VERSION 5.8 ;
BUSBITCHARS "[]" ;
DIVIDERCHAR "/" ;
UNITS
    DATABASE MICRONS 1000 ;
END UNITS

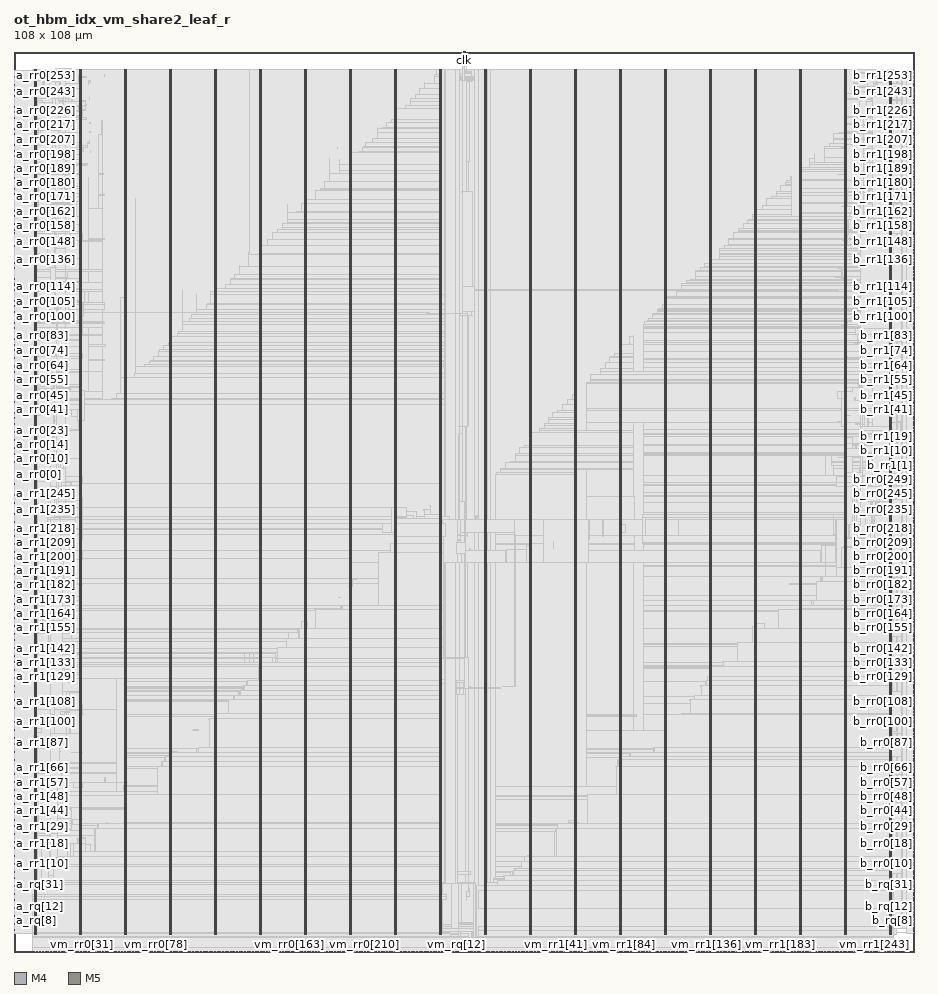
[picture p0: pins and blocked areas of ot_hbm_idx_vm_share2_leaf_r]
MACRO ot_hbm_idx_vm_share2_leaf_r
  FOREIGN ot_hbm_idx_vm_share2_leaf_r 0 0 ;
  CLASS BLOCK ;
  SIZE 108 BY 108 ;
  PIN a_rq[0]
    DIRECTION INPUT ;
    USE SIGNAL ;
    PORT
      LAYER M4 ;
        RECT  0 2.256 0.084 2.28 ;
    END
  END a_rq[0]
  PIN a_rq[10]
    DIRECTION INPUT ;
    USE SIGNAL ;
    PORT
      LAYER M4 ;
        RECT  0 4.128 0.084 4.152 ;
    END
  END a_rq[10]
  PIN a_rq[11]
    DIRECTION INPUT ;
    USE SIGNAL ;
    PORT
      LAYER M4 ;
        RECT  0 4.32 0.084 4.344 ;
    END
  END a_rq[11]
  PIN a_rq[12]
    DIRECTION INPUT ;
    USE SIGNAL ;
    PORT
      LAYER M4 ;
        RECT  0 4.512 0.084 4.536 ;
    END
  END a_rq[12]
  PIN a_rq[13]
    DIRECTION INPUT ;
    USE SIGNAL ;
    PORT
      LAYER M4 ;
        RECT  0 4.704 0.084 4.728 ;
    END
  END a_rq[13]
  PIN a_rq[14]
    DIRECTION INPUT ;
    USE SIGNAL ;
    PORT
      LAYER M4 ;
        RECT  0 4.896 0.084 4.92 ;
    END
  END a_rq[14]
  PIN a_rq[15]
    DIRECTION INPUT ;
    USE SIGNAL ;
    PORT
      LAYER M4 ;
        RECT  0 5.088 0.084 5.112 ;
    END
  END a_rq[15]
  PIN a_rq[16]
    DIRECTION INPUT ;
    USE SIGNAL ;
    PORT
      LAYER M4 ;
        RECT  0 5.28 0.084 5.304 ;
    END
  END a_rq[16]
  PIN a_rq[17]
    DIRECTION INPUT ;
    USE SIGNAL ;
    PORT
      LAYER M4 ;
        RECT  0 5.472 0.084 5.496 ;
    END
  END a_rq[17]
  PIN a_rq[18]
    DIRECTION INPUT ;
    USE SIGNAL ;
    PORT
      LAYER M4 ;
        RECT  0 5.664 0.084 5.688 ;
    END
  END a_rq[18]
  PIN a_rq[19]
    DIRECTION INPUT ;
    USE SIGNAL ;
    PORT
      LAYER M4 ;
        RECT  0 5.856 0.084 5.88 ;
    END
  END a_rq[19]
  PIN a_rq[1]
    DIRECTION INPUT ;
    USE SIGNAL ;
    PORT
      LAYER M4 ;
        RECT  0 2.448 0.084 2.472 ;
    END
  END a_rq[1]
  PIN a_rq[20]
    DIRECTION INPUT ;
    USE SIGNAL ;
    PORT
      LAYER M4 ;
        RECT  0 6.048 0.084 6.072 ;
    END
  END a_rq[20]
  PIN a_rq[21]
    DIRECTION INPUT ;
    USE SIGNAL ;
    PORT
      LAYER M4 ;
        RECT  0 6.24 0.084 6.264 ;
    END
  END a_rq[21]
  PIN a_rq[22]
    DIRECTION INPUT ;
    USE SIGNAL ;
    PORT
      LAYER M4 ;
        RECT  0 6.384 0.084 6.408 ;
    END
  END a_rq[22]
  PIN a_rq[23]
    DIRECTION INPUT ;
    USE SIGNAL ;
    PORT
      LAYER M4 ;
        RECT  0 6.576 0.084 6.6 ;
    END
  END a_rq[23]
  PIN a_rq[24]
    DIRECTION INPUT ;
    USE SIGNAL ;
    PORT
      LAYER M4 ;
        RECT  0 6.768 0.084 6.792 ;
    END
  END a_rq[24]
  PIN a_rq[25]
    DIRECTION INPUT ;
    USE SIGNAL ;
    PORT
      LAYER M4 ;
        RECT  0 6.96 0.084 6.984 ;
    END
  END a_rq[25]
  PIN a_rq[26]
    DIRECTION INPUT ;
    USE SIGNAL ;
    PORT
      LAYER M4 ;
        RECT  0 7.152 0.084 7.176 ;
    END
  END a_rq[26]
  PIN a_rq[27]
    DIRECTION INPUT ;
    USE SIGNAL ;
    PORT
      LAYER M4 ;
        RECT  0 7.344 0.084 7.368 ;
    END
  END a_rq[27]
  PIN a_rq[28]
    DIRECTION INPUT ;
    USE SIGNAL ;
    PORT
      LAYER M4 ;
        RECT  0 7.536 0.084 7.56 ;
    END
  END a_rq[28]
  PIN a_rq[29]
    DIRECTION INPUT ;
    USE SIGNAL ;
    PORT
      LAYER M4 ;
        RECT  0 7.728 0.084 7.752 ;
    END
  END a_rq[29]
  PIN a_rq[2]
    DIRECTION INPUT ;
    USE SIGNAL ;
    PORT
      LAYER M4 ;
        RECT  0 2.64 0.084 2.664 ;
    END
  END a_rq[2]
  PIN a_rq[30]
    DIRECTION INPUT ;
    USE SIGNAL ;
    PORT
      LAYER M4 ;
        RECT  0 7.92 0.084 7.944 ;
    END
  END a_rq[30]
  PIN a_rq[31]
    DIRECTION INPUT ;
    USE SIGNAL ;
    PORT
      LAYER M4 ;
        RECT  0 8.112 0.084 8.136 ;
    END
  END a_rq[31]
  PIN a_rq[32]
    DIRECTION INPUT ;
    USE SIGNAL ;
    PORT
      LAYER M4 ;
        RECT  0 8.304 0.084 8.328 ;
    END
  END a_rq[32]
  PIN a_rq[33]
    DIRECTION INPUT ;
    USE SIGNAL ;
    PORT
      LAYER M4 ;
        RECT  0 8.496 0.084 8.52 ;
    END
  END a_rq[33]
  PIN a_rq[3]
    DIRECTION INPUT ;
    USE SIGNAL ;
    PORT
      LAYER M4 ;
        RECT  0 2.832 0.084 2.856 ;
    END
  END a_rq[3]
  PIN a_rq[4]
    DIRECTION INPUT ;
    USE SIGNAL ;
    PORT
      LAYER M4 ;
        RECT  0 2.976 0.084 3 ;
    END
  END a_rq[4]
  PIN a_rq[5]
    DIRECTION INPUT ;
    USE SIGNAL ;
    PORT
      LAYER M4 ;
        RECT  0 3.168 0.084 3.192 ;
    END
  END a_rq[5]
  PIN a_rq[6]
    DIRECTION INPUT ;
    USE SIGNAL ;
    PORT
      LAYER M4 ;
        RECT  0 3.36 0.084 3.384 ;
    END
  END a_rq[6]
  PIN a_rq[7]
    DIRECTION INPUT ;
    USE SIGNAL ;
    PORT
      LAYER M4 ;
        RECT  0 3.552 0.084 3.576 ;
    END
  END a_rq[7]
  PIN a_rq[8]
    DIRECTION INPUT ;
    USE SIGNAL ;
    PORT
      LAYER M4 ;
        RECT  0 3.744 0.084 3.768 ;
    END
  END a_rq[8]
  PIN a_rq[9]
    DIRECTION INPUT ;
    USE SIGNAL ;
    PORT
      LAYER M4 ;
        RECT  0 3.936 0.084 3.96 ;
    END
  END a_rq[9]
  PIN a_rr0[0]
    DIRECTION OUTPUT ;
    USE SIGNAL ;
    PORT
      LAYER M4 ;
        RECT  0 57.264 0.084 57.288 ;
    END
  END a_rr0[0]
  PIN a_rr0[100]
    DIRECTION OUTPUT ;
    USE SIGNAL ;
    PORT
      LAYER M4 ;
        RECT  0 76.224 0.084 76.248 ;
    END
  END a_rr0[100]
  PIN a_rr0[101]
    DIRECTION OUTPUT ;
    USE SIGNAL ;
    PORT
      LAYER M4 ;
        RECT  0 76.416 0.084 76.44 ;
    END
  END a_rr0[101]
  PIN a_rr0[102]
    DIRECTION OUTPUT ;
    USE SIGNAL ;
    PORT
      LAYER M4 ;
        RECT  0 76.608 0.084 76.632 ;
    END
  END a_rr0[102]
  PIN a_rr0[103]
    DIRECTION OUTPUT ;
    USE SIGNAL ;
    PORT
      LAYER M4 ;
        RECT  0 76.8 0.084 76.824 ;
    END
  END a_rr0[103]
  PIN a_rr0[104]
    DIRECTION OUTPUT ;
    USE SIGNAL ;
    PORT
      LAYER M4 ;
        RECT  0 76.944 0.084 76.968 ;
    END
  END a_rr0[104]
  PIN a_rr0[105]
    DIRECTION OUTPUT ;
    USE SIGNAL ;
    PORT
      LAYER M4 ;
        RECT  0 77.136 0.084 77.16 ;
    END
  END a_rr0[105]
  PIN a_rr0[106]
    DIRECTION OUTPUT ;
    USE SIGNAL ;
    PORT
      LAYER M4 ;
        RECT  0 77.328 0.084 77.352 ;
    END
  END a_rr0[106]
  PIN a_rr0[107]
    DIRECTION OUTPUT ;
    USE SIGNAL ;
    PORT
      LAYER M4 ;
        RECT  0 77.52 0.084 77.544 ;
    END
  END a_rr0[107]
  PIN a_rr0[108]
    DIRECTION OUTPUT ;
    USE SIGNAL ;
    PORT
      LAYER M4 ;
        RECT  0 77.712 0.084 77.736 ;
    END
  END a_rr0[108]
  PIN a_rr0[109]
    DIRECTION OUTPUT ;
    USE SIGNAL ;
    PORT
      LAYER M4 ;
        RECT  0 77.904 0.084 77.928 ;
    END
  END a_rr0[109]
  PIN a_rr0[10]
    DIRECTION OUTPUT ;
    USE SIGNAL ;
    PORT
      LAYER M4 ;
        RECT  0 59.184 0.084 59.208 ;
    END
  END a_rr0[10]
  PIN a_rr0[110]
    DIRECTION OUTPUT ;
    USE SIGNAL ;
    PORT
      LAYER M4 ;
        RECT  0 78.096 0.084 78.12 ;
    END
  END a_rr0[110]
  PIN a_rr0[111]
    DIRECTION OUTPUT ;
    USE SIGNAL ;
    PORT
      LAYER M4 ;
        RECT  0 78.288 0.084 78.312 ;
    END
  END a_rr0[111]
  PIN a_rr0[112]
    DIRECTION OUTPUT ;
    USE SIGNAL ;
    PORT
      LAYER M4 ;
        RECT  0 78.48 0.084 78.504 ;
    END
  END a_rr0[112]
  PIN a_rr0[113]
    DIRECTION OUTPUT ;
    USE SIGNAL ;
    PORT
      LAYER M4 ;
        RECT  0 78.672 0.084 78.696 ;
    END
  END a_rr0[113]
  PIN a_rr0[114]
    DIRECTION OUTPUT ;
    USE SIGNAL ;
    PORT
      LAYER M4 ;
        RECT  0 78.864 0.084 78.888 ;
    END
  END a_rr0[114]
  PIN a_rr0[115]
    DIRECTION OUTPUT ;
    USE SIGNAL ;
    PORT
      LAYER M4 ;
        RECT  0 79.056 0.084 79.08 ;
    END
  END a_rr0[115]
  PIN a_rr0[116]
    DIRECTION OUTPUT ;
    USE SIGNAL ;
    PORT
      LAYER M4 ;
        RECT  0 79.248 0.084 79.272 ;
    END
  END a_rr0[116]
  PIN a_rr0[117]
    DIRECTION OUTPUT ;
    USE SIGNAL ;
    PORT
      LAYER M4 ;
        RECT  0 79.44 0.084 79.464 ;
    END
  END a_rr0[117]
  PIN a_rr0[118]
    DIRECTION OUTPUT ;
    USE SIGNAL ;
    PORT
      LAYER M4 ;
        RECT  0 79.632 0.084 79.656 ;
    END
  END a_rr0[118]
  PIN a_rr0[119]
    DIRECTION OUTPUT ;
    USE SIGNAL ;
    PORT
      LAYER M4 ;
        RECT  0 79.824 0.084 79.848 ;
    END
  END a_rr0[119]
  PIN a_rr0[11]
    DIRECTION OUTPUT ;
    USE SIGNAL ;
    PORT
      LAYER M4 ;
        RECT  0 59.376 0.084 59.4 ;
    END
  END a_rr0[11]
  PIN a_rr0[120]
    DIRECTION OUTPUT ;
    USE SIGNAL ;
    PORT
      LAYER M4 ;
        RECT  0 80.016 0.084 80.04 ;
    END
  END a_rr0[120]
  PIN a_rr0[121]
    DIRECTION OUTPUT ;
    USE SIGNAL ;
    PORT
      LAYER M4 ;
        RECT  0 80.16 0.084 80.184 ;
    END
  END a_rr0[121]
  PIN a_rr0[122]
    DIRECTION OUTPUT ;
    USE SIGNAL ;
    PORT
      LAYER M4 ;
        RECT  0 80.352 0.084 80.376 ;
    END
  END a_rr0[122]
  PIN a_rr0[123]
    DIRECTION OUTPUT ;
    USE SIGNAL ;
    PORT
      LAYER M4 ;
        RECT  0 80.544 0.084 80.568 ;
    END
  END a_rr0[123]
  PIN a_rr0[124]
    DIRECTION OUTPUT ;
    USE SIGNAL ;
    PORT
      LAYER M4 ;
        RECT  0 80.736 0.084 80.76 ;
    END
  END a_rr0[124]
  PIN a_rr0[125]
    DIRECTION OUTPUT ;
    USE SIGNAL ;
    PORT
      LAYER M4 ;
        RECT  0 80.928 0.084 80.952 ;
    END
  END a_rr0[125]
  PIN a_rr0[126]
    DIRECTION OUTPUT ;
    USE SIGNAL ;
    PORT
      LAYER M4 ;
        RECT  0 81.12 0.084 81.144 ;
    END
  END a_rr0[126]
  PIN a_rr0[127]
    DIRECTION OUTPUT ;
    USE SIGNAL ;
    PORT
      LAYER M4 ;
        RECT  0 81.312 0.084 81.336 ;
    END
  END a_rr0[127]
  PIN a_rr0[128]
    DIRECTION OUTPUT ;
    USE SIGNAL ;
    PORT
      LAYER M4 ;
        RECT  0 81.504 0.084 81.528 ;
    END
  END a_rr0[128]
  PIN a_rr0[129]
    DIRECTION OUTPUT ;
    USE SIGNAL ;
    PORT
      LAYER M4 ;
        RECT  0 81.696 0.084 81.72 ;
    END
  END a_rr0[129]
  PIN a_rr0[12]
    DIRECTION OUTPUT ;
    USE SIGNAL ;
    PORT
      LAYER M4 ;
        RECT  0 59.568 0.084 59.592 ;
    END
  END a_rr0[12]
  PIN a_rr0[130]
    DIRECTION OUTPUT ;
    USE SIGNAL ;
    PORT
      LAYER M4 ;
        RECT  0 81.888 0.084 81.912 ;
    END
  END a_rr0[130]
  PIN a_rr0[131]
    DIRECTION OUTPUT ;
    USE SIGNAL ;
    PORT
      LAYER M4 ;
        RECT  0 82.08 0.084 82.104 ;
    END
  END a_rr0[131]
  PIN a_rr0[132]
    DIRECTION OUTPUT ;
    USE SIGNAL ;
    PORT
      LAYER M4 ;
        RECT  0 82.272 0.084 82.296 ;
    END
  END a_rr0[132]
  PIN a_rr0[133]
    DIRECTION OUTPUT ;
    USE SIGNAL ;
    PORT
      LAYER M4 ;
        RECT  0 82.464 0.084 82.488 ;
    END
  END a_rr0[133]
  PIN a_rr0[134]
    DIRECTION OUTPUT ;
    USE SIGNAL ;
    PORT
      LAYER M4 ;
        RECT  0 82.656 0.084 82.68 ;
    END
  END a_rr0[134]
  PIN a_rr0[135]
    DIRECTION OUTPUT ;
    USE SIGNAL ;
    PORT
      LAYER M4 ;
        RECT  0 82.848 0.084 82.872 ;
    END
  END a_rr0[135]
  PIN a_rr0[136]
    DIRECTION OUTPUT ;
    USE SIGNAL ;
    PORT
      LAYER M4 ;
        RECT  0 83.04 0.084 83.064 ;
    END
  END a_rr0[136]
  PIN a_rr0[137]
    DIRECTION OUTPUT ;
    USE SIGNAL ;
    PORT
      LAYER M4 ;
        RECT  0 83.232 0.084 83.256 ;
    END
  END a_rr0[137]
  PIN a_rr0[138]
    DIRECTION OUTPUT ;
    USE SIGNAL ;
    PORT
      LAYER M4 ;
        RECT  0 83.424 0.084 83.448 ;
    END
  END a_rr0[138]
  PIN a_rr0[139]
    DIRECTION OUTPUT ;
    USE SIGNAL ;
    PORT
      LAYER M4 ;
        RECT  0 83.568 0.084 83.592 ;
    END
  END a_rr0[139]
  PIN a_rr0[13]
    DIRECTION OUTPUT ;
    USE SIGNAL ;
    PORT
      LAYER M4 ;
        RECT  0 59.76 0.084 59.784 ;
    END
  END a_rr0[13]
  PIN a_rr0[140]
    DIRECTION OUTPUT ;
    USE SIGNAL ;
    PORT
      LAYER M4 ;
        RECT  0 83.76 0.084 83.784 ;
    END
  END a_rr0[140]
  PIN a_rr0[141]
    DIRECTION OUTPUT ;
    USE SIGNAL ;
    PORT
      LAYER M4 ;
        RECT  0 83.952 0.084 83.976 ;
    END
  END a_rr0[141]
  PIN a_rr0[142]
    DIRECTION OUTPUT ;
    USE SIGNAL ;
    PORT
      LAYER M4 ;
        RECT  0 84.144 0.084 84.168 ;
    END
  END a_rr0[142]
  PIN a_rr0[143]
    DIRECTION OUTPUT ;
    USE SIGNAL ;
    PORT
      LAYER M4 ;
        RECT  0 84.336 0.084 84.36 ;
    END
  END a_rr0[143]
  PIN a_rr0[144]
    DIRECTION OUTPUT ;
    USE SIGNAL ;
    PORT
      LAYER M4 ;
        RECT  0 84.528 0.084 84.552 ;
    END
  END a_rr0[144]
  PIN a_rr0[145]
    DIRECTION OUTPUT ;
    USE SIGNAL ;
    PORT
      LAYER M4 ;
        RECT  0 84.72 0.084 84.744 ;
    END
  END a_rr0[145]
  PIN a_rr0[146]
    DIRECTION OUTPUT ;
    USE SIGNAL ;
    PORT
      LAYER M4 ;
        RECT  0 84.912 0.084 84.936 ;
    END
  END a_rr0[146]
  PIN a_rr0[147]
    DIRECTION OUTPUT ;
    USE SIGNAL ;
    PORT
      LAYER M4 ;
        RECT  0 85.104 0.084 85.128 ;
    END
  END a_rr0[147]
  PIN a_rr0[148]
    DIRECTION OUTPUT ;
    USE SIGNAL ;
    PORT
      LAYER M4 ;
        RECT  0 85.296 0.084 85.32 ;
    END
  END a_rr0[148]
  PIN a_rr0[149]
    DIRECTION OUTPUT ;
    USE SIGNAL ;
    PORT
      LAYER M4 ;
        RECT  0 85.488 0.084 85.512 ;
    END
  END a_rr0[149]
  PIN a_rr0[14]
    DIRECTION OUTPUT ;
    USE SIGNAL ;
    PORT
      LAYER M4 ;
        RECT  0 59.952 0.084 59.976 ;
    END
  END a_rr0[14]
  PIN a_rr0[150]
    DIRECTION OUTPUT ;
    USE SIGNAL ;
    PORT
      LAYER M4 ;
        RECT  0 85.68 0.084 85.704 ;
    END
  END a_rr0[150]
  PIN a_rr0[151]
    DIRECTION OUTPUT ;
    USE SIGNAL ;
    PORT
      LAYER M4 ;
        RECT  0 85.872 0.084 85.896 ;
    END
  END a_rr0[151]
  PIN a_rr0[152]
    DIRECTION OUTPUT ;
    USE SIGNAL ;
    PORT
      LAYER M4 ;
        RECT  0 86.064 0.084 86.088 ;
    END
  END a_rr0[152]
  PIN a_rr0[153]
    DIRECTION OUTPUT ;
    USE SIGNAL ;
    PORT
      LAYER M4 ;
        RECT  0 86.256 0.084 86.28 ;
    END
  END a_rr0[153]
  PIN a_rr0[154]
    DIRECTION OUTPUT ;
    USE SIGNAL ;
    PORT
      LAYER M4 ;
        RECT  0 86.448 0.084 86.472 ;
    END
  END a_rr0[154]
  PIN a_rr0[155]
    DIRECTION OUTPUT ;
    USE SIGNAL ;
    PORT
      LAYER M4 ;
        RECT  0 86.64 0.084 86.664 ;
    END
  END a_rr0[155]
  PIN a_rr0[156]
    DIRECTION OUTPUT ;
    USE SIGNAL ;
    PORT
      LAYER M4 ;
        RECT  0 86.784 0.084 86.808 ;
    END
  END a_rr0[156]
  PIN a_rr0[157]
    DIRECTION OUTPUT ;
    USE SIGNAL ;
    PORT
      LAYER M4 ;
        RECT  0 86.976 0.084 87 ;
    END
  END a_rr0[157]
  PIN a_rr0[158]
    DIRECTION OUTPUT ;
    USE SIGNAL ;
    PORT
      LAYER M4 ;
        RECT  0 87.168 0.084 87.192 ;
    END
  END a_rr0[158]
  PIN a_rr0[159]
    DIRECTION OUTPUT ;
    USE SIGNAL ;
    PORT
      LAYER M4 ;
        RECT  0 87.36 0.084 87.384 ;
    END
  END a_rr0[159]
  PIN a_rr0[15]
    DIRECTION OUTPUT ;
    USE SIGNAL ;
    PORT
      LAYER M4 ;
        RECT  0 60.144 0.084 60.168 ;
    END
  END a_rr0[15]
  PIN a_rr0[160]
    DIRECTION OUTPUT ;
    USE SIGNAL ;
    PORT
      LAYER M4 ;
        RECT  0 87.552 0.084 87.576 ;
    END
  END a_rr0[160]
  PIN a_rr0[161]
    DIRECTION OUTPUT ;
    USE SIGNAL ;
    PORT
      LAYER M4 ;
        RECT  0 87.744 0.084 87.768 ;
    END
  END a_rr0[161]
  PIN a_rr0[162]
    DIRECTION OUTPUT ;
    USE SIGNAL ;
    PORT
      LAYER M4 ;
        RECT  0 87.936 0.084 87.96 ;
    END
  END a_rr0[162]
  PIN a_rr0[163]
    DIRECTION OUTPUT ;
    USE SIGNAL ;
    PORT
      LAYER M4 ;
        RECT  0 88.128 0.084 88.152 ;
    END
  END a_rr0[163]
  PIN a_rr0[164]
    DIRECTION OUTPUT ;
    USE SIGNAL ;
    PORT
      LAYER M4 ;
        RECT  0 88.32 0.084 88.344 ;
    END
  END a_rr0[164]
  PIN a_rr0[165]
    DIRECTION OUTPUT ;
    USE SIGNAL ;
    PORT
      LAYER M4 ;
        RECT  0 88.512 0.084 88.536 ;
    END
  END a_rr0[165]
  PIN a_rr0[166]
    DIRECTION OUTPUT ;
    USE SIGNAL ;
    PORT
      LAYER M4 ;
        RECT  0 88.704 0.084 88.728 ;
    END
  END a_rr0[166]
  PIN a_rr0[167]
    DIRECTION OUTPUT ;
    USE SIGNAL ;
    PORT
      LAYER M4 ;
        RECT  0 88.896 0.084 88.92 ;
    END
  END a_rr0[167]
  PIN a_rr0[168]
    DIRECTION OUTPUT ;
    USE SIGNAL ;
    PORT
      LAYER M4 ;
        RECT  0 89.088 0.084 89.112 ;
    END
  END a_rr0[168]
  PIN a_rr0[169]
    DIRECTION OUTPUT ;
    USE SIGNAL ;
    PORT
      LAYER M4 ;
        RECT  0 89.28 0.084 89.304 ;
    END
  END a_rr0[169]
  PIN a_rr0[16]
    DIRECTION OUTPUT ;
    USE SIGNAL ;
    PORT
      LAYER M4 ;
        RECT  0 60.288 0.084 60.312 ;
    END
  END a_rr0[16]
  PIN a_rr0[170]
    DIRECTION OUTPUT ;
    USE SIGNAL ;
    PORT
      LAYER M4 ;
        RECT  0 89.472 0.084 89.496 ;
    END
  END a_rr0[170]
  PIN a_rr0[171]
    DIRECTION OUTPUT ;
    USE SIGNAL ;
    PORT
      LAYER M4 ;
        RECT  0 89.664 0.084 89.688 ;
    END
  END a_rr0[171]
  PIN a_rr0[172]
    DIRECTION OUTPUT ;
    USE SIGNAL ;
    PORT
      LAYER M4 ;
        RECT  0 89.856 0.084 89.88 ;
    END
  END a_rr0[172]
  PIN a_rr0[173]
    DIRECTION OUTPUT ;
    USE SIGNAL ;
    PORT
      LAYER M4 ;
        RECT  0 90.048 0.084 90.072 ;
    END
  END a_rr0[173]
  PIN a_rr0[174]
    DIRECTION OUTPUT ;
    USE SIGNAL ;
    PORT
      LAYER M4 ;
        RECT  0 90.192 0.084 90.216 ;
    END
  END a_rr0[174]
  PIN a_rr0[175]
    DIRECTION OUTPUT ;
    USE SIGNAL ;
    PORT
      LAYER M4 ;
        RECT  0 90.384 0.084 90.408 ;
    END
  END a_rr0[175]
  PIN a_rr0[176]
    DIRECTION OUTPUT ;
    USE SIGNAL ;
    PORT
      LAYER M4 ;
        RECT  0 90.576 0.084 90.6 ;
    END
  END a_rr0[176]
  PIN a_rr0[177]
    DIRECTION OUTPUT ;
    USE SIGNAL ;
    PORT
      LAYER M4 ;
        RECT  0 90.768 0.084 90.792 ;
    END
  END a_rr0[177]
  PIN a_rr0[178]
    DIRECTION OUTPUT ;
    USE SIGNAL ;
    PORT
      LAYER M4 ;
        RECT  0 90.96 0.084 90.984 ;
    END
  END a_rr0[178]
  PIN a_rr0[179]
    DIRECTION OUTPUT ;
    USE SIGNAL ;
    PORT
      LAYER M4 ;
        RECT  0 91.152 0.084 91.176 ;
    END
  END a_rr0[179]
  PIN a_rr0[17]
    DIRECTION OUTPUT ;
    USE SIGNAL ;
    PORT
      LAYER M4 ;
        RECT  0 60.48 0.084 60.504 ;
    END
  END a_rr0[17]
  PIN a_rr0[180]
    DIRECTION OUTPUT ;
    USE SIGNAL ;
    PORT
      LAYER M4 ;
        RECT  0 91.344 0.084 91.368 ;
    END
  END a_rr0[180]
  PIN a_rr0[181]
    DIRECTION OUTPUT ;
    USE SIGNAL ;
    PORT
      LAYER M4 ;
        RECT  0 91.536 0.084 91.56 ;
    END
  END a_rr0[181]
  PIN a_rr0[182]
    DIRECTION OUTPUT ;
    USE SIGNAL ;
    PORT
      LAYER M4 ;
        RECT  0 91.728 0.084 91.752 ;
    END
  END a_rr0[182]
  PIN a_rr0[183]
    DIRECTION OUTPUT ;
    USE SIGNAL ;
    PORT
      LAYER M4 ;
        RECT  0 91.92 0.084 91.944 ;
    END
  END a_rr0[183]
  PIN a_rr0[184]
    DIRECTION OUTPUT ;
    USE SIGNAL ;
    PORT
      LAYER M4 ;
        RECT  0 92.112 0.084 92.136 ;
    END
  END a_rr0[184]
  PIN a_rr0[185]
    DIRECTION OUTPUT ;
    USE SIGNAL ;
    PORT
      LAYER M4 ;
        RECT  0 92.304 0.084 92.328 ;
    END
  END a_rr0[185]
  PIN a_rr0[186]
    DIRECTION OUTPUT ;
    USE SIGNAL ;
    PORT
      LAYER M4 ;
        RECT  0 92.496 0.084 92.52 ;
    END
  END a_rr0[186]
  PIN a_rr0[187]
    DIRECTION OUTPUT ;
    USE SIGNAL ;
    PORT
      LAYER M4 ;
        RECT  0 92.688 0.084 92.712 ;
    END
  END a_rr0[187]
  PIN a_rr0[188]
    DIRECTION OUTPUT ;
    USE SIGNAL ;
    PORT
      LAYER M4 ;
        RECT  0 92.88 0.084 92.904 ;
    END
  END a_rr0[188]
  PIN a_rr0[189]
    DIRECTION OUTPUT ;
    USE SIGNAL ;
    PORT
      LAYER M4 ;
        RECT  0 93.072 0.084 93.096 ;
    END
  END a_rr0[189]
  PIN a_rr0[18]
    DIRECTION OUTPUT ;
    USE SIGNAL ;
    PORT
      LAYER M4 ;
        RECT  0 60.672 0.084 60.696 ;
    END
  END a_rr0[18]
  PIN a_rr0[190]
    DIRECTION OUTPUT ;
    USE SIGNAL ;
    PORT
      LAYER M4 ;
        RECT  0 93.264 0.084 93.288 ;
    END
  END a_rr0[190]
  PIN a_rr0[191]
    DIRECTION OUTPUT ;
    USE SIGNAL ;
    PORT
      LAYER M4 ;
        RECT  0 93.408 0.084 93.432 ;
    END
  END a_rr0[191]
  PIN a_rr0[192]
    DIRECTION OUTPUT ;
    USE SIGNAL ;
    PORT
      LAYER M4 ;
        RECT  0 93.6 0.084 93.624 ;
    END
  END a_rr0[192]
  PIN a_rr0[193]
    DIRECTION OUTPUT ;
    USE SIGNAL ;
    PORT
      LAYER M4 ;
        RECT  0 93.792 0.084 93.816 ;
    END
  END a_rr0[193]
  PIN a_rr0[194]
    DIRECTION OUTPUT ;
    USE SIGNAL ;
    PORT
      LAYER M4 ;
        RECT  0 93.984 0.084 94.008 ;
    END
  END a_rr0[194]
  PIN a_rr0[195]
    DIRECTION OUTPUT ;
    USE SIGNAL ;
    PORT
      LAYER M4 ;
        RECT  0 94.176 0.084 94.2 ;
    END
  END a_rr0[195]
  PIN a_rr0[196]
    DIRECTION OUTPUT ;
    USE SIGNAL ;
    PORT
      LAYER M4 ;
        RECT  0 94.368 0.084 94.392 ;
    END
  END a_rr0[196]
  PIN a_rr0[197]
    DIRECTION OUTPUT ;
    USE SIGNAL ;
    PORT
      LAYER M4 ;
        RECT  0 94.56 0.084 94.584 ;
    END
  END a_rr0[197]
  PIN a_rr0[198]
    DIRECTION OUTPUT ;
    USE SIGNAL ;
    PORT
      LAYER M4 ;
        RECT  0 94.752 0.084 94.776 ;
    END
  END a_rr0[198]
  PIN a_rr0[199]
    DIRECTION OUTPUT ;
    USE SIGNAL ;
    PORT
      LAYER M4 ;
        RECT  0 94.944 0.084 94.968 ;
    END
  END a_rr0[199]
  PIN a_rr0[19]
    DIRECTION OUTPUT ;
    USE SIGNAL ;
    PORT
      LAYER M4 ;
        RECT  0 60.864 0.084 60.888 ;
    END
  END a_rr0[19]
  PIN a_rr0[1]
    DIRECTION OUTPUT ;
    USE SIGNAL ;
    PORT
      LAYER M4 ;
        RECT  0 57.456 0.084 57.48 ;
    END
  END a_rr0[1]
  PIN a_rr0[200]
    DIRECTION OUTPUT ;
    USE SIGNAL ;
    PORT
      LAYER M4 ;
        RECT  0 95.136 0.084 95.16 ;
    END
  END a_rr0[200]
  PIN a_rr0[201]
    DIRECTION OUTPUT ;
    USE SIGNAL ;
    PORT
      LAYER M4 ;
        RECT  0 95.328 0.084 95.352 ;
    END
  END a_rr0[201]
  PIN a_rr0[202]
    DIRECTION OUTPUT ;
    USE SIGNAL ;
    PORT
      LAYER M4 ;
        RECT  0 95.52 0.084 95.544 ;
    END
  END a_rr0[202]
  PIN a_rr0[203]
    DIRECTION OUTPUT ;
    USE SIGNAL ;
    PORT
      LAYER M4 ;
        RECT  0 95.712 0.084 95.736 ;
    END
  END a_rr0[203]
  PIN a_rr0[204]
    DIRECTION OUTPUT ;
    USE SIGNAL ;
    PORT
      LAYER M4 ;
        RECT  0 95.904 0.084 95.928 ;
    END
  END a_rr0[204]
  PIN a_rr0[205]
    DIRECTION OUTPUT ;
    USE SIGNAL ;
    PORT
      LAYER M4 ;
        RECT  0 96.096 0.084 96.12 ;
    END
  END a_rr0[205]
  PIN a_rr0[206]
    DIRECTION OUTPUT ;
    USE SIGNAL ;
    PORT
      LAYER M4 ;
        RECT  0 96.288 0.084 96.312 ;
    END
  END a_rr0[206]
  PIN a_rr0[207]
    DIRECTION OUTPUT ;
    USE SIGNAL ;
    PORT
      LAYER M4 ;
        RECT  0 96.48 0.084 96.504 ;
    END
  END a_rr0[207]
  PIN a_rr0[208]
    DIRECTION OUTPUT ;
    USE SIGNAL ;
    PORT
      LAYER M4 ;
        RECT  0 96.672 0.084 96.696 ;
    END
  END a_rr0[208]
  PIN a_rr0[209]
    DIRECTION OUTPUT ;
    USE SIGNAL ;
    PORT
      LAYER M4 ;
        RECT  0 96.816 0.084 96.84 ;
    END
  END a_rr0[209]
  PIN a_rr0[20]
    DIRECTION OUTPUT ;
    USE SIGNAL ;
    PORT
      LAYER M4 ;
        RECT  0 61.056 0.084 61.08 ;
    END
  END a_rr0[20]
  PIN a_rr0[210]
    DIRECTION OUTPUT ;
    USE SIGNAL ;
    PORT
      LAYER M4 ;
        RECT  0 97.008 0.084 97.032 ;
    END
  END a_rr0[210]
  PIN a_rr0[211]
    DIRECTION OUTPUT ;
    USE SIGNAL ;
    PORT
      LAYER M4 ;
        RECT  0 97.2 0.084 97.224 ;
    END
  END a_rr0[211]
  PIN a_rr0[212]
    DIRECTION OUTPUT ;
    USE SIGNAL ;
    PORT
      LAYER M4 ;
        RECT  0 97.392 0.084 97.416 ;
    END
  END a_rr0[212]
  PIN a_rr0[213]
    DIRECTION OUTPUT ;
    USE SIGNAL ;
    PORT
      LAYER M4 ;
        RECT  0 97.584 0.084 97.608 ;
    END
  END a_rr0[213]
  PIN a_rr0[214]
    DIRECTION OUTPUT ;
    USE SIGNAL ;
    PORT
      LAYER M4 ;
        RECT  0 97.776 0.084 97.8 ;
    END
  END a_rr0[214]
  PIN a_rr0[215]
    DIRECTION OUTPUT ;
    USE SIGNAL ;
    PORT
      LAYER M4 ;
        RECT  0 97.968 0.084 97.992 ;
    END
  END a_rr0[215]
  PIN a_rr0[216]
    DIRECTION OUTPUT ;
    USE SIGNAL ;
    PORT
      LAYER M4 ;
        RECT  0 98.16 0.084 98.184 ;
    END
  END a_rr0[216]
  PIN a_rr0[217]
    DIRECTION OUTPUT ;
    USE SIGNAL ;
    PORT
      LAYER M4 ;
        RECT  0 98.352 0.084 98.376 ;
    END
  END a_rr0[217]
  PIN a_rr0[218]
    DIRECTION OUTPUT ;
    USE SIGNAL ;
    PORT
      LAYER M4 ;
        RECT  0 98.544 0.084 98.568 ;
    END
  END a_rr0[218]
  PIN a_rr0[219]
    DIRECTION OUTPUT ;
    USE SIGNAL ;
    PORT
      LAYER M4 ;
        RECT  0 98.736 0.084 98.76 ;
    END
  END a_rr0[219]
  PIN a_rr0[21]
    DIRECTION OUTPUT ;
    USE SIGNAL ;
    PORT
      LAYER M4 ;
        RECT  0 61.248 0.084 61.272 ;
    END
  END a_rr0[21]
  PIN a_rr0[220]
    DIRECTION OUTPUT ;
    USE SIGNAL ;
    PORT
      LAYER M4 ;
        RECT  0 98.928 0.084 98.952 ;
    END
  END a_rr0[220]
  PIN a_rr0[221]
    DIRECTION OUTPUT ;
    USE SIGNAL ;
    PORT
      LAYER M4 ;
        RECT  0 99.12 0.084 99.144 ;
    END
  END a_rr0[221]
  PIN a_rr0[222]
    DIRECTION OUTPUT ;
    USE SIGNAL ;
    PORT
      LAYER M4 ;
        RECT  0 99.312 0.084 99.336 ;
    END
  END a_rr0[222]
  PIN a_rr0[223]
    DIRECTION OUTPUT ;
    USE SIGNAL ;
    PORT
      LAYER M4 ;
        RECT  0 99.504 0.084 99.528 ;
    END
  END a_rr0[223]
  PIN a_rr0[224]
    DIRECTION OUTPUT ;
    USE SIGNAL ;
    PORT
      LAYER M4 ;
        RECT  0 99.696 0.084 99.72 ;
    END
  END a_rr0[224]
  PIN a_rr0[225]
    DIRECTION OUTPUT ;
    USE SIGNAL ;
    PORT
      LAYER M4 ;
        RECT  0 99.888 0.084 99.912 ;
    END
  END a_rr0[225]
  PIN a_rr0[226]
    DIRECTION OUTPUT ;
    USE SIGNAL ;
    PORT
      LAYER M4 ;
        RECT  0 100.08 0.084 100.104 ;
    END
  END a_rr0[226]
  PIN a_rr0[227]
    DIRECTION OUTPUT ;
    USE SIGNAL ;
    PORT
      LAYER M4 ;
        RECT  0 100.224 0.084 100.248 ;
    END
  END a_rr0[227]
  PIN a_rr0[228]
    DIRECTION OUTPUT ;
    USE SIGNAL ;
    PORT
      LAYER M4 ;
        RECT  0 100.416 0.084 100.44 ;
    END
  END a_rr0[228]
  PIN a_rr0[229]
    DIRECTION OUTPUT ;
    USE SIGNAL ;
    PORT
      LAYER M4 ;
        RECT  0 100.608 0.084 100.632 ;
    END
  END a_rr0[229]
  PIN a_rr0[22]
    DIRECTION OUTPUT ;
    USE SIGNAL ;
    PORT
      LAYER M4 ;
        RECT  0 61.44 0.084 61.464 ;
    END
  END a_rr0[22]
  PIN a_rr0[230]
    DIRECTION OUTPUT ;
    USE SIGNAL ;
    PORT
      LAYER M4 ;
        RECT  0 100.8 0.084 100.824 ;
    END
  END a_rr0[230]
  PIN a_rr0[231]
    DIRECTION OUTPUT ;
    USE SIGNAL ;
    PORT
      LAYER M4 ;
        RECT  0 100.992 0.084 101.016 ;
    END
  END a_rr0[231]
  PIN a_rr0[232]
    DIRECTION OUTPUT ;
    USE SIGNAL ;
    PORT
      LAYER M4 ;
        RECT  0 101.184 0.084 101.208 ;
    END
  END a_rr0[232]
  PIN a_rr0[233]
    DIRECTION OUTPUT ;
    USE SIGNAL ;
    PORT
      LAYER M4 ;
        RECT  0 101.376 0.084 101.4 ;
    END
  END a_rr0[233]
  PIN a_rr0[234]
    DIRECTION OUTPUT ;
    USE SIGNAL ;
    PORT
      LAYER M4 ;
        RECT  0 101.568 0.084 101.592 ;
    END
  END a_rr0[234]
  PIN a_rr0[235]
    DIRECTION OUTPUT ;
    USE SIGNAL ;
    PORT
      LAYER M4 ;
        RECT  0 101.76 0.084 101.784 ;
    END
  END a_rr0[235]
  PIN a_rr0[236]
    DIRECTION OUTPUT ;
    USE SIGNAL ;
    PORT
      LAYER M4 ;
        RECT  0 101.952 0.084 101.976 ;
    END
  END a_rr0[236]
  PIN a_rr0[237]
    DIRECTION OUTPUT ;
    USE SIGNAL ;
    PORT
      LAYER M4 ;
        RECT  0 102.144 0.084 102.168 ;
    END
  END a_rr0[237]
  PIN a_rr0[238]
    DIRECTION OUTPUT ;
    USE SIGNAL ;
    PORT
      LAYER M4 ;
        RECT  0 102.336 0.084 102.36 ;
    END
  END a_rr0[238]
  PIN a_rr0[239]
    DIRECTION OUTPUT ;
    USE SIGNAL ;
    PORT
      LAYER M4 ;
        RECT  0 102.528 0.084 102.552 ;
    END
  END a_rr0[239]
  PIN a_rr0[23]
    DIRECTION OUTPUT ;
    USE SIGNAL ;
    PORT
      LAYER M4 ;
        RECT  0 61.632 0.084 61.656 ;
    END
  END a_rr0[23]
  PIN a_rr0[240]
    DIRECTION OUTPUT ;
    USE SIGNAL ;
    PORT
      LAYER M4 ;
        RECT  0 102.72 0.084 102.744 ;
    END
  END a_rr0[240]
  PIN a_rr0[241]
    DIRECTION OUTPUT ;
    USE SIGNAL ;
    PORT
      LAYER M4 ;
        RECT  0 102.912 0.084 102.936 ;
    END
  END a_rr0[241]
  PIN a_rr0[242]
    DIRECTION OUTPUT ;
    USE SIGNAL ;
    PORT
      LAYER M4 ;
        RECT  0 103.104 0.084 103.128 ;
    END
  END a_rr0[242]
  PIN a_rr0[243]
    DIRECTION OUTPUT ;
    USE SIGNAL ;
    PORT
      LAYER M4 ;
        RECT  0 103.296 0.084 103.32 ;
    END
  END a_rr0[243]
  PIN a_rr0[244]
    DIRECTION OUTPUT ;
    USE SIGNAL ;
    PORT
      LAYER M4 ;
        RECT  0 103.44 0.084 103.464 ;
    END
  END a_rr0[244]
  PIN a_rr0[245]
    DIRECTION OUTPUT ;
    USE SIGNAL ;
    PORT
      LAYER M4 ;
        RECT  0 103.632 0.084 103.656 ;
    END
  END a_rr0[245]
  PIN a_rr0[246]
    DIRECTION OUTPUT ;
    USE SIGNAL ;
    PORT
      LAYER M4 ;
        RECT  0 103.824 0.084 103.848 ;
    END
  END a_rr0[246]
  PIN a_rr0[247]
    DIRECTION OUTPUT ;
    USE SIGNAL ;
    PORT
      LAYER M4 ;
        RECT  0 104.016 0.084 104.04 ;
    END
  END a_rr0[247]
  PIN a_rr0[248]
    DIRECTION OUTPUT ;
    USE SIGNAL ;
    PORT
      LAYER M4 ;
        RECT  0 104.208 0.084 104.232 ;
    END
  END a_rr0[248]
  PIN a_rr0[249]
    DIRECTION OUTPUT ;
    USE SIGNAL ;
    PORT
      LAYER M4 ;
        RECT  0 104.4 0.084 104.424 ;
    END
  END a_rr0[249]
  PIN a_rr0[24]
    DIRECTION OUTPUT ;
    USE SIGNAL ;
    PORT
      LAYER M4 ;
        RECT  0 61.824 0.084 61.848 ;
    END
  END a_rr0[24]
  PIN a_rr0[250]
    DIRECTION OUTPUT ;
    USE SIGNAL ;
    PORT
      LAYER M4 ;
        RECT  0 104.592 0.084 104.616 ;
    END
  END a_rr0[250]
  PIN a_rr0[251]
    DIRECTION OUTPUT ;
    USE SIGNAL ;
    PORT
      LAYER M4 ;
        RECT  0 104.784 0.084 104.808 ;
    END
  END a_rr0[251]
  PIN a_rr0[252]
    DIRECTION OUTPUT ;
    USE SIGNAL ;
    PORT
      LAYER M4 ;
        RECT  0 104.976 0.084 105 ;
    END
  END a_rr0[252]
  PIN a_rr0[253]
    DIRECTION OUTPUT ;
    USE SIGNAL ;
    PORT
      LAYER M4 ;
        RECT  0 105.168 0.084 105.192 ;
    END
  END a_rr0[253]
  PIN a_rr0[254]
    DIRECTION OUTPUT ;
    USE SIGNAL ;
    PORT
      LAYER M4 ;
        RECT  0 105.36 0.084 105.384 ;
    END
  END a_rr0[254]
  PIN a_rr0[255]
    DIRECTION OUTPUT ;
    USE SIGNAL ;
    PORT
      LAYER M4 ;
        RECT  0 105.552 0.084 105.576 ;
    END
  END a_rr0[255]
  PIN a_rr0[256]
    DIRECTION OUTPUT ;
    USE SIGNAL ;
    PORT
      LAYER M4 ;
        RECT  0 105.744 0.084 105.768 ;
    END
  END a_rr0[256]
  PIN a_rr0[25]
    DIRECTION OUTPUT ;
    USE SIGNAL ;
    PORT
      LAYER M4 ;
        RECT  0 62.016 0.084 62.04 ;
    END
  END a_rr0[25]
  PIN a_rr0[26]
    DIRECTION OUTPUT ;
    USE SIGNAL ;
    PORT
      LAYER M4 ;
        RECT  0 62.208 0.084 62.232 ;
    END
  END a_rr0[26]
  PIN a_rr0[27]
    DIRECTION OUTPUT ;
    USE SIGNAL ;
    PORT
      LAYER M4 ;
        RECT  0 62.4 0.084 62.424 ;
    END
  END a_rr0[27]
  PIN a_rr0[28]
    DIRECTION OUTPUT ;
    USE SIGNAL ;
    PORT
      LAYER M4 ;
        RECT  0 62.592 0.084 62.616 ;
    END
  END a_rr0[28]
  PIN a_rr0[29]
    DIRECTION OUTPUT ;
    USE SIGNAL ;
    PORT
      LAYER M4 ;
        RECT  0 62.784 0.084 62.808 ;
    END
  END a_rr0[29]
  PIN a_rr0[2]
    DIRECTION OUTPUT ;
    USE SIGNAL ;
    PORT
      LAYER M4 ;
        RECT  0 57.648 0.084 57.672 ;
    END
  END a_rr0[2]
  PIN a_rr0[30]
    DIRECTION OUTPUT ;
    USE SIGNAL ;
    PORT
      LAYER M4 ;
        RECT  0 62.976 0.084 63 ;
    END
  END a_rr0[30]
  PIN a_rr0[31]
    DIRECTION OUTPUT ;
    USE SIGNAL ;
    PORT
      LAYER M4 ;
        RECT  0 63.168 0.084 63.192 ;
    END
  END a_rr0[31]
  PIN a_rr0[32]
    DIRECTION OUTPUT ;
    USE SIGNAL ;
    PORT
      LAYER M4 ;
        RECT  0 63.36 0.084 63.384 ;
    END
  END a_rr0[32]
  PIN a_rr0[33]
    DIRECTION OUTPUT ;
    USE SIGNAL ;
    PORT
      LAYER M4 ;
        RECT  0 63.552 0.084 63.576 ;
    END
  END a_rr0[33]
  PIN a_rr0[34]
    DIRECTION OUTPUT ;
    USE SIGNAL ;
    PORT
      LAYER M4 ;
        RECT  0 63.696 0.084 63.72 ;
    END
  END a_rr0[34]
  PIN a_rr0[35]
    DIRECTION OUTPUT ;
    USE SIGNAL ;
    PORT
      LAYER M4 ;
        RECT  0 63.888 0.084 63.912 ;
    END
  END a_rr0[35]
  PIN a_rr0[36]
    DIRECTION OUTPUT ;
    USE SIGNAL ;
    PORT
      LAYER M4 ;
        RECT  0 64.08 0.084 64.104 ;
    END
  END a_rr0[36]
  PIN a_rr0[37]
    DIRECTION OUTPUT ;
    USE SIGNAL ;
    PORT
      LAYER M4 ;
        RECT  0 64.272 0.084 64.296 ;
    END
  END a_rr0[37]
  PIN a_rr0[38]
    DIRECTION OUTPUT ;
    USE SIGNAL ;
    PORT
      LAYER M4 ;
        RECT  0 64.464 0.084 64.488 ;
    END
  END a_rr0[38]
  PIN a_rr0[39]
    DIRECTION OUTPUT ;
    USE SIGNAL ;
    PORT
      LAYER M4 ;
        RECT  0 64.656 0.084 64.68 ;
    END
  END a_rr0[39]
  PIN a_rr0[3]
    DIRECTION OUTPUT ;
    USE SIGNAL ;
    PORT
      LAYER M4 ;
        RECT  0 57.84 0.084 57.864 ;
    END
  END a_rr0[3]
  PIN a_rr0[40]
    DIRECTION OUTPUT ;
    USE SIGNAL ;
    PORT
      LAYER M4 ;
        RECT  0 64.848 0.084 64.872 ;
    END
  END a_rr0[40]
  PIN a_rr0[41]
    DIRECTION OUTPUT ;
    USE SIGNAL ;
    PORT
      LAYER M4 ;
        RECT  0 65.04 0.084 65.064 ;
    END
  END a_rr0[41]
  PIN a_rr0[42]
    DIRECTION OUTPUT ;
    USE SIGNAL ;
    PORT
      LAYER M4 ;
        RECT  0 65.232 0.084 65.256 ;
    END
  END a_rr0[42]
  PIN a_rr0[43]
    DIRECTION OUTPUT ;
    USE SIGNAL ;
    PORT
      LAYER M4 ;
        RECT  0 65.424 0.084 65.448 ;
    END
  END a_rr0[43]
  PIN a_rr0[44]
    DIRECTION OUTPUT ;
    USE SIGNAL ;
    PORT
      LAYER M4 ;
        RECT  0 65.616 0.084 65.64 ;
    END
  END a_rr0[44]
  PIN a_rr0[45]
    DIRECTION OUTPUT ;
    USE SIGNAL ;
    PORT
      LAYER M4 ;
        RECT  0 65.808 0.084 65.832 ;
    END
  END a_rr0[45]
  PIN a_rr0[46]
    DIRECTION OUTPUT ;
    USE SIGNAL ;
    PORT
      LAYER M4 ;
        RECT  0 66 0.084 66.024 ;
    END
  END a_rr0[46]
  PIN a_rr0[47]
    DIRECTION OUTPUT ;
    USE SIGNAL ;
    PORT
      LAYER M4 ;
        RECT  0 66.192 0.084 66.216 ;
    END
  END a_rr0[47]
  PIN a_rr0[48]
    DIRECTION OUTPUT ;
    USE SIGNAL ;
    PORT
      LAYER M4 ;
        RECT  0 66.384 0.084 66.408 ;
    END
  END a_rr0[48]
  PIN a_rr0[49]
    DIRECTION OUTPUT ;
    USE SIGNAL ;
    PORT
      LAYER M4 ;
        RECT  0 66.576 0.084 66.6 ;
    END
  END a_rr0[49]
  PIN a_rr0[4]
    DIRECTION OUTPUT ;
    USE SIGNAL ;
    PORT
      LAYER M4 ;
        RECT  0 58.032 0.084 58.056 ;
    END
  END a_rr0[4]
  PIN a_rr0[50]
    DIRECTION OUTPUT ;
    USE SIGNAL ;
    PORT
      LAYER M4 ;
        RECT  0 66.768 0.084 66.792 ;
    END
  END a_rr0[50]
  PIN a_rr0[51]
    DIRECTION OUTPUT ;
    USE SIGNAL ;
    PORT
      LAYER M4 ;
        RECT  0 66.912 0.084 66.936 ;
    END
  END a_rr0[51]
  PIN a_rr0[52]
    DIRECTION OUTPUT ;
    USE SIGNAL ;
    PORT
      LAYER M4 ;
        RECT  0 67.104 0.084 67.128 ;
    END
  END a_rr0[52]
  PIN a_rr0[53]
    DIRECTION OUTPUT ;
    USE SIGNAL ;
    PORT
      LAYER M4 ;
        RECT  0 67.296 0.084 67.32 ;
    END
  END a_rr0[53]
  PIN a_rr0[54]
    DIRECTION OUTPUT ;
    USE SIGNAL ;
    PORT
      LAYER M4 ;
        RECT  0 67.488 0.084 67.512 ;
    END
  END a_rr0[54]
  PIN a_rr0[55]
    DIRECTION OUTPUT ;
    USE SIGNAL ;
    PORT
      LAYER M4 ;
        RECT  0 67.68 0.084 67.704 ;
    END
  END a_rr0[55]
  PIN a_rr0[56]
    DIRECTION OUTPUT ;
    USE SIGNAL ;
    PORT
      LAYER M4 ;
        RECT  0 67.872 0.084 67.896 ;
    END
  END a_rr0[56]
  PIN a_rr0[57]
    DIRECTION OUTPUT ;
    USE SIGNAL ;
    PORT
      LAYER M4 ;
        RECT  0 68.064 0.084 68.088 ;
    END
  END a_rr0[57]
  PIN a_rr0[58]
    DIRECTION OUTPUT ;
    USE SIGNAL ;
    PORT
      LAYER M4 ;
        RECT  0 68.256 0.084 68.28 ;
    END
  END a_rr0[58]
  PIN a_rr0[59]
    DIRECTION OUTPUT ;
    USE SIGNAL ;
    PORT
      LAYER M4 ;
        RECT  0 68.448 0.084 68.472 ;
    END
  END a_rr0[59]
  PIN a_rr0[5]
    DIRECTION OUTPUT ;
    USE SIGNAL ;
    PORT
      LAYER M4 ;
        RECT  0 58.224 0.084 58.248 ;
    END
  END a_rr0[5]
  PIN a_rr0[60]
    DIRECTION OUTPUT ;
    USE SIGNAL ;
    PORT
      LAYER M4 ;
        RECT  0 68.64 0.084 68.664 ;
    END
  END a_rr0[60]
  PIN a_rr0[61]
    DIRECTION OUTPUT ;
    USE SIGNAL ;
    PORT
      LAYER M4 ;
        RECT  0 68.832 0.084 68.856 ;
    END
  END a_rr0[61]
  PIN a_rr0[62]
    DIRECTION OUTPUT ;
    USE SIGNAL ;
    PORT
      LAYER M4 ;
        RECT  0 69.024 0.084 69.048 ;
    END
  END a_rr0[62]
  PIN a_rr0[63]
    DIRECTION OUTPUT ;
    USE SIGNAL ;
    PORT
      LAYER M4 ;
        RECT  0 69.216 0.084 69.24 ;
    END
  END a_rr0[63]
  PIN a_rr0[64]
    DIRECTION OUTPUT ;
    USE SIGNAL ;
    PORT
      LAYER M4 ;
        RECT  0 69.408 0.084 69.432 ;
    END
  END a_rr0[64]
  PIN a_rr0[65]
    DIRECTION OUTPUT ;
    USE SIGNAL ;
    PORT
      LAYER M4 ;
        RECT  0 69.6 0.084 69.624 ;
    END
  END a_rr0[65]
  PIN a_rr0[66]
    DIRECTION OUTPUT ;
    USE SIGNAL ;
    PORT
      LAYER M4 ;
        RECT  0 69.792 0.084 69.816 ;
    END
  END a_rr0[66]
  PIN a_rr0[67]
    DIRECTION OUTPUT ;
    USE SIGNAL ;
    PORT
      LAYER M4 ;
        RECT  0 69.984 0.084 70.008 ;
    END
  END a_rr0[67]
  PIN a_rr0[68]
    DIRECTION OUTPUT ;
    USE SIGNAL ;
    PORT
      LAYER M4 ;
        RECT  0 70.176 0.084 70.2 ;
    END
  END a_rr0[68]
  PIN a_rr0[69]
    DIRECTION OUTPUT ;
    USE SIGNAL ;
    PORT
      LAYER M4 ;
        RECT  0 70.32 0.084 70.344 ;
    END
  END a_rr0[69]
  PIN a_rr0[6]
    DIRECTION OUTPUT ;
    USE SIGNAL ;
    PORT
      LAYER M4 ;
        RECT  0 58.416 0.084 58.44 ;
    END
  END a_rr0[6]
  PIN a_rr0[70]
    DIRECTION OUTPUT ;
    USE SIGNAL ;
    PORT
      LAYER M4 ;
        RECT  0 70.512 0.084 70.536 ;
    END
  END a_rr0[70]
  PIN a_rr0[71]
    DIRECTION OUTPUT ;
    USE SIGNAL ;
    PORT
      LAYER M4 ;
        RECT  0 70.704 0.084 70.728 ;
    END
  END a_rr0[71]
  PIN a_rr0[72]
    DIRECTION OUTPUT ;
    USE SIGNAL ;
    PORT
      LAYER M4 ;
        RECT  0 70.896 0.084 70.92 ;
    END
  END a_rr0[72]
  PIN a_rr0[73]
    DIRECTION OUTPUT ;
    USE SIGNAL ;
    PORT
      LAYER M4 ;
        RECT  0 71.088 0.084 71.112 ;
    END
  END a_rr0[73]
  PIN a_rr0[74]
    DIRECTION OUTPUT ;
    USE SIGNAL ;
    PORT
      LAYER M4 ;
        RECT  0 71.28 0.084 71.304 ;
    END
  END a_rr0[74]
  PIN a_rr0[75]
    DIRECTION OUTPUT ;
    USE SIGNAL ;
    PORT
      LAYER M4 ;
        RECT  0 71.472 0.084 71.496 ;
    END
  END a_rr0[75]
  PIN a_rr0[76]
    DIRECTION OUTPUT ;
    USE SIGNAL ;
    PORT
      LAYER M4 ;
        RECT  0 71.664 0.084 71.688 ;
    END
  END a_rr0[76]
  PIN a_rr0[77]
    DIRECTION OUTPUT ;
    USE SIGNAL ;
    PORT
      LAYER M4 ;
        RECT  0 71.856 0.084 71.88 ;
    END
  END a_rr0[77]
  PIN a_rr0[78]
    DIRECTION OUTPUT ;
    USE SIGNAL ;
    PORT
      LAYER M4 ;
        RECT  0 72.048 0.084 72.072 ;
    END
  END a_rr0[78]
  PIN a_rr0[79]
    DIRECTION OUTPUT ;
    USE SIGNAL ;
    PORT
      LAYER M4 ;
        RECT  0 72.24 0.084 72.264 ;
    END
  END a_rr0[79]
  PIN a_rr0[7]
    DIRECTION OUTPUT ;
    USE SIGNAL ;
    PORT
      LAYER M4 ;
        RECT  0 58.608 0.084 58.632 ;
    END
  END a_rr0[7]
  PIN a_rr0[80]
    DIRECTION OUTPUT ;
    USE SIGNAL ;
    PORT
      LAYER M4 ;
        RECT  0 72.432 0.084 72.456 ;
    END
  END a_rr0[80]
  PIN a_rr0[81]
    DIRECTION OUTPUT ;
    USE SIGNAL ;
    PORT
      LAYER M4 ;
        RECT  0 72.624 0.084 72.648 ;
    END
  END a_rr0[81]
  PIN a_rr0[82]
    DIRECTION OUTPUT ;
    USE SIGNAL ;
    PORT
      LAYER M4 ;
        RECT  0 72.816 0.084 72.84 ;
    END
  END a_rr0[82]
  PIN a_rr0[83]
    DIRECTION OUTPUT ;
    USE SIGNAL ;
    PORT
      LAYER M4 ;
        RECT  0 73.008 0.084 73.032 ;
    END
  END a_rr0[83]
  PIN a_rr0[84]
    DIRECTION OUTPUT ;
    USE SIGNAL ;
    PORT
      LAYER M4 ;
        RECT  0 73.2 0.084 73.224 ;
    END
  END a_rr0[84]
  PIN a_rr0[85]
    DIRECTION OUTPUT ;
    USE SIGNAL ;
    PORT
      LAYER M4 ;
        RECT  0 73.392 0.084 73.416 ;
    END
  END a_rr0[85]
  PIN a_rr0[86]
    DIRECTION OUTPUT ;
    USE SIGNAL ;
    PORT
      LAYER M4 ;
        RECT  0 73.536 0.084 73.56 ;
    END
  END a_rr0[86]
  PIN a_rr0[87]
    DIRECTION OUTPUT ;
    USE SIGNAL ;
    PORT
      LAYER M4 ;
        RECT  0 73.728 0.084 73.752 ;
    END
  END a_rr0[87]
  PIN a_rr0[88]
    DIRECTION OUTPUT ;
    USE SIGNAL ;
    PORT
      LAYER M4 ;
        RECT  0 73.92 0.084 73.944 ;
    END
  END a_rr0[88]
  PIN a_rr0[89]
    DIRECTION OUTPUT ;
    USE SIGNAL ;
    PORT
      LAYER M4 ;
        RECT  0 74.112 0.084 74.136 ;
    END
  END a_rr0[89]
  PIN a_rr0[8]
    DIRECTION OUTPUT ;
    USE SIGNAL ;
    PORT
      LAYER M4 ;
        RECT  0 58.8 0.084 58.824 ;
    END
  END a_rr0[8]
  PIN a_rr0[90]
    DIRECTION OUTPUT ;
    USE SIGNAL ;
    PORT
      LAYER M4 ;
        RECT  0 74.304 0.084 74.328 ;
    END
  END a_rr0[90]
  PIN a_rr0[91]
    DIRECTION OUTPUT ;
    USE SIGNAL ;
    PORT
      LAYER M4 ;
        RECT  0 74.496 0.084 74.52 ;
    END
  END a_rr0[91]
  PIN a_rr0[92]
    DIRECTION OUTPUT ;
    USE SIGNAL ;
    PORT
      LAYER M4 ;
        RECT  0 74.688 0.084 74.712 ;
    END
  END a_rr0[92]
  PIN a_rr0[93]
    DIRECTION OUTPUT ;
    USE SIGNAL ;
    PORT
      LAYER M4 ;
        RECT  0 74.88 0.084 74.904 ;
    END
  END a_rr0[93]
  PIN a_rr0[94]
    DIRECTION OUTPUT ;
    USE SIGNAL ;
    PORT
      LAYER M4 ;
        RECT  0 75.072 0.084 75.096 ;
    END
  END a_rr0[94]
  PIN a_rr0[95]
    DIRECTION OUTPUT ;
    USE SIGNAL ;
    PORT
      LAYER M4 ;
        RECT  0 75.264 0.084 75.288 ;
    END
  END a_rr0[95]
  PIN a_rr0[96]
    DIRECTION OUTPUT ;
    USE SIGNAL ;
    PORT
      LAYER M4 ;
        RECT  0 75.456 0.084 75.48 ;
    END
  END a_rr0[96]
  PIN a_rr0[97]
    DIRECTION OUTPUT ;
    USE SIGNAL ;
    PORT
      LAYER M4 ;
        RECT  0 75.648 0.084 75.672 ;
    END
  END a_rr0[97]
  PIN a_rr0[98]
    DIRECTION OUTPUT ;
    USE SIGNAL ;
    PORT
      LAYER M4 ;
        RECT  0 75.84 0.084 75.864 ;
    END
  END a_rr0[98]
  PIN a_rr0[99]
    DIRECTION OUTPUT ;
    USE SIGNAL ;
    PORT
      LAYER M4 ;
        RECT  0 76.032 0.084 76.056 ;
    END
  END a_rr0[99]
  PIN a_rr0[9]
    DIRECTION OUTPUT ;
    USE SIGNAL ;
    PORT
      LAYER M4 ;
        RECT  0 58.992 0.084 59.016 ;
    END
  END a_rr0[9]
  PIN a_rr1[0]
    DIRECTION OUTPUT ;
    USE SIGNAL ;
    PORT
      LAYER M4 ;
        RECT  0 8.688 0.084 8.712 ;
    END
  END a_rr1[0]
  PIN a_rr1[100]
    DIRECTION OUTPUT ;
    USE SIGNAL ;
    PORT
      LAYER M4 ;
        RECT  0 27.6 0.084 27.624 ;
    END
  END a_rr1[100]
  PIN a_rr1[101]
    DIRECTION OUTPUT ;
    USE SIGNAL ;
    PORT
      LAYER M4 ;
        RECT  0 27.792 0.084 27.816 ;
    END
  END a_rr1[101]
  PIN a_rr1[102]
    DIRECTION OUTPUT ;
    USE SIGNAL ;
    PORT
      LAYER M4 ;
        RECT  0 27.984 0.084 28.008 ;
    END
  END a_rr1[102]
  PIN a_rr1[103]
    DIRECTION OUTPUT ;
    USE SIGNAL ;
    PORT
      LAYER M4 ;
        RECT  0 28.176 0.084 28.2 ;
    END
  END a_rr1[103]
  PIN a_rr1[104]
    DIRECTION OUTPUT ;
    USE SIGNAL ;
    PORT
      LAYER M4 ;
        RECT  0 28.368 0.084 28.392 ;
    END
  END a_rr1[104]
  PIN a_rr1[105]
    DIRECTION OUTPUT ;
    USE SIGNAL ;
    PORT
      LAYER M4 ;
        RECT  0 28.512 0.084 28.536 ;
    END
  END a_rr1[105]
  PIN a_rr1[106]
    DIRECTION OUTPUT ;
    USE SIGNAL ;
    PORT
      LAYER M4 ;
        RECT  0 28.704 0.084 28.728 ;
    END
  END a_rr1[106]
  PIN a_rr1[107]
    DIRECTION OUTPUT ;
    USE SIGNAL ;
    PORT
      LAYER M4 ;
        RECT  0 28.896 0.084 28.92 ;
    END
  END a_rr1[107]
  PIN a_rr1[108]
    DIRECTION OUTPUT ;
    USE SIGNAL ;
    PORT
      LAYER M4 ;
        RECT  0 29.088 0.084 29.112 ;
    END
  END a_rr1[108]
  PIN a_rr1[109]
    DIRECTION OUTPUT ;
    USE SIGNAL ;
    PORT
      LAYER M4 ;
        RECT  0 29.28 0.084 29.304 ;
    END
  END a_rr1[109]
  PIN a_rr1[10]
    DIRECTION OUTPUT ;
    USE SIGNAL ;
    PORT
      LAYER M4 ;
        RECT  0 10.56 0.084 10.584 ;
    END
  END a_rr1[10]
  PIN a_rr1[110]
    DIRECTION OUTPUT ;
    USE SIGNAL ;
    PORT
      LAYER M4 ;
        RECT  0 29.472 0.084 29.496 ;
    END
  END a_rr1[110]
  PIN a_rr1[111]
    DIRECTION OUTPUT ;
    USE SIGNAL ;
    PORT
      LAYER M4 ;
        RECT  0 29.664 0.084 29.688 ;
    END
  END a_rr1[111]
  PIN a_rr1[112]
    DIRECTION OUTPUT ;
    USE SIGNAL ;
    PORT
      LAYER M4 ;
        RECT  0 29.856 0.084 29.88 ;
    END
  END a_rr1[112]
  PIN a_rr1[113]
    DIRECTION OUTPUT ;
    USE SIGNAL ;
    PORT
      LAYER M4 ;
        RECT  0 30.048 0.084 30.072 ;
    END
  END a_rr1[113]
  PIN a_rr1[114]
    DIRECTION OUTPUT ;
    USE SIGNAL ;
    PORT
      LAYER M4 ;
        RECT  0 30.24 0.084 30.264 ;
    END
  END a_rr1[114]
  PIN a_rr1[115]
    DIRECTION OUTPUT ;
    USE SIGNAL ;
    PORT
      LAYER M4 ;
        RECT  0 30.432 0.084 30.456 ;
    END
  END a_rr1[115]
  PIN a_rr1[116]
    DIRECTION OUTPUT ;
    USE SIGNAL ;
    PORT
      LAYER M4 ;
        RECT  0 30.624 0.084 30.648 ;
    END
  END a_rr1[116]
  PIN a_rr1[117]
    DIRECTION OUTPUT ;
    USE SIGNAL ;
    PORT
      LAYER M4 ;
        RECT  0 30.816 0.084 30.84 ;
    END
  END a_rr1[117]
  PIN a_rr1[118]
    DIRECTION OUTPUT ;
    USE SIGNAL ;
    PORT
      LAYER M4 ;
        RECT  0 31.008 0.084 31.032 ;
    END
  END a_rr1[118]
  PIN a_rr1[119]
    DIRECTION OUTPUT ;
    USE SIGNAL ;
    PORT
      LAYER M4 ;
        RECT  0 31.2 0.084 31.224 ;
    END
  END a_rr1[119]
  PIN a_rr1[11]
    DIRECTION OUTPUT ;
    USE SIGNAL ;
    PORT
      LAYER M4 ;
        RECT  0 10.752 0.084 10.776 ;
    END
  END a_rr1[11]
  PIN a_rr1[120]
    DIRECTION OUTPUT ;
    USE SIGNAL ;
    PORT
      LAYER M4 ;
        RECT  0 31.392 0.084 31.416 ;
    END
  END a_rr1[120]
  PIN a_rr1[121]
    DIRECTION OUTPUT ;
    USE SIGNAL ;
    PORT
      LAYER M4 ;
        RECT  0 31.584 0.084 31.608 ;
    END
  END a_rr1[121]
  PIN a_rr1[122]
    DIRECTION OUTPUT ;
    USE SIGNAL ;
    PORT
      LAYER M4 ;
        RECT  0 31.728 0.084 31.752 ;
    END
  END a_rr1[122]
  PIN a_rr1[123]
    DIRECTION OUTPUT ;
    USE SIGNAL ;
    PORT
      LAYER M4 ;
        RECT  0 31.92 0.084 31.944 ;
    END
  END a_rr1[123]
  PIN a_rr1[124]
    DIRECTION OUTPUT ;
    USE SIGNAL ;
    PORT
      LAYER M4 ;
        RECT  0 32.112 0.084 32.136 ;
    END
  END a_rr1[124]
  PIN a_rr1[125]
    DIRECTION OUTPUT ;
    USE SIGNAL ;
    PORT
      LAYER M4 ;
        RECT  0 32.304 0.084 32.328 ;
    END
  END a_rr1[125]
  PIN a_rr1[126]
    DIRECTION OUTPUT ;
    USE SIGNAL ;
    PORT
      LAYER M4 ;
        RECT  0 32.496 0.084 32.52 ;
    END
  END a_rr1[126]
  PIN a_rr1[127]
    DIRECTION OUTPUT ;
    USE SIGNAL ;
    PORT
      LAYER M4 ;
        RECT  0 32.688 0.084 32.712 ;
    END
  END a_rr1[127]
  PIN a_rr1[128]
    DIRECTION OUTPUT ;
    USE SIGNAL ;
    PORT
      LAYER M4 ;
        RECT  0 32.88 0.084 32.904 ;
    END
  END a_rr1[128]
  PIN a_rr1[129]
    DIRECTION OUTPUT ;
    USE SIGNAL ;
    PORT
      LAYER M4 ;
        RECT  0 33.072 0.084 33.096 ;
    END
  END a_rr1[129]
  PIN a_rr1[12]
    DIRECTION OUTPUT ;
    USE SIGNAL ;
    PORT
      LAYER M4 ;
        RECT  0 10.944 0.084 10.968 ;
    END
  END a_rr1[12]
  PIN a_rr1[130]
    DIRECTION OUTPUT ;
    USE SIGNAL ;
    PORT
      LAYER M4 ;
        RECT  0 33.264 0.084 33.288 ;
    END
  END a_rr1[130]
  PIN a_rr1[131]
    DIRECTION OUTPUT ;
    USE SIGNAL ;
    PORT
      LAYER M4 ;
        RECT  0 33.456 0.084 33.48 ;
    END
  END a_rr1[131]
  PIN a_rr1[132]
    DIRECTION OUTPUT ;
    USE SIGNAL ;
    PORT
      LAYER M4 ;
        RECT  0 33.648 0.084 33.672 ;
    END
  END a_rr1[132]
  PIN a_rr1[133]
    DIRECTION OUTPUT ;
    USE SIGNAL ;
    PORT
      LAYER M4 ;
        RECT  0 33.84 0.084 33.864 ;
    END
  END a_rr1[133]
  PIN a_rr1[134]
    DIRECTION OUTPUT ;
    USE SIGNAL ;
    PORT
      LAYER M4 ;
        RECT  0 34.032 0.084 34.056 ;
    END
  END a_rr1[134]
  PIN a_rr1[135]
    DIRECTION OUTPUT ;
    USE SIGNAL ;
    PORT
      LAYER M4 ;
        RECT  0 34.224 0.084 34.248 ;
    END
  END a_rr1[135]
  PIN a_rr1[136]
    DIRECTION OUTPUT ;
    USE SIGNAL ;
    PORT
      LAYER M4 ;
        RECT  0 34.416 0.084 34.44 ;
    END
  END a_rr1[136]
  PIN a_rr1[137]
    DIRECTION OUTPUT ;
    USE SIGNAL ;
    PORT
      LAYER M4 ;
        RECT  0 34.608 0.084 34.632 ;
    END
  END a_rr1[137]
  PIN a_rr1[138]
    DIRECTION OUTPUT ;
    USE SIGNAL ;
    PORT
      LAYER M4 ;
        RECT  0 34.8 0.084 34.824 ;
    END
  END a_rr1[138]
  PIN a_rr1[139]
    DIRECTION OUTPUT ;
    USE SIGNAL ;
    PORT
      LAYER M4 ;
        RECT  0 34.944 0.084 34.968 ;
    END
  END a_rr1[139]
  PIN a_rr1[13]
    DIRECTION OUTPUT ;
    USE SIGNAL ;
    PORT
      LAYER M4 ;
        RECT  0 11.136 0.084 11.16 ;
    END
  END a_rr1[13]
  PIN a_rr1[140]
    DIRECTION OUTPUT ;
    USE SIGNAL ;
    PORT
      LAYER M4 ;
        RECT  0 35.136 0.084 35.16 ;
    END
  END a_rr1[140]
  PIN a_rr1[141]
    DIRECTION OUTPUT ;
    USE SIGNAL ;
    PORT
      LAYER M4 ;
        RECT  0 35.328 0.084 35.352 ;
    END
  END a_rr1[141]
  PIN a_rr1[142]
    DIRECTION OUTPUT ;
    USE SIGNAL ;
    PORT
      LAYER M4 ;
        RECT  0 35.52 0.084 35.544 ;
    END
  END a_rr1[142]
  PIN a_rr1[143]
    DIRECTION OUTPUT ;
    USE SIGNAL ;
    PORT
      LAYER M4 ;
        RECT  0 35.712 0.084 35.736 ;
    END
  END a_rr1[143]
  PIN a_rr1[144]
    DIRECTION OUTPUT ;
    USE SIGNAL ;
    PORT
      LAYER M4 ;
        RECT  0 35.904 0.084 35.928 ;
    END
  END a_rr1[144]
  PIN a_rr1[145]
    DIRECTION OUTPUT ;
    USE SIGNAL ;
    PORT
      LAYER M4 ;
        RECT  0 36.096 0.084 36.12 ;
    END
  END a_rr1[145]
  PIN a_rr1[146]
    DIRECTION OUTPUT ;
    USE SIGNAL ;
    PORT
      LAYER M4 ;
        RECT  0 36.288 0.084 36.312 ;
    END
  END a_rr1[146]
  PIN a_rr1[147]
    DIRECTION OUTPUT ;
    USE SIGNAL ;
    PORT
      LAYER M4 ;
        RECT  0 36.48 0.084 36.504 ;
    END
  END a_rr1[147]
  PIN a_rr1[148]
    DIRECTION OUTPUT ;
    USE SIGNAL ;
    PORT
      LAYER M4 ;
        RECT  0 36.672 0.084 36.696 ;
    END
  END a_rr1[148]
  PIN a_rr1[149]
    DIRECTION OUTPUT ;
    USE SIGNAL ;
    PORT
      LAYER M4 ;
        RECT  0 36.864 0.084 36.888 ;
    END
  END a_rr1[149]
  PIN a_rr1[14]
    DIRECTION OUTPUT ;
    USE SIGNAL ;
    PORT
      LAYER M4 ;
        RECT  0 11.328 0.084 11.352 ;
    END
  END a_rr1[14]
  PIN a_rr1[150]
    DIRECTION OUTPUT ;
    USE SIGNAL ;
    PORT
      LAYER M4 ;
        RECT  0 37.056 0.084 37.08 ;
    END
  END a_rr1[150]
  PIN a_rr1[151]
    DIRECTION OUTPUT ;
    USE SIGNAL ;
    PORT
      LAYER M4 ;
        RECT  0 37.248 0.084 37.272 ;
    END
  END a_rr1[151]
  PIN a_rr1[152]
    DIRECTION OUTPUT ;
    USE SIGNAL ;
    PORT
      LAYER M4 ;
        RECT  0 37.44 0.084 37.464 ;
    END
  END a_rr1[152]
  PIN a_rr1[153]
    DIRECTION OUTPUT ;
    USE SIGNAL ;
    PORT
      LAYER M4 ;
        RECT  0 37.632 0.084 37.656 ;
    END
  END a_rr1[153]
  PIN a_rr1[154]
    DIRECTION OUTPUT ;
    USE SIGNAL ;
    PORT
      LAYER M4 ;
        RECT  0 37.824 0.084 37.848 ;
    END
  END a_rr1[154]
  PIN a_rr1[155]
    DIRECTION OUTPUT ;
    USE SIGNAL ;
    PORT
      LAYER M4 ;
        RECT  0 37.968 0.084 37.992 ;
    END
  END a_rr1[155]
  PIN a_rr1[156]
    DIRECTION OUTPUT ;
    USE SIGNAL ;
    PORT
      LAYER M4 ;
        RECT  0 38.16 0.084 38.184 ;
    END
  END a_rr1[156]
  PIN a_rr1[157]
    DIRECTION OUTPUT ;
    USE SIGNAL ;
    PORT
      LAYER M4 ;
        RECT  0 38.352 0.084 38.376 ;
    END
  END a_rr1[157]
  PIN a_rr1[158]
    DIRECTION OUTPUT ;
    USE SIGNAL ;
    PORT
      LAYER M4 ;
        RECT  0 38.544 0.084 38.568 ;
    END
  END a_rr1[158]
  PIN a_rr1[159]
    DIRECTION OUTPUT ;
    USE SIGNAL ;
    PORT
      LAYER M4 ;
        RECT  0 38.736 0.084 38.76 ;
    END
  END a_rr1[159]
  PIN a_rr1[15]
    DIRECTION OUTPUT ;
    USE SIGNAL ;
    PORT
      LAYER M4 ;
        RECT  0 11.52 0.084 11.544 ;
    END
  END a_rr1[15]
  PIN a_rr1[160]
    DIRECTION OUTPUT ;
    USE SIGNAL ;
    PORT
      LAYER M4 ;
        RECT  0 38.928 0.084 38.952 ;
    END
  END a_rr1[160]
  PIN a_rr1[161]
    DIRECTION OUTPUT ;
    USE SIGNAL ;
    PORT
      LAYER M4 ;
        RECT  0 39.12 0.084 39.144 ;
    END
  END a_rr1[161]
  PIN a_rr1[162]
    DIRECTION OUTPUT ;
    USE SIGNAL ;
    PORT
      LAYER M4 ;
        RECT  0 39.312 0.084 39.336 ;
    END
  END a_rr1[162]
  PIN a_rr1[163]
    DIRECTION OUTPUT ;
    USE SIGNAL ;
    PORT
      LAYER M4 ;
        RECT  0 39.504 0.084 39.528 ;
    END
  END a_rr1[163]
  PIN a_rr1[164]
    DIRECTION OUTPUT ;
    USE SIGNAL ;
    PORT
      LAYER M4 ;
        RECT  0 39.696 0.084 39.72 ;
    END
  END a_rr1[164]
  PIN a_rr1[165]
    DIRECTION OUTPUT ;
    USE SIGNAL ;
    PORT
      LAYER M4 ;
        RECT  0 39.888 0.084 39.912 ;
    END
  END a_rr1[165]
  PIN a_rr1[166]
    DIRECTION OUTPUT ;
    USE SIGNAL ;
    PORT
      LAYER M4 ;
        RECT  0 40.08 0.084 40.104 ;
    END
  END a_rr1[166]
  PIN a_rr1[167]
    DIRECTION OUTPUT ;
    USE SIGNAL ;
    PORT
      LAYER M4 ;
        RECT  0 40.272 0.084 40.296 ;
    END
  END a_rr1[167]
  PIN a_rr1[168]
    DIRECTION OUTPUT ;
    USE SIGNAL ;
    PORT
      LAYER M4 ;
        RECT  0 40.464 0.084 40.488 ;
    END
  END a_rr1[168]
  PIN a_rr1[169]
    DIRECTION OUTPUT ;
    USE SIGNAL ;
    PORT
      LAYER M4 ;
        RECT  0 40.656 0.084 40.68 ;
    END
  END a_rr1[169]
  PIN a_rr1[16]
    DIRECTION OUTPUT ;
    USE SIGNAL ;
    PORT
      LAYER M4 ;
        RECT  0 11.712 0.084 11.736 ;
    END
  END a_rr1[16]
  PIN a_rr1[170]
    DIRECTION OUTPUT ;
    USE SIGNAL ;
    PORT
      LAYER M4 ;
        RECT  0 40.848 0.084 40.872 ;
    END
  END a_rr1[170]
  PIN a_rr1[171]
    DIRECTION OUTPUT ;
    USE SIGNAL ;
    PORT
      LAYER M4 ;
        RECT  0 41.04 0.084 41.064 ;
    END
  END a_rr1[171]
  PIN a_rr1[172]
    DIRECTION OUTPUT ;
    USE SIGNAL ;
    PORT
      LAYER M4 ;
        RECT  0 41.184 0.084 41.208 ;
    END
  END a_rr1[172]
  PIN a_rr1[173]
    DIRECTION OUTPUT ;
    USE SIGNAL ;
    PORT
      LAYER M4 ;
        RECT  0 41.376 0.084 41.4 ;
    END
  END a_rr1[173]
  PIN a_rr1[174]
    DIRECTION OUTPUT ;
    USE SIGNAL ;
    PORT
      LAYER M4 ;
        RECT  0 41.568 0.084 41.592 ;
    END
  END a_rr1[174]
  PIN a_rr1[175]
    DIRECTION OUTPUT ;
    USE SIGNAL ;
    PORT
      LAYER M4 ;
        RECT  0 41.76 0.084 41.784 ;
    END
  END a_rr1[175]
  PIN a_rr1[176]
    DIRECTION OUTPUT ;
    USE SIGNAL ;
    PORT
      LAYER M4 ;
        RECT  0 41.952 0.084 41.976 ;
    END
  END a_rr1[176]
  PIN a_rr1[177]
    DIRECTION OUTPUT ;
    USE SIGNAL ;
    PORT
      LAYER M4 ;
        RECT  0 42.144 0.084 42.168 ;
    END
  END a_rr1[177]
  PIN a_rr1[178]
    DIRECTION OUTPUT ;
    USE SIGNAL ;
    PORT
      LAYER M4 ;
        RECT  0 42.336 0.084 42.36 ;
    END
  END a_rr1[178]
  PIN a_rr1[179]
    DIRECTION OUTPUT ;
    USE SIGNAL ;
    PORT
      LAYER M4 ;
        RECT  0 42.528 0.084 42.552 ;
    END
  END a_rr1[179]
  PIN a_rr1[17]
    DIRECTION OUTPUT ;
    USE SIGNAL ;
    PORT
      LAYER M4 ;
        RECT  0 11.904 0.084 11.928 ;
    END
  END a_rr1[17]
  PIN a_rr1[180]
    DIRECTION OUTPUT ;
    USE SIGNAL ;
    PORT
      LAYER M4 ;
        RECT  0 42.72 0.084 42.744 ;
    END
  END a_rr1[180]
  PIN a_rr1[181]
    DIRECTION OUTPUT ;
    USE SIGNAL ;
    PORT
      LAYER M4 ;
        RECT  0 42.912 0.084 42.936 ;
    END
  END a_rr1[181]
  PIN a_rr1[182]
    DIRECTION OUTPUT ;
    USE SIGNAL ;
    PORT
      LAYER M4 ;
        RECT  0 43.104 0.084 43.128 ;
    END
  END a_rr1[182]
  PIN a_rr1[183]
    DIRECTION OUTPUT ;
    USE SIGNAL ;
    PORT
      LAYER M4 ;
        RECT  0 43.296 0.084 43.32 ;
    END
  END a_rr1[183]
  PIN a_rr1[184]
    DIRECTION OUTPUT ;
    USE SIGNAL ;
    PORT
      LAYER M4 ;
        RECT  0 43.488 0.084 43.512 ;
    END
  END a_rr1[184]
  PIN a_rr1[185]
    DIRECTION OUTPUT ;
    USE SIGNAL ;
    PORT
      LAYER M4 ;
        RECT  0 43.68 0.084 43.704 ;
    END
  END a_rr1[185]
  PIN a_rr1[186]
    DIRECTION OUTPUT ;
    USE SIGNAL ;
    PORT
      LAYER M4 ;
        RECT  0 43.872 0.084 43.896 ;
    END
  END a_rr1[186]
  PIN a_rr1[187]
    DIRECTION OUTPUT ;
    USE SIGNAL ;
    PORT
      LAYER M4 ;
        RECT  0 44.064 0.084 44.088 ;
    END
  END a_rr1[187]
  PIN a_rr1[188]
    DIRECTION OUTPUT ;
    USE SIGNAL ;
    PORT
      LAYER M4 ;
        RECT  0 44.256 0.084 44.28 ;
    END
  END a_rr1[188]
  PIN a_rr1[189]
    DIRECTION OUTPUT ;
    USE SIGNAL ;
    PORT
      LAYER M4 ;
        RECT  0 44.4 0.084 44.424 ;
    END
  END a_rr1[189]
  PIN a_rr1[18]
    DIRECTION OUTPUT ;
    USE SIGNAL ;
    PORT
      LAYER M4 ;
        RECT  0 12.096 0.084 12.12 ;
    END
  END a_rr1[18]
  PIN a_rr1[190]
    DIRECTION OUTPUT ;
    USE SIGNAL ;
    PORT
      LAYER M4 ;
        RECT  0 44.592 0.084 44.616 ;
    END
  END a_rr1[190]
  PIN a_rr1[191]
    DIRECTION OUTPUT ;
    USE SIGNAL ;
    PORT
      LAYER M4 ;
        RECT  0 44.784 0.084 44.808 ;
    END
  END a_rr1[191]
  PIN a_rr1[192]
    DIRECTION OUTPUT ;
    USE SIGNAL ;
    PORT
      LAYER M4 ;
        RECT  0 44.976 0.084 45 ;
    END
  END a_rr1[192]
  PIN a_rr1[193]
    DIRECTION OUTPUT ;
    USE SIGNAL ;
    PORT
      LAYER M4 ;
        RECT  0 45.168 0.084 45.192 ;
    END
  END a_rr1[193]
  PIN a_rr1[194]
    DIRECTION OUTPUT ;
    USE SIGNAL ;
    PORT
      LAYER M4 ;
        RECT  0 45.36 0.084 45.384 ;
    END
  END a_rr1[194]
  PIN a_rr1[195]
    DIRECTION OUTPUT ;
    USE SIGNAL ;
    PORT
      LAYER M4 ;
        RECT  0 45.552 0.084 45.576 ;
    END
  END a_rr1[195]
  PIN a_rr1[196]
    DIRECTION OUTPUT ;
    USE SIGNAL ;
    PORT
      LAYER M4 ;
        RECT  0 45.744 0.084 45.768 ;
    END
  END a_rr1[196]
  PIN a_rr1[197]
    DIRECTION OUTPUT ;
    USE SIGNAL ;
    PORT
      LAYER M4 ;
        RECT  0 45.936 0.084 45.96 ;
    END
  END a_rr1[197]
  PIN a_rr1[198]
    DIRECTION OUTPUT ;
    USE SIGNAL ;
    PORT
      LAYER M4 ;
        RECT  0 46.128 0.084 46.152 ;
    END
  END a_rr1[198]
  PIN a_rr1[199]
    DIRECTION OUTPUT ;
    USE SIGNAL ;
    PORT
      LAYER M4 ;
        RECT  0 46.32 0.084 46.344 ;
    END
  END a_rr1[199]
  PIN a_rr1[19]
    DIRECTION OUTPUT ;
    USE SIGNAL ;
    PORT
      LAYER M4 ;
        RECT  0 12.288 0.084 12.312 ;
    END
  END a_rr1[19]
  PIN a_rr1[1]
    DIRECTION OUTPUT ;
    USE SIGNAL ;
    PORT
      LAYER M4 ;
        RECT  0 8.88 0.084 8.904 ;
    END
  END a_rr1[1]
  PIN a_rr1[200]
    DIRECTION OUTPUT ;
    USE SIGNAL ;
    PORT
      LAYER M4 ;
        RECT  0 46.512 0.084 46.536 ;
    END
  END a_rr1[200]
  PIN a_rr1[201]
    DIRECTION OUTPUT ;
    USE SIGNAL ;
    PORT
      LAYER M4 ;
        RECT  0 46.704 0.084 46.728 ;
    END
  END a_rr1[201]
  PIN a_rr1[202]
    DIRECTION OUTPUT ;
    USE SIGNAL ;
    PORT
      LAYER M4 ;
        RECT  0 46.896 0.084 46.92 ;
    END
  END a_rr1[202]
  PIN a_rr1[203]
    DIRECTION OUTPUT ;
    USE SIGNAL ;
    PORT
      LAYER M4 ;
        RECT  0 47.088 0.084 47.112 ;
    END
  END a_rr1[203]
  PIN a_rr1[204]
    DIRECTION OUTPUT ;
    USE SIGNAL ;
    PORT
      LAYER M4 ;
        RECT  0 47.28 0.084 47.304 ;
    END
  END a_rr1[204]
  PIN a_rr1[205]
    DIRECTION OUTPUT ;
    USE SIGNAL ;
    PORT
      LAYER M4 ;
        RECT  0 47.472 0.084 47.496 ;
    END
  END a_rr1[205]
  PIN a_rr1[206]
    DIRECTION OUTPUT ;
    USE SIGNAL ;
    PORT
      LAYER M4 ;
        RECT  0 47.616 0.084 47.64 ;
    END
  END a_rr1[206]
  PIN a_rr1[207]
    DIRECTION OUTPUT ;
    USE SIGNAL ;
    PORT
      LAYER M4 ;
        RECT  0 47.808 0.084 47.832 ;
    END
  END a_rr1[207]
  PIN a_rr1[208]
    DIRECTION OUTPUT ;
    USE SIGNAL ;
    PORT
      LAYER M4 ;
        RECT  0 48 0.084 48.024 ;
    END
  END a_rr1[208]
  PIN a_rr1[209]
    DIRECTION OUTPUT ;
    USE SIGNAL ;
    PORT
      LAYER M4 ;
        RECT  0 48.192 0.084 48.216 ;
    END
  END a_rr1[209]
  PIN a_rr1[20]
    DIRECTION OUTPUT ;
    USE SIGNAL ;
    PORT
      LAYER M4 ;
        RECT  0 12.48 0.084 12.504 ;
    END
  END a_rr1[20]
  PIN a_rr1[210]
    DIRECTION OUTPUT ;
    USE SIGNAL ;
    PORT
      LAYER M4 ;
        RECT  0 48.384 0.084 48.408 ;
    END
  END a_rr1[210]
  PIN a_rr1[211]
    DIRECTION OUTPUT ;
    USE SIGNAL ;
    PORT
      LAYER M4 ;
        RECT  0 48.576 0.084 48.6 ;
    END
  END a_rr1[211]
  PIN a_rr1[212]
    DIRECTION OUTPUT ;
    USE SIGNAL ;
    PORT
      LAYER M4 ;
        RECT  0 48.768 0.084 48.792 ;
    END
  END a_rr1[212]
  PIN a_rr1[213]
    DIRECTION OUTPUT ;
    USE SIGNAL ;
    PORT
      LAYER M4 ;
        RECT  0 48.96 0.084 48.984 ;
    END
  END a_rr1[213]
  PIN a_rr1[214]
    DIRECTION OUTPUT ;
    USE SIGNAL ;
    PORT
      LAYER M4 ;
        RECT  0 49.152 0.084 49.176 ;
    END
  END a_rr1[214]
  PIN a_rr1[215]
    DIRECTION OUTPUT ;
    USE SIGNAL ;
    PORT
      LAYER M4 ;
        RECT  0 49.344 0.084 49.368 ;
    END
  END a_rr1[215]
  PIN a_rr1[216]
    DIRECTION OUTPUT ;
    USE SIGNAL ;
    PORT
      LAYER M4 ;
        RECT  0 49.536 0.084 49.56 ;
    END
  END a_rr1[216]
  PIN a_rr1[217]
    DIRECTION OUTPUT ;
    USE SIGNAL ;
    PORT
      LAYER M4 ;
        RECT  0 49.728 0.084 49.752 ;
    END
  END a_rr1[217]
  PIN a_rr1[218]
    DIRECTION OUTPUT ;
    USE SIGNAL ;
    PORT
      LAYER M4 ;
        RECT  0 49.92 0.084 49.944 ;
    END
  END a_rr1[218]
  PIN a_rr1[219]
    DIRECTION OUTPUT ;
    USE SIGNAL ;
    PORT
      LAYER M4 ;
        RECT  0 50.112 0.084 50.136 ;
    END
  END a_rr1[219]
  PIN a_rr1[21]
    DIRECTION OUTPUT ;
    USE SIGNAL ;
    PORT
      LAYER M4 ;
        RECT  0 12.624 0.084 12.648 ;
    END
  END a_rr1[21]
  PIN a_rr1[220]
    DIRECTION OUTPUT ;
    USE SIGNAL ;
    PORT
      LAYER M4 ;
        RECT  0 50.304 0.084 50.328 ;
    END
  END a_rr1[220]
  PIN a_rr1[221]
    DIRECTION OUTPUT ;
    USE SIGNAL ;
    PORT
      LAYER M4 ;
        RECT  0 50.496 0.084 50.52 ;
    END
  END a_rr1[221]
  PIN a_rr1[222]
    DIRECTION OUTPUT ;
    USE SIGNAL ;
    PORT
      LAYER M4 ;
        RECT  0 50.64 0.084 50.664 ;
    END
  END a_rr1[222]
  PIN a_rr1[223]
    DIRECTION OUTPUT ;
    USE SIGNAL ;
    PORT
      LAYER M4 ;
        RECT  0 50.832 0.084 50.856 ;
    END
  END a_rr1[223]
  PIN a_rr1[224]
    DIRECTION OUTPUT ;
    USE SIGNAL ;
    PORT
      LAYER M4 ;
        RECT  0 51.024 0.084 51.048 ;
    END
  END a_rr1[224]
  PIN a_rr1[225]
    DIRECTION OUTPUT ;
    USE SIGNAL ;
    PORT
      LAYER M4 ;
        RECT  0 51.216 0.084 51.24 ;
    END
  END a_rr1[225]
  PIN a_rr1[226]
    DIRECTION OUTPUT ;
    USE SIGNAL ;
    PORT
      LAYER M4 ;
        RECT  0 51.408 0.084 51.432 ;
    END
  END a_rr1[226]
  PIN a_rr1[227]
    DIRECTION OUTPUT ;
    USE SIGNAL ;
    PORT
      LAYER M4 ;
        RECT  0 51.6 0.084 51.624 ;
    END
  END a_rr1[227]
  PIN a_rr1[228]
    DIRECTION OUTPUT ;
    USE SIGNAL ;
    PORT
      LAYER M4 ;
        RECT  0 51.792 0.084 51.816 ;
    END
  END a_rr1[228]
  PIN a_rr1[229]
    DIRECTION OUTPUT ;
    USE SIGNAL ;
    PORT
      LAYER M4 ;
        RECT  0 51.984 0.084 52.008 ;
    END
  END a_rr1[229]
  PIN a_rr1[22]
    DIRECTION OUTPUT ;
    USE SIGNAL ;
    PORT
      LAYER M4 ;
        RECT  0 12.816 0.084 12.84 ;
    END
  END a_rr1[22]
  PIN a_rr1[230]
    DIRECTION OUTPUT ;
    USE SIGNAL ;
    PORT
      LAYER M4 ;
        RECT  0 52.176 0.084 52.2 ;
    END
  END a_rr1[230]
  PIN a_rr1[231]
    DIRECTION OUTPUT ;
    USE SIGNAL ;
    PORT
      LAYER M4 ;
        RECT  0 52.368 0.084 52.392 ;
    END
  END a_rr1[231]
  PIN a_rr1[232]
    DIRECTION OUTPUT ;
    USE SIGNAL ;
    PORT
      LAYER M4 ;
        RECT  0 52.56 0.084 52.584 ;
    END
  END a_rr1[232]
  PIN a_rr1[233]
    DIRECTION OUTPUT ;
    USE SIGNAL ;
    PORT
      LAYER M4 ;
        RECT  0 52.752 0.084 52.776 ;
    END
  END a_rr1[233]
  PIN a_rr1[234]
    DIRECTION OUTPUT ;
    USE SIGNAL ;
    PORT
      LAYER M4 ;
        RECT  0 52.944 0.084 52.968 ;
    END
  END a_rr1[234]
  PIN a_rr1[235]
    DIRECTION OUTPUT ;
    USE SIGNAL ;
    PORT
      LAYER M4 ;
        RECT  0 53.136 0.084 53.16 ;
    END
  END a_rr1[235]
  PIN a_rr1[236]
    DIRECTION OUTPUT ;
    USE SIGNAL ;
    PORT
      LAYER M4 ;
        RECT  0 53.328 0.084 53.352 ;
    END
  END a_rr1[236]
  PIN a_rr1[237]
    DIRECTION OUTPUT ;
    USE SIGNAL ;
    PORT
      LAYER M4 ;
        RECT  0 53.52 0.084 53.544 ;
    END
  END a_rr1[237]
  PIN a_rr1[238]
    DIRECTION OUTPUT ;
    USE SIGNAL ;
    PORT
      LAYER M4 ;
        RECT  0 53.712 0.084 53.736 ;
    END
  END a_rr1[238]
  PIN a_rr1[239]
    DIRECTION OUTPUT ;
    USE SIGNAL ;
    PORT
      LAYER M4 ;
        RECT  0 53.856 0.084 53.88 ;
    END
  END a_rr1[239]
  PIN a_rr1[23]
    DIRECTION OUTPUT ;
    USE SIGNAL ;
    PORT
      LAYER M4 ;
        RECT  0 13.008 0.084 13.032 ;
    END
  END a_rr1[23]
  PIN a_rr1[240]
    DIRECTION OUTPUT ;
    USE SIGNAL ;
    PORT
      LAYER M4 ;
        RECT  0 54.048 0.084 54.072 ;
    END
  END a_rr1[240]
  PIN a_rr1[241]
    DIRECTION OUTPUT ;
    USE SIGNAL ;
    PORT
      LAYER M4 ;
        RECT  0 54.24 0.084 54.264 ;
    END
  END a_rr1[241]
  PIN a_rr1[242]
    DIRECTION OUTPUT ;
    USE SIGNAL ;
    PORT
      LAYER M4 ;
        RECT  0 54.432 0.084 54.456 ;
    END
  END a_rr1[242]
  PIN a_rr1[243]
    DIRECTION OUTPUT ;
    USE SIGNAL ;
    PORT
      LAYER M4 ;
        RECT  0 54.624 0.084 54.648 ;
    END
  END a_rr1[243]
  PIN a_rr1[244]
    DIRECTION OUTPUT ;
    USE SIGNAL ;
    PORT
      LAYER M4 ;
        RECT  0 54.816 0.084 54.84 ;
    END
  END a_rr1[244]
  PIN a_rr1[245]
    DIRECTION OUTPUT ;
    USE SIGNAL ;
    PORT
      LAYER M4 ;
        RECT  0 55.008 0.084 55.032 ;
    END
  END a_rr1[245]
  PIN a_rr1[246]
    DIRECTION OUTPUT ;
    USE SIGNAL ;
    PORT
      LAYER M4 ;
        RECT  0 55.2 0.084 55.224 ;
    END
  END a_rr1[246]
  PIN a_rr1[247]
    DIRECTION OUTPUT ;
    USE SIGNAL ;
    PORT
      LAYER M4 ;
        RECT  0 55.392 0.084 55.416 ;
    END
  END a_rr1[247]
  PIN a_rr1[248]
    DIRECTION OUTPUT ;
    USE SIGNAL ;
    PORT
      LAYER M4 ;
        RECT  0 55.584 0.084 55.608 ;
    END
  END a_rr1[248]
  PIN a_rr1[249]
    DIRECTION OUTPUT ;
    USE SIGNAL ;
    PORT
      LAYER M4 ;
        RECT  0 55.776 0.084 55.8 ;
    END
  END a_rr1[249]
  PIN a_rr1[24]
    DIRECTION OUTPUT ;
    USE SIGNAL ;
    PORT
      LAYER M4 ;
        RECT  0 13.2 0.084 13.224 ;
    END
  END a_rr1[24]
  PIN a_rr1[250]
    DIRECTION OUTPUT ;
    USE SIGNAL ;
    PORT
      LAYER M4 ;
        RECT  0 55.968 0.084 55.992 ;
    END
  END a_rr1[250]
  PIN a_rr1[251]
    DIRECTION OUTPUT ;
    USE SIGNAL ;
    PORT
      LAYER M4 ;
        RECT  0 56.16 0.084 56.184 ;
    END
  END a_rr1[251]
  PIN a_rr1[252]
    DIRECTION OUTPUT ;
    USE SIGNAL ;
    PORT
      LAYER M4 ;
        RECT  0 56.352 0.084 56.376 ;
    END
  END a_rr1[252]
  PIN a_rr1[253]
    DIRECTION OUTPUT ;
    USE SIGNAL ;
    PORT
      LAYER M4 ;
        RECT  0 56.544 0.084 56.568 ;
    END
  END a_rr1[253]
  PIN a_rr1[254]
    DIRECTION OUTPUT ;
    USE SIGNAL ;
    PORT
      LAYER M4 ;
        RECT  0 56.736 0.084 56.76 ;
    END
  END a_rr1[254]
  PIN a_rr1[255]
    DIRECTION OUTPUT ;
    USE SIGNAL ;
    PORT
      LAYER M4 ;
        RECT  0 56.928 0.084 56.952 ;
    END
  END a_rr1[255]
  PIN a_rr1[256]
    DIRECTION OUTPUT ;
    USE SIGNAL ;
    PORT
      LAYER M4 ;
        RECT  0 57.072 0.084 57.096 ;
    END
  END a_rr1[256]
  PIN a_rr1[25]
    DIRECTION OUTPUT ;
    USE SIGNAL ;
    PORT
      LAYER M4 ;
        RECT  0 13.392 0.084 13.416 ;
    END
  END a_rr1[25]
  PIN a_rr1[26]
    DIRECTION OUTPUT ;
    USE SIGNAL ;
    PORT
      LAYER M4 ;
        RECT  0 13.584 0.084 13.608 ;
    END
  END a_rr1[26]
  PIN a_rr1[27]
    DIRECTION OUTPUT ;
    USE SIGNAL ;
    PORT
      LAYER M4 ;
        RECT  0 13.776 0.084 13.8 ;
    END
  END a_rr1[27]
  PIN a_rr1[28]
    DIRECTION OUTPUT ;
    USE SIGNAL ;
    PORT
      LAYER M4 ;
        RECT  0 13.968 0.084 13.992 ;
    END
  END a_rr1[28]
  PIN a_rr1[29]
    DIRECTION OUTPUT ;
    USE SIGNAL ;
    PORT
      LAYER M4 ;
        RECT  0 14.16 0.084 14.184 ;
    END
  END a_rr1[29]
  PIN a_rr1[2]
    DIRECTION OUTPUT ;
    USE SIGNAL ;
    PORT
      LAYER M4 ;
        RECT  0 9.072 0.084 9.096 ;
    END
  END a_rr1[2]
  PIN a_rr1[30]
    DIRECTION OUTPUT ;
    USE SIGNAL ;
    PORT
      LAYER M4 ;
        RECT  0 14.352 0.084 14.376 ;
    END
  END a_rr1[30]
  PIN a_rr1[31]
    DIRECTION OUTPUT ;
    USE SIGNAL ;
    PORT
      LAYER M4 ;
        RECT  0 14.544 0.084 14.568 ;
    END
  END a_rr1[31]
  PIN a_rr1[32]
    DIRECTION OUTPUT ;
    USE SIGNAL ;
    PORT
      LAYER M4 ;
        RECT  0 14.736 0.084 14.76 ;
    END
  END a_rr1[32]
  PIN a_rr1[33]
    DIRECTION OUTPUT ;
    USE SIGNAL ;
    PORT
      LAYER M4 ;
        RECT  0 14.928 0.084 14.952 ;
    END
  END a_rr1[33]
  PIN a_rr1[34]
    DIRECTION OUTPUT ;
    USE SIGNAL ;
    PORT
      LAYER M4 ;
        RECT  0 15.12 0.084 15.144 ;
    END
  END a_rr1[34]
  PIN a_rr1[35]
    DIRECTION OUTPUT ;
    USE SIGNAL ;
    PORT
      LAYER M4 ;
        RECT  0 15.312 0.084 15.336 ;
    END
  END a_rr1[35]
  PIN a_rr1[36]
    DIRECTION OUTPUT ;
    USE SIGNAL ;
    PORT
      LAYER M4 ;
        RECT  0 15.504 0.084 15.528 ;
    END
  END a_rr1[36]
  PIN a_rr1[37]
    DIRECTION OUTPUT ;
    USE SIGNAL ;
    PORT
      LAYER M4 ;
        RECT  0 15.696 0.084 15.72 ;
    END
  END a_rr1[37]
  PIN a_rr1[38]
    DIRECTION OUTPUT ;
    USE SIGNAL ;
    PORT
      LAYER M4 ;
        RECT  0 15.84 0.084 15.864 ;
    END
  END a_rr1[38]
  PIN a_rr1[39]
    DIRECTION OUTPUT ;
    USE SIGNAL ;
    PORT
      LAYER M4 ;
        RECT  0 16.032 0.084 16.056 ;
    END
  END a_rr1[39]
  PIN a_rr1[3]
    DIRECTION OUTPUT ;
    USE SIGNAL ;
    PORT
      LAYER M4 ;
        RECT  0 9.264 0.084 9.288 ;
    END
  END a_rr1[3]
  PIN a_rr1[40]
    DIRECTION OUTPUT ;
    USE SIGNAL ;
    PORT
      LAYER M4 ;
        RECT  0 16.224 0.084 16.248 ;
    END
  END a_rr1[40]
  PIN a_rr1[41]
    DIRECTION OUTPUT ;
    USE SIGNAL ;
    PORT
      LAYER M4 ;
        RECT  0 16.416 0.084 16.44 ;
    END
  END a_rr1[41]
  PIN a_rr1[42]
    DIRECTION OUTPUT ;
    USE SIGNAL ;
    PORT
      LAYER M4 ;
        RECT  0 16.608 0.084 16.632 ;
    END
  END a_rr1[42]
  PIN a_rr1[43]
    DIRECTION OUTPUT ;
    USE SIGNAL ;
    PORT
      LAYER M4 ;
        RECT  0 16.8 0.084 16.824 ;
    END
  END a_rr1[43]
  PIN a_rr1[44]
    DIRECTION OUTPUT ;
    USE SIGNAL ;
    PORT
      LAYER M4 ;
        RECT  0 16.992 0.084 17.016 ;
    END
  END a_rr1[44]
  PIN a_rr1[45]
    DIRECTION OUTPUT ;
    USE SIGNAL ;
    PORT
      LAYER M4 ;
        RECT  0 17.184 0.084 17.208 ;
    END
  END a_rr1[45]
  PIN a_rr1[46]
    DIRECTION OUTPUT ;
    USE SIGNAL ;
    PORT
      LAYER M4 ;
        RECT  0 17.376 0.084 17.4 ;
    END
  END a_rr1[46]
  PIN a_rr1[47]
    DIRECTION OUTPUT ;
    USE SIGNAL ;
    PORT
      LAYER M4 ;
        RECT  0 17.568 0.084 17.592 ;
    END
  END a_rr1[47]
  PIN a_rr1[48]
    DIRECTION OUTPUT ;
    USE SIGNAL ;
    PORT
      LAYER M4 ;
        RECT  0 17.76 0.084 17.784 ;
    END
  END a_rr1[48]
  PIN a_rr1[49]
    DIRECTION OUTPUT ;
    USE SIGNAL ;
    PORT
      LAYER M4 ;
        RECT  0 17.952 0.084 17.976 ;
    END
  END a_rr1[49]
  PIN a_rr1[4]
    DIRECTION OUTPUT ;
    USE SIGNAL ;
    PORT
      LAYER M4 ;
        RECT  0 9.456 0.084 9.48 ;
    END
  END a_rr1[4]
  PIN a_rr1[50]
    DIRECTION OUTPUT ;
    USE SIGNAL ;
    PORT
      LAYER M4 ;
        RECT  0 18.144 0.084 18.168 ;
    END
  END a_rr1[50]
  PIN a_rr1[51]
    DIRECTION OUTPUT ;
    USE SIGNAL ;
    PORT
      LAYER M4 ;
        RECT  0 18.336 0.084 18.36 ;
    END
  END a_rr1[51]
  PIN a_rr1[52]
    DIRECTION OUTPUT ;
    USE SIGNAL ;
    PORT
      LAYER M4 ;
        RECT  0 18.528 0.084 18.552 ;
    END
  END a_rr1[52]
  PIN a_rr1[53]
    DIRECTION OUTPUT ;
    USE SIGNAL ;
    PORT
      LAYER M4 ;
        RECT  0 18.72 0.084 18.744 ;
    END
  END a_rr1[53]
  PIN a_rr1[54]
    DIRECTION OUTPUT ;
    USE SIGNAL ;
    PORT
      LAYER M4 ;
        RECT  0 18.912 0.084 18.936 ;
    END
  END a_rr1[54]
  PIN a_rr1[55]
    DIRECTION OUTPUT ;
    USE SIGNAL ;
    PORT
      LAYER M4 ;
        RECT  0 19.056 0.084 19.08 ;
    END
  END a_rr1[55]
  PIN a_rr1[56]
    DIRECTION OUTPUT ;
    USE SIGNAL ;
    PORT
      LAYER M4 ;
        RECT  0 19.248 0.084 19.272 ;
    END
  END a_rr1[56]
  PIN a_rr1[57]
    DIRECTION OUTPUT ;
    USE SIGNAL ;
    PORT
      LAYER M4 ;
        RECT  0 19.44 0.084 19.464 ;
    END
  END a_rr1[57]
  PIN a_rr1[58]
    DIRECTION OUTPUT ;
    USE SIGNAL ;
    PORT
      LAYER M4 ;
        RECT  0 19.632 0.084 19.656 ;
    END
  END a_rr1[58]
  PIN a_rr1[59]
    DIRECTION OUTPUT ;
    USE SIGNAL ;
    PORT
      LAYER M4 ;
        RECT  0 19.824 0.084 19.848 ;
    END
  END a_rr1[59]
  PIN a_rr1[5]
    DIRECTION OUTPUT ;
    USE SIGNAL ;
    PORT
      LAYER M4 ;
        RECT  0 9.6 0.084 9.624 ;
    END
  END a_rr1[5]
  PIN a_rr1[60]
    DIRECTION OUTPUT ;
    USE SIGNAL ;
    PORT
      LAYER M4 ;
        RECT  0 20.016 0.084 20.04 ;
    END
  END a_rr1[60]
  PIN a_rr1[61]
    DIRECTION OUTPUT ;
    USE SIGNAL ;
    PORT
      LAYER M4 ;
        RECT  0 20.208 0.084 20.232 ;
    END
  END a_rr1[61]
  PIN a_rr1[62]
    DIRECTION OUTPUT ;
    USE SIGNAL ;
    PORT
      LAYER M4 ;
        RECT  0 20.4 0.084 20.424 ;
    END
  END a_rr1[62]
  PIN a_rr1[63]
    DIRECTION OUTPUT ;
    USE SIGNAL ;
    PORT
      LAYER M4 ;
        RECT  0 20.592 0.084 20.616 ;
    END
  END a_rr1[63]
  PIN a_rr1[64]
    DIRECTION OUTPUT ;
    USE SIGNAL ;
    PORT
      LAYER M4 ;
        RECT  0 20.784 0.084 20.808 ;
    END
  END a_rr1[64]
  PIN a_rr1[65]
    DIRECTION OUTPUT ;
    USE SIGNAL ;
    PORT
      LAYER M4 ;
        RECT  0 20.976 0.084 21 ;
    END
  END a_rr1[65]
  PIN a_rr1[66]
    DIRECTION OUTPUT ;
    USE SIGNAL ;
    PORT
      LAYER M4 ;
        RECT  0 21.168 0.084 21.192 ;
    END
  END a_rr1[66]
  PIN a_rr1[67]
    DIRECTION OUTPUT ;
    USE SIGNAL ;
    PORT
      LAYER M4 ;
        RECT  0 21.36 0.084 21.384 ;
    END
  END a_rr1[67]
  PIN a_rr1[68]
    DIRECTION OUTPUT ;
    USE SIGNAL ;
    PORT
      LAYER M4 ;
        RECT  0 21.552 0.084 21.576 ;
    END
  END a_rr1[68]
  PIN a_rr1[69]
    DIRECTION OUTPUT ;
    USE SIGNAL ;
    PORT
      LAYER M4 ;
        RECT  0 21.744 0.084 21.768 ;
    END
  END a_rr1[69]
  PIN a_rr1[6]
    DIRECTION OUTPUT ;
    USE SIGNAL ;
    PORT
      LAYER M4 ;
        RECT  0 9.792 0.084 9.816 ;
    END
  END a_rr1[6]
  PIN a_rr1[70]
    DIRECTION OUTPUT ;
    USE SIGNAL ;
    PORT
      LAYER M4 ;
        RECT  0 21.936 0.084 21.96 ;
    END
  END a_rr1[70]
  PIN a_rr1[71]
    DIRECTION OUTPUT ;
    USE SIGNAL ;
    PORT
      LAYER M4 ;
        RECT  0 22.128 0.084 22.152 ;
    END
  END a_rr1[71]
  PIN a_rr1[72]
    DIRECTION OUTPUT ;
    USE SIGNAL ;
    PORT
      LAYER M4 ;
        RECT  0 22.272 0.084 22.296 ;
    END
  END a_rr1[72]
  PIN a_rr1[73]
    DIRECTION OUTPUT ;
    USE SIGNAL ;
    PORT
      LAYER M4 ;
        RECT  0 22.464 0.084 22.488 ;
    END
  END a_rr1[73]
  PIN a_rr1[74]
    DIRECTION OUTPUT ;
    USE SIGNAL ;
    PORT
      LAYER M4 ;
        RECT  0 22.656 0.084 22.68 ;
    END
  END a_rr1[74]
  PIN a_rr1[75]
    DIRECTION OUTPUT ;
    USE SIGNAL ;
    PORT
      LAYER M4 ;
        RECT  0 22.848 0.084 22.872 ;
    END
  END a_rr1[75]
  PIN a_rr1[76]
    DIRECTION OUTPUT ;
    USE SIGNAL ;
    PORT
      LAYER M4 ;
        RECT  0 23.04 0.084 23.064 ;
    END
  END a_rr1[76]
  PIN a_rr1[77]
    DIRECTION OUTPUT ;
    USE SIGNAL ;
    PORT
      LAYER M4 ;
        RECT  0 23.232 0.084 23.256 ;
    END
  END a_rr1[77]
  PIN a_rr1[78]
    DIRECTION OUTPUT ;
    USE SIGNAL ;
    PORT
      LAYER M4 ;
        RECT  0 23.424 0.084 23.448 ;
    END
  END a_rr1[78]
  PIN a_rr1[79]
    DIRECTION OUTPUT ;
    USE SIGNAL ;
    PORT
      LAYER M4 ;
        RECT  0 23.616 0.084 23.64 ;
    END
  END a_rr1[79]
  PIN a_rr1[7]
    DIRECTION OUTPUT ;
    USE SIGNAL ;
    PORT
      LAYER M4 ;
        RECT  0 9.984 0.084 10.008 ;
    END
  END a_rr1[7]
  PIN a_rr1[80]
    DIRECTION OUTPUT ;
    USE SIGNAL ;
    PORT
      LAYER M4 ;
        RECT  0 23.808 0.084 23.832 ;
    END
  END a_rr1[80]
  PIN a_rr1[81]
    DIRECTION OUTPUT ;
    USE SIGNAL ;
    PORT
      LAYER M4 ;
        RECT  0 24 0.084 24.024 ;
    END
  END a_rr1[81]
  PIN a_rr1[82]
    DIRECTION OUTPUT ;
    USE SIGNAL ;
    PORT
      LAYER M4 ;
        RECT  0 24.192 0.084 24.216 ;
    END
  END a_rr1[82]
  PIN a_rr1[83]
    DIRECTION OUTPUT ;
    USE SIGNAL ;
    PORT
      LAYER M4 ;
        RECT  0 24.384 0.084 24.408 ;
    END
  END a_rr1[83]
  PIN a_rr1[84]
    DIRECTION OUTPUT ;
    USE SIGNAL ;
    PORT
      LAYER M4 ;
        RECT  0 24.576 0.084 24.6 ;
    END
  END a_rr1[84]
  PIN a_rr1[85]
    DIRECTION OUTPUT ;
    USE SIGNAL ;
    PORT
      LAYER M4 ;
        RECT  0 24.768 0.084 24.792 ;
    END
  END a_rr1[85]
  PIN a_rr1[86]
    DIRECTION OUTPUT ;
    USE SIGNAL ;
    PORT
      LAYER M4 ;
        RECT  0 24.96 0.084 24.984 ;
    END
  END a_rr1[86]
  PIN a_rr1[87]
    DIRECTION OUTPUT ;
    USE SIGNAL ;
    PORT
      LAYER M4 ;
        RECT  0 25.152 0.084 25.176 ;
    END
  END a_rr1[87]
  PIN a_rr1[88]
    DIRECTION OUTPUT ;
    USE SIGNAL ;
    PORT
      LAYER M4 ;
        RECT  0 25.296 0.084 25.32 ;
    END
  END a_rr1[88]
  PIN a_rr1[89]
    DIRECTION OUTPUT ;
    USE SIGNAL ;
    PORT
      LAYER M4 ;
        RECT  0 25.488 0.084 25.512 ;
    END
  END a_rr1[89]
  PIN a_rr1[8]
    DIRECTION OUTPUT ;
    USE SIGNAL ;
    PORT
      LAYER M4 ;
        RECT  0 10.176 0.084 10.2 ;
    END
  END a_rr1[8]
  PIN a_rr1[90]
    DIRECTION OUTPUT ;
    USE SIGNAL ;
    PORT
      LAYER M4 ;
        RECT  0 25.68 0.084 25.704 ;
    END
  END a_rr1[90]
  PIN a_rr1[91]
    DIRECTION OUTPUT ;
    USE SIGNAL ;
    PORT
      LAYER M4 ;
        RECT  0 25.872 0.084 25.896 ;
    END
  END a_rr1[91]
  PIN a_rr1[92]
    DIRECTION OUTPUT ;
    USE SIGNAL ;
    PORT
      LAYER M4 ;
        RECT  0 26.064 0.084 26.088 ;
    END
  END a_rr1[92]
  PIN a_rr1[93]
    DIRECTION OUTPUT ;
    USE SIGNAL ;
    PORT
      LAYER M4 ;
        RECT  0 26.256 0.084 26.28 ;
    END
  END a_rr1[93]
  PIN a_rr1[94]
    DIRECTION OUTPUT ;
    USE SIGNAL ;
    PORT
      LAYER M4 ;
        RECT  0 26.448 0.084 26.472 ;
    END
  END a_rr1[94]
  PIN a_rr1[95]
    DIRECTION OUTPUT ;
    USE SIGNAL ;
    PORT
      LAYER M4 ;
        RECT  0 26.64 0.084 26.664 ;
    END
  END a_rr1[95]
  PIN a_rr1[96]
    DIRECTION OUTPUT ;
    USE SIGNAL ;
    PORT
      LAYER M4 ;
        RECT  0 26.832 0.084 26.856 ;
    END
  END a_rr1[96]
  PIN a_rr1[97]
    DIRECTION OUTPUT ;
    USE SIGNAL ;
    PORT
      LAYER M4 ;
        RECT  0 27.024 0.084 27.048 ;
    END
  END a_rr1[97]
  PIN a_rr1[98]
    DIRECTION OUTPUT ;
    USE SIGNAL ;
    PORT
      LAYER M4 ;
        RECT  0 27.216 0.084 27.24 ;
    END
  END a_rr1[98]
  PIN a_rr1[99]
    DIRECTION OUTPUT ;
    USE SIGNAL ;
    PORT
      LAYER M4 ;
        RECT  0 27.408 0.084 27.432 ;
    END
  END a_rr1[99]
  PIN a_rr1[9]
    DIRECTION OUTPUT ;
    USE SIGNAL ;
    PORT
      LAYER M4 ;
        RECT  0 10.368 0.084 10.392 ;
    END
  END a_rr1[9]
  PIN b_rq[0]
    DIRECTION INPUT ;
    USE SIGNAL ;
    PORT
      LAYER M4 ;
        RECT  107.916 2.256 108 2.28 ;
    END
  END b_rq[0]
  PIN b_rq[10]
    DIRECTION INPUT ;
    USE SIGNAL ;
    PORT
      LAYER M4 ;
        RECT  107.916 4.128 108 4.152 ;
    END
  END b_rq[10]
  PIN b_rq[11]
    DIRECTION INPUT ;
    USE SIGNAL ;
    PORT
      LAYER M4 ;
        RECT  107.916 4.32 108 4.344 ;
    END
  END b_rq[11]
  PIN b_rq[12]
    DIRECTION INPUT ;
    USE SIGNAL ;
    PORT
      LAYER M4 ;
        RECT  107.916 4.512 108 4.536 ;
    END
  END b_rq[12]
  PIN b_rq[13]
    DIRECTION INPUT ;
    USE SIGNAL ;
    PORT
      LAYER M4 ;
        RECT  107.916 4.704 108 4.728 ;
    END
  END b_rq[13]
  PIN b_rq[14]
    DIRECTION INPUT ;
    USE SIGNAL ;
    PORT
      LAYER M4 ;
        RECT  107.916 4.896 108 4.92 ;
    END
  END b_rq[14]
  PIN b_rq[15]
    DIRECTION INPUT ;
    USE SIGNAL ;
    PORT
      LAYER M4 ;
        RECT  107.916 5.088 108 5.112 ;
    END
  END b_rq[15]
  PIN b_rq[16]
    DIRECTION INPUT ;
    USE SIGNAL ;
    PORT
      LAYER M4 ;
        RECT  107.916 5.28 108 5.304 ;
    END
  END b_rq[16]
  PIN b_rq[17]
    DIRECTION INPUT ;
    USE SIGNAL ;
    PORT
      LAYER M4 ;
        RECT  107.916 5.472 108 5.496 ;
    END
  END b_rq[17]
  PIN b_rq[18]
    DIRECTION INPUT ;
    USE SIGNAL ;
    PORT
      LAYER M4 ;
        RECT  107.916 5.664 108 5.688 ;
    END
  END b_rq[18]
  PIN b_rq[19]
    DIRECTION INPUT ;
    USE SIGNAL ;
    PORT
      LAYER M4 ;
        RECT  107.916 5.856 108 5.88 ;
    END
  END b_rq[19]
  PIN b_rq[1]
    DIRECTION INPUT ;
    USE SIGNAL ;
    PORT
      LAYER M4 ;
        RECT  107.916 2.448 108 2.472 ;
    END
  END b_rq[1]
  PIN b_rq[20]
    DIRECTION INPUT ;
    USE SIGNAL ;
    PORT
      LAYER M4 ;
        RECT  107.916 6.048 108 6.072 ;
    END
  END b_rq[20]
  PIN b_rq[21]
    DIRECTION INPUT ;
    USE SIGNAL ;
    PORT
      LAYER M4 ;
        RECT  107.916 6.24 108 6.264 ;
    END
  END b_rq[21]
  PIN b_rq[22]
    DIRECTION INPUT ;
    USE SIGNAL ;
    PORT
      LAYER M4 ;
        RECT  107.916 6.384 108 6.408 ;
    END
  END b_rq[22]
  PIN b_rq[23]
    DIRECTION INPUT ;
    USE SIGNAL ;
    PORT
      LAYER M4 ;
        RECT  107.916 6.576 108 6.6 ;
    END
  END b_rq[23]
  PIN b_rq[24]
    DIRECTION INPUT ;
    USE SIGNAL ;
    PORT
      LAYER M4 ;
        RECT  107.916 6.768 108 6.792 ;
    END
  END b_rq[24]
  PIN b_rq[25]
    DIRECTION INPUT ;
    USE SIGNAL ;
    PORT
      LAYER M4 ;
        RECT  107.916 6.96 108 6.984 ;
    END
  END b_rq[25]
  PIN b_rq[26]
    DIRECTION INPUT ;
    USE SIGNAL ;
    PORT
      LAYER M4 ;
        RECT  107.916 7.152 108 7.176 ;
    END
  END b_rq[26]
  PIN b_rq[27]
    DIRECTION INPUT ;
    USE SIGNAL ;
    PORT
      LAYER M4 ;
        RECT  107.916 7.344 108 7.368 ;
    END
  END b_rq[27]
  PIN b_rq[28]
    DIRECTION INPUT ;
    USE SIGNAL ;
    PORT
      LAYER M4 ;
        RECT  107.916 7.536 108 7.56 ;
    END
  END b_rq[28]
  PIN b_rq[29]
    DIRECTION INPUT ;
    USE SIGNAL ;
    PORT
      LAYER M4 ;
        RECT  107.916 7.728 108 7.752 ;
    END
  END b_rq[29]
  PIN b_rq[2]
    DIRECTION INPUT ;
    USE SIGNAL ;
    PORT
      LAYER M4 ;
        RECT  107.916 2.64 108 2.664 ;
    END
  END b_rq[2]
  PIN b_rq[30]
    DIRECTION INPUT ;
    USE SIGNAL ;
    PORT
      LAYER M4 ;
        RECT  107.916 7.92 108 7.944 ;
    END
  END b_rq[30]
  PIN b_rq[31]
    DIRECTION INPUT ;
    USE SIGNAL ;
    PORT
      LAYER M4 ;
        RECT  107.916 8.112 108 8.136 ;
    END
  END b_rq[31]
  PIN b_rq[32]
    DIRECTION INPUT ;
    USE SIGNAL ;
    PORT
      LAYER M4 ;
        RECT  107.916 8.304 108 8.328 ;
    END
  END b_rq[32]
  PIN b_rq[33]
    DIRECTION INPUT ;
    USE SIGNAL ;
    PORT
      LAYER M4 ;
        RECT  107.916 8.496 108 8.52 ;
    END
  END b_rq[33]
  PIN b_rq[3]
    DIRECTION INPUT ;
    USE SIGNAL ;
    PORT
      LAYER M4 ;
        RECT  107.916 2.832 108 2.856 ;
    END
  END b_rq[3]
  PIN b_rq[4]
    DIRECTION INPUT ;
    USE SIGNAL ;
    PORT
      LAYER M4 ;
        RECT  107.916 2.976 108 3 ;
    END
  END b_rq[4]
  PIN b_rq[5]
    DIRECTION INPUT ;
    USE SIGNAL ;
    PORT
      LAYER M4 ;
        RECT  107.916 3.168 108 3.192 ;
    END
  END b_rq[5]
  PIN b_rq[6]
    DIRECTION INPUT ;
    USE SIGNAL ;
    PORT
      LAYER M4 ;
        RECT  107.916 3.36 108 3.384 ;
    END
  END b_rq[6]
  PIN b_rq[7]
    DIRECTION INPUT ;
    USE SIGNAL ;
    PORT
      LAYER M4 ;
        RECT  107.916 3.552 108 3.576 ;
    END
  END b_rq[7]
  PIN b_rq[8]
    DIRECTION INPUT ;
    USE SIGNAL ;
    PORT
      LAYER M4 ;
        RECT  107.916 3.744 108 3.768 ;
    END
  END b_rq[8]
  PIN b_rq[9]
    DIRECTION INPUT ;
    USE SIGNAL ;
    PORT
      LAYER M4 ;
        RECT  107.916 3.936 108 3.96 ;
    END
  END b_rq[9]
  PIN b_rr0[0]
    DIRECTION OUTPUT ;
    USE SIGNAL ;
    PORT
      LAYER M4 ;
        RECT  107.916 8.688 108 8.712 ;
    END
  END b_rr0[0]
  PIN b_rr0[100]
    DIRECTION OUTPUT ;
    USE SIGNAL ;
    PORT
      LAYER M4 ;
        RECT  107.916 27.6 108 27.624 ;
    END
  END b_rr0[100]
  PIN b_rr0[101]
    DIRECTION OUTPUT ;
    USE SIGNAL ;
    PORT
      LAYER M4 ;
        RECT  107.916 27.792 108 27.816 ;
    END
  END b_rr0[101]
  PIN b_rr0[102]
    DIRECTION OUTPUT ;
    USE SIGNAL ;
    PORT
      LAYER M4 ;
        RECT  107.916 27.984 108 28.008 ;
    END
  END b_rr0[102]
  PIN b_rr0[103]
    DIRECTION OUTPUT ;
    USE SIGNAL ;
    PORT
      LAYER M4 ;
        RECT  107.916 28.176 108 28.2 ;
    END
  END b_rr0[103]
  PIN b_rr0[104]
    DIRECTION OUTPUT ;
    USE SIGNAL ;
    PORT
      LAYER M4 ;
        RECT  107.916 28.368 108 28.392 ;
    END
  END b_rr0[104]
  PIN b_rr0[105]
    DIRECTION OUTPUT ;
    USE SIGNAL ;
    PORT
      LAYER M4 ;
        RECT  107.916 28.512 108 28.536 ;
    END
  END b_rr0[105]
  PIN b_rr0[106]
    DIRECTION OUTPUT ;
    USE SIGNAL ;
    PORT
      LAYER M4 ;
        RECT  107.916 28.704 108 28.728 ;
    END
  END b_rr0[106]
  PIN b_rr0[107]
    DIRECTION OUTPUT ;
    USE SIGNAL ;
    PORT
      LAYER M4 ;
        RECT  107.916 28.896 108 28.92 ;
    END
  END b_rr0[107]
  PIN b_rr0[108]
    DIRECTION OUTPUT ;
    USE SIGNAL ;
    PORT
      LAYER M4 ;
        RECT  107.916 29.088 108 29.112 ;
    END
  END b_rr0[108]
  PIN b_rr0[109]
    DIRECTION OUTPUT ;
    USE SIGNAL ;
    PORT
      LAYER M4 ;
        RECT  107.916 29.28 108 29.304 ;
    END
  END b_rr0[109]
  PIN b_rr0[10]
    DIRECTION OUTPUT ;
    USE SIGNAL ;
    PORT
      LAYER M4 ;
        RECT  107.916 10.56 108 10.584 ;
    END
  END b_rr0[10]
  PIN b_rr0[110]
    DIRECTION OUTPUT ;
    USE SIGNAL ;
    PORT
      LAYER M4 ;
        RECT  107.916 29.472 108 29.496 ;
    END
  END b_rr0[110]
  PIN b_rr0[111]
    DIRECTION OUTPUT ;
    USE SIGNAL ;
    PORT
      LAYER M4 ;
        RECT  107.916 29.664 108 29.688 ;
    END
  END b_rr0[111]
  PIN b_rr0[112]
    DIRECTION OUTPUT ;
    USE SIGNAL ;
    PORT
      LAYER M4 ;
        RECT  107.916 29.856 108 29.88 ;
    END
  END b_rr0[112]
  PIN b_rr0[113]
    DIRECTION OUTPUT ;
    USE SIGNAL ;
    PORT
      LAYER M4 ;
        RECT  107.916 30.048 108 30.072 ;
    END
  END b_rr0[113]
  PIN b_rr0[114]
    DIRECTION OUTPUT ;
    USE SIGNAL ;
    PORT
      LAYER M4 ;
        RECT  107.916 30.24 108 30.264 ;
    END
  END b_rr0[114]
  PIN b_rr0[115]
    DIRECTION OUTPUT ;
    USE SIGNAL ;
    PORT
      LAYER M4 ;
        RECT  107.916 30.432 108 30.456 ;
    END
  END b_rr0[115]
  PIN b_rr0[116]
    DIRECTION OUTPUT ;
    USE SIGNAL ;
    PORT
      LAYER M4 ;
        RECT  107.916 30.624 108 30.648 ;
    END
  END b_rr0[116]
  PIN b_rr0[117]
    DIRECTION OUTPUT ;
    USE SIGNAL ;
    PORT
      LAYER M4 ;
        RECT  107.916 30.816 108 30.84 ;
    END
  END b_rr0[117]
  PIN b_rr0[118]
    DIRECTION OUTPUT ;
    USE SIGNAL ;
    PORT
      LAYER M4 ;
        RECT  107.916 31.008 108 31.032 ;
    END
  END b_rr0[118]
  PIN b_rr0[119]
    DIRECTION OUTPUT ;
    USE SIGNAL ;
    PORT
      LAYER M4 ;
        RECT  107.916 31.2 108 31.224 ;
    END
  END b_rr0[119]
  PIN b_rr0[11]
    DIRECTION OUTPUT ;
    USE SIGNAL ;
    PORT
      LAYER M4 ;
        RECT  107.916 10.752 108 10.776 ;
    END
  END b_rr0[11]
  PIN b_rr0[120]
    DIRECTION OUTPUT ;
    USE SIGNAL ;
    PORT
      LAYER M4 ;
        RECT  107.916 31.392 108 31.416 ;
    END
  END b_rr0[120]
  PIN b_rr0[121]
    DIRECTION OUTPUT ;
    USE SIGNAL ;
    PORT
      LAYER M4 ;
        RECT  107.916 31.584 108 31.608 ;
    END
  END b_rr0[121]
  PIN b_rr0[122]
    DIRECTION OUTPUT ;
    USE SIGNAL ;
    PORT
      LAYER M4 ;
        RECT  107.916 31.728 108 31.752 ;
    END
  END b_rr0[122]
  PIN b_rr0[123]
    DIRECTION OUTPUT ;
    USE SIGNAL ;
    PORT
      LAYER M4 ;
        RECT  107.916 31.92 108 31.944 ;
    END
  END b_rr0[123]
  PIN b_rr0[124]
    DIRECTION OUTPUT ;
    USE SIGNAL ;
    PORT
      LAYER M4 ;
        RECT  107.916 32.112 108 32.136 ;
    END
  END b_rr0[124]
  PIN b_rr0[125]
    DIRECTION OUTPUT ;
    USE SIGNAL ;
    PORT
      LAYER M4 ;
        RECT  107.916 32.304 108 32.328 ;
    END
  END b_rr0[125]
  PIN b_rr0[126]
    DIRECTION OUTPUT ;
    USE SIGNAL ;
    PORT
      LAYER M4 ;
        RECT  107.916 32.496 108 32.52 ;
    END
  END b_rr0[126]
  PIN b_rr0[127]
    DIRECTION OUTPUT ;
    USE SIGNAL ;
    PORT
      LAYER M4 ;
        RECT  107.916 32.688 108 32.712 ;
    END
  END b_rr0[127]
  PIN b_rr0[128]
    DIRECTION OUTPUT ;
    USE SIGNAL ;
    PORT
      LAYER M4 ;
        RECT  107.916 32.88 108 32.904 ;
    END
  END b_rr0[128]
  PIN b_rr0[129]
    DIRECTION OUTPUT ;
    USE SIGNAL ;
    PORT
      LAYER M4 ;
        RECT  107.916 33.072 108 33.096 ;
    END
  END b_rr0[129]
  PIN b_rr0[12]
    DIRECTION OUTPUT ;
    USE SIGNAL ;
    PORT
      LAYER M4 ;
        RECT  107.916 10.944 108 10.968 ;
    END
  END b_rr0[12]
  PIN b_rr0[130]
    DIRECTION OUTPUT ;
    USE SIGNAL ;
    PORT
      LAYER M4 ;
        RECT  107.916 33.264 108 33.288 ;
    END
  END b_rr0[130]
  PIN b_rr0[131]
    DIRECTION OUTPUT ;
    USE SIGNAL ;
    PORT
      LAYER M4 ;
        RECT  107.916 33.456 108 33.48 ;
    END
  END b_rr0[131]
  PIN b_rr0[132]
    DIRECTION OUTPUT ;
    USE SIGNAL ;
    PORT
      LAYER M4 ;
        RECT  107.916 33.648 108 33.672 ;
    END
  END b_rr0[132]
  PIN b_rr0[133]
    DIRECTION OUTPUT ;
    USE SIGNAL ;
    PORT
      LAYER M4 ;
        RECT  107.916 33.84 108 33.864 ;
    END
  END b_rr0[133]
  PIN b_rr0[134]
    DIRECTION OUTPUT ;
    USE SIGNAL ;
    PORT
      LAYER M4 ;
        RECT  107.916 34.032 108 34.056 ;
    END
  END b_rr0[134]
  PIN b_rr0[135]
    DIRECTION OUTPUT ;
    USE SIGNAL ;
    PORT
      LAYER M4 ;
        RECT  107.916 34.224 108 34.248 ;
    END
  END b_rr0[135]
  PIN b_rr0[136]
    DIRECTION OUTPUT ;
    USE SIGNAL ;
    PORT
      LAYER M4 ;
        RECT  107.916 34.416 108 34.44 ;
    END
  END b_rr0[136]
  PIN b_rr0[137]
    DIRECTION OUTPUT ;
    USE SIGNAL ;
    PORT
      LAYER M4 ;
        RECT  107.916 34.608 108 34.632 ;
    END
  END b_rr0[137]
  PIN b_rr0[138]
    DIRECTION OUTPUT ;
    USE SIGNAL ;
    PORT
      LAYER M4 ;
        RECT  107.916 34.8 108 34.824 ;
    END
  END b_rr0[138]
  PIN b_rr0[139]
    DIRECTION OUTPUT ;
    USE SIGNAL ;
    PORT
      LAYER M4 ;
        RECT  107.916 34.944 108 34.968 ;
    END
  END b_rr0[139]
  PIN b_rr0[13]
    DIRECTION OUTPUT ;
    USE SIGNAL ;
    PORT
      LAYER M4 ;
        RECT  107.916 11.136 108 11.16 ;
    END
  END b_rr0[13]
  PIN b_rr0[140]
    DIRECTION OUTPUT ;
    USE SIGNAL ;
    PORT
      LAYER M4 ;
        RECT  107.916 35.136 108 35.16 ;
    END
  END b_rr0[140]
  PIN b_rr0[141]
    DIRECTION OUTPUT ;
    USE SIGNAL ;
    PORT
      LAYER M4 ;
        RECT  107.916 35.328 108 35.352 ;
    END
  END b_rr0[141]
  PIN b_rr0[142]
    DIRECTION OUTPUT ;
    USE SIGNAL ;
    PORT
      LAYER M4 ;
        RECT  107.916 35.52 108 35.544 ;
    END
  END b_rr0[142]
  PIN b_rr0[143]
    DIRECTION OUTPUT ;
    USE SIGNAL ;
    PORT
      LAYER M4 ;
        RECT  107.916 35.712 108 35.736 ;
    END
  END b_rr0[143]
  PIN b_rr0[144]
    DIRECTION OUTPUT ;
    USE SIGNAL ;
    PORT
      LAYER M4 ;
        RECT  107.916 35.904 108 35.928 ;
    END
  END b_rr0[144]
  PIN b_rr0[145]
    DIRECTION OUTPUT ;
    USE SIGNAL ;
    PORT
      LAYER M4 ;
        RECT  107.916 36.096 108 36.12 ;
    END
  END b_rr0[145]
  PIN b_rr0[146]
    DIRECTION OUTPUT ;
    USE SIGNAL ;
    PORT
      LAYER M4 ;
        RECT  107.916 36.288 108 36.312 ;
    END
  END b_rr0[146]
  PIN b_rr0[147]
    DIRECTION OUTPUT ;
    USE SIGNAL ;
    PORT
      LAYER M4 ;
        RECT  107.916 36.48 108 36.504 ;
    END
  END b_rr0[147]
  PIN b_rr0[148]
    DIRECTION OUTPUT ;
    USE SIGNAL ;
    PORT
      LAYER M4 ;
        RECT  107.916 36.672 108 36.696 ;
    END
  END b_rr0[148]
  PIN b_rr0[149]
    DIRECTION OUTPUT ;
    USE SIGNAL ;
    PORT
      LAYER M4 ;
        RECT  107.916 36.864 108 36.888 ;
    END
  END b_rr0[149]
  PIN b_rr0[14]
    DIRECTION OUTPUT ;
    USE SIGNAL ;
    PORT
      LAYER M4 ;
        RECT  107.916 11.328 108 11.352 ;
    END
  END b_rr0[14]
  PIN b_rr0[150]
    DIRECTION OUTPUT ;
    USE SIGNAL ;
    PORT
      LAYER M4 ;
        RECT  107.916 37.056 108 37.08 ;
    END
  END b_rr0[150]
  PIN b_rr0[151]
    DIRECTION OUTPUT ;
    USE SIGNAL ;
    PORT
      LAYER M4 ;
        RECT  107.916 37.248 108 37.272 ;
    END
  END b_rr0[151]
  PIN b_rr0[152]
    DIRECTION OUTPUT ;
    USE SIGNAL ;
    PORT
      LAYER M4 ;
        RECT  107.916 37.44 108 37.464 ;
    END
  END b_rr0[152]
  PIN b_rr0[153]
    DIRECTION OUTPUT ;
    USE SIGNAL ;
    PORT
      LAYER M4 ;
        RECT  107.916 37.632 108 37.656 ;
    END
  END b_rr0[153]
  PIN b_rr0[154]
    DIRECTION OUTPUT ;
    USE SIGNAL ;
    PORT
      LAYER M4 ;
        RECT  107.916 37.824 108 37.848 ;
    END
  END b_rr0[154]
  PIN b_rr0[155]
    DIRECTION OUTPUT ;
    USE SIGNAL ;
    PORT
      LAYER M4 ;
        RECT  107.916 37.968 108 37.992 ;
    END
  END b_rr0[155]
  PIN b_rr0[156]
    DIRECTION OUTPUT ;
    USE SIGNAL ;
    PORT
      LAYER M4 ;
        RECT  107.916 38.16 108 38.184 ;
    END
  END b_rr0[156]
  PIN b_rr0[157]
    DIRECTION OUTPUT ;
    USE SIGNAL ;
    PORT
      LAYER M4 ;
        RECT  107.916 38.352 108 38.376 ;
    END
  END b_rr0[157]
  PIN b_rr0[158]
    DIRECTION OUTPUT ;
    USE SIGNAL ;
    PORT
      LAYER M4 ;
        RECT  107.916 38.544 108 38.568 ;
    END
  END b_rr0[158]
  PIN b_rr0[159]
    DIRECTION OUTPUT ;
    USE SIGNAL ;
    PORT
      LAYER M4 ;
        RECT  107.916 38.736 108 38.76 ;
    END
  END b_rr0[159]
  PIN b_rr0[15]
    DIRECTION OUTPUT ;
    USE SIGNAL ;
    PORT
      LAYER M4 ;
        RECT  107.916 11.52 108 11.544 ;
    END
  END b_rr0[15]
  PIN b_rr0[160]
    DIRECTION OUTPUT ;
    USE SIGNAL ;
    PORT
      LAYER M4 ;
        RECT  107.916 38.928 108 38.952 ;
    END
  END b_rr0[160]
  PIN b_rr0[161]
    DIRECTION OUTPUT ;
    USE SIGNAL ;
    PORT
      LAYER M4 ;
        RECT  107.916 39.12 108 39.144 ;
    END
  END b_rr0[161]
  PIN b_rr0[162]
    DIRECTION OUTPUT ;
    USE SIGNAL ;
    PORT
      LAYER M4 ;
        RECT  107.916 39.312 108 39.336 ;
    END
  END b_rr0[162]
  PIN b_rr0[163]
    DIRECTION OUTPUT ;
    USE SIGNAL ;
    PORT
      LAYER M4 ;
        RECT  107.916 39.504 108 39.528 ;
    END
  END b_rr0[163]
  PIN b_rr0[164]
    DIRECTION OUTPUT ;
    USE SIGNAL ;
    PORT
      LAYER M4 ;
        RECT  107.916 39.696 108 39.72 ;
    END
  END b_rr0[164]
  PIN b_rr0[165]
    DIRECTION OUTPUT ;
    USE SIGNAL ;
    PORT
      LAYER M4 ;
        RECT  107.916 39.888 108 39.912 ;
    END
  END b_rr0[165]
  PIN b_rr0[166]
    DIRECTION OUTPUT ;
    USE SIGNAL ;
    PORT
      LAYER M4 ;
        RECT  107.916 40.08 108 40.104 ;
    END
  END b_rr0[166]
  PIN b_rr0[167]
    DIRECTION OUTPUT ;
    USE SIGNAL ;
    PORT
      LAYER M4 ;
        RECT  107.916 40.272 108 40.296 ;
    END
  END b_rr0[167]
  PIN b_rr0[168]
    DIRECTION OUTPUT ;
    USE SIGNAL ;
    PORT
      LAYER M4 ;
        RECT  107.916 40.464 108 40.488 ;
    END
  END b_rr0[168]
  PIN b_rr0[169]
    DIRECTION OUTPUT ;
    USE SIGNAL ;
    PORT
      LAYER M4 ;
        RECT  107.916 40.656 108 40.68 ;
    END
  END b_rr0[169]
  PIN b_rr0[16]
    DIRECTION OUTPUT ;
    USE SIGNAL ;
    PORT
      LAYER M4 ;
        RECT  107.916 11.712 108 11.736 ;
    END
  END b_rr0[16]
  PIN b_rr0[170]
    DIRECTION OUTPUT ;
    USE SIGNAL ;
    PORT
      LAYER M4 ;
        RECT  107.916 40.848 108 40.872 ;
    END
  END b_rr0[170]
  PIN b_rr0[171]
    DIRECTION OUTPUT ;
    USE SIGNAL ;
    PORT
      LAYER M4 ;
        RECT  107.916 41.04 108 41.064 ;
    END
  END b_rr0[171]
  PIN b_rr0[172]
    DIRECTION OUTPUT ;
    USE SIGNAL ;
    PORT
      LAYER M4 ;
        RECT  107.916 41.184 108 41.208 ;
    END
  END b_rr0[172]
  PIN b_rr0[173]
    DIRECTION OUTPUT ;
    USE SIGNAL ;
    PORT
      LAYER M4 ;
        RECT  107.916 41.376 108 41.4 ;
    END
  END b_rr0[173]
  PIN b_rr0[174]
    DIRECTION OUTPUT ;
    USE SIGNAL ;
    PORT
      LAYER M4 ;
        RECT  107.916 41.568 108 41.592 ;
    END
  END b_rr0[174]
  PIN b_rr0[175]
    DIRECTION OUTPUT ;
    USE SIGNAL ;
    PORT
      LAYER M4 ;
        RECT  107.916 41.76 108 41.784 ;
    END
  END b_rr0[175]
  PIN b_rr0[176]
    DIRECTION OUTPUT ;
    USE SIGNAL ;
    PORT
      LAYER M4 ;
        RECT  107.916 41.952 108 41.976 ;
    END
  END b_rr0[176]
  PIN b_rr0[177]
    DIRECTION OUTPUT ;
    USE SIGNAL ;
    PORT
      LAYER M4 ;
        RECT  107.916 42.144 108 42.168 ;
    END
  END b_rr0[177]
  PIN b_rr0[178]
    DIRECTION OUTPUT ;
    USE SIGNAL ;
    PORT
      LAYER M4 ;
        RECT  107.916 42.336 108 42.36 ;
    END
  END b_rr0[178]
  PIN b_rr0[179]
    DIRECTION OUTPUT ;
    USE SIGNAL ;
    PORT
      LAYER M4 ;
        RECT  107.916 42.528 108 42.552 ;
    END
  END b_rr0[179]
  PIN b_rr0[17]
    DIRECTION OUTPUT ;
    USE SIGNAL ;
    PORT
      LAYER M4 ;
        RECT  107.916 11.904 108 11.928 ;
    END
  END b_rr0[17]
  PIN b_rr0[180]
    DIRECTION OUTPUT ;
    USE SIGNAL ;
    PORT
      LAYER M4 ;
        RECT  107.916 42.72 108 42.744 ;
    END
  END b_rr0[180]
  PIN b_rr0[181]
    DIRECTION OUTPUT ;
    USE SIGNAL ;
    PORT
      LAYER M4 ;
        RECT  107.916 42.912 108 42.936 ;
    END
  END b_rr0[181]
  PIN b_rr0[182]
    DIRECTION OUTPUT ;
    USE SIGNAL ;
    PORT
      LAYER M4 ;
        RECT  107.916 43.104 108 43.128 ;
    END
  END b_rr0[182]
  PIN b_rr0[183]
    DIRECTION OUTPUT ;
    USE SIGNAL ;
    PORT
      LAYER M4 ;
        RECT  107.916 43.296 108 43.32 ;
    END
  END b_rr0[183]
  PIN b_rr0[184]
    DIRECTION OUTPUT ;
    USE SIGNAL ;
    PORT
      LAYER M4 ;
        RECT  107.916 43.488 108 43.512 ;
    END
  END b_rr0[184]
  PIN b_rr0[185]
    DIRECTION OUTPUT ;
    USE SIGNAL ;
    PORT
      LAYER M4 ;
        RECT  107.916 43.68 108 43.704 ;
    END
  END b_rr0[185]
  PIN b_rr0[186]
    DIRECTION OUTPUT ;
    USE SIGNAL ;
    PORT
      LAYER M4 ;
        RECT  107.916 43.872 108 43.896 ;
    END
  END b_rr0[186]
  PIN b_rr0[187]
    DIRECTION OUTPUT ;
    USE SIGNAL ;
    PORT
      LAYER M4 ;
        RECT  107.916 44.064 108 44.088 ;
    END
  END b_rr0[187]
  PIN b_rr0[188]
    DIRECTION OUTPUT ;
    USE SIGNAL ;
    PORT
      LAYER M4 ;
        RECT  107.916 44.256 108 44.28 ;
    END
  END b_rr0[188]
  PIN b_rr0[189]
    DIRECTION OUTPUT ;
    USE SIGNAL ;
    PORT
      LAYER M4 ;
        RECT  107.916 44.4 108 44.424 ;
    END
  END b_rr0[189]
  PIN b_rr0[18]
    DIRECTION OUTPUT ;
    USE SIGNAL ;
    PORT
      LAYER M4 ;
        RECT  107.916 12.096 108 12.12 ;
    END
  END b_rr0[18]
  PIN b_rr0[190]
    DIRECTION OUTPUT ;
    USE SIGNAL ;
    PORT
      LAYER M4 ;
        RECT  107.916 44.592 108 44.616 ;
    END
  END b_rr0[190]
  PIN b_rr0[191]
    DIRECTION OUTPUT ;
    USE SIGNAL ;
    PORT
      LAYER M4 ;
        RECT  107.916 44.784 108 44.808 ;
    END
  END b_rr0[191]
  PIN b_rr0[192]
    DIRECTION OUTPUT ;
    USE SIGNAL ;
    PORT
      LAYER M4 ;
        RECT  107.916 44.976 108 45 ;
    END
  END b_rr0[192]
  PIN b_rr0[193]
    DIRECTION OUTPUT ;
    USE SIGNAL ;
    PORT
      LAYER M4 ;
        RECT  107.916 45.168 108 45.192 ;
    END
  END b_rr0[193]
  PIN b_rr0[194]
    DIRECTION OUTPUT ;
    USE SIGNAL ;
    PORT
      LAYER M4 ;
        RECT  107.916 45.36 108 45.384 ;
    END
  END b_rr0[194]
  PIN b_rr0[195]
    DIRECTION OUTPUT ;
    USE SIGNAL ;
    PORT
      LAYER M4 ;
        RECT  107.916 45.552 108 45.576 ;
    END
  END b_rr0[195]
  PIN b_rr0[196]
    DIRECTION OUTPUT ;
    USE SIGNAL ;
    PORT
      LAYER M4 ;
        RECT  107.916 45.744 108 45.768 ;
    END
  END b_rr0[196]
  PIN b_rr0[197]
    DIRECTION OUTPUT ;
    USE SIGNAL ;
    PORT
      LAYER M4 ;
        RECT  107.916 45.936 108 45.96 ;
    END
  END b_rr0[197]
  PIN b_rr0[198]
    DIRECTION OUTPUT ;
    USE SIGNAL ;
    PORT
      LAYER M4 ;
        RECT  107.916 46.128 108 46.152 ;
    END
  END b_rr0[198]
  PIN b_rr0[199]
    DIRECTION OUTPUT ;
    USE SIGNAL ;
    PORT
      LAYER M4 ;
        RECT  107.916 46.32 108 46.344 ;
    END
  END b_rr0[199]
  PIN b_rr0[19]
    DIRECTION OUTPUT ;
    USE SIGNAL ;
    PORT
      LAYER M4 ;
        RECT  107.916 12.288 108 12.312 ;
    END
  END b_rr0[19]
  PIN b_rr0[1]
    DIRECTION OUTPUT ;
    USE SIGNAL ;
    PORT
      LAYER M4 ;
        RECT  107.916 8.88 108 8.904 ;
    END
  END b_rr0[1]
  PIN b_rr0[200]
    DIRECTION OUTPUT ;
    USE SIGNAL ;
    PORT
      LAYER M4 ;
        RECT  107.916 46.512 108 46.536 ;
    END
  END b_rr0[200]
  PIN b_rr0[201]
    DIRECTION OUTPUT ;
    USE SIGNAL ;
    PORT
      LAYER M4 ;
        RECT  107.916 46.704 108 46.728 ;
    END
  END b_rr0[201]
  PIN b_rr0[202]
    DIRECTION OUTPUT ;
    USE SIGNAL ;
    PORT
      LAYER M4 ;
        RECT  107.916 46.896 108 46.92 ;
    END
  END b_rr0[202]
  PIN b_rr0[203]
    DIRECTION OUTPUT ;
    USE SIGNAL ;
    PORT
      LAYER M4 ;
        RECT  107.916 47.088 108 47.112 ;
    END
  END b_rr0[203]
  PIN b_rr0[204]
    DIRECTION OUTPUT ;
    USE SIGNAL ;
    PORT
      LAYER M4 ;
        RECT  107.916 47.28 108 47.304 ;
    END
  END b_rr0[204]
  PIN b_rr0[205]
    DIRECTION OUTPUT ;
    USE SIGNAL ;
    PORT
      LAYER M4 ;
        RECT  107.916 47.472 108 47.496 ;
    END
  END b_rr0[205]
  PIN b_rr0[206]
    DIRECTION OUTPUT ;
    USE SIGNAL ;
    PORT
      LAYER M4 ;
        RECT  107.916 47.616 108 47.64 ;
    END
  END b_rr0[206]
  PIN b_rr0[207]
    DIRECTION OUTPUT ;
    USE SIGNAL ;
    PORT
      LAYER M4 ;
        RECT  107.916 47.808 108 47.832 ;
    END
  END b_rr0[207]
  PIN b_rr0[208]
    DIRECTION OUTPUT ;
    USE SIGNAL ;
    PORT
      LAYER M4 ;
        RECT  107.916 48 108 48.024 ;
    END
  END b_rr0[208]
  PIN b_rr0[209]
    DIRECTION OUTPUT ;
    USE SIGNAL ;
    PORT
      LAYER M4 ;
        RECT  107.916 48.192 108 48.216 ;
    END
  END b_rr0[209]
  PIN b_rr0[20]
    DIRECTION OUTPUT ;
    USE SIGNAL ;
    PORT
      LAYER M4 ;
        RECT  107.916 12.48 108 12.504 ;
    END
  END b_rr0[20]
  PIN b_rr0[210]
    DIRECTION OUTPUT ;
    USE SIGNAL ;
    PORT
      LAYER M4 ;
        RECT  107.916 48.384 108 48.408 ;
    END
  END b_rr0[210]
  PIN b_rr0[211]
    DIRECTION OUTPUT ;
    USE SIGNAL ;
    PORT
      LAYER M4 ;
        RECT  107.916 48.576 108 48.6 ;
    END
  END b_rr0[211]
  PIN b_rr0[212]
    DIRECTION OUTPUT ;
    USE SIGNAL ;
    PORT
      LAYER M4 ;
        RECT  107.916 48.768 108 48.792 ;
    END
  END b_rr0[212]
  PIN b_rr0[213]
    DIRECTION OUTPUT ;
    USE SIGNAL ;
    PORT
      LAYER M4 ;
        RECT  107.916 48.96 108 48.984 ;
    END
  END b_rr0[213]
  PIN b_rr0[214]
    DIRECTION OUTPUT ;
    USE SIGNAL ;
    PORT
      LAYER M4 ;
        RECT  107.916 49.152 108 49.176 ;
    END
  END b_rr0[214]
  PIN b_rr0[215]
    DIRECTION OUTPUT ;
    USE SIGNAL ;
    PORT
      LAYER M4 ;
        RECT  107.916 49.344 108 49.368 ;
    END
  END b_rr0[215]
  PIN b_rr0[216]
    DIRECTION OUTPUT ;
    USE SIGNAL ;
    PORT
      LAYER M4 ;
        RECT  107.916 49.536 108 49.56 ;
    END
  END b_rr0[216]
  PIN b_rr0[217]
    DIRECTION OUTPUT ;
    USE SIGNAL ;
    PORT
      LAYER M4 ;
        RECT  107.916 49.728 108 49.752 ;
    END
  END b_rr0[217]
  PIN b_rr0[218]
    DIRECTION OUTPUT ;
    USE SIGNAL ;
    PORT
      LAYER M4 ;
        RECT  107.916 49.92 108 49.944 ;
    END
  END b_rr0[218]
  PIN b_rr0[219]
    DIRECTION OUTPUT ;
    USE SIGNAL ;
    PORT
      LAYER M4 ;
        RECT  107.916 50.112 108 50.136 ;
    END
  END b_rr0[219]
  PIN b_rr0[21]
    DIRECTION OUTPUT ;
    USE SIGNAL ;
    PORT
      LAYER M4 ;
        RECT  107.916 12.624 108 12.648 ;
    END
  END b_rr0[21]
  PIN b_rr0[220]
    DIRECTION OUTPUT ;
    USE SIGNAL ;
    PORT
      LAYER M4 ;
        RECT  107.916 50.304 108 50.328 ;
    END
  END b_rr0[220]
  PIN b_rr0[221]
    DIRECTION OUTPUT ;
    USE SIGNAL ;
    PORT
      LAYER M4 ;
        RECT  107.916 50.496 108 50.52 ;
    END
  END b_rr0[221]
  PIN b_rr0[222]
    DIRECTION OUTPUT ;
    USE SIGNAL ;
    PORT
      LAYER M4 ;
        RECT  107.916 50.64 108 50.664 ;
    END
  END b_rr0[222]
  PIN b_rr0[223]
    DIRECTION OUTPUT ;
    USE SIGNAL ;
    PORT
      LAYER M4 ;
        RECT  107.916 50.832 108 50.856 ;
    END
  END b_rr0[223]
  PIN b_rr0[224]
    DIRECTION OUTPUT ;
    USE SIGNAL ;
    PORT
      LAYER M4 ;
        RECT  107.916 51.024 108 51.048 ;
    END
  END b_rr0[224]
  PIN b_rr0[225]
    DIRECTION OUTPUT ;
    USE SIGNAL ;
    PORT
      LAYER M4 ;
        RECT  107.916 51.216 108 51.24 ;
    END
  END b_rr0[225]
  PIN b_rr0[226]
    DIRECTION OUTPUT ;
    USE SIGNAL ;
    PORT
      LAYER M4 ;
        RECT  107.916 51.408 108 51.432 ;
    END
  END b_rr0[226]
  PIN b_rr0[227]
    DIRECTION OUTPUT ;
    USE SIGNAL ;
    PORT
      LAYER M4 ;
        RECT  107.916 51.6 108 51.624 ;
    END
  END b_rr0[227]
  PIN b_rr0[228]
    DIRECTION OUTPUT ;
    USE SIGNAL ;
    PORT
      LAYER M4 ;
        RECT  107.916 51.792 108 51.816 ;
    END
  END b_rr0[228]
  PIN b_rr0[229]
    DIRECTION OUTPUT ;
    USE SIGNAL ;
    PORT
      LAYER M4 ;
        RECT  107.916 51.984 108 52.008 ;
    END
  END b_rr0[229]
  PIN b_rr0[22]
    DIRECTION OUTPUT ;
    USE SIGNAL ;
    PORT
      LAYER M4 ;
        RECT  107.916 12.816 108 12.84 ;
    END
  END b_rr0[22]
  PIN b_rr0[230]
    DIRECTION OUTPUT ;
    USE SIGNAL ;
    PORT
      LAYER M4 ;
        RECT  107.916 52.176 108 52.2 ;
    END
  END b_rr0[230]
  PIN b_rr0[231]
    DIRECTION OUTPUT ;
    USE SIGNAL ;
    PORT
      LAYER M4 ;
        RECT  107.916 52.368 108 52.392 ;
    END
  END b_rr0[231]
  PIN b_rr0[232]
    DIRECTION OUTPUT ;
    USE SIGNAL ;
    PORT
      LAYER M4 ;
        RECT  107.916 52.56 108 52.584 ;
    END
  END b_rr0[232]
  PIN b_rr0[233]
    DIRECTION OUTPUT ;
    USE SIGNAL ;
    PORT
      LAYER M4 ;
        RECT  107.916 52.752 108 52.776 ;
    END
  END b_rr0[233]
  PIN b_rr0[234]
    DIRECTION OUTPUT ;
    USE SIGNAL ;
    PORT
      LAYER M4 ;
        RECT  107.916 52.944 108 52.968 ;
    END
  END b_rr0[234]
  PIN b_rr0[235]
    DIRECTION OUTPUT ;
    USE SIGNAL ;
    PORT
      LAYER M4 ;
        RECT  107.916 53.136 108 53.16 ;
    END
  END b_rr0[235]
  PIN b_rr0[236]
    DIRECTION OUTPUT ;
    USE SIGNAL ;
    PORT
      LAYER M4 ;
        RECT  107.916 53.328 108 53.352 ;
    END
  END b_rr0[236]
  PIN b_rr0[237]
    DIRECTION OUTPUT ;
    USE SIGNAL ;
    PORT
      LAYER M4 ;
        RECT  107.916 53.52 108 53.544 ;
    END
  END b_rr0[237]
  PIN b_rr0[238]
    DIRECTION OUTPUT ;
    USE SIGNAL ;
    PORT
      LAYER M4 ;
        RECT  107.916 53.712 108 53.736 ;
    END
  END b_rr0[238]
  PIN b_rr0[239]
    DIRECTION OUTPUT ;
    USE SIGNAL ;
    PORT
      LAYER M4 ;
        RECT  107.916 53.856 108 53.88 ;
    END
  END b_rr0[239]
  PIN b_rr0[23]
    DIRECTION OUTPUT ;
    USE SIGNAL ;
    PORT
      LAYER M4 ;
        RECT  107.916 13.008 108 13.032 ;
    END
  END b_rr0[23]
  PIN b_rr0[240]
    DIRECTION OUTPUT ;
    USE SIGNAL ;
    PORT
      LAYER M4 ;
        RECT  107.916 54.048 108 54.072 ;
    END
  END b_rr0[240]
  PIN b_rr0[241]
    DIRECTION OUTPUT ;
    USE SIGNAL ;
    PORT
      LAYER M4 ;
        RECT  107.916 54.24 108 54.264 ;
    END
  END b_rr0[241]
  PIN b_rr0[242]
    DIRECTION OUTPUT ;
    USE SIGNAL ;
    PORT
      LAYER M4 ;
        RECT  107.916 54.432 108 54.456 ;
    END
  END b_rr0[242]
  PIN b_rr0[243]
    DIRECTION OUTPUT ;
    USE SIGNAL ;
    PORT
      LAYER M4 ;
        RECT  107.916 54.624 108 54.648 ;
    END
  END b_rr0[243]
  PIN b_rr0[244]
    DIRECTION OUTPUT ;
    USE SIGNAL ;
    PORT
      LAYER M4 ;
        RECT  107.916 54.816 108 54.84 ;
    END
  END b_rr0[244]
  PIN b_rr0[245]
    DIRECTION OUTPUT ;
    USE SIGNAL ;
    PORT
      LAYER M4 ;
        RECT  107.916 55.008 108 55.032 ;
    END
  END b_rr0[245]
  PIN b_rr0[246]
    DIRECTION OUTPUT ;
    USE SIGNAL ;
    PORT
      LAYER M4 ;
        RECT  107.916 55.2 108 55.224 ;
    END
  END b_rr0[246]
  PIN b_rr0[247]
    DIRECTION OUTPUT ;
    USE SIGNAL ;
    PORT
      LAYER M4 ;
        RECT  107.916 55.392 108 55.416 ;
    END
  END b_rr0[247]
  PIN b_rr0[248]
    DIRECTION OUTPUT ;
    USE SIGNAL ;
    PORT
      LAYER M4 ;
        RECT  107.916 55.584 108 55.608 ;
    END
  END b_rr0[248]
  PIN b_rr0[249]
    DIRECTION OUTPUT ;
    USE SIGNAL ;
    PORT
      LAYER M4 ;
        RECT  107.916 55.776 108 55.8 ;
    END
  END b_rr0[249]
  PIN b_rr0[24]
    DIRECTION OUTPUT ;
    USE SIGNAL ;
    PORT
      LAYER M4 ;
        RECT  107.916 13.2 108 13.224 ;
    END
  END b_rr0[24]
  PIN b_rr0[250]
    DIRECTION OUTPUT ;
    USE SIGNAL ;
    PORT
      LAYER M4 ;
        RECT  107.916 55.968 108 55.992 ;
    END
  END b_rr0[250]
  PIN b_rr0[251]
    DIRECTION OUTPUT ;
    USE SIGNAL ;
    PORT
      LAYER M4 ;
        RECT  107.916 56.16 108 56.184 ;
    END
  END b_rr0[251]
  PIN b_rr0[252]
    DIRECTION OUTPUT ;
    USE SIGNAL ;
    PORT
      LAYER M4 ;
        RECT  107.916 56.352 108 56.376 ;
    END
  END b_rr0[252]
  PIN b_rr0[253]
    DIRECTION OUTPUT ;
    USE SIGNAL ;
    PORT
      LAYER M4 ;
        RECT  107.916 56.544 108 56.568 ;
    END
  END b_rr0[253]
  PIN b_rr0[254]
    DIRECTION OUTPUT ;
    USE SIGNAL ;
    PORT
      LAYER M4 ;
        RECT  107.916 56.736 108 56.76 ;
    END
  END b_rr0[254]
  PIN b_rr0[255]
    DIRECTION OUTPUT ;
    USE SIGNAL ;
    PORT
      LAYER M4 ;
        RECT  107.916 56.928 108 56.952 ;
    END
  END b_rr0[255]
  PIN b_rr0[256]
    DIRECTION OUTPUT ;
    USE SIGNAL ;
    PORT
      LAYER M4 ;
        RECT  107.916 57.072 108 57.096 ;
    END
  END b_rr0[256]
  PIN b_rr0[25]
    DIRECTION OUTPUT ;
    USE SIGNAL ;
    PORT
      LAYER M4 ;
        RECT  107.916 13.392 108 13.416 ;
    END
  END b_rr0[25]
  PIN b_rr0[26]
    DIRECTION OUTPUT ;
    USE SIGNAL ;
    PORT
      LAYER M4 ;
        RECT  107.916 13.584 108 13.608 ;
    END
  END b_rr0[26]
  PIN b_rr0[27]
    DIRECTION OUTPUT ;
    USE SIGNAL ;
    PORT
      LAYER M4 ;
        RECT  107.916 13.776 108 13.8 ;
    END
  END b_rr0[27]
  PIN b_rr0[28]
    DIRECTION OUTPUT ;
    USE SIGNAL ;
    PORT
      LAYER M4 ;
        RECT  107.916 13.968 108 13.992 ;
    END
  END b_rr0[28]
  PIN b_rr0[29]
    DIRECTION OUTPUT ;
    USE SIGNAL ;
    PORT
      LAYER M4 ;
        RECT  107.916 14.16 108 14.184 ;
    END
  END b_rr0[29]
  PIN b_rr0[2]
    DIRECTION OUTPUT ;
    USE SIGNAL ;
    PORT
      LAYER M4 ;
        RECT  107.916 9.072 108 9.096 ;
    END
  END b_rr0[2]
  PIN b_rr0[30]
    DIRECTION OUTPUT ;
    USE SIGNAL ;
    PORT
      LAYER M4 ;
        RECT  107.916 14.352 108 14.376 ;
    END
  END b_rr0[30]
  PIN b_rr0[31]
    DIRECTION OUTPUT ;
    USE SIGNAL ;
    PORT
      LAYER M4 ;
        RECT  107.916 14.544 108 14.568 ;
    END
  END b_rr0[31]
  PIN b_rr0[32]
    DIRECTION OUTPUT ;
    USE SIGNAL ;
    PORT
      LAYER M4 ;
        RECT  107.916 14.736 108 14.76 ;
    END
  END b_rr0[32]
  PIN b_rr0[33]
    DIRECTION OUTPUT ;
    USE SIGNAL ;
    PORT
      LAYER M4 ;
        RECT  107.916 14.928 108 14.952 ;
    END
  END b_rr0[33]
  PIN b_rr0[34]
    DIRECTION OUTPUT ;
    USE SIGNAL ;
    PORT
      LAYER M4 ;
        RECT  107.916 15.12 108 15.144 ;
    END
  END b_rr0[34]
  PIN b_rr0[35]
    DIRECTION OUTPUT ;
    USE SIGNAL ;
    PORT
      LAYER M4 ;
        RECT  107.916 15.312 108 15.336 ;
    END
  END b_rr0[35]
  PIN b_rr0[36]
    DIRECTION OUTPUT ;
    USE SIGNAL ;
    PORT
      LAYER M4 ;
        RECT  107.916 15.504 108 15.528 ;
    END
  END b_rr0[36]
  PIN b_rr0[37]
    DIRECTION OUTPUT ;
    USE SIGNAL ;
    PORT
      LAYER M4 ;
        RECT  107.916 15.696 108 15.72 ;
    END
  END b_rr0[37]
  PIN b_rr0[38]
    DIRECTION OUTPUT ;
    USE SIGNAL ;
    PORT
      LAYER M4 ;
        RECT  107.916 15.84 108 15.864 ;
    END
  END b_rr0[38]
  PIN b_rr0[39]
    DIRECTION OUTPUT ;
    USE SIGNAL ;
    PORT
      LAYER M4 ;
        RECT  107.916 16.032 108 16.056 ;
    END
  END b_rr0[39]
  PIN b_rr0[3]
    DIRECTION OUTPUT ;
    USE SIGNAL ;
    PORT
      LAYER M4 ;
        RECT  107.916 9.264 108 9.288 ;
    END
  END b_rr0[3]
  PIN b_rr0[40]
    DIRECTION OUTPUT ;
    USE SIGNAL ;
    PORT
      LAYER M4 ;
        RECT  107.916 16.224 108 16.248 ;
    END
  END b_rr0[40]
  PIN b_rr0[41]
    DIRECTION OUTPUT ;
    USE SIGNAL ;
    PORT
      LAYER M4 ;
        RECT  107.916 16.416 108 16.44 ;
    END
  END b_rr0[41]
  PIN b_rr0[42]
    DIRECTION OUTPUT ;
    USE SIGNAL ;
    PORT
      LAYER M4 ;
        RECT  107.916 16.608 108 16.632 ;
    END
  END b_rr0[42]
  PIN b_rr0[43]
    DIRECTION OUTPUT ;
    USE SIGNAL ;
    PORT
      LAYER M4 ;
        RECT  107.916 16.8 108 16.824 ;
    END
  END b_rr0[43]
  PIN b_rr0[44]
    DIRECTION OUTPUT ;
    USE SIGNAL ;
    PORT
      LAYER M4 ;
        RECT  107.916 16.992 108 17.016 ;
    END
  END b_rr0[44]
  PIN b_rr0[45]
    DIRECTION OUTPUT ;
    USE SIGNAL ;
    PORT
      LAYER M4 ;
        RECT  107.916 17.184 108 17.208 ;
    END
  END b_rr0[45]
  PIN b_rr0[46]
    DIRECTION OUTPUT ;
    USE SIGNAL ;
    PORT
      LAYER M4 ;
        RECT  107.916 17.376 108 17.4 ;
    END
  END b_rr0[46]
  PIN b_rr0[47]
    DIRECTION OUTPUT ;
    USE SIGNAL ;
    PORT
      LAYER M4 ;
        RECT  107.916 17.568 108 17.592 ;
    END
  END b_rr0[47]
  PIN b_rr0[48]
    DIRECTION OUTPUT ;
    USE SIGNAL ;
    PORT
      LAYER M4 ;
        RECT  107.916 17.76 108 17.784 ;
    END
  END b_rr0[48]
  PIN b_rr0[49]
    DIRECTION OUTPUT ;
    USE SIGNAL ;
    PORT
      LAYER M4 ;
        RECT  107.916 17.952 108 17.976 ;
    END
  END b_rr0[49]
  PIN b_rr0[4]
    DIRECTION OUTPUT ;
    USE SIGNAL ;
    PORT
      LAYER M4 ;
        RECT  107.916 9.456 108 9.48 ;
    END
  END b_rr0[4]
  PIN b_rr0[50]
    DIRECTION OUTPUT ;
    USE SIGNAL ;
    PORT
      LAYER M4 ;
        RECT  107.916 18.144 108 18.168 ;
    END
  END b_rr0[50]
  PIN b_rr0[51]
    DIRECTION OUTPUT ;
    USE SIGNAL ;
    PORT
      LAYER M4 ;
        RECT  107.916 18.336 108 18.36 ;
    END
  END b_rr0[51]
  PIN b_rr0[52]
    DIRECTION OUTPUT ;
    USE SIGNAL ;
    PORT
      LAYER M4 ;
        RECT  107.916 18.528 108 18.552 ;
    END
  END b_rr0[52]
  PIN b_rr0[53]
    DIRECTION OUTPUT ;
    USE SIGNAL ;
    PORT
      LAYER M4 ;
        RECT  107.916 18.72 108 18.744 ;
    END
  END b_rr0[53]
  PIN b_rr0[54]
    DIRECTION OUTPUT ;
    USE SIGNAL ;
    PORT
      LAYER M4 ;
        RECT  107.916 18.912 108 18.936 ;
    END
  END b_rr0[54]
  PIN b_rr0[55]
    DIRECTION OUTPUT ;
    USE SIGNAL ;
    PORT
      LAYER M4 ;
        RECT  107.916 19.056 108 19.08 ;
    END
  END b_rr0[55]
  PIN b_rr0[56]
    DIRECTION OUTPUT ;
    USE SIGNAL ;
    PORT
      LAYER M4 ;
        RECT  107.916 19.248 108 19.272 ;
    END
  END b_rr0[56]
  PIN b_rr0[57]
    DIRECTION OUTPUT ;
    USE SIGNAL ;
    PORT
      LAYER M4 ;
        RECT  107.916 19.44 108 19.464 ;
    END
  END b_rr0[57]
  PIN b_rr0[58]
    DIRECTION OUTPUT ;
    USE SIGNAL ;
    PORT
      LAYER M4 ;
        RECT  107.916 19.632 108 19.656 ;
    END
  END b_rr0[58]
  PIN b_rr0[59]
    DIRECTION OUTPUT ;
    USE SIGNAL ;
    PORT
      LAYER M4 ;
        RECT  107.916 19.824 108 19.848 ;
    END
  END b_rr0[59]
  PIN b_rr0[5]
    DIRECTION OUTPUT ;
    USE SIGNAL ;
    PORT
      LAYER M4 ;
        RECT  107.916 9.6 108 9.624 ;
    END
  END b_rr0[5]
  PIN b_rr0[60]
    DIRECTION OUTPUT ;
    USE SIGNAL ;
    PORT
      LAYER M4 ;
        RECT  107.916 20.016 108 20.04 ;
    END
  END b_rr0[60]
  PIN b_rr0[61]
    DIRECTION OUTPUT ;
    USE SIGNAL ;
    PORT
      LAYER M4 ;
        RECT  107.916 20.208 108 20.232 ;
    END
  END b_rr0[61]
  PIN b_rr0[62]
    DIRECTION OUTPUT ;
    USE SIGNAL ;
    PORT
      LAYER M4 ;
        RECT  107.916 20.4 108 20.424 ;
    END
  END b_rr0[62]
  PIN b_rr0[63]
    DIRECTION OUTPUT ;
    USE SIGNAL ;
    PORT
      LAYER M4 ;
        RECT  107.916 20.592 108 20.616 ;
    END
  END b_rr0[63]
  PIN b_rr0[64]
    DIRECTION OUTPUT ;
    USE SIGNAL ;
    PORT
      LAYER M4 ;
        RECT  107.916 20.784 108 20.808 ;
    END
  END b_rr0[64]
  PIN b_rr0[65]
    DIRECTION OUTPUT ;
    USE SIGNAL ;
    PORT
      LAYER M4 ;
        RECT  107.916 20.976 108 21 ;
    END
  END b_rr0[65]
  PIN b_rr0[66]
    DIRECTION OUTPUT ;
    USE SIGNAL ;
    PORT
      LAYER M4 ;
        RECT  107.916 21.168 108 21.192 ;
    END
  END b_rr0[66]
  PIN b_rr0[67]
    DIRECTION OUTPUT ;
    USE SIGNAL ;
    PORT
      LAYER M4 ;
        RECT  107.916 21.36 108 21.384 ;
    END
  END b_rr0[67]
  PIN b_rr0[68]
    DIRECTION OUTPUT ;
    USE SIGNAL ;
    PORT
      LAYER M4 ;
        RECT  107.916 21.552 108 21.576 ;
    END
  END b_rr0[68]
  PIN b_rr0[69]
    DIRECTION OUTPUT ;
    USE SIGNAL ;
    PORT
      LAYER M4 ;
        RECT  107.916 21.744 108 21.768 ;
    END
  END b_rr0[69]
  PIN b_rr0[6]
    DIRECTION OUTPUT ;
    USE SIGNAL ;
    PORT
      LAYER M4 ;
        RECT  107.916 9.792 108 9.816 ;
    END
  END b_rr0[6]
  PIN b_rr0[70]
    DIRECTION OUTPUT ;
    USE SIGNAL ;
    PORT
      LAYER M4 ;
        RECT  107.916 21.936 108 21.96 ;
    END
  END b_rr0[70]
  PIN b_rr0[71]
    DIRECTION OUTPUT ;
    USE SIGNAL ;
    PORT
      LAYER M4 ;
        RECT  107.916 22.128 108 22.152 ;
    END
  END b_rr0[71]
  PIN b_rr0[72]
    DIRECTION OUTPUT ;
    USE SIGNAL ;
    PORT
      LAYER M4 ;
        RECT  107.916 22.272 108 22.296 ;
    END
  END b_rr0[72]
  PIN b_rr0[73]
    DIRECTION OUTPUT ;
    USE SIGNAL ;
    PORT
      LAYER M4 ;
        RECT  107.916 22.464 108 22.488 ;
    END
  END b_rr0[73]
  PIN b_rr0[74]
    DIRECTION OUTPUT ;
    USE SIGNAL ;
    PORT
      LAYER M4 ;
        RECT  107.916 22.656 108 22.68 ;
    END
  END b_rr0[74]
  PIN b_rr0[75]
    DIRECTION OUTPUT ;
    USE SIGNAL ;
    PORT
      LAYER M4 ;
        RECT  107.916 22.848 108 22.872 ;
    END
  END b_rr0[75]
  PIN b_rr0[76]
    DIRECTION OUTPUT ;
    USE SIGNAL ;
    PORT
      LAYER M4 ;
        RECT  107.916 23.04 108 23.064 ;
    END
  END b_rr0[76]
  PIN b_rr0[77]
    DIRECTION OUTPUT ;
    USE SIGNAL ;
    PORT
      LAYER M4 ;
        RECT  107.916 23.232 108 23.256 ;
    END
  END b_rr0[77]
  PIN b_rr0[78]
    DIRECTION OUTPUT ;
    USE SIGNAL ;
    PORT
      LAYER M4 ;
        RECT  107.916 23.424 108 23.448 ;
    END
  END b_rr0[78]
  PIN b_rr0[79]
    DIRECTION OUTPUT ;
    USE SIGNAL ;
    PORT
      LAYER M4 ;
        RECT  107.916 23.616 108 23.64 ;
    END
  END b_rr0[79]
  PIN b_rr0[7]
    DIRECTION OUTPUT ;
    USE SIGNAL ;
    PORT
      LAYER M4 ;
        RECT  107.916 9.984 108 10.008 ;
    END
  END b_rr0[7]
  PIN b_rr0[80]
    DIRECTION OUTPUT ;
    USE SIGNAL ;
    PORT
      LAYER M4 ;
        RECT  107.916 23.808 108 23.832 ;
    END
  END b_rr0[80]
  PIN b_rr0[81]
    DIRECTION OUTPUT ;
    USE SIGNAL ;
    PORT
      LAYER M4 ;
        RECT  107.916 24 108 24.024 ;
    END
  END b_rr0[81]
  PIN b_rr0[82]
    DIRECTION OUTPUT ;
    USE SIGNAL ;
    PORT
      LAYER M4 ;
        RECT  107.916 24.192 108 24.216 ;
    END
  END b_rr0[82]
  PIN b_rr0[83]
    DIRECTION OUTPUT ;
    USE SIGNAL ;
    PORT
      LAYER M4 ;
        RECT  107.916 24.384 108 24.408 ;
    END
  END b_rr0[83]
  PIN b_rr0[84]
    DIRECTION OUTPUT ;
    USE SIGNAL ;
    PORT
      LAYER M4 ;
        RECT  107.916 24.576 108 24.6 ;
    END
  END b_rr0[84]
  PIN b_rr0[85]
    DIRECTION OUTPUT ;
    USE SIGNAL ;
    PORT
      LAYER M4 ;
        RECT  107.916 24.768 108 24.792 ;
    END
  END b_rr0[85]
  PIN b_rr0[86]
    DIRECTION OUTPUT ;
    USE SIGNAL ;
    PORT
      LAYER M4 ;
        RECT  107.916 24.96 108 24.984 ;
    END
  END b_rr0[86]
  PIN b_rr0[87]
    DIRECTION OUTPUT ;
    USE SIGNAL ;
    PORT
      LAYER M4 ;
        RECT  107.916 25.152 108 25.176 ;
    END
  END b_rr0[87]
  PIN b_rr0[88]
    DIRECTION OUTPUT ;
    USE SIGNAL ;
    PORT
      LAYER M4 ;
        RECT  107.916 25.296 108 25.32 ;
    END
  END b_rr0[88]
  PIN b_rr0[89]
    DIRECTION OUTPUT ;
    USE SIGNAL ;
    PORT
      LAYER M4 ;
        RECT  107.916 25.488 108 25.512 ;
    END
  END b_rr0[89]
  PIN b_rr0[8]
    DIRECTION OUTPUT ;
    USE SIGNAL ;
    PORT
      LAYER M4 ;
        RECT  107.916 10.176 108 10.2 ;
    END
  END b_rr0[8]
  PIN b_rr0[90]
    DIRECTION OUTPUT ;
    USE SIGNAL ;
    PORT
      LAYER M4 ;
        RECT  107.916 25.68 108 25.704 ;
    END
  END b_rr0[90]
  PIN b_rr0[91]
    DIRECTION OUTPUT ;
    USE SIGNAL ;
    PORT
      LAYER M4 ;
        RECT  107.916 25.872 108 25.896 ;
    END
  END b_rr0[91]
  PIN b_rr0[92]
    DIRECTION OUTPUT ;
    USE SIGNAL ;
    PORT
      LAYER M4 ;
        RECT  107.916 26.064 108 26.088 ;
    END
  END b_rr0[92]
  PIN b_rr0[93]
    DIRECTION OUTPUT ;
    USE SIGNAL ;
    PORT
      LAYER M4 ;
        RECT  107.916 26.256 108 26.28 ;
    END
  END b_rr0[93]
  PIN b_rr0[94]
    DIRECTION OUTPUT ;
    USE SIGNAL ;
    PORT
      LAYER M4 ;
        RECT  107.916 26.448 108 26.472 ;
    END
  END b_rr0[94]
  PIN b_rr0[95]
    DIRECTION OUTPUT ;
    USE SIGNAL ;
    PORT
      LAYER M4 ;
        RECT  107.916 26.64 108 26.664 ;
    END
  END b_rr0[95]
  PIN b_rr0[96]
    DIRECTION OUTPUT ;
    USE SIGNAL ;
    PORT
      LAYER M4 ;
        RECT  107.916 26.832 108 26.856 ;
    END
  END b_rr0[96]
  PIN b_rr0[97]
    DIRECTION OUTPUT ;
    USE SIGNAL ;
    PORT
      LAYER M4 ;
        RECT  107.916 27.024 108 27.048 ;
    END
  END b_rr0[97]
  PIN b_rr0[98]
    DIRECTION OUTPUT ;
    USE SIGNAL ;
    PORT
      LAYER M4 ;
        RECT  107.916 27.216 108 27.24 ;
    END
  END b_rr0[98]
  PIN b_rr0[99]
    DIRECTION OUTPUT ;
    USE SIGNAL ;
    PORT
      LAYER M4 ;
        RECT  107.916 27.408 108 27.432 ;
    END
  END b_rr0[99]
  PIN b_rr0[9]
    DIRECTION OUTPUT ;
    USE SIGNAL ;
    PORT
      LAYER M4 ;
        RECT  107.916 10.368 108 10.392 ;
    END
  END b_rr0[9]
  PIN b_rr1[0]
    DIRECTION OUTPUT ;
    USE SIGNAL ;
    PORT
      LAYER M4 ;
        RECT  107.916 57.264 108 57.288 ;
    END
  END b_rr1[0]
  PIN b_rr1[100]
    DIRECTION OUTPUT ;
    USE SIGNAL ;
    PORT
      LAYER M4 ;
        RECT  107.916 76.224 108 76.248 ;
    END
  END b_rr1[100]
  PIN b_rr1[101]
    DIRECTION OUTPUT ;
    USE SIGNAL ;
    PORT
      LAYER M4 ;
        RECT  107.916 76.416 108 76.44 ;
    END
  END b_rr1[101]
  PIN b_rr1[102]
    DIRECTION OUTPUT ;
    USE SIGNAL ;
    PORT
      LAYER M4 ;
        RECT  107.916 76.608 108 76.632 ;
    END
  END b_rr1[102]
  PIN b_rr1[103]
    DIRECTION OUTPUT ;
    USE SIGNAL ;
    PORT
      LAYER M4 ;
        RECT  107.916 76.8 108 76.824 ;
    END
  END b_rr1[103]
  PIN b_rr1[104]
    DIRECTION OUTPUT ;
    USE SIGNAL ;
    PORT
      LAYER M4 ;
        RECT  107.916 76.944 108 76.968 ;
    END
  END b_rr1[104]
  PIN b_rr1[105]
    DIRECTION OUTPUT ;
    USE SIGNAL ;
    PORT
      LAYER M4 ;
        RECT  107.916 77.136 108 77.16 ;
    END
  END b_rr1[105]
  PIN b_rr1[106]
    DIRECTION OUTPUT ;
    USE SIGNAL ;
    PORT
      LAYER M4 ;
        RECT  107.916 77.328 108 77.352 ;
    END
  END b_rr1[106]
  PIN b_rr1[107]
    DIRECTION OUTPUT ;
    USE SIGNAL ;
    PORT
      LAYER M4 ;
        RECT  107.916 77.52 108 77.544 ;
    END
  END b_rr1[107]
  PIN b_rr1[108]
    DIRECTION OUTPUT ;
    USE SIGNAL ;
    PORT
      LAYER M4 ;
        RECT  107.916 77.712 108 77.736 ;
    END
  END b_rr1[108]
  PIN b_rr1[109]
    DIRECTION OUTPUT ;
    USE SIGNAL ;
    PORT
      LAYER M4 ;
        RECT  107.916 77.904 108 77.928 ;
    END
  END b_rr1[109]
  PIN b_rr1[10]
    DIRECTION OUTPUT ;
    USE SIGNAL ;
    PORT
      LAYER M4 ;
        RECT  107.916 59.184 108 59.208 ;
    END
  END b_rr1[10]
  PIN b_rr1[110]
    DIRECTION OUTPUT ;
    USE SIGNAL ;
    PORT
      LAYER M4 ;
        RECT  107.916 78.096 108 78.12 ;
    END
  END b_rr1[110]
  PIN b_rr1[111]
    DIRECTION OUTPUT ;
    USE SIGNAL ;
    PORT
      LAYER M4 ;
        RECT  107.916 78.288 108 78.312 ;
    END
  END b_rr1[111]
  PIN b_rr1[112]
    DIRECTION OUTPUT ;
    USE SIGNAL ;
    PORT
      LAYER M4 ;
        RECT  107.916 78.48 108 78.504 ;
    END
  END b_rr1[112]
  PIN b_rr1[113]
    DIRECTION OUTPUT ;
    USE SIGNAL ;
    PORT
      LAYER M4 ;
        RECT  107.916 78.672 108 78.696 ;
    END
  END b_rr1[113]
  PIN b_rr1[114]
    DIRECTION OUTPUT ;
    USE SIGNAL ;
    PORT
      LAYER M4 ;
        RECT  107.916 78.864 108 78.888 ;
    END
  END b_rr1[114]
  PIN b_rr1[115]
    DIRECTION OUTPUT ;
    USE SIGNAL ;
    PORT
      LAYER M4 ;
        RECT  107.916 79.056 108 79.08 ;
    END
  END b_rr1[115]
  PIN b_rr1[116]
    DIRECTION OUTPUT ;
    USE SIGNAL ;
    PORT
      LAYER M4 ;
        RECT  107.916 79.248 108 79.272 ;
    END
  END b_rr1[116]
  PIN b_rr1[117]
    DIRECTION OUTPUT ;
    USE SIGNAL ;
    PORT
      LAYER M4 ;
        RECT  107.916 79.44 108 79.464 ;
    END
  END b_rr1[117]
  PIN b_rr1[118]
    DIRECTION OUTPUT ;
    USE SIGNAL ;
    PORT
      LAYER M4 ;
        RECT  107.916 79.632 108 79.656 ;
    END
  END b_rr1[118]
  PIN b_rr1[119]
    DIRECTION OUTPUT ;
    USE SIGNAL ;
    PORT
      LAYER M4 ;
        RECT  107.916 79.824 108 79.848 ;
    END
  END b_rr1[119]
  PIN b_rr1[11]
    DIRECTION OUTPUT ;
    USE SIGNAL ;
    PORT
      LAYER M4 ;
        RECT  107.916 59.376 108 59.4 ;
    END
  END b_rr1[11]
  PIN b_rr1[120]
    DIRECTION OUTPUT ;
    USE SIGNAL ;
    PORT
      LAYER M4 ;
        RECT  107.916 80.016 108 80.04 ;
    END
  END b_rr1[120]
  PIN b_rr1[121]
    DIRECTION OUTPUT ;
    USE SIGNAL ;
    PORT
      LAYER M4 ;
        RECT  107.916 80.16 108 80.184 ;
    END
  END b_rr1[121]
  PIN b_rr1[122]
    DIRECTION OUTPUT ;
    USE SIGNAL ;
    PORT
      LAYER M4 ;
        RECT  107.916 80.352 108 80.376 ;
    END
  END b_rr1[122]
  PIN b_rr1[123]
    DIRECTION OUTPUT ;
    USE SIGNAL ;
    PORT
      LAYER M4 ;
        RECT  107.916 80.544 108 80.568 ;
    END
  END b_rr1[123]
  PIN b_rr1[124]
    DIRECTION OUTPUT ;
    USE SIGNAL ;
    PORT
      LAYER M4 ;
        RECT  107.916 80.736 108 80.76 ;
    END
  END b_rr1[124]
  PIN b_rr1[125]
    DIRECTION OUTPUT ;
    USE SIGNAL ;
    PORT
      LAYER M4 ;
        RECT  107.916 80.928 108 80.952 ;
    END
  END b_rr1[125]
  PIN b_rr1[126]
    DIRECTION OUTPUT ;
    USE SIGNAL ;
    PORT
      LAYER M4 ;
        RECT  107.916 81.12 108 81.144 ;
    END
  END b_rr1[126]
  PIN b_rr1[127]
    DIRECTION OUTPUT ;
    USE SIGNAL ;
    PORT
      LAYER M4 ;
        RECT  107.916 81.312 108 81.336 ;
    END
  END b_rr1[127]
  PIN b_rr1[128]
    DIRECTION OUTPUT ;
    USE SIGNAL ;
    PORT
      LAYER M4 ;
        RECT  107.916 81.504 108 81.528 ;
    END
  END b_rr1[128]
  PIN b_rr1[129]
    DIRECTION OUTPUT ;
    USE SIGNAL ;
    PORT
      LAYER M4 ;
        RECT  107.916 81.696 108 81.72 ;
    END
  END b_rr1[129]
  PIN b_rr1[12]
    DIRECTION OUTPUT ;
    USE SIGNAL ;
    PORT
      LAYER M4 ;
        RECT  107.916 59.568 108 59.592 ;
    END
  END b_rr1[12]
  PIN b_rr1[130]
    DIRECTION OUTPUT ;
    USE SIGNAL ;
    PORT
      LAYER M4 ;
        RECT  107.916 81.888 108 81.912 ;
    END
  END b_rr1[130]
  PIN b_rr1[131]
    DIRECTION OUTPUT ;
    USE SIGNAL ;
    PORT
      LAYER M4 ;
        RECT  107.916 82.08 108 82.104 ;
    END
  END b_rr1[131]
  PIN b_rr1[132]
    DIRECTION OUTPUT ;
    USE SIGNAL ;
    PORT
      LAYER M4 ;
        RECT  107.916 82.272 108 82.296 ;
    END
  END b_rr1[132]
  PIN b_rr1[133]
    DIRECTION OUTPUT ;
    USE SIGNAL ;
    PORT
      LAYER M4 ;
        RECT  107.916 82.464 108 82.488 ;
    END
  END b_rr1[133]
  PIN b_rr1[134]
    DIRECTION OUTPUT ;
    USE SIGNAL ;
    PORT
      LAYER M4 ;
        RECT  107.916 82.656 108 82.68 ;
    END
  END b_rr1[134]
  PIN b_rr1[135]
    DIRECTION OUTPUT ;
    USE SIGNAL ;
    PORT
      LAYER M4 ;
        RECT  107.916 82.848 108 82.872 ;
    END
  END b_rr1[135]
  PIN b_rr1[136]
    DIRECTION OUTPUT ;
    USE SIGNAL ;
    PORT
      LAYER M4 ;
        RECT  107.916 83.04 108 83.064 ;
    END
  END b_rr1[136]
  PIN b_rr1[137]
    DIRECTION OUTPUT ;
    USE SIGNAL ;
    PORT
      LAYER M4 ;
        RECT  107.916 83.232 108 83.256 ;
    END
  END b_rr1[137]
  PIN b_rr1[138]
    DIRECTION OUTPUT ;
    USE SIGNAL ;
    PORT
      LAYER M4 ;
        RECT  107.916 83.424 108 83.448 ;
    END
  END b_rr1[138]
  PIN b_rr1[139]
    DIRECTION OUTPUT ;
    USE SIGNAL ;
    PORT
      LAYER M4 ;
        RECT  107.916 83.568 108 83.592 ;
    END
  END b_rr1[139]
  PIN b_rr1[13]
    DIRECTION OUTPUT ;
    USE SIGNAL ;
    PORT
      LAYER M4 ;
        RECT  107.916 59.76 108 59.784 ;
    END
  END b_rr1[13]
  PIN b_rr1[140]
    DIRECTION OUTPUT ;
    USE SIGNAL ;
    PORT
      LAYER M4 ;
        RECT  107.916 83.76 108 83.784 ;
    END
  END b_rr1[140]
  PIN b_rr1[141]
    DIRECTION OUTPUT ;
    USE SIGNAL ;
    PORT
      LAYER M4 ;
        RECT  107.916 83.952 108 83.976 ;
    END
  END b_rr1[141]
  PIN b_rr1[142]
    DIRECTION OUTPUT ;
    USE SIGNAL ;
    PORT
      LAYER M4 ;
        RECT  107.916 84.144 108 84.168 ;
    END
  END b_rr1[142]
  PIN b_rr1[143]
    DIRECTION OUTPUT ;
    USE SIGNAL ;
    PORT
      LAYER M4 ;
        RECT  107.916 84.336 108 84.36 ;
    END
  END b_rr1[143]
  PIN b_rr1[144]
    DIRECTION OUTPUT ;
    USE SIGNAL ;
    PORT
      LAYER M4 ;
        RECT  107.916 84.528 108 84.552 ;
    END
  END b_rr1[144]
  PIN b_rr1[145]
    DIRECTION OUTPUT ;
    USE SIGNAL ;
    PORT
      LAYER M4 ;
        RECT  107.916 84.72 108 84.744 ;
    END
  END b_rr1[145]
  PIN b_rr1[146]
    DIRECTION OUTPUT ;
    USE SIGNAL ;
    PORT
      LAYER M4 ;
        RECT  107.916 84.912 108 84.936 ;
    END
  END b_rr1[146]
  PIN b_rr1[147]
    DIRECTION OUTPUT ;
    USE SIGNAL ;
    PORT
      LAYER M4 ;
        RECT  107.916 85.104 108 85.128 ;
    END
  END b_rr1[147]
  PIN b_rr1[148]
    DIRECTION OUTPUT ;
    USE SIGNAL ;
    PORT
      LAYER M4 ;
        RECT  107.916 85.296 108 85.32 ;
    END
  END b_rr1[148]
  PIN b_rr1[149]
    DIRECTION OUTPUT ;
    USE SIGNAL ;
    PORT
      LAYER M4 ;
        RECT  107.916 85.488 108 85.512 ;
    END
  END b_rr1[149]
  PIN b_rr1[14]
    DIRECTION OUTPUT ;
    USE SIGNAL ;
    PORT
      LAYER M4 ;
        RECT  107.916 59.952 108 59.976 ;
    END
  END b_rr1[14]
  PIN b_rr1[150]
    DIRECTION OUTPUT ;
    USE SIGNAL ;
    PORT
      LAYER M4 ;
        RECT  107.916 85.68 108 85.704 ;
    END
  END b_rr1[150]
  PIN b_rr1[151]
    DIRECTION OUTPUT ;
    USE SIGNAL ;
    PORT
      LAYER M4 ;
        RECT  107.916 85.872 108 85.896 ;
    END
  END b_rr1[151]
  PIN b_rr1[152]
    DIRECTION OUTPUT ;
    USE SIGNAL ;
    PORT
      LAYER M4 ;
        RECT  107.916 86.064 108 86.088 ;
    END
  END b_rr1[152]
  PIN b_rr1[153]
    DIRECTION OUTPUT ;
    USE SIGNAL ;
    PORT
      LAYER M4 ;
        RECT  107.916 86.256 108 86.28 ;
    END
  END b_rr1[153]
  PIN b_rr1[154]
    DIRECTION OUTPUT ;
    USE SIGNAL ;
    PORT
      LAYER M4 ;
        RECT  107.916 86.448 108 86.472 ;
    END
  END b_rr1[154]
  PIN b_rr1[155]
    DIRECTION OUTPUT ;
    USE SIGNAL ;
    PORT
      LAYER M4 ;
        RECT  107.916 86.64 108 86.664 ;
    END
  END b_rr1[155]
  PIN b_rr1[156]
    DIRECTION OUTPUT ;
    USE SIGNAL ;
    PORT
      LAYER M4 ;
        RECT  107.916 86.784 108 86.808 ;
    END
  END b_rr1[156]
  PIN b_rr1[157]
    DIRECTION OUTPUT ;
    USE SIGNAL ;
    PORT
      LAYER M4 ;
        RECT  107.916 86.976 108 87 ;
    END
  END b_rr1[157]
  PIN b_rr1[158]
    DIRECTION OUTPUT ;
    USE SIGNAL ;
    PORT
      LAYER M4 ;
        RECT  107.916 87.168 108 87.192 ;
    END
  END b_rr1[158]
  PIN b_rr1[159]
    DIRECTION OUTPUT ;
    USE SIGNAL ;
    PORT
      LAYER M4 ;
        RECT  107.916 87.36 108 87.384 ;
    END
  END b_rr1[159]
  PIN b_rr1[15]
    DIRECTION OUTPUT ;
    USE SIGNAL ;
    PORT
      LAYER M4 ;
        RECT  107.916 60.144 108 60.168 ;
    END
  END b_rr1[15]
  PIN b_rr1[160]
    DIRECTION OUTPUT ;
    USE SIGNAL ;
    PORT
      LAYER M4 ;
        RECT  107.916 87.552 108 87.576 ;
    END
  END b_rr1[160]
  PIN b_rr1[161]
    DIRECTION OUTPUT ;
    USE SIGNAL ;
    PORT
      LAYER M4 ;
        RECT  107.916 87.744 108 87.768 ;
    END
  END b_rr1[161]
  PIN b_rr1[162]
    DIRECTION OUTPUT ;
    USE SIGNAL ;
    PORT
      LAYER M4 ;
        RECT  107.916 87.936 108 87.96 ;
    END
  END b_rr1[162]
  PIN b_rr1[163]
    DIRECTION OUTPUT ;
    USE SIGNAL ;
    PORT
      LAYER M4 ;
        RECT  107.916 88.128 108 88.152 ;
    END
  END b_rr1[163]
  PIN b_rr1[164]
    DIRECTION OUTPUT ;
    USE SIGNAL ;
    PORT
      LAYER M4 ;
        RECT  107.916 88.32 108 88.344 ;
    END
  END b_rr1[164]
  PIN b_rr1[165]
    DIRECTION OUTPUT ;
    USE SIGNAL ;
    PORT
      LAYER M4 ;
        RECT  107.916 88.512 108 88.536 ;
    END
  END b_rr1[165]
  PIN b_rr1[166]
    DIRECTION OUTPUT ;
    USE SIGNAL ;
    PORT
      LAYER M4 ;
        RECT  107.916 88.704 108 88.728 ;
    END
  END b_rr1[166]
  PIN b_rr1[167]
    DIRECTION OUTPUT ;
    USE SIGNAL ;
    PORT
      LAYER M4 ;
        RECT  107.916 88.896 108 88.92 ;
    END
  END b_rr1[167]
  PIN b_rr1[168]
    DIRECTION OUTPUT ;
    USE SIGNAL ;
    PORT
      LAYER M4 ;
        RECT  107.916 89.088 108 89.112 ;
    END
  END b_rr1[168]
  PIN b_rr1[169]
    DIRECTION OUTPUT ;
    USE SIGNAL ;
    PORT
      LAYER M4 ;
        RECT  107.916 89.28 108 89.304 ;
    END
  END b_rr1[169]
  PIN b_rr1[16]
    DIRECTION OUTPUT ;
    USE SIGNAL ;
    PORT
      LAYER M4 ;
        RECT  107.916 60.288 108 60.312 ;
    END
  END b_rr1[16]
  PIN b_rr1[170]
    DIRECTION OUTPUT ;
    USE SIGNAL ;
    PORT
      LAYER M4 ;
        RECT  107.916 89.472 108 89.496 ;
    END
  END b_rr1[170]
  PIN b_rr1[171]
    DIRECTION OUTPUT ;
    USE SIGNAL ;
    PORT
      LAYER M4 ;
        RECT  107.916 89.664 108 89.688 ;
    END
  END b_rr1[171]
  PIN b_rr1[172]
    DIRECTION OUTPUT ;
    USE SIGNAL ;
    PORT
      LAYER M4 ;
        RECT  107.916 89.856 108 89.88 ;
    END
  END b_rr1[172]
  PIN b_rr1[173]
    DIRECTION OUTPUT ;
    USE SIGNAL ;
    PORT
      LAYER M4 ;
        RECT  107.916 90.048 108 90.072 ;
    END
  END b_rr1[173]
  PIN b_rr1[174]
    DIRECTION OUTPUT ;
    USE SIGNAL ;
    PORT
      LAYER M4 ;
        RECT  107.916 90.192 108 90.216 ;
    END
  END b_rr1[174]
  PIN b_rr1[175]
    DIRECTION OUTPUT ;
    USE SIGNAL ;
    PORT
      LAYER M4 ;
        RECT  107.916 90.384 108 90.408 ;
    END
  END b_rr1[175]
  PIN b_rr1[176]
    DIRECTION OUTPUT ;
    USE SIGNAL ;
    PORT
      LAYER M4 ;
        RECT  107.916 90.576 108 90.6 ;
    END
  END b_rr1[176]
  PIN b_rr1[177]
    DIRECTION OUTPUT ;
    USE SIGNAL ;
    PORT
      LAYER M4 ;
        RECT  107.916 90.768 108 90.792 ;
    END
  END b_rr1[177]
  PIN b_rr1[178]
    DIRECTION OUTPUT ;
    USE SIGNAL ;
    PORT
      LAYER M4 ;
        RECT  107.916 90.96 108 90.984 ;
    END
  END b_rr1[178]
  PIN b_rr1[179]
    DIRECTION OUTPUT ;
    USE SIGNAL ;
    PORT
      LAYER M4 ;
        RECT  107.916 91.152 108 91.176 ;
    END
  END b_rr1[179]
  PIN b_rr1[17]
    DIRECTION OUTPUT ;
    USE SIGNAL ;
    PORT
      LAYER M4 ;
        RECT  107.916 60.48 108 60.504 ;
    END
  END b_rr1[17]
  PIN b_rr1[180]
    DIRECTION OUTPUT ;
    USE SIGNAL ;
    PORT
      LAYER M4 ;
        RECT  107.916 91.344 108 91.368 ;
    END
  END b_rr1[180]
  PIN b_rr1[181]
    DIRECTION OUTPUT ;
    USE SIGNAL ;
    PORT
      LAYER M4 ;
        RECT  107.916 91.536 108 91.56 ;
    END
  END b_rr1[181]
  PIN b_rr1[182]
    DIRECTION OUTPUT ;
    USE SIGNAL ;
    PORT
      LAYER M4 ;
        RECT  107.916 91.728 108 91.752 ;
    END
  END b_rr1[182]
  PIN b_rr1[183]
    DIRECTION OUTPUT ;
    USE SIGNAL ;
    PORT
      LAYER M4 ;
        RECT  107.916 91.92 108 91.944 ;
    END
  END b_rr1[183]
  PIN b_rr1[184]
    DIRECTION OUTPUT ;
    USE SIGNAL ;
    PORT
      LAYER M4 ;
        RECT  107.916 92.112 108 92.136 ;
    END
  END b_rr1[184]
  PIN b_rr1[185]
    DIRECTION OUTPUT ;
    USE SIGNAL ;
    PORT
      LAYER M4 ;
        RECT  107.916 92.304 108 92.328 ;
    END
  END b_rr1[185]
  PIN b_rr1[186]
    DIRECTION OUTPUT ;
    USE SIGNAL ;
    PORT
      LAYER M4 ;
        RECT  107.916 92.496 108 92.52 ;
    END
  END b_rr1[186]
  PIN b_rr1[187]
    DIRECTION OUTPUT ;
    USE SIGNAL ;
    PORT
      LAYER M4 ;
        RECT  107.916 92.688 108 92.712 ;
    END
  END b_rr1[187]
  PIN b_rr1[188]
    DIRECTION OUTPUT ;
    USE SIGNAL ;
    PORT
      LAYER M4 ;
        RECT  107.916 92.88 108 92.904 ;
    END
  END b_rr1[188]
  PIN b_rr1[189]
    DIRECTION OUTPUT ;
    USE SIGNAL ;
    PORT
      LAYER M4 ;
        RECT  107.916 93.072 108 93.096 ;
    END
  END b_rr1[189]
  PIN b_rr1[18]
    DIRECTION OUTPUT ;
    USE SIGNAL ;
    PORT
      LAYER M4 ;
        RECT  107.916 60.672 108 60.696 ;
    END
  END b_rr1[18]
  PIN b_rr1[190]
    DIRECTION OUTPUT ;
    USE SIGNAL ;
    PORT
      LAYER M4 ;
        RECT  107.916 93.264 108 93.288 ;
    END
  END b_rr1[190]
  PIN b_rr1[191]
    DIRECTION OUTPUT ;
    USE SIGNAL ;
    PORT
      LAYER M4 ;
        RECT  107.916 93.408 108 93.432 ;
    END
  END b_rr1[191]
  PIN b_rr1[192]
    DIRECTION OUTPUT ;
    USE SIGNAL ;
    PORT
      LAYER M4 ;
        RECT  107.916 93.6 108 93.624 ;
    END
  END b_rr1[192]
  PIN b_rr1[193]
    DIRECTION OUTPUT ;
    USE SIGNAL ;
    PORT
      LAYER M4 ;
        RECT  107.916 93.792 108 93.816 ;
    END
  END b_rr1[193]
  PIN b_rr1[194]
    DIRECTION OUTPUT ;
    USE SIGNAL ;
    PORT
      LAYER M4 ;
        RECT  107.916 93.984 108 94.008 ;
    END
  END b_rr1[194]
  PIN b_rr1[195]
    DIRECTION OUTPUT ;
    USE SIGNAL ;
    PORT
      LAYER M4 ;
        RECT  107.916 94.176 108 94.2 ;
    END
  END b_rr1[195]
  PIN b_rr1[196]
    DIRECTION OUTPUT ;
    USE SIGNAL ;
    PORT
      LAYER M4 ;
        RECT  107.916 94.368 108 94.392 ;
    END
  END b_rr1[196]
  PIN b_rr1[197]
    DIRECTION OUTPUT ;
    USE SIGNAL ;
    PORT
      LAYER M4 ;
        RECT  107.916 94.56 108 94.584 ;
    END
  END b_rr1[197]
  PIN b_rr1[198]
    DIRECTION OUTPUT ;
    USE SIGNAL ;
    PORT
      LAYER M4 ;
        RECT  107.916 94.752 108 94.776 ;
    END
  END b_rr1[198]
  PIN b_rr1[199]
    DIRECTION OUTPUT ;
    USE SIGNAL ;
    PORT
      LAYER M4 ;
        RECT  107.916 94.944 108 94.968 ;
    END
  END b_rr1[199]
  PIN b_rr1[19]
    DIRECTION OUTPUT ;
    USE SIGNAL ;
    PORT
      LAYER M4 ;
        RECT  107.916 60.864 108 60.888 ;
    END
  END b_rr1[19]
  PIN b_rr1[1]
    DIRECTION OUTPUT ;
    USE SIGNAL ;
    PORT
      LAYER M4 ;
        RECT  107.916 57.456 108 57.48 ;
    END
  END b_rr1[1]
  PIN b_rr1[200]
    DIRECTION OUTPUT ;
    USE SIGNAL ;
    PORT
      LAYER M4 ;
        RECT  107.916 95.136 108 95.16 ;
    END
  END b_rr1[200]
  PIN b_rr1[201]
    DIRECTION OUTPUT ;
    USE SIGNAL ;
    PORT
      LAYER M4 ;
        RECT  107.916 95.328 108 95.352 ;
    END
  END b_rr1[201]
  PIN b_rr1[202]
    DIRECTION OUTPUT ;
    USE SIGNAL ;
    PORT
      LAYER M4 ;
        RECT  107.916 95.52 108 95.544 ;
    END
  END b_rr1[202]
  PIN b_rr1[203]
    DIRECTION OUTPUT ;
    USE SIGNAL ;
    PORT
      LAYER M4 ;
        RECT  107.916 95.712 108 95.736 ;
    END
  END b_rr1[203]
  PIN b_rr1[204]
    DIRECTION OUTPUT ;
    USE SIGNAL ;
    PORT
      LAYER M4 ;
        RECT  107.916 95.904 108 95.928 ;
    END
  END b_rr1[204]
  PIN b_rr1[205]
    DIRECTION OUTPUT ;
    USE SIGNAL ;
    PORT
      LAYER M4 ;
        RECT  107.916 96.096 108 96.12 ;
    END
  END b_rr1[205]
  PIN b_rr1[206]
    DIRECTION OUTPUT ;
    USE SIGNAL ;
    PORT
      LAYER M4 ;
        RECT  107.916 96.288 108 96.312 ;
    END
  END b_rr1[206]
  PIN b_rr1[207]
    DIRECTION OUTPUT ;
    USE SIGNAL ;
    PORT
      LAYER M4 ;
        RECT  107.916 96.48 108 96.504 ;
    END
  END b_rr1[207]
  PIN b_rr1[208]
    DIRECTION OUTPUT ;
    USE SIGNAL ;
    PORT
      LAYER M4 ;
        RECT  107.916 96.672 108 96.696 ;
    END
  END b_rr1[208]
  PIN b_rr1[209]
    DIRECTION OUTPUT ;
    USE SIGNAL ;
    PORT
      LAYER M4 ;
        RECT  107.916 96.816 108 96.84 ;
    END
  END b_rr1[209]
  PIN b_rr1[20]
    DIRECTION OUTPUT ;
    USE SIGNAL ;
    PORT
      LAYER M4 ;
        RECT  107.916 61.056 108 61.08 ;
    END
  END b_rr1[20]
  PIN b_rr1[210]
    DIRECTION OUTPUT ;
    USE SIGNAL ;
    PORT
      LAYER M4 ;
        RECT  107.916 97.008 108 97.032 ;
    END
  END b_rr1[210]
  PIN b_rr1[211]
    DIRECTION OUTPUT ;
    USE SIGNAL ;
    PORT
      LAYER M4 ;
        RECT  107.916 97.2 108 97.224 ;
    END
  END b_rr1[211]
  PIN b_rr1[212]
    DIRECTION OUTPUT ;
    USE SIGNAL ;
    PORT
      LAYER M4 ;
        RECT  107.916 97.392 108 97.416 ;
    END
  END b_rr1[212]
  PIN b_rr1[213]
    DIRECTION OUTPUT ;
    USE SIGNAL ;
    PORT
      LAYER M4 ;
        RECT  107.916 97.584 108 97.608 ;
    END
  END b_rr1[213]
  PIN b_rr1[214]
    DIRECTION OUTPUT ;
    USE SIGNAL ;
    PORT
      LAYER M4 ;
        RECT  107.916 97.776 108 97.8 ;
    END
  END b_rr1[214]
  PIN b_rr1[215]
    DIRECTION OUTPUT ;
    USE SIGNAL ;
    PORT
      LAYER M4 ;
        RECT  107.916 97.968 108 97.992 ;
    END
  END b_rr1[215]
  PIN b_rr1[216]
    DIRECTION OUTPUT ;
    USE SIGNAL ;
    PORT
      LAYER M4 ;
        RECT  107.916 98.16 108 98.184 ;
    END
  END b_rr1[216]
  PIN b_rr1[217]
    DIRECTION OUTPUT ;
    USE SIGNAL ;
    PORT
      LAYER M4 ;
        RECT  107.916 98.352 108 98.376 ;
    END
  END b_rr1[217]
  PIN b_rr1[218]
    DIRECTION OUTPUT ;
    USE SIGNAL ;
    PORT
      LAYER M4 ;
        RECT  107.916 98.544 108 98.568 ;
    END
  END b_rr1[218]
  PIN b_rr1[219]
    DIRECTION OUTPUT ;
    USE SIGNAL ;
    PORT
      LAYER M4 ;
        RECT  107.916 98.736 108 98.76 ;
    END
  END b_rr1[219]
  PIN b_rr1[21]
    DIRECTION OUTPUT ;
    USE SIGNAL ;
    PORT
      LAYER M4 ;
        RECT  107.916 61.248 108 61.272 ;
    END
  END b_rr1[21]
  PIN b_rr1[220]
    DIRECTION OUTPUT ;
    USE SIGNAL ;
    PORT
      LAYER M4 ;
        RECT  107.916 98.928 108 98.952 ;
    END
  END b_rr1[220]
  PIN b_rr1[221]
    DIRECTION OUTPUT ;
    USE SIGNAL ;
    PORT
      LAYER M4 ;
        RECT  107.916 99.12 108 99.144 ;
    END
  END b_rr1[221]
  PIN b_rr1[222]
    DIRECTION OUTPUT ;
    USE SIGNAL ;
    PORT
      LAYER M4 ;
        RECT  107.916 99.312 108 99.336 ;
    END
  END b_rr1[222]
  PIN b_rr1[223]
    DIRECTION OUTPUT ;
    USE SIGNAL ;
    PORT
      LAYER M4 ;
        RECT  107.916 99.504 108 99.528 ;
    END
  END b_rr1[223]
  PIN b_rr1[224]
    DIRECTION OUTPUT ;
    USE SIGNAL ;
    PORT
      LAYER M4 ;
        RECT  107.916 99.696 108 99.72 ;
    END
  END b_rr1[224]
  PIN b_rr1[225]
    DIRECTION OUTPUT ;
    USE SIGNAL ;
    PORT
      LAYER M4 ;
        RECT  107.916 99.888 108 99.912 ;
    END
  END b_rr1[225]
  PIN b_rr1[226]
    DIRECTION OUTPUT ;
    USE SIGNAL ;
    PORT
      LAYER M4 ;
        RECT  107.916 100.08 108 100.104 ;
    END
  END b_rr1[226]
  PIN b_rr1[227]
    DIRECTION OUTPUT ;
    USE SIGNAL ;
    PORT
      LAYER M4 ;
        RECT  107.916 100.224 108 100.248 ;
    END
  END b_rr1[227]
  PIN b_rr1[228]
    DIRECTION OUTPUT ;
    USE SIGNAL ;
    PORT
      LAYER M4 ;
        RECT  107.916 100.416 108 100.44 ;
    END
  END b_rr1[228]
  PIN b_rr1[229]
    DIRECTION OUTPUT ;
    USE SIGNAL ;
    PORT
      LAYER M4 ;
        RECT  107.916 100.608 108 100.632 ;
    END
  END b_rr1[229]
  PIN b_rr1[22]
    DIRECTION OUTPUT ;
    USE SIGNAL ;
    PORT
      LAYER M4 ;
        RECT  107.916 61.44 108 61.464 ;
    END
  END b_rr1[22]
  PIN b_rr1[230]
    DIRECTION OUTPUT ;
    USE SIGNAL ;
    PORT
      LAYER M4 ;
        RECT  107.916 100.8 108 100.824 ;
    END
  END b_rr1[230]
  PIN b_rr1[231]
    DIRECTION OUTPUT ;
    USE SIGNAL ;
    PORT
      LAYER M4 ;
        RECT  107.916 100.992 108 101.016 ;
    END
  END b_rr1[231]
  PIN b_rr1[232]
    DIRECTION OUTPUT ;
    USE SIGNAL ;
    PORT
      LAYER M4 ;
        RECT  107.916 101.184 108 101.208 ;
    END
  END b_rr1[232]
  PIN b_rr1[233]
    DIRECTION OUTPUT ;
    USE SIGNAL ;
    PORT
      LAYER M4 ;
        RECT  107.916 101.376 108 101.4 ;
    END
  END b_rr1[233]
  PIN b_rr1[234]
    DIRECTION OUTPUT ;
    USE SIGNAL ;
    PORT
      LAYER M4 ;
        RECT  107.916 101.568 108 101.592 ;
    END
  END b_rr1[234]
  PIN b_rr1[235]
    DIRECTION OUTPUT ;
    USE SIGNAL ;
    PORT
      LAYER M4 ;
        RECT  107.916 101.76 108 101.784 ;
    END
  END b_rr1[235]
  PIN b_rr1[236]
    DIRECTION OUTPUT ;
    USE SIGNAL ;
    PORT
      LAYER M4 ;
        RECT  107.916 101.952 108 101.976 ;
    END
  END b_rr1[236]
  PIN b_rr1[237]
    DIRECTION OUTPUT ;
    USE SIGNAL ;
    PORT
      LAYER M4 ;
        RECT  107.916 102.144 108 102.168 ;
    END
  END b_rr1[237]
  PIN b_rr1[238]
    DIRECTION OUTPUT ;
    USE SIGNAL ;
    PORT
      LAYER M4 ;
        RECT  107.916 102.336 108 102.36 ;
    END
  END b_rr1[238]
  PIN b_rr1[239]
    DIRECTION OUTPUT ;
    USE SIGNAL ;
    PORT
      LAYER M4 ;
        RECT  107.916 102.528 108 102.552 ;
    END
  END b_rr1[239]
  PIN b_rr1[23]
    DIRECTION OUTPUT ;
    USE SIGNAL ;
    PORT
      LAYER M4 ;
        RECT  107.916 61.632 108 61.656 ;
    END
  END b_rr1[23]
  PIN b_rr1[240]
    DIRECTION OUTPUT ;
    USE SIGNAL ;
    PORT
      LAYER M4 ;
        RECT  107.916 102.72 108 102.744 ;
    END
  END b_rr1[240]
  PIN b_rr1[241]
    DIRECTION OUTPUT ;
    USE SIGNAL ;
    PORT
      LAYER M4 ;
        RECT  107.916 102.912 108 102.936 ;
    END
  END b_rr1[241]
  PIN b_rr1[242]
    DIRECTION OUTPUT ;
    USE SIGNAL ;
    PORT
      LAYER M4 ;
        RECT  107.916 103.104 108 103.128 ;
    END
  END b_rr1[242]
  PIN b_rr1[243]
    DIRECTION OUTPUT ;
    USE SIGNAL ;
    PORT
      LAYER M4 ;
        RECT  107.916 103.296 108 103.32 ;
    END
  END b_rr1[243]
  PIN b_rr1[244]
    DIRECTION OUTPUT ;
    USE SIGNAL ;
    PORT
      LAYER M4 ;
        RECT  107.916 103.44 108 103.464 ;
    END
  END b_rr1[244]
  PIN b_rr1[245]
    DIRECTION OUTPUT ;
    USE SIGNAL ;
    PORT
      LAYER M4 ;
        RECT  107.916 103.632 108 103.656 ;
    END
  END b_rr1[245]
  PIN b_rr1[246]
    DIRECTION OUTPUT ;
    USE SIGNAL ;
    PORT
      LAYER M4 ;
        RECT  107.916 103.824 108 103.848 ;
    END
  END b_rr1[246]
  PIN b_rr1[247]
    DIRECTION OUTPUT ;
    USE SIGNAL ;
    PORT
      LAYER M4 ;
        RECT  107.916 104.016 108 104.04 ;
    END
  END b_rr1[247]
  PIN b_rr1[248]
    DIRECTION OUTPUT ;
    USE SIGNAL ;
    PORT
      LAYER M4 ;
        RECT  107.916 104.208 108 104.232 ;
    END
  END b_rr1[248]
  PIN b_rr1[249]
    DIRECTION OUTPUT ;
    USE SIGNAL ;
    PORT
      LAYER M4 ;
        RECT  107.916 104.4 108 104.424 ;
    END
  END b_rr1[249]
  PIN b_rr1[24]
    DIRECTION OUTPUT ;
    USE SIGNAL ;
    PORT
      LAYER M4 ;
        RECT  107.916 61.824 108 61.848 ;
    END
  END b_rr1[24]
  PIN b_rr1[250]
    DIRECTION OUTPUT ;
    USE SIGNAL ;
    PORT
      LAYER M4 ;
        RECT  107.916 104.592 108 104.616 ;
    END
  END b_rr1[250]
  PIN b_rr1[251]
    DIRECTION OUTPUT ;
    USE SIGNAL ;
    PORT
      LAYER M4 ;
        RECT  107.916 104.784 108 104.808 ;
    END
  END b_rr1[251]
  PIN b_rr1[252]
    DIRECTION OUTPUT ;
    USE SIGNAL ;
    PORT
      LAYER M4 ;
        RECT  107.916 104.976 108 105 ;
    END
  END b_rr1[252]
  PIN b_rr1[253]
    DIRECTION OUTPUT ;
    USE SIGNAL ;
    PORT
      LAYER M4 ;
        RECT  107.916 105.168 108 105.192 ;
    END
  END b_rr1[253]
  PIN b_rr1[254]
    DIRECTION OUTPUT ;
    USE SIGNAL ;
    PORT
      LAYER M4 ;
        RECT  107.916 105.36 108 105.384 ;
    END
  END b_rr1[254]
  PIN b_rr1[255]
    DIRECTION OUTPUT ;
    USE SIGNAL ;
    PORT
      LAYER M4 ;
        RECT  107.916 105.552 108 105.576 ;
    END
  END b_rr1[255]
  PIN b_rr1[256]
    DIRECTION OUTPUT ;
    USE SIGNAL ;
    PORT
      LAYER M4 ;
        RECT  107.916 105.744 108 105.768 ;
    END
  END b_rr1[256]
  PIN b_rr1[25]
    DIRECTION OUTPUT ;
    USE SIGNAL ;
    PORT
      LAYER M4 ;
        RECT  107.916 62.016 108 62.04 ;
    END
  END b_rr1[25]
  PIN b_rr1[26]
    DIRECTION OUTPUT ;
    USE SIGNAL ;
    PORT
      LAYER M4 ;
        RECT  107.916 62.208 108 62.232 ;
    END
  END b_rr1[26]
  PIN b_rr1[27]
    DIRECTION OUTPUT ;
    USE SIGNAL ;
    PORT
      LAYER M4 ;
        RECT  107.916 62.4 108 62.424 ;
    END
  END b_rr1[27]
  PIN b_rr1[28]
    DIRECTION OUTPUT ;
    USE SIGNAL ;
    PORT
      LAYER M4 ;
        RECT  107.916 62.592 108 62.616 ;
    END
  END b_rr1[28]
  PIN b_rr1[29]
    DIRECTION OUTPUT ;
    USE SIGNAL ;
    PORT
      LAYER M4 ;
        RECT  107.916 62.784 108 62.808 ;
    END
  END b_rr1[29]
  PIN b_rr1[2]
    DIRECTION OUTPUT ;
    USE SIGNAL ;
    PORT
      LAYER M4 ;
        RECT  107.916 57.648 108 57.672 ;
    END
  END b_rr1[2]
  PIN b_rr1[30]
    DIRECTION OUTPUT ;
    USE SIGNAL ;
    PORT
      LAYER M4 ;
        RECT  107.916 62.976 108 63 ;
    END
  END b_rr1[30]
  PIN b_rr1[31]
    DIRECTION OUTPUT ;
    USE SIGNAL ;
    PORT
      LAYER M4 ;
        RECT  107.916 63.168 108 63.192 ;
    END
  END b_rr1[31]
  PIN b_rr1[32]
    DIRECTION OUTPUT ;
    USE SIGNAL ;
    PORT
      LAYER M4 ;
        RECT  107.916 63.36 108 63.384 ;
    END
  END b_rr1[32]
  PIN b_rr1[33]
    DIRECTION OUTPUT ;
    USE SIGNAL ;
    PORT
      LAYER M4 ;
        RECT  107.916 63.552 108 63.576 ;
    END
  END b_rr1[33]
  PIN b_rr1[34]
    DIRECTION OUTPUT ;
    USE SIGNAL ;
    PORT
      LAYER M4 ;
        RECT  107.916 63.696 108 63.72 ;
    END
  END b_rr1[34]
  PIN b_rr1[35]
    DIRECTION OUTPUT ;
    USE SIGNAL ;
    PORT
      LAYER M4 ;
        RECT  107.916 63.888 108 63.912 ;
    END
  END b_rr1[35]
  PIN b_rr1[36]
    DIRECTION OUTPUT ;
    USE SIGNAL ;
    PORT
      LAYER M4 ;
        RECT  107.916 64.08 108 64.104 ;
    END
  END b_rr1[36]
  PIN b_rr1[37]
    DIRECTION OUTPUT ;
    USE SIGNAL ;
    PORT
      LAYER M4 ;
        RECT  107.916 64.272 108 64.296 ;
    END
  END b_rr1[37]
  PIN b_rr1[38]
    DIRECTION OUTPUT ;
    USE SIGNAL ;
    PORT
      LAYER M4 ;
        RECT  107.916 64.464 108 64.488 ;
    END
  END b_rr1[38]
  PIN b_rr1[39]
    DIRECTION OUTPUT ;
    USE SIGNAL ;
    PORT
      LAYER M4 ;
        RECT  107.916 64.656 108 64.68 ;
    END
  END b_rr1[39]
  PIN b_rr1[3]
    DIRECTION OUTPUT ;
    USE SIGNAL ;
    PORT
      LAYER M4 ;
        RECT  107.916 57.84 108 57.864 ;
    END
  END b_rr1[3]
  PIN b_rr1[40]
    DIRECTION OUTPUT ;
    USE SIGNAL ;
    PORT
      LAYER M4 ;
        RECT  107.916 64.848 108 64.872 ;
    END
  END b_rr1[40]
  PIN b_rr1[41]
    DIRECTION OUTPUT ;
    USE SIGNAL ;
    PORT
      LAYER M4 ;
        RECT  107.916 65.04 108 65.064 ;
    END
  END b_rr1[41]
  PIN b_rr1[42]
    DIRECTION OUTPUT ;
    USE SIGNAL ;
    PORT
      LAYER M4 ;
        RECT  107.916 65.232 108 65.256 ;
    END
  END b_rr1[42]
  PIN b_rr1[43]
    DIRECTION OUTPUT ;
    USE SIGNAL ;
    PORT
      LAYER M4 ;
        RECT  107.916 65.424 108 65.448 ;
    END
  END b_rr1[43]
  PIN b_rr1[44]
    DIRECTION OUTPUT ;
    USE SIGNAL ;
    PORT
      LAYER M4 ;
        RECT  107.916 65.616 108 65.64 ;
    END
  END b_rr1[44]
  PIN b_rr1[45]
    DIRECTION OUTPUT ;
    USE SIGNAL ;
    PORT
      LAYER M4 ;
        RECT  107.916 65.808 108 65.832 ;
    END
  END b_rr1[45]
  PIN b_rr1[46]
    DIRECTION OUTPUT ;
    USE SIGNAL ;
    PORT
      LAYER M4 ;
        RECT  107.916 66 108 66.024 ;
    END
  END b_rr1[46]
  PIN b_rr1[47]
    DIRECTION OUTPUT ;
    USE SIGNAL ;
    PORT
      LAYER M4 ;
        RECT  107.916 66.192 108 66.216 ;
    END
  END b_rr1[47]
  PIN b_rr1[48]
    DIRECTION OUTPUT ;
    USE SIGNAL ;
    PORT
      LAYER M4 ;
        RECT  107.916 66.384 108 66.408 ;
    END
  END b_rr1[48]
  PIN b_rr1[49]
    DIRECTION OUTPUT ;
    USE SIGNAL ;
    PORT
      LAYER M4 ;
        RECT  107.916 66.576 108 66.6 ;
    END
  END b_rr1[49]
  PIN b_rr1[4]
    DIRECTION OUTPUT ;
    USE SIGNAL ;
    PORT
      LAYER M4 ;
        RECT  107.916 58.032 108 58.056 ;
    END
  END b_rr1[4]
  PIN b_rr1[50]
    DIRECTION OUTPUT ;
    USE SIGNAL ;
    PORT
      LAYER M4 ;
        RECT  107.916 66.768 108 66.792 ;
    END
  END b_rr1[50]
  PIN b_rr1[51]
    DIRECTION OUTPUT ;
    USE SIGNAL ;
    PORT
      LAYER M4 ;
        RECT  107.916 66.912 108 66.936 ;
    END
  END b_rr1[51]
  PIN b_rr1[52]
    DIRECTION OUTPUT ;
    USE SIGNAL ;
    PORT
      LAYER M4 ;
        RECT  107.916 67.104 108 67.128 ;
    END
  END b_rr1[52]
  PIN b_rr1[53]
    DIRECTION OUTPUT ;
    USE SIGNAL ;
    PORT
      LAYER M4 ;
        RECT  107.916 67.296 108 67.32 ;
    END
  END b_rr1[53]
  PIN b_rr1[54]
    DIRECTION OUTPUT ;
    USE SIGNAL ;
    PORT
      LAYER M4 ;
        RECT  107.916 67.488 108 67.512 ;
    END
  END b_rr1[54]
  PIN b_rr1[55]
    DIRECTION OUTPUT ;
    USE SIGNAL ;
    PORT
      LAYER M4 ;
        RECT  107.916 67.68 108 67.704 ;
    END
  END b_rr1[55]
  PIN b_rr1[56]
    DIRECTION OUTPUT ;
    USE SIGNAL ;
    PORT
      LAYER M4 ;
        RECT  107.916 67.872 108 67.896 ;
    END
  END b_rr1[56]
  PIN b_rr1[57]
    DIRECTION OUTPUT ;
    USE SIGNAL ;
    PORT
      LAYER M4 ;
        RECT  107.916 68.064 108 68.088 ;
    END
  END b_rr1[57]
  PIN b_rr1[58]
    DIRECTION OUTPUT ;
    USE SIGNAL ;
    PORT
      LAYER M4 ;
        RECT  107.916 68.256 108 68.28 ;
    END
  END b_rr1[58]
  PIN b_rr1[59]
    DIRECTION OUTPUT ;
    USE SIGNAL ;
    PORT
      LAYER M4 ;
        RECT  107.916 68.448 108 68.472 ;
    END
  END b_rr1[59]
  PIN b_rr1[5]
    DIRECTION OUTPUT ;
    USE SIGNAL ;
    PORT
      LAYER M4 ;
        RECT  107.916 58.224 108 58.248 ;
    END
  END b_rr1[5]
  PIN b_rr1[60]
    DIRECTION OUTPUT ;
    USE SIGNAL ;
    PORT
      LAYER M4 ;
        RECT  107.916 68.64 108 68.664 ;
    END
  END b_rr1[60]
  PIN b_rr1[61]
    DIRECTION OUTPUT ;
    USE SIGNAL ;
    PORT
      LAYER M4 ;
        RECT  107.916 68.832 108 68.856 ;
    END
  END b_rr1[61]
  PIN b_rr1[62]
    DIRECTION OUTPUT ;
    USE SIGNAL ;
    PORT
      LAYER M4 ;
        RECT  107.916 69.024 108 69.048 ;
    END
  END b_rr1[62]
  PIN b_rr1[63]
    DIRECTION OUTPUT ;
    USE SIGNAL ;
    PORT
      LAYER M4 ;
        RECT  107.916 69.216 108 69.24 ;
    END
  END b_rr1[63]
  PIN b_rr1[64]
    DIRECTION OUTPUT ;
    USE SIGNAL ;
    PORT
      LAYER M4 ;
        RECT  107.916 69.408 108 69.432 ;
    END
  END b_rr1[64]
  PIN b_rr1[65]
    DIRECTION OUTPUT ;
    USE SIGNAL ;
    PORT
      LAYER M4 ;
        RECT  107.916 69.6 108 69.624 ;
    END
  END b_rr1[65]
  PIN b_rr1[66]
    DIRECTION OUTPUT ;
    USE SIGNAL ;
    PORT
      LAYER M4 ;
        RECT  107.916 69.792 108 69.816 ;
    END
  END b_rr1[66]
  PIN b_rr1[67]
    DIRECTION OUTPUT ;
    USE SIGNAL ;
    PORT
      LAYER M4 ;
        RECT  107.916 69.984 108 70.008 ;
    END
  END b_rr1[67]
  PIN b_rr1[68]
    DIRECTION OUTPUT ;
    USE SIGNAL ;
    PORT
      LAYER M4 ;
        RECT  107.916 70.176 108 70.2 ;
    END
  END b_rr1[68]
  PIN b_rr1[69]
    DIRECTION OUTPUT ;
    USE SIGNAL ;
    PORT
      LAYER M4 ;
        RECT  107.916 70.32 108 70.344 ;
    END
  END b_rr1[69]
  PIN b_rr1[6]
    DIRECTION OUTPUT ;
    USE SIGNAL ;
    PORT
      LAYER M4 ;
        RECT  107.916 58.416 108 58.44 ;
    END
  END b_rr1[6]
  PIN b_rr1[70]
    DIRECTION OUTPUT ;
    USE SIGNAL ;
    PORT
      LAYER M4 ;
        RECT  107.916 70.512 108 70.536 ;
    END
  END b_rr1[70]
  PIN b_rr1[71]
    DIRECTION OUTPUT ;
    USE SIGNAL ;
    PORT
      LAYER M4 ;
        RECT  107.916 70.704 108 70.728 ;
    END
  END b_rr1[71]
  PIN b_rr1[72]
    DIRECTION OUTPUT ;
    USE SIGNAL ;
    PORT
      LAYER M4 ;
        RECT  107.916 70.896 108 70.92 ;
    END
  END b_rr1[72]
  PIN b_rr1[73]
    DIRECTION OUTPUT ;
    USE SIGNAL ;
    PORT
      LAYER M4 ;
        RECT  107.916 71.088 108 71.112 ;
    END
  END b_rr1[73]
  PIN b_rr1[74]
    DIRECTION OUTPUT ;
    USE SIGNAL ;
    PORT
      LAYER M4 ;
        RECT  107.916 71.28 108 71.304 ;
    END
  END b_rr1[74]
  PIN b_rr1[75]
    DIRECTION OUTPUT ;
    USE SIGNAL ;
    PORT
      LAYER M4 ;
        RECT  107.916 71.472 108 71.496 ;
    END
  END b_rr1[75]
  PIN b_rr1[76]
    DIRECTION OUTPUT ;
    USE SIGNAL ;
    PORT
      LAYER M4 ;
        RECT  107.916 71.664 108 71.688 ;
    END
  END b_rr1[76]
  PIN b_rr1[77]
    DIRECTION OUTPUT ;
    USE SIGNAL ;
    PORT
      LAYER M4 ;
        RECT  107.916 71.856 108 71.88 ;
    END
  END b_rr1[77]
  PIN b_rr1[78]
    DIRECTION OUTPUT ;
    USE SIGNAL ;
    PORT
      LAYER M4 ;
        RECT  107.916 72.048 108 72.072 ;
    END
  END b_rr1[78]
  PIN b_rr1[79]
    DIRECTION OUTPUT ;
    USE SIGNAL ;
    PORT
      LAYER M4 ;
        RECT  107.916 72.24 108 72.264 ;
    END
  END b_rr1[79]
  PIN b_rr1[7]
    DIRECTION OUTPUT ;
    USE SIGNAL ;
    PORT
      LAYER M4 ;
        RECT  107.916 58.608 108 58.632 ;
    END
  END b_rr1[7]
  PIN b_rr1[80]
    DIRECTION OUTPUT ;
    USE SIGNAL ;
    PORT
      LAYER M4 ;
        RECT  107.916 72.432 108 72.456 ;
    END
  END b_rr1[80]
  PIN b_rr1[81]
    DIRECTION OUTPUT ;
    USE SIGNAL ;
    PORT
      LAYER M4 ;
        RECT  107.916 72.624 108 72.648 ;
    END
  END b_rr1[81]
  PIN b_rr1[82]
    DIRECTION OUTPUT ;
    USE SIGNAL ;
    PORT
      LAYER M4 ;
        RECT  107.916 72.816 108 72.84 ;
    END
  END b_rr1[82]
  PIN b_rr1[83]
    DIRECTION OUTPUT ;
    USE SIGNAL ;
    PORT
      LAYER M4 ;
        RECT  107.916 73.008 108 73.032 ;
    END
  END b_rr1[83]
  PIN b_rr1[84]
    DIRECTION OUTPUT ;
    USE SIGNAL ;
    PORT
      LAYER M4 ;
        RECT  107.916 73.2 108 73.224 ;
    END
  END b_rr1[84]
  PIN b_rr1[85]
    DIRECTION OUTPUT ;
    USE SIGNAL ;
    PORT
      LAYER M4 ;
        RECT  107.916 73.392 108 73.416 ;
    END
  END b_rr1[85]
  PIN b_rr1[86]
    DIRECTION OUTPUT ;
    USE SIGNAL ;
    PORT
      LAYER M4 ;
        RECT  107.916 73.536 108 73.56 ;
    END
  END b_rr1[86]
  PIN b_rr1[87]
    DIRECTION OUTPUT ;
    USE SIGNAL ;
    PORT
      LAYER M4 ;
        RECT  107.916 73.728 108 73.752 ;
    END
  END b_rr1[87]
  PIN b_rr1[88]
    DIRECTION OUTPUT ;
    USE SIGNAL ;
    PORT
      LAYER M4 ;
        RECT  107.916 73.92 108 73.944 ;
    END
  END b_rr1[88]
  PIN b_rr1[89]
    DIRECTION OUTPUT ;
    USE SIGNAL ;
    PORT
      LAYER M4 ;
        RECT  107.916 74.112 108 74.136 ;
    END
  END b_rr1[89]
  PIN b_rr1[8]
    DIRECTION OUTPUT ;
    USE SIGNAL ;
    PORT
      LAYER M4 ;
        RECT  107.916 58.8 108 58.824 ;
    END
  END b_rr1[8]
  PIN b_rr1[90]
    DIRECTION OUTPUT ;
    USE SIGNAL ;
    PORT
      LAYER M4 ;
        RECT  107.916 74.304 108 74.328 ;
    END
  END b_rr1[90]
  PIN b_rr1[91]
    DIRECTION OUTPUT ;
    USE SIGNAL ;
    PORT
      LAYER M4 ;
        RECT  107.916 74.496 108 74.52 ;
    END
  END b_rr1[91]
  PIN b_rr1[92]
    DIRECTION OUTPUT ;
    USE SIGNAL ;
    PORT
      LAYER M4 ;
        RECT  107.916 74.688 108 74.712 ;
    END
  END b_rr1[92]
  PIN b_rr1[93]
    DIRECTION OUTPUT ;
    USE SIGNAL ;
    PORT
      LAYER M4 ;
        RECT  107.916 74.88 108 74.904 ;
    END
  END b_rr1[93]
  PIN b_rr1[94]
    DIRECTION OUTPUT ;
    USE SIGNAL ;
    PORT
      LAYER M4 ;
        RECT  107.916 75.072 108 75.096 ;
    END
  END b_rr1[94]
  PIN b_rr1[95]
    DIRECTION OUTPUT ;
    USE SIGNAL ;
    PORT
      LAYER M4 ;
        RECT  107.916 75.264 108 75.288 ;
    END
  END b_rr1[95]
  PIN b_rr1[96]
    DIRECTION OUTPUT ;
    USE SIGNAL ;
    PORT
      LAYER M4 ;
        RECT  107.916 75.456 108 75.48 ;
    END
  END b_rr1[96]
  PIN b_rr1[97]
    DIRECTION OUTPUT ;
    USE SIGNAL ;
    PORT
      LAYER M4 ;
        RECT  107.916 75.648 108 75.672 ;
    END
  END b_rr1[97]
  PIN b_rr1[98]
    DIRECTION OUTPUT ;
    USE SIGNAL ;
    PORT
      LAYER M4 ;
        RECT  107.916 75.84 108 75.864 ;
    END
  END b_rr1[98]
  PIN b_rr1[99]
    DIRECTION OUTPUT ;
    USE SIGNAL ;
    PORT
      LAYER M4 ;
        RECT  107.916 76.032 108 76.056 ;
    END
  END b_rr1[99]
  PIN b_rr1[9]
    DIRECTION OUTPUT ;
    USE SIGNAL ;
    PORT
      LAYER M4 ;
        RECT  107.916 58.992 108 59.016 ;
    END
  END b_rr1[9]
  PIN clk
    DIRECTION INPUT ;
    USE SIGNAL ;
    PORT
      LAYER M5 ;
        RECT  53.952 107.916 53.976 108 ;
    END
  END clk
  PIN fault
    DIRECTION OUTPUT ;
    USE SIGNAL ;
    PORT
      LAYER M5 ;
        RECT  54.144 107.916 54.168 108 ;
    END
  END fault
  PIN rst_n
    DIRECTION INPUT ;
    USE SIGNAL ;
    PORT
      LAYER M5 ;
        RECT  54.048 107.916 54.072 108 ;
    END
  END rst_n
  PIN vm_rq[0]
    DIRECTION OUTPUT ;
    USE SIGNAL ;
    PORT
      LAYER M5 ;
        RECT  50.88 0 50.904 0.084 ;
    END
  END vm_rq[0]
  PIN vm_rq[10]
    DIRECTION OUTPUT ;
    USE SIGNAL ;
    PORT
      LAYER M5 ;
        RECT  52.752 0 52.776 0.084 ;
    END
  END vm_rq[10]
  PIN vm_rq[11]
    DIRECTION OUTPUT ;
    USE SIGNAL ;
    PORT
      LAYER M5 ;
        RECT  52.944 0 52.968 0.084 ;
    END
  END vm_rq[11]
  PIN vm_rq[12]
    DIRECTION OUTPUT ;
    USE SIGNAL ;
    PORT
      LAYER M5 ;
        RECT  53.136 0 53.16 0.084 ;
    END
  END vm_rq[12]
  PIN vm_rq[13]
    DIRECTION OUTPUT ;
    USE SIGNAL ;
    PORT
      LAYER M5 ;
        RECT  53.328 0 53.352 0.084 ;
    END
  END vm_rq[13]
  PIN vm_rq[14]
    DIRECTION OUTPUT ;
    USE SIGNAL ;
    PORT
      LAYER M5 ;
        RECT  53.52 0 53.544 0.084 ;
    END
  END vm_rq[14]
  PIN vm_rq[15]
    DIRECTION OUTPUT ;
    USE SIGNAL ;
    PORT
      LAYER M5 ;
        RECT  53.712 0 53.736 0.084 ;
    END
  END vm_rq[15]
  PIN vm_rq[16]
    DIRECTION OUTPUT ;
    USE SIGNAL ;
    PORT
      LAYER M5 ;
        RECT  53.904 0 53.928 0.084 ;
    END
  END vm_rq[16]
  PIN vm_rq[17]
    DIRECTION OUTPUT ;
    USE SIGNAL ;
    PORT
      LAYER M5 ;
        RECT  54.096 0 54.12 0.084 ;
    END
  END vm_rq[17]
  PIN vm_rq[18]
    DIRECTION OUTPUT ;
    USE SIGNAL ;
    PORT
      LAYER M5 ;
        RECT  54.288 0 54.312 0.084 ;
    END
  END vm_rq[18]
  PIN vm_rq[19]
    DIRECTION OUTPUT ;
    USE SIGNAL ;
    PORT
      LAYER M5 ;
        RECT  54.48 0 54.504 0.084 ;
    END
  END vm_rq[19]
  PIN vm_rq[1]
    DIRECTION OUTPUT ;
    USE SIGNAL ;
    PORT
      LAYER M5 ;
        RECT  51.072 0 51.096 0.084 ;
    END
  END vm_rq[1]
  PIN vm_rq[20]
    DIRECTION OUTPUT ;
    USE SIGNAL ;
    PORT
      LAYER M5 ;
        RECT  54.624 0 54.648 0.084 ;
    END
  END vm_rq[20]
  PIN vm_rq[21]
    DIRECTION OUTPUT ;
    USE SIGNAL ;
    PORT
      LAYER M5 ;
        RECT  54.816 0 54.84 0.084 ;
    END
  END vm_rq[21]
  PIN vm_rq[22]
    DIRECTION OUTPUT ;
    USE SIGNAL ;
    PORT
      LAYER M5 ;
        RECT  55.008 0 55.032 0.084 ;
    END
  END vm_rq[22]
  PIN vm_rq[23]
    DIRECTION OUTPUT ;
    USE SIGNAL ;
    PORT
      LAYER M5 ;
        RECT  55.2 0 55.224 0.084 ;
    END
  END vm_rq[23]
  PIN vm_rq[24]
    DIRECTION OUTPUT ;
    USE SIGNAL ;
    PORT
      LAYER M5 ;
        RECT  55.392 0 55.416 0.084 ;
    END
  END vm_rq[24]
  PIN vm_rq[25]
    DIRECTION OUTPUT ;
    USE SIGNAL ;
    PORT
      LAYER M5 ;
        RECT  55.584 0 55.608 0.084 ;
    END
  END vm_rq[25]
  PIN vm_rq[26]
    DIRECTION OUTPUT ;
    USE SIGNAL ;
    PORT
      LAYER M5 ;
        RECT  55.776 0 55.8 0.084 ;
    END
  END vm_rq[26]
  PIN vm_rq[27]
    DIRECTION OUTPUT ;
    USE SIGNAL ;
    PORT
      LAYER M5 ;
        RECT  55.968 0 55.992 0.084 ;
    END
  END vm_rq[27]
  PIN vm_rq[28]
    DIRECTION OUTPUT ;
    USE SIGNAL ;
    PORT
      LAYER M5 ;
        RECT  56.16 0 56.184 0.084 ;
    END
  END vm_rq[28]
  PIN vm_rq[29]
    DIRECTION OUTPUT ;
    USE SIGNAL ;
    PORT
      LAYER M5 ;
        RECT  56.352 0 56.376 0.084 ;
    END
  END vm_rq[29]
  PIN vm_rq[2]
    DIRECTION OUTPUT ;
    USE SIGNAL ;
    PORT
      LAYER M5 ;
        RECT  51.264 0 51.288 0.084 ;
    END
  END vm_rq[2]
  PIN vm_rq[30]
    DIRECTION OUTPUT ;
    USE SIGNAL ;
    PORT
      LAYER M5 ;
        RECT  56.544 0 56.568 0.084 ;
    END
  END vm_rq[30]
  PIN vm_rq[31]
    DIRECTION OUTPUT ;
    USE SIGNAL ;
    PORT
      LAYER M5 ;
        RECT  56.736 0 56.76 0.084 ;
    END
  END vm_rq[31]
  PIN vm_rq[32]
    DIRECTION OUTPUT ;
    USE SIGNAL ;
    PORT
      LAYER M5 ;
        RECT  56.928 0 56.952 0.084 ;
    END
  END vm_rq[32]
  PIN vm_rq[33]
    DIRECTION OUTPUT ;
    USE SIGNAL ;
    PORT
      LAYER M5 ;
        RECT  57.072 0 57.096 0.084 ;
    END
  END vm_rq[33]
  PIN vm_rq[3]
    DIRECTION OUTPUT ;
    USE SIGNAL ;
    PORT
      LAYER M5 ;
        RECT  51.456 0 51.48 0.084 ;
    END
  END vm_rq[3]
  PIN vm_rq[4]
    DIRECTION OUTPUT ;
    USE SIGNAL ;
    PORT
      LAYER M5 ;
        RECT  51.648 0 51.672 0.084 ;
    END
  END vm_rq[4]
  PIN vm_rq[5]
    DIRECTION OUTPUT ;
    USE SIGNAL ;
    PORT
      LAYER M5 ;
        RECT  51.84 0 51.864 0.084 ;
    END
  END vm_rq[5]
  PIN vm_rq[6]
    DIRECTION OUTPUT ;
    USE SIGNAL ;
    PORT
      LAYER M5 ;
        RECT  52.032 0 52.056 0.084 ;
    END
  END vm_rq[6]
  PIN vm_rq[7]
    DIRECTION OUTPUT ;
    USE SIGNAL ;
    PORT
      LAYER M5 ;
        RECT  52.224 0 52.248 0.084 ;
    END
  END vm_rq[7]
  PIN vm_rq[8]
    DIRECTION OUTPUT ;
    USE SIGNAL ;
    PORT
      LAYER M5 ;
        RECT  52.368 0 52.392 0.084 ;
    END
  END vm_rq[8]
  PIN vm_rq[9]
    DIRECTION OUTPUT ;
    USE SIGNAL ;
    PORT
      LAYER M5 ;
        RECT  52.56 0 52.584 0.084 ;
    END
  END vm_rq[9]
  PIN vm_rr0[0]
    DIRECTION INPUT ;
    USE SIGNAL ;
    PORT
      LAYER M5 ;
        RECT  2.256 0 2.28 0.084 ;
    END
  END vm_rr0[0]
  PIN vm_rr0[100]
    DIRECTION INPUT ;
    USE SIGNAL ;
    PORT
      LAYER M5 ;
        RECT  21.168 0 21.192 0.084 ;
    END
  END vm_rr0[100]
  PIN vm_rr0[101]
    DIRECTION INPUT ;
    USE SIGNAL ;
    PORT
      LAYER M5 ;
        RECT  21.36 0 21.384 0.084 ;
    END
  END vm_rr0[101]
  PIN vm_rr0[102]
    DIRECTION INPUT ;
    USE SIGNAL ;
    PORT
      LAYER M5 ;
        RECT  21.552 0 21.576 0.084 ;
    END
  END vm_rr0[102]
  PIN vm_rr0[103]
    DIRECTION INPUT ;
    USE SIGNAL ;
    PORT
      LAYER M5 ;
        RECT  21.744 0 21.768 0.084 ;
    END
  END vm_rr0[103]
  PIN vm_rr0[104]
    DIRECTION INPUT ;
    USE SIGNAL ;
    PORT
      LAYER M5 ;
        RECT  21.936 0 21.96 0.084 ;
    END
  END vm_rr0[104]
  PIN vm_rr0[105]
    DIRECTION INPUT ;
    USE SIGNAL ;
    PORT
      LAYER M5 ;
        RECT  22.128 0 22.152 0.084 ;
    END
  END vm_rr0[105]
  PIN vm_rr0[106]
    DIRECTION INPUT ;
    USE SIGNAL ;
    PORT
      LAYER M5 ;
        RECT  22.32 0 22.344 0.084 ;
    END
  END vm_rr0[106]
  PIN vm_rr0[107]
    DIRECTION INPUT ;
    USE SIGNAL ;
    PORT
      LAYER M5 ;
        RECT  22.512 0 22.536 0.084 ;
    END
  END vm_rr0[107]
  PIN vm_rr0[108]
    DIRECTION INPUT ;
    USE SIGNAL ;
    PORT
      LAYER M5 ;
        RECT  22.704 0 22.728 0.084 ;
    END
  END vm_rr0[108]
  PIN vm_rr0[109]
    DIRECTION INPUT ;
    USE SIGNAL ;
    PORT
      LAYER M5 ;
        RECT  22.896 0 22.92 0.084 ;
    END
  END vm_rr0[109]
  PIN vm_rr0[10]
    DIRECTION INPUT ;
    USE SIGNAL ;
    PORT
      LAYER M5 ;
        RECT  4.128 0 4.152 0.084 ;
    END
  END vm_rr0[10]
  PIN vm_rr0[110]
    DIRECTION INPUT ;
    USE SIGNAL ;
    PORT
      LAYER M5 ;
        RECT  23.04 0 23.064 0.084 ;
    END
  END vm_rr0[110]
  PIN vm_rr0[111]
    DIRECTION INPUT ;
    USE SIGNAL ;
    PORT
      LAYER M5 ;
        RECT  23.232 0 23.256 0.084 ;
    END
  END vm_rr0[111]
  PIN vm_rr0[112]
    DIRECTION INPUT ;
    USE SIGNAL ;
    PORT
      LAYER M5 ;
        RECT  23.424 0 23.448 0.084 ;
    END
  END vm_rr0[112]
  PIN vm_rr0[113]
    DIRECTION INPUT ;
    USE SIGNAL ;
    PORT
      LAYER M5 ;
        RECT  23.616 0 23.64 0.084 ;
    END
  END vm_rr0[113]
  PIN vm_rr0[114]
    DIRECTION INPUT ;
    USE SIGNAL ;
    PORT
      LAYER M5 ;
        RECT  23.808 0 23.832 0.084 ;
    END
  END vm_rr0[114]
  PIN vm_rr0[115]
    DIRECTION INPUT ;
    USE SIGNAL ;
    PORT
      LAYER M5 ;
        RECT  24 0 24.024 0.084 ;
    END
  END vm_rr0[115]
  PIN vm_rr0[116]
    DIRECTION INPUT ;
    USE SIGNAL ;
    PORT
      LAYER M5 ;
        RECT  24.192 0 24.216 0.084 ;
    END
  END vm_rr0[116]
  PIN vm_rr0[117]
    DIRECTION INPUT ;
    USE SIGNAL ;
    PORT
      LAYER M5 ;
        RECT  24.384 0 24.408 0.084 ;
    END
  END vm_rr0[117]
  PIN vm_rr0[118]
    DIRECTION INPUT ;
    USE SIGNAL ;
    PORT
      LAYER M5 ;
        RECT  24.576 0 24.6 0.084 ;
    END
  END vm_rr0[118]
  PIN vm_rr0[119]
    DIRECTION INPUT ;
    USE SIGNAL ;
    PORT
      LAYER M5 ;
        RECT  24.768 0 24.792 0.084 ;
    END
  END vm_rr0[119]
  PIN vm_rr0[11]
    DIRECTION INPUT ;
    USE SIGNAL ;
    PORT
      LAYER M5 ;
        RECT  4.32 0 4.344 0.084 ;
    END
  END vm_rr0[11]
  PIN vm_rr0[120]
    DIRECTION INPUT ;
    USE SIGNAL ;
    PORT
      LAYER M5 ;
        RECT  24.96 0 24.984 0.084 ;
    END
  END vm_rr0[120]
  PIN vm_rr0[121]
    DIRECTION INPUT ;
    USE SIGNAL ;
    PORT
      LAYER M5 ;
        RECT  25.152 0 25.176 0.084 ;
    END
  END vm_rr0[121]
  PIN vm_rr0[122]
    DIRECTION INPUT ;
    USE SIGNAL ;
    PORT
      LAYER M5 ;
        RECT  25.344 0 25.368 0.084 ;
    END
  END vm_rr0[122]
  PIN vm_rr0[123]
    DIRECTION INPUT ;
    USE SIGNAL ;
    PORT
      LAYER M5 ;
        RECT  25.536 0 25.56 0.084 ;
    END
  END vm_rr0[123]
  PIN vm_rr0[124]
    DIRECTION INPUT ;
    USE SIGNAL ;
    PORT
      LAYER M5 ;
        RECT  25.728 0 25.752 0.084 ;
    END
  END vm_rr0[124]
  PIN vm_rr0[125]
    DIRECTION INPUT ;
    USE SIGNAL ;
    PORT
      LAYER M5 ;
        RECT  25.92 0 25.944 0.084 ;
    END
  END vm_rr0[125]
  PIN vm_rr0[126]
    DIRECTION INPUT ;
    USE SIGNAL ;
    PORT
      LAYER M5 ;
        RECT  26.112 0 26.136 0.084 ;
    END
  END vm_rr0[126]
  PIN vm_rr0[127]
    DIRECTION INPUT ;
    USE SIGNAL ;
    PORT
      LAYER M5 ;
        RECT  26.256 0 26.28 0.084 ;
    END
  END vm_rr0[127]
  PIN vm_rr0[128]
    DIRECTION INPUT ;
    USE SIGNAL ;
    PORT
      LAYER M5 ;
        RECT  26.448 0 26.472 0.084 ;
    END
  END vm_rr0[128]
  PIN vm_rr0[129]
    DIRECTION INPUT ;
    USE SIGNAL ;
    PORT
      LAYER M5 ;
        RECT  26.64 0 26.664 0.084 ;
    END
  END vm_rr0[129]
  PIN vm_rr0[12]
    DIRECTION INPUT ;
    USE SIGNAL ;
    PORT
      LAYER M5 ;
        RECT  4.512 0 4.536 0.084 ;
    END
  END vm_rr0[12]
  PIN vm_rr0[130]
    DIRECTION INPUT ;
    USE SIGNAL ;
    PORT
      LAYER M5 ;
        RECT  26.832 0 26.856 0.084 ;
    END
  END vm_rr0[130]
  PIN vm_rr0[131]
    DIRECTION INPUT ;
    USE SIGNAL ;
    PORT
      LAYER M5 ;
        RECT  27.024 0 27.048 0.084 ;
    END
  END vm_rr0[131]
  PIN vm_rr0[132]
    DIRECTION INPUT ;
    USE SIGNAL ;
    PORT
      LAYER M5 ;
        RECT  27.216 0 27.24 0.084 ;
    END
  END vm_rr0[132]
  PIN vm_rr0[133]
    DIRECTION INPUT ;
    USE SIGNAL ;
    PORT
      LAYER M5 ;
        RECT  27.408 0 27.432 0.084 ;
    END
  END vm_rr0[133]
  PIN vm_rr0[134]
    DIRECTION INPUT ;
    USE SIGNAL ;
    PORT
      LAYER M5 ;
        RECT  27.6 0 27.624 0.084 ;
    END
  END vm_rr0[134]
  PIN vm_rr0[135]
    DIRECTION INPUT ;
    USE SIGNAL ;
    PORT
      LAYER M5 ;
        RECT  27.792 0 27.816 0.084 ;
    END
  END vm_rr0[135]
  PIN vm_rr0[136]
    DIRECTION INPUT ;
    USE SIGNAL ;
    PORT
      LAYER M5 ;
        RECT  27.984 0 28.008 0.084 ;
    END
  END vm_rr0[136]
  PIN vm_rr0[137]
    DIRECTION INPUT ;
    USE SIGNAL ;
    PORT
      LAYER M5 ;
        RECT  28.176 0 28.2 0.084 ;
    END
  END vm_rr0[137]
  PIN vm_rr0[138]
    DIRECTION INPUT ;
    USE SIGNAL ;
    PORT
      LAYER M5 ;
        RECT  28.368 0 28.392 0.084 ;
    END
  END vm_rr0[138]
  PIN vm_rr0[139]
    DIRECTION INPUT ;
    USE SIGNAL ;
    PORT
      LAYER M5 ;
        RECT  28.56 0 28.584 0.084 ;
    END
  END vm_rr0[139]
  PIN vm_rr0[13]
    DIRECTION INPUT ;
    USE SIGNAL ;
    PORT
      LAYER M5 ;
        RECT  4.704 0 4.728 0.084 ;
    END
  END vm_rr0[13]
  PIN vm_rr0[140]
    DIRECTION INPUT ;
    USE SIGNAL ;
    PORT
      LAYER M5 ;
        RECT  28.752 0 28.776 0.084 ;
    END
  END vm_rr0[140]
  PIN vm_rr0[141]
    DIRECTION INPUT ;
    USE SIGNAL ;
    PORT
      LAYER M5 ;
        RECT  28.944 0 28.968 0.084 ;
    END
  END vm_rr0[141]
  PIN vm_rr0[142]
    DIRECTION INPUT ;
    USE SIGNAL ;
    PORT
      LAYER M5 ;
        RECT  29.136 0 29.16 0.084 ;
    END
  END vm_rr0[142]
  PIN vm_rr0[143]
    DIRECTION INPUT ;
    USE SIGNAL ;
    PORT
      LAYER M5 ;
        RECT  29.328 0 29.352 0.084 ;
    END
  END vm_rr0[143]
  PIN vm_rr0[144]
    DIRECTION INPUT ;
    USE SIGNAL ;
    PORT
      LAYER M5 ;
        RECT  29.52 0 29.544 0.084 ;
    END
  END vm_rr0[144]
  PIN vm_rr0[145]
    DIRECTION INPUT ;
    USE SIGNAL ;
    PORT
      LAYER M5 ;
        RECT  29.664 0 29.688 0.084 ;
    END
  END vm_rr0[145]
  PIN vm_rr0[146]
    DIRECTION INPUT ;
    USE SIGNAL ;
    PORT
      LAYER M5 ;
        RECT  29.856 0 29.88 0.084 ;
    END
  END vm_rr0[146]
  PIN vm_rr0[147]
    DIRECTION INPUT ;
    USE SIGNAL ;
    PORT
      LAYER M5 ;
        RECT  30.048 0 30.072 0.084 ;
    END
  END vm_rr0[147]
  PIN vm_rr0[148]
    DIRECTION INPUT ;
    USE SIGNAL ;
    PORT
      LAYER M5 ;
        RECT  30.24 0 30.264 0.084 ;
    END
  END vm_rr0[148]
  PIN vm_rr0[149]
    DIRECTION INPUT ;
    USE SIGNAL ;
    PORT
      LAYER M5 ;
        RECT  30.432 0 30.456 0.084 ;
    END
  END vm_rr0[149]
  PIN vm_rr0[14]
    DIRECTION INPUT ;
    USE SIGNAL ;
    PORT
      LAYER M5 ;
        RECT  4.896 0 4.92 0.084 ;
    END
  END vm_rr0[14]
  PIN vm_rr0[150]
    DIRECTION INPUT ;
    USE SIGNAL ;
    PORT
      LAYER M5 ;
        RECT  30.624 0 30.648 0.084 ;
    END
  END vm_rr0[150]
  PIN vm_rr0[151]
    DIRECTION INPUT ;
    USE SIGNAL ;
    PORT
      LAYER M5 ;
        RECT  30.816 0 30.84 0.084 ;
    END
  END vm_rr0[151]
  PIN vm_rr0[152]
    DIRECTION INPUT ;
    USE SIGNAL ;
    PORT
      LAYER M5 ;
        RECT  31.008 0 31.032 0.084 ;
    END
  END vm_rr0[152]
  PIN vm_rr0[153]
    DIRECTION INPUT ;
    USE SIGNAL ;
    PORT
      LAYER M5 ;
        RECT  31.2 0 31.224 0.084 ;
    END
  END vm_rr0[153]
  PIN vm_rr0[154]
    DIRECTION INPUT ;
    USE SIGNAL ;
    PORT
      LAYER M5 ;
        RECT  31.392 0 31.416 0.084 ;
    END
  END vm_rr0[154]
  PIN vm_rr0[155]
    DIRECTION INPUT ;
    USE SIGNAL ;
    PORT
      LAYER M5 ;
        RECT  31.584 0 31.608 0.084 ;
    END
  END vm_rr0[155]
  PIN vm_rr0[156]
    DIRECTION INPUT ;
    USE SIGNAL ;
    PORT
      LAYER M5 ;
        RECT  31.776 0 31.8 0.084 ;
    END
  END vm_rr0[156]
  PIN vm_rr0[157]
    DIRECTION INPUT ;
    USE SIGNAL ;
    PORT
      LAYER M5 ;
        RECT  31.968 0 31.992 0.084 ;
    END
  END vm_rr0[157]
  PIN vm_rr0[158]
    DIRECTION INPUT ;
    USE SIGNAL ;
    PORT
      LAYER M5 ;
        RECT  32.16 0 32.184 0.084 ;
    END
  END vm_rr0[158]
  PIN vm_rr0[159]
    DIRECTION INPUT ;
    USE SIGNAL ;
    PORT
      LAYER M5 ;
        RECT  32.352 0 32.376 0.084 ;
    END
  END vm_rr0[159]
  PIN vm_rr0[15]
    DIRECTION INPUT ;
    USE SIGNAL ;
    PORT
      LAYER M5 ;
        RECT  5.088 0 5.112 0.084 ;
    END
  END vm_rr0[15]
  PIN vm_rr0[160]
    DIRECTION INPUT ;
    USE SIGNAL ;
    PORT
      LAYER M5 ;
        RECT  32.544 0 32.568 0.084 ;
    END
  END vm_rr0[160]
  PIN vm_rr0[161]
    DIRECTION INPUT ;
    USE SIGNAL ;
    PORT
      LAYER M5 ;
        RECT  32.736 0 32.76 0.084 ;
    END
  END vm_rr0[161]
  PIN vm_rr0[162]
    DIRECTION INPUT ;
    USE SIGNAL ;
    PORT
      LAYER M5 ;
        RECT  32.88 0 32.904 0.084 ;
    END
  END vm_rr0[162]
  PIN vm_rr0[163]
    DIRECTION INPUT ;
    USE SIGNAL ;
    PORT
      LAYER M5 ;
        RECT  33.072 0 33.096 0.084 ;
    END
  END vm_rr0[163]
  PIN vm_rr0[164]
    DIRECTION INPUT ;
    USE SIGNAL ;
    PORT
      LAYER M5 ;
        RECT  33.264 0 33.288 0.084 ;
    END
  END vm_rr0[164]
  PIN vm_rr0[165]
    DIRECTION INPUT ;
    USE SIGNAL ;
    PORT
      LAYER M5 ;
        RECT  33.456 0 33.48 0.084 ;
    END
  END vm_rr0[165]
  PIN vm_rr0[166]
    DIRECTION INPUT ;
    USE SIGNAL ;
    PORT
      LAYER M5 ;
        RECT  33.648 0 33.672 0.084 ;
    END
  END vm_rr0[166]
  PIN vm_rr0[167]
    DIRECTION INPUT ;
    USE SIGNAL ;
    PORT
      LAYER M5 ;
        RECT  33.84 0 33.864 0.084 ;
    END
  END vm_rr0[167]
  PIN vm_rr0[168]
    DIRECTION INPUT ;
    USE SIGNAL ;
    PORT
      LAYER M5 ;
        RECT  34.032 0 34.056 0.084 ;
    END
  END vm_rr0[168]
  PIN vm_rr0[169]
    DIRECTION INPUT ;
    USE SIGNAL ;
    PORT
      LAYER M5 ;
        RECT  34.224 0 34.248 0.084 ;
    END
  END vm_rr0[169]
  PIN vm_rr0[16]
    DIRECTION INPUT ;
    USE SIGNAL ;
    PORT
      LAYER M5 ;
        RECT  5.28 0 5.304 0.084 ;
    END
  END vm_rr0[16]
  PIN vm_rr0[170]
    DIRECTION INPUT ;
    USE SIGNAL ;
    PORT
      LAYER M5 ;
        RECT  34.416 0 34.44 0.084 ;
    END
  END vm_rr0[170]
  PIN vm_rr0[171]
    DIRECTION INPUT ;
    USE SIGNAL ;
    PORT
      LAYER M5 ;
        RECT  34.608 0 34.632 0.084 ;
    END
  END vm_rr0[171]
  PIN vm_rr0[172]
    DIRECTION INPUT ;
    USE SIGNAL ;
    PORT
      LAYER M5 ;
        RECT  34.8 0 34.824 0.084 ;
    END
  END vm_rr0[172]
  PIN vm_rr0[173]
    DIRECTION INPUT ;
    USE SIGNAL ;
    PORT
      LAYER M5 ;
        RECT  34.992 0 35.016 0.084 ;
    END
  END vm_rr0[173]
  PIN vm_rr0[174]
    DIRECTION INPUT ;
    USE SIGNAL ;
    PORT
      LAYER M5 ;
        RECT  35.184 0 35.208 0.084 ;
    END
  END vm_rr0[174]
  PIN vm_rr0[175]
    DIRECTION INPUT ;
    USE SIGNAL ;
    PORT
      LAYER M5 ;
        RECT  35.376 0 35.4 0.084 ;
    END
  END vm_rr0[175]
  PIN vm_rr0[176]
    DIRECTION INPUT ;
    USE SIGNAL ;
    PORT
      LAYER M5 ;
        RECT  35.568 0 35.592 0.084 ;
    END
  END vm_rr0[176]
  PIN vm_rr0[177]
    DIRECTION INPUT ;
    USE SIGNAL ;
    PORT
      LAYER M5 ;
        RECT  35.76 0 35.784 0.084 ;
    END
  END vm_rr0[177]
  PIN vm_rr0[178]
    DIRECTION INPUT ;
    USE SIGNAL ;
    PORT
      LAYER M5 ;
        RECT  35.952 0 35.976 0.084 ;
    END
  END vm_rr0[178]
  PIN vm_rr0[179]
    DIRECTION INPUT ;
    USE SIGNAL ;
    PORT
      LAYER M5 ;
        RECT  36.144 0 36.168 0.084 ;
    END
  END vm_rr0[179]
  PIN vm_rr0[17]
    DIRECTION INPUT ;
    USE SIGNAL ;
    PORT
      LAYER M5 ;
        RECT  5.472 0 5.496 0.084 ;
    END
  END vm_rr0[17]
  PIN vm_rr0[180]
    DIRECTION INPUT ;
    USE SIGNAL ;
    PORT
      LAYER M5 ;
        RECT  36.288 0 36.312 0.084 ;
    END
  END vm_rr0[180]
  PIN vm_rr0[181]
    DIRECTION INPUT ;
    USE SIGNAL ;
    PORT
      LAYER M5 ;
        RECT  36.48 0 36.504 0.084 ;
    END
  END vm_rr0[181]
  PIN vm_rr0[182]
    DIRECTION INPUT ;
    USE SIGNAL ;
    PORT
      LAYER M5 ;
        RECT  36.672 0 36.696 0.084 ;
    END
  END vm_rr0[182]
  PIN vm_rr0[183]
    DIRECTION INPUT ;
    USE SIGNAL ;
    PORT
      LAYER M5 ;
        RECT  36.864 0 36.888 0.084 ;
    END
  END vm_rr0[183]
  PIN vm_rr0[184]
    DIRECTION INPUT ;
    USE SIGNAL ;
    PORT
      LAYER M5 ;
        RECT  37.056 0 37.08 0.084 ;
    END
  END vm_rr0[184]
  PIN vm_rr0[185]
    DIRECTION INPUT ;
    USE SIGNAL ;
    PORT
      LAYER M5 ;
        RECT  37.248 0 37.272 0.084 ;
    END
  END vm_rr0[185]
  PIN vm_rr0[186]
    DIRECTION INPUT ;
    USE SIGNAL ;
    PORT
      LAYER M5 ;
        RECT  37.44 0 37.464 0.084 ;
    END
  END vm_rr0[186]
  PIN vm_rr0[187]
    DIRECTION INPUT ;
    USE SIGNAL ;
    PORT
      LAYER M5 ;
        RECT  37.632 0 37.656 0.084 ;
    END
  END vm_rr0[187]
  PIN vm_rr0[188]
    DIRECTION INPUT ;
    USE SIGNAL ;
    PORT
      LAYER M5 ;
        RECT  37.824 0 37.848 0.084 ;
    END
  END vm_rr0[188]
  PIN vm_rr0[189]
    DIRECTION INPUT ;
    USE SIGNAL ;
    PORT
      LAYER M5 ;
        RECT  38.016 0 38.04 0.084 ;
    END
  END vm_rr0[189]
  PIN vm_rr0[18]
    DIRECTION INPUT ;
    USE SIGNAL ;
    PORT
      LAYER M5 ;
        RECT  5.664 0 5.688 0.084 ;
    END
  END vm_rr0[18]
  PIN vm_rr0[190]
    DIRECTION INPUT ;
    USE SIGNAL ;
    PORT
      LAYER M5 ;
        RECT  38.208 0 38.232 0.084 ;
    END
  END vm_rr0[190]
  PIN vm_rr0[191]
    DIRECTION INPUT ;
    USE SIGNAL ;
    PORT
      LAYER M5 ;
        RECT  38.4 0 38.424 0.084 ;
    END
  END vm_rr0[191]
  PIN vm_rr0[192]
    DIRECTION INPUT ;
    USE SIGNAL ;
    PORT
      LAYER M5 ;
        RECT  38.592 0 38.616 0.084 ;
    END
  END vm_rr0[192]
  PIN vm_rr0[193]
    DIRECTION INPUT ;
    USE SIGNAL ;
    PORT
      LAYER M5 ;
        RECT  38.784 0 38.808 0.084 ;
    END
  END vm_rr0[193]
  PIN vm_rr0[194]
    DIRECTION INPUT ;
    USE SIGNAL ;
    PORT
      LAYER M5 ;
        RECT  38.976 0 39 0.084 ;
    END
  END vm_rr0[194]
  PIN vm_rr0[195]
    DIRECTION INPUT ;
    USE SIGNAL ;
    PORT
      LAYER M5 ;
        RECT  39.168 0 39.192 0.084 ;
    END
  END vm_rr0[195]
  PIN vm_rr0[196]
    DIRECTION INPUT ;
    USE SIGNAL ;
    PORT
      LAYER M5 ;
        RECT  39.36 0 39.384 0.084 ;
    END
  END vm_rr0[196]
  PIN vm_rr0[197]
    DIRECTION INPUT ;
    USE SIGNAL ;
    PORT
      LAYER M5 ;
        RECT  39.504 0 39.528 0.084 ;
    END
  END vm_rr0[197]
  PIN vm_rr0[198]
    DIRECTION INPUT ;
    USE SIGNAL ;
    PORT
      LAYER M5 ;
        RECT  39.696 0 39.72 0.084 ;
    END
  END vm_rr0[198]
  PIN vm_rr0[199]
    DIRECTION INPUT ;
    USE SIGNAL ;
    PORT
      LAYER M5 ;
        RECT  39.888 0 39.912 0.084 ;
    END
  END vm_rr0[199]
  PIN vm_rr0[19]
    DIRECTION INPUT ;
    USE SIGNAL ;
    PORT
      LAYER M5 ;
        RECT  5.856 0 5.88 0.084 ;
    END
  END vm_rr0[19]
  PIN vm_rr0[1]
    DIRECTION INPUT ;
    USE SIGNAL ;
    PORT
      LAYER M5 ;
        RECT  2.448 0 2.472 0.084 ;
    END
  END vm_rr0[1]
  PIN vm_rr0[200]
    DIRECTION INPUT ;
    USE SIGNAL ;
    PORT
      LAYER M5 ;
        RECT  40.08 0 40.104 0.084 ;
    END
  END vm_rr0[200]
  PIN vm_rr0[201]
    DIRECTION INPUT ;
    USE SIGNAL ;
    PORT
      LAYER M5 ;
        RECT  40.272 0 40.296 0.084 ;
    END
  END vm_rr0[201]
  PIN vm_rr0[202]
    DIRECTION INPUT ;
    USE SIGNAL ;
    PORT
      LAYER M5 ;
        RECT  40.464 0 40.488 0.084 ;
    END
  END vm_rr0[202]
  PIN vm_rr0[203]
    DIRECTION INPUT ;
    USE SIGNAL ;
    PORT
      LAYER M5 ;
        RECT  40.656 0 40.68 0.084 ;
    END
  END vm_rr0[203]
  PIN vm_rr0[204]
    DIRECTION INPUT ;
    USE SIGNAL ;
    PORT
      LAYER M5 ;
        RECT  40.848 0 40.872 0.084 ;
    END
  END vm_rr0[204]
  PIN vm_rr0[205]
    DIRECTION INPUT ;
    USE SIGNAL ;
    PORT
      LAYER M5 ;
        RECT  41.04 0 41.064 0.084 ;
    END
  END vm_rr0[205]
  PIN vm_rr0[206]
    DIRECTION INPUT ;
    USE SIGNAL ;
    PORT
      LAYER M5 ;
        RECT  41.232 0 41.256 0.084 ;
    END
  END vm_rr0[206]
  PIN vm_rr0[207]
    DIRECTION INPUT ;
    USE SIGNAL ;
    PORT
      LAYER M5 ;
        RECT  41.424 0 41.448 0.084 ;
    END
  END vm_rr0[207]
  PIN vm_rr0[208]
    DIRECTION INPUT ;
    USE SIGNAL ;
    PORT
      LAYER M5 ;
        RECT  41.616 0 41.64 0.084 ;
    END
  END vm_rr0[208]
  PIN vm_rr0[209]
    DIRECTION INPUT ;
    USE SIGNAL ;
    PORT
      LAYER M5 ;
        RECT  41.808 0 41.832 0.084 ;
    END
  END vm_rr0[209]
  PIN vm_rr0[20]
    DIRECTION INPUT ;
    USE SIGNAL ;
    PORT
      LAYER M5 ;
        RECT  6.048 0 6.072 0.084 ;
    END
  END vm_rr0[20]
  PIN vm_rr0[210]
    DIRECTION INPUT ;
    USE SIGNAL ;
    PORT
      LAYER M5 ;
        RECT  42 0 42.024 0.084 ;
    END
  END vm_rr0[210]
  PIN vm_rr0[211]
    DIRECTION INPUT ;
    USE SIGNAL ;
    PORT
      LAYER M5 ;
        RECT  42.192 0 42.216 0.084 ;
    END
  END vm_rr0[211]
  PIN vm_rr0[212]
    DIRECTION INPUT ;
    USE SIGNAL ;
    PORT
      LAYER M5 ;
        RECT  42.384 0 42.408 0.084 ;
    END
  END vm_rr0[212]
  PIN vm_rr0[213]
    DIRECTION INPUT ;
    USE SIGNAL ;
    PORT
      LAYER M5 ;
        RECT  42.576 0 42.6 0.084 ;
    END
  END vm_rr0[213]
  PIN vm_rr0[214]
    DIRECTION INPUT ;
    USE SIGNAL ;
    PORT
      LAYER M5 ;
        RECT  42.768 0 42.792 0.084 ;
    END
  END vm_rr0[214]
  PIN vm_rr0[215]
    DIRECTION INPUT ;
    USE SIGNAL ;
    PORT
      LAYER M5 ;
        RECT  42.912 0 42.936 0.084 ;
    END
  END vm_rr0[215]
  PIN vm_rr0[216]
    DIRECTION INPUT ;
    USE SIGNAL ;
    PORT
      LAYER M5 ;
        RECT  43.104 0 43.128 0.084 ;
    END
  END vm_rr0[216]
  PIN vm_rr0[217]
    DIRECTION INPUT ;
    USE SIGNAL ;
    PORT
      LAYER M5 ;
        RECT  43.296 0 43.32 0.084 ;
    END
  END vm_rr0[217]
  PIN vm_rr0[218]
    DIRECTION INPUT ;
    USE SIGNAL ;
    PORT
      LAYER M5 ;
        RECT  43.488 0 43.512 0.084 ;
    END
  END vm_rr0[218]
  PIN vm_rr0[219]
    DIRECTION INPUT ;
    USE SIGNAL ;
    PORT
      LAYER M5 ;
        RECT  43.68 0 43.704 0.084 ;
    END
  END vm_rr0[219]
  PIN vm_rr0[21]
    DIRECTION INPUT ;
    USE SIGNAL ;
    PORT
      LAYER M5 ;
        RECT  6.24 0 6.264 0.084 ;
    END
  END vm_rr0[21]
  PIN vm_rr0[220]
    DIRECTION INPUT ;
    USE SIGNAL ;
    PORT
      LAYER M5 ;
        RECT  43.872 0 43.896 0.084 ;
    END
  END vm_rr0[220]
  PIN vm_rr0[221]
    DIRECTION INPUT ;
    USE SIGNAL ;
    PORT
      LAYER M5 ;
        RECT  44.064 0 44.088 0.084 ;
    END
  END vm_rr0[221]
  PIN vm_rr0[222]
    DIRECTION INPUT ;
    USE SIGNAL ;
    PORT
      LAYER M5 ;
        RECT  44.256 0 44.28 0.084 ;
    END
  END vm_rr0[222]
  PIN vm_rr0[223]
    DIRECTION INPUT ;
    USE SIGNAL ;
    PORT
      LAYER M5 ;
        RECT  44.448 0 44.472 0.084 ;
    END
  END vm_rr0[223]
  PIN vm_rr0[224]
    DIRECTION INPUT ;
    USE SIGNAL ;
    PORT
      LAYER M5 ;
        RECT  44.64 0 44.664 0.084 ;
    END
  END vm_rr0[224]
  PIN vm_rr0[225]
    DIRECTION INPUT ;
    USE SIGNAL ;
    PORT
      LAYER M5 ;
        RECT  44.832 0 44.856 0.084 ;
    END
  END vm_rr0[225]
  PIN vm_rr0[226]
    DIRECTION INPUT ;
    USE SIGNAL ;
    PORT
      LAYER M5 ;
        RECT  45.024 0 45.048 0.084 ;
    END
  END vm_rr0[226]
  PIN vm_rr0[227]
    DIRECTION INPUT ;
    USE SIGNAL ;
    PORT
      LAYER M5 ;
        RECT  45.216 0 45.24 0.084 ;
    END
  END vm_rr0[227]
  PIN vm_rr0[228]
    DIRECTION INPUT ;
    USE SIGNAL ;
    PORT
      LAYER M5 ;
        RECT  45.408 0 45.432 0.084 ;
    END
  END vm_rr0[228]
  PIN vm_rr0[229]
    DIRECTION INPUT ;
    USE SIGNAL ;
    PORT
      LAYER M5 ;
        RECT  45.6 0 45.624 0.084 ;
    END
  END vm_rr0[229]
  PIN vm_rr0[22]
    DIRECTION INPUT ;
    USE SIGNAL ;
    PORT
      LAYER M5 ;
        RECT  6.384 0 6.408 0.084 ;
    END
  END vm_rr0[22]
  PIN vm_rr0[230]
    DIRECTION INPUT ;
    USE SIGNAL ;
    PORT
      LAYER M5 ;
        RECT  45.792 0 45.816 0.084 ;
    END
  END vm_rr0[230]
  PIN vm_rr0[231]
    DIRECTION INPUT ;
    USE SIGNAL ;
    PORT
      LAYER M5 ;
        RECT  45.984 0 46.008 0.084 ;
    END
  END vm_rr0[231]
  PIN vm_rr0[232]
    DIRECTION INPUT ;
    USE SIGNAL ;
    PORT
      LAYER M5 ;
        RECT  46.128 0 46.152 0.084 ;
    END
  END vm_rr0[232]
  PIN vm_rr0[233]
    DIRECTION INPUT ;
    USE SIGNAL ;
    PORT
      LAYER M5 ;
        RECT  46.32 0 46.344 0.084 ;
    END
  END vm_rr0[233]
  PIN vm_rr0[234]
    DIRECTION INPUT ;
    USE SIGNAL ;
    PORT
      LAYER M5 ;
        RECT  46.512 0 46.536 0.084 ;
    END
  END vm_rr0[234]
  PIN vm_rr0[235]
    DIRECTION INPUT ;
    USE SIGNAL ;
    PORT
      LAYER M5 ;
        RECT  46.704 0 46.728 0.084 ;
    END
  END vm_rr0[235]
  PIN vm_rr0[236]
    DIRECTION INPUT ;
    USE SIGNAL ;
    PORT
      LAYER M5 ;
        RECT  46.896 0 46.92 0.084 ;
    END
  END vm_rr0[236]
  PIN vm_rr0[237]
    DIRECTION INPUT ;
    USE SIGNAL ;
    PORT
      LAYER M5 ;
        RECT  47.088 0 47.112 0.084 ;
    END
  END vm_rr0[237]
  PIN vm_rr0[238]
    DIRECTION INPUT ;
    USE SIGNAL ;
    PORT
      LAYER M5 ;
        RECT  47.28 0 47.304 0.084 ;
    END
  END vm_rr0[238]
  PIN vm_rr0[239]
    DIRECTION INPUT ;
    USE SIGNAL ;
    PORT
      LAYER M5 ;
        RECT  47.472 0 47.496 0.084 ;
    END
  END vm_rr0[239]
  PIN vm_rr0[23]
    DIRECTION INPUT ;
    USE SIGNAL ;
    PORT
      LAYER M5 ;
        RECT  6.576 0 6.6 0.084 ;
    END
  END vm_rr0[23]
  PIN vm_rr0[240]
    DIRECTION INPUT ;
    USE SIGNAL ;
    PORT
      LAYER M5 ;
        RECT  47.664 0 47.688 0.084 ;
    END
  END vm_rr0[240]
  PIN vm_rr0[241]
    DIRECTION INPUT ;
    USE SIGNAL ;
    PORT
      LAYER M5 ;
        RECT  47.856 0 47.88 0.084 ;
    END
  END vm_rr0[241]
  PIN vm_rr0[242]
    DIRECTION INPUT ;
    USE SIGNAL ;
    PORT
      LAYER M5 ;
        RECT  48.048 0 48.072 0.084 ;
    END
  END vm_rr0[242]
  PIN vm_rr0[243]
    DIRECTION INPUT ;
    USE SIGNAL ;
    PORT
      LAYER M5 ;
        RECT  48.24 0 48.264 0.084 ;
    END
  END vm_rr0[243]
  PIN vm_rr0[244]
    DIRECTION INPUT ;
    USE SIGNAL ;
    PORT
      LAYER M5 ;
        RECT  48.432 0 48.456 0.084 ;
    END
  END vm_rr0[244]
  PIN vm_rr0[245]
    DIRECTION INPUT ;
    USE SIGNAL ;
    PORT
      LAYER M5 ;
        RECT  48.624 0 48.648 0.084 ;
    END
  END vm_rr0[245]
  PIN vm_rr0[246]
    DIRECTION INPUT ;
    USE SIGNAL ;
    PORT
      LAYER M5 ;
        RECT  48.816 0 48.84 0.084 ;
    END
  END vm_rr0[246]
  PIN vm_rr0[247]
    DIRECTION INPUT ;
    USE SIGNAL ;
    PORT
      LAYER M5 ;
        RECT  49.008 0 49.032 0.084 ;
    END
  END vm_rr0[247]
  PIN vm_rr0[248]
    DIRECTION INPUT ;
    USE SIGNAL ;
    PORT
      LAYER M5 ;
        RECT  49.2 0 49.224 0.084 ;
    END
  END vm_rr0[248]
  PIN vm_rr0[249]
    DIRECTION INPUT ;
    USE SIGNAL ;
    PORT
      LAYER M5 ;
        RECT  49.392 0 49.416 0.084 ;
    END
  END vm_rr0[249]
  PIN vm_rr0[24]
    DIRECTION INPUT ;
    USE SIGNAL ;
    PORT
      LAYER M5 ;
        RECT  6.768 0 6.792 0.084 ;
    END
  END vm_rr0[24]
  PIN vm_rr0[250]
    DIRECTION INPUT ;
    USE SIGNAL ;
    PORT
      LAYER M5 ;
        RECT  49.536 0 49.56 0.084 ;
    END
  END vm_rr0[250]
  PIN vm_rr0[251]
    DIRECTION INPUT ;
    USE SIGNAL ;
    PORT
      LAYER M5 ;
        RECT  49.728 0 49.752 0.084 ;
    END
  END vm_rr0[251]
  PIN vm_rr0[252]
    DIRECTION INPUT ;
    USE SIGNAL ;
    PORT
      LAYER M5 ;
        RECT  49.92 0 49.944 0.084 ;
    END
  END vm_rr0[252]
  PIN vm_rr0[253]
    DIRECTION INPUT ;
    USE SIGNAL ;
    PORT
      LAYER M5 ;
        RECT  50.112 0 50.136 0.084 ;
    END
  END vm_rr0[253]
  PIN vm_rr0[254]
    DIRECTION INPUT ;
    USE SIGNAL ;
    PORT
      LAYER M5 ;
        RECT  50.304 0 50.328 0.084 ;
    END
  END vm_rr0[254]
  PIN vm_rr0[255]
    DIRECTION INPUT ;
    USE SIGNAL ;
    PORT
      LAYER M5 ;
        RECT  50.496 0 50.52 0.084 ;
    END
  END vm_rr0[255]
  PIN vm_rr0[256]
    DIRECTION INPUT ;
    USE SIGNAL ;
    PORT
      LAYER M5 ;
        RECT  50.688 0 50.712 0.084 ;
    END
  END vm_rr0[256]
  PIN vm_rr0[25]
    DIRECTION INPUT ;
    USE SIGNAL ;
    PORT
      LAYER M5 ;
        RECT  6.96 0 6.984 0.084 ;
    END
  END vm_rr0[25]
  PIN vm_rr0[26]
    DIRECTION INPUT ;
    USE SIGNAL ;
    PORT
      LAYER M5 ;
        RECT  7.152 0 7.176 0.084 ;
    END
  END vm_rr0[26]
  PIN vm_rr0[27]
    DIRECTION INPUT ;
    USE SIGNAL ;
    PORT
      LAYER M5 ;
        RECT  7.344 0 7.368 0.084 ;
    END
  END vm_rr0[27]
  PIN vm_rr0[28]
    DIRECTION INPUT ;
    USE SIGNAL ;
    PORT
      LAYER M5 ;
        RECT  7.536 0 7.56 0.084 ;
    END
  END vm_rr0[28]
  PIN vm_rr0[29]
    DIRECTION INPUT ;
    USE SIGNAL ;
    PORT
      LAYER M5 ;
        RECT  7.728 0 7.752 0.084 ;
    END
  END vm_rr0[29]
  PIN vm_rr0[2]
    DIRECTION INPUT ;
    USE SIGNAL ;
    PORT
      LAYER M5 ;
        RECT  2.64 0 2.664 0.084 ;
    END
  END vm_rr0[2]
  PIN vm_rr0[30]
    DIRECTION INPUT ;
    USE SIGNAL ;
    PORT
      LAYER M5 ;
        RECT  7.92 0 7.944 0.084 ;
    END
  END vm_rr0[30]
  PIN vm_rr0[31]
    DIRECTION INPUT ;
    USE SIGNAL ;
    PORT
      LAYER M5 ;
        RECT  8.112 0 8.136 0.084 ;
    END
  END vm_rr0[31]
  PIN vm_rr0[32]
    DIRECTION INPUT ;
    USE SIGNAL ;
    PORT
      LAYER M5 ;
        RECT  8.304 0 8.328 0.084 ;
    END
  END vm_rr0[32]
  PIN vm_rr0[33]
    DIRECTION INPUT ;
    USE SIGNAL ;
    PORT
      LAYER M5 ;
        RECT  8.496 0 8.52 0.084 ;
    END
  END vm_rr0[33]
  PIN vm_rr0[34]
    DIRECTION INPUT ;
    USE SIGNAL ;
    PORT
      LAYER M5 ;
        RECT  8.688 0 8.712 0.084 ;
    END
  END vm_rr0[34]
  PIN vm_rr0[35]
    DIRECTION INPUT ;
    USE SIGNAL ;
    PORT
      LAYER M5 ;
        RECT  8.88 0 8.904 0.084 ;
    END
  END vm_rr0[35]
  PIN vm_rr0[36]
    DIRECTION INPUT ;
    USE SIGNAL ;
    PORT
      LAYER M5 ;
        RECT  9.072 0 9.096 0.084 ;
    END
  END vm_rr0[36]
  PIN vm_rr0[37]
    DIRECTION INPUT ;
    USE SIGNAL ;
    PORT
      LAYER M5 ;
        RECT  9.264 0 9.288 0.084 ;
    END
  END vm_rr0[37]
  PIN vm_rr0[38]
    DIRECTION INPUT ;
    USE SIGNAL ;
    PORT
      LAYER M5 ;
        RECT  9.456 0 9.48 0.084 ;
    END
  END vm_rr0[38]
  PIN vm_rr0[39]
    DIRECTION INPUT ;
    USE SIGNAL ;
    PORT
      LAYER M5 ;
        RECT  9.648 0 9.672 0.084 ;
    END
  END vm_rr0[39]
  PIN vm_rr0[3]
    DIRECTION INPUT ;
    USE SIGNAL ;
    PORT
      LAYER M5 ;
        RECT  2.832 0 2.856 0.084 ;
    END
  END vm_rr0[3]
  PIN vm_rr0[40]
    DIRECTION INPUT ;
    USE SIGNAL ;
    PORT
      LAYER M5 ;
        RECT  9.792 0 9.816 0.084 ;
    END
  END vm_rr0[40]
  PIN vm_rr0[41]
    DIRECTION INPUT ;
    USE SIGNAL ;
    PORT
      LAYER M5 ;
        RECT  9.984 0 10.008 0.084 ;
    END
  END vm_rr0[41]
  PIN vm_rr0[42]
    DIRECTION INPUT ;
    USE SIGNAL ;
    PORT
      LAYER M5 ;
        RECT  10.176 0 10.2 0.084 ;
    END
  END vm_rr0[42]
  PIN vm_rr0[43]
    DIRECTION INPUT ;
    USE SIGNAL ;
    PORT
      LAYER M5 ;
        RECT  10.368 0 10.392 0.084 ;
    END
  END vm_rr0[43]
  PIN vm_rr0[44]
    DIRECTION INPUT ;
    USE SIGNAL ;
    PORT
      LAYER M5 ;
        RECT  10.56 0 10.584 0.084 ;
    END
  END vm_rr0[44]
  PIN vm_rr0[45]
    DIRECTION INPUT ;
    USE SIGNAL ;
    PORT
      LAYER M5 ;
        RECT  10.752 0 10.776 0.084 ;
    END
  END vm_rr0[45]
  PIN vm_rr0[46]
    DIRECTION INPUT ;
    USE SIGNAL ;
    PORT
      LAYER M5 ;
        RECT  10.944 0 10.968 0.084 ;
    END
  END vm_rr0[46]
  PIN vm_rr0[47]
    DIRECTION INPUT ;
    USE SIGNAL ;
    PORT
      LAYER M5 ;
        RECT  11.136 0 11.16 0.084 ;
    END
  END vm_rr0[47]
  PIN vm_rr0[48]
    DIRECTION INPUT ;
    USE SIGNAL ;
    PORT
      LAYER M5 ;
        RECT  11.328 0 11.352 0.084 ;
    END
  END vm_rr0[48]
  PIN vm_rr0[49]
    DIRECTION INPUT ;
    USE SIGNAL ;
    PORT
      LAYER M5 ;
        RECT  11.52 0 11.544 0.084 ;
    END
  END vm_rr0[49]
  PIN vm_rr0[4]
    DIRECTION INPUT ;
    USE SIGNAL ;
    PORT
      LAYER M5 ;
        RECT  3.024 0 3.048 0.084 ;
    END
  END vm_rr0[4]
  PIN vm_rr0[50]
    DIRECTION INPUT ;
    USE SIGNAL ;
    PORT
      LAYER M5 ;
        RECT  11.712 0 11.736 0.084 ;
    END
  END vm_rr0[50]
  PIN vm_rr0[51]
    DIRECTION INPUT ;
    USE SIGNAL ;
    PORT
      LAYER M5 ;
        RECT  11.904 0 11.928 0.084 ;
    END
  END vm_rr0[51]
  PIN vm_rr0[52]
    DIRECTION INPUT ;
    USE SIGNAL ;
    PORT
      LAYER M5 ;
        RECT  12.096 0 12.12 0.084 ;
    END
  END vm_rr0[52]
  PIN vm_rr0[53]
    DIRECTION INPUT ;
    USE SIGNAL ;
    PORT
      LAYER M5 ;
        RECT  12.288 0 12.312 0.084 ;
    END
  END vm_rr0[53]
  PIN vm_rr0[54]
    DIRECTION INPUT ;
    USE SIGNAL ;
    PORT
      LAYER M5 ;
        RECT  12.48 0 12.504 0.084 ;
    END
  END vm_rr0[54]
  PIN vm_rr0[55]
    DIRECTION INPUT ;
    USE SIGNAL ;
    PORT
      LAYER M5 ;
        RECT  12.672 0 12.696 0.084 ;
    END
  END vm_rr0[55]
  PIN vm_rr0[56]
    DIRECTION INPUT ;
    USE SIGNAL ;
    PORT
      LAYER M5 ;
        RECT  12.864 0 12.888 0.084 ;
    END
  END vm_rr0[56]
  PIN vm_rr0[57]
    DIRECTION INPUT ;
    USE SIGNAL ;
    PORT
      LAYER M5 ;
        RECT  13.008 0 13.032 0.084 ;
    END
  END vm_rr0[57]
  PIN vm_rr0[58]
    DIRECTION INPUT ;
    USE SIGNAL ;
    PORT
      LAYER M5 ;
        RECT  13.2 0 13.224 0.084 ;
    END
  END vm_rr0[58]
  PIN vm_rr0[59]
    DIRECTION INPUT ;
    USE SIGNAL ;
    PORT
      LAYER M5 ;
        RECT  13.392 0 13.416 0.084 ;
    END
  END vm_rr0[59]
  PIN vm_rr0[5]
    DIRECTION INPUT ;
    USE SIGNAL ;
    PORT
      LAYER M5 ;
        RECT  3.168 0 3.192 0.084 ;
    END
  END vm_rr0[5]
  PIN vm_rr0[60]
    DIRECTION INPUT ;
    USE SIGNAL ;
    PORT
      LAYER M5 ;
        RECT  13.584 0 13.608 0.084 ;
    END
  END vm_rr0[60]
  PIN vm_rr0[61]
    DIRECTION INPUT ;
    USE SIGNAL ;
    PORT
      LAYER M5 ;
        RECT  13.776 0 13.8 0.084 ;
    END
  END vm_rr0[61]
  PIN vm_rr0[62]
    DIRECTION INPUT ;
    USE SIGNAL ;
    PORT
      LAYER M5 ;
        RECT  13.968 0 13.992 0.084 ;
    END
  END vm_rr0[62]
  PIN vm_rr0[63]
    DIRECTION INPUT ;
    USE SIGNAL ;
    PORT
      LAYER M5 ;
        RECT  14.16 0 14.184 0.084 ;
    END
  END vm_rr0[63]
  PIN vm_rr0[64]
    DIRECTION INPUT ;
    USE SIGNAL ;
    PORT
      LAYER M5 ;
        RECT  14.352 0 14.376 0.084 ;
    END
  END vm_rr0[64]
  PIN vm_rr0[65]
    DIRECTION INPUT ;
    USE SIGNAL ;
    PORT
      LAYER M5 ;
        RECT  14.544 0 14.568 0.084 ;
    END
  END vm_rr0[65]
  PIN vm_rr0[66]
    DIRECTION INPUT ;
    USE SIGNAL ;
    PORT
      LAYER M5 ;
        RECT  14.736 0 14.76 0.084 ;
    END
  END vm_rr0[66]
  PIN vm_rr0[67]
    DIRECTION INPUT ;
    USE SIGNAL ;
    PORT
      LAYER M5 ;
        RECT  14.928 0 14.952 0.084 ;
    END
  END vm_rr0[67]
  PIN vm_rr0[68]
    DIRECTION INPUT ;
    USE SIGNAL ;
    PORT
      LAYER M5 ;
        RECT  15.12 0 15.144 0.084 ;
    END
  END vm_rr0[68]
  PIN vm_rr0[69]
    DIRECTION INPUT ;
    USE SIGNAL ;
    PORT
      LAYER M5 ;
        RECT  15.312 0 15.336 0.084 ;
    END
  END vm_rr0[69]
  PIN vm_rr0[6]
    DIRECTION INPUT ;
    USE SIGNAL ;
    PORT
      LAYER M5 ;
        RECT  3.36 0 3.384 0.084 ;
    END
  END vm_rr0[6]
  PIN vm_rr0[70]
    DIRECTION INPUT ;
    USE SIGNAL ;
    PORT
      LAYER M5 ;
        RECT  15.504 0 15.528 0.084 ;
    END
  END vm_rr0[70]
  PIN vm_rr0[71]
    DIRECTION INPUT ;
    USE SIGNAL ;
    PORT
      LAYER M5 ;
        RECT  15.696 0 15.72 0.084 ;
    END
  END vm_rr0[71]
  PIN vm_rr0[72]
    DIRECTION INPUT ;
    USE SIGNAL ;
    PORT
      LAYER M5 ;
        RECT  15.888 0 15.912 0.084 ;
    END
  END vm_rr0[72]
  PIN vm_rr0[73]
    DIRECTION INPUT ;
    USE SIGNAL ;
    PORT
      LAYER M5 ;
        RECT  16.08 0 16.104 0.084 ;
    END
  END vm_rr0[73]
  PIN vm_rr0[74]
    DIRECTION INPUT ;
    USE SIGNAL ;
    PORT
      LAYER M5 ;
        RECT  16.272 0 16.296 0.084 ;
    END
  END vm_rr0[74]
  PIN vm_rr0[75]
    DIRECTION INPUT ;
    USE SIGNAL ;
    PORT
      LAYER M5 ;
        RECT  16.416 0 16.44 0.084 ;
    END
  END vm_rr0[75]
  PIN vm_rr0[76]
    DIRECTION INPUT ;
    USE SIGNAL ;
    PORT
      LAYER M5 ;
        RECT  16.608 0 16.632 0.084 ;
    END
  END vm_rr0[76]
  PIN vm_rr0[77]
    DIRECTION INPUT ;
    USE SIGNAL ;
    PORT
      LAYER M5 ;
        RECT  16.8 0 16.824 0.084 ;
    END
  END vm_rr0[77]
  PIN vm_rr0[78]
    DIRECTION INPUT ;
    USE SIGNAL ;
    PORT
      LAYER M5 ;
        RECT  16.992 0 17.016 0.084 ;
    END
  END vm_rr0[78]
  PIN vm_rr0[79]
    DIRECTION INPUT ;
    USE SIGNAL ;
    PORT
      LAYER M5 ;
        RECT  17.184 0 17.208 0.084 ;
    END
  END vm_rr0[79]
  PIN vm_rr0[7]
    DIRECTION INPUT ;
    USE SIGNAL ;
    PORT
      LAYER M5 ;
        RECT  3.552 0 3.576 0.084 ;
    END
  END vm_rr0[7]
  PIN vm_rr0[80]
    DIRECTION INPUT ;
    USE SIGNAL ;
    PORT
      LAYER M5 ;
        RECT  17.376 0 17.4 0.084 ;
    END
  END vm_rr0[80]
  PIN vm_rr0[81]
    DIRECTION INPUT ;
    USE SIGNAL ;
    PORT
      LAYER M5 ;
        RECT  17.568 0 17.592 0.084 ;
    END
  END vm_rr0[81]
  PIN vm_rr0[82]
    DIRECTION INPUT ;
    USE SIGNAL ;
    PORT
      LAYER M5 ;
        RECT  17.76 0 17.784 0.084 ;
    END
  END vm_rr0[82]
  PIN vm_rr0[83]
    DIRECTION INPUT ;
    USE SIGNAL ;
    PORT
      LAYER M5 ;
        RECT  17.952 0 17.976 0.084 ;
    END
  END vm_rr0[83]
  PIN vm_rr0[84]
    DIRECTION INPUT ;
    USE SIGNAL ;
    PORT
      LAYER M5 ;
        RECT  18.144 0 18.168 0.084 ;
    END
  END vm_rr0[84]
  PIN vm_rr0[85]
    DIRECTION INPUT ;
    USE SIGNAL ;
    PORT
      LAYER M5 ;
        RECT  18.336 0 18.36 0.084 ;
    END
  END vm_rr0[85]
  PIN vm_rr0[86]
    DIRECTION INPUT ;
    USE SIGNAL ;
    PORT
      LAYER M5 ;
        RECT  18.528 0 18.552 0.084 ;
    END
  END vm_rr0[86]
  PIN vm_rr0[87]
    DIRECTION INPUT ;
    USE SIGNAL ;
    PORT
      LAYER M5 ;
        RECT  18.72 0 18.744 0.084 ;
    END
  END vm_rr0[87]
  PIN vm_rr0[88]
    DIRECTION INPUT ;
    USE SIGNAL ;
    PORT
      LAYER M5 ;
        RECT  18.912 0 18.936 0.084 ;
    END
  END vm_rr0[88]
  PIN vm_rr0[89]
    DIRECTION INPUT ;
    USE SIGNAL ;
    PORT
      LAYER M5 ;
        RECT  19.104 0 19.128 0.084 ;
    END
  END vm_rr0[89]
  PIN vm_rr0[8]
    DIRECTION INPUT ;
    USE SIGNAL ;
    PORT
      LAYER M5 ;
        RECT  3.744 0 3.768 0.084 ;
    END
  END vm_rr0[8]
  PIN vm_rr0[90]
    DIRECTION INPUT ;
    USE SIGNAL ;
    PORT
      LAYER M5 ;
        RECT  19.296 0 19.32 0.084 ;
    END
  END vm_rr0[90]
  PIN vm_rr0[91]
    DIRECTION INPUT ;
    USE SIGNAL ;
    PORT
      LAYER M5 ;
        RECT  19.488 0 19.512 0.084 ;
    END
  END vm_rr0[91]
  PIN vm_rr0[92]
    DIRECTION INPUT ;
    USE SIGNAL ;
    PORT
      LAYER M5 ;
        RECT  19.632 0 19.656 0.084 ;
    END
  END vm_rr0[92]
  PIN vm_rr0[93]
    DIRECTION INPUT ;
    USE SIGNAL ;
    PORT
      LAYER M5 ;
        RECT  19.824 0 19.848 0.084 ;
    END
  END vm_rr0[93]
  PIN vm_rr0[94]
    DIRECTION INPUT ;
    USE SIGNAL ;
    PORT
      LAYER M5 ;
        RECT  20.016 0 20.04 0.084 ;
    END
  END vm_rr0[94]
  PIN vm_rr0[95]
    DIRECTION INPUT ;
    USE SIGNAL ;
    PORT
      LAYER M5 ;
        RECT  20.208 0 20.232 0.084 ;
    END
  END vm_rr0[95]
  PIN vm_rr0[96]
    DIRECTION INPUT ;
    USE SIGNAL ;
    PORT
      LAYER M5 ;
        RECT  20.4 0 20.424 0.084 ;
    END
  END vm_rr0[96]
  PIN vm_rr0[97]
    DIRECTION INPUT ;
    USE SIGNAL ;
    PORT
      LAYER M5 ;
        RECT  20.592 0 20.616 0.084 ;
    END
  END vm_rr0[97]
  PIN vm_rr0[98]
    DIRECTION INPUT ;
    USE SIGNAL ;
    PORT
      LAYER M5 ;
        RECT  20.784 0 20.808 0.084 ;
    END
  END vm_rr0[98]
  PIN vm_rr0[99]
    DIRECTION INPUT ;
    USE SIGNAL ;
    PORT
      LAYER M5 ;
        RECT  20.976 0 21 0.084 ;
    END
  END vm_rr0[99]
  PIN vm_rr0[9]
    DIRECTION INPUT ;
    USE SIGNAL ;
    PORT
      LAYER M5 ;
        RECT  3.936 0 3.96 0.084 ;
    END
  END vm_rr0[9]
  PIN vm_rr1[0]
    DIRECTION INPUT ;
    USE SIGNAL ;
    PORT
      LAYER M5 ;
        RECT  57.264 0 57.288 0.084 ;
    END
  END vm_rr1[0]
  PIN vm_rr1[100]
    DIRECTION INPUT ;
    USE SIGNAL ;
    PORT
      LAYER M5 ;
        RECT  76.224 0 76.248 0.084 ;
    END
  END vm_rr1[100]
  PIN vm_rr1[101]
    DIRECTION INPUT ;
    USE SIGNAL ;
    PORT
      LAYER M5 ;
        RECT  76.416 0 76.44 0.084 ;
    END
  END vm_rr1[101]
  PIN vm_rr1[102]
    DIRECTION INPUT ;
    USE SIGNAL ;
    PORT
      LAYER M5 ;
        RECT  76.608 0 76.632 0.084 ;
    END
  END vm_rr1[102]
  PIN vm_rr1[103]
    DIRECTION INPUT ;
    USE SIGNAL ;
    PORT
      LAYER M5 ;
        RECT  76.8 0 76.824 0.084 ;
    END
  END vm_rr1[103]
  PIN vm_rr1[104]
    DIRECTION INPUT ;
    USE SIGNAL ;
    PORT
      LAYER M5 ;
        RECT  76.944 0 76.968 0.084 ;
    END
  END vm_rr1[104]
  PIN vm_rr1[105]
    DIRECTION INPUT ;
    USE SIGNAL ;
    PORT
      LAYER M5 ;
        RECT  77.136 0 77.16 0.084 ;
    END
  END vm_rr1[105]
  PIN vm_rr1[106]
    DIRECTION INPUT ;
    USE SIGNAL ;
    PORT
      LAYER M5 ;
        RECT  77.328 0 77.352 0.084 ;
    END
  END vm_rr1[106]
  PIN vm_rr1[107]
    DIRECTION INPUT ;
    USE SIGNAL ;
    PORT
      LAYER M5 ;
        RECT  77.52 0 77.544 0.084 ;
    END
  END vm_rr1[107]
  PIN vm_rr1[108]
    DIRECTION INPUT ;
    USE SIGNAL ;
    PORT
      LAYER M5 ;
        RECT  77.712 0 77.736 0.084 ;
    END
  END vm_rr1[108]
  PIN vm_rr1[109]
    DIRECTION INPUT ;
    USE SIGNAL ;
    PORT
      LAYER M5 ;
        RECT  77.904 0 77.928 0.084 ;
    END
  END vm_rr1[109]
  PIN vm_rr1[10]
    DIRECTION INPUT ;
    USE SIGNAL ;
    PORT
      LAYER M5 ;
        RECT  59.184 0 59.208 0.084 ;
    END
  END vm_rr1[10]
  PIN vm_rr1[110]
    DIRECTION INPUT ;
    USE SIGNAL ;
    PORT
      LAYER M5 ;
        RECT  78.096 0 78.12 0.084 ;
    END
  END vm_rr1[110]
  PIN vm_rr1[111]
    DIRECTION INPUT ;
    USE SIGNAL ;
    PORT
      LAYER M5 ;
        RECT  78.288 0 78.312 0.084 ;
    END
  END vm_rr1[111]
  PIN vm_rr1[112]
    DIRECTION INPUT ;
    USE SIGNAL ;
    PORT
      LAYER M5 ;
        RECT  78.48 0 78.504 0.084 ;
    END
  END vm_rr1[112]
  PIN vm_rr1[113]
    DIRECTION INPUT ;
    USE SIGNAL ;
    PORT
      LAYER M5 ;
        RECT  78.672 0 78.696 0.084 ;
    END
  END vm_rr1[113]
  PIN vm_rr1[114]
    DIRECTION INPUT ;
    USE SIGNAL ;
    PORT
      LAYER M5 ;
        RECT  78.864 0 78.888 0.084 ;
    END
  END vm_rr1[114]
  PIN vm_rr1[115]
    DIRECTION INPUT ;
    USE SIGNAL ;
    PORT
      LAYER M5 ;
        RECT  79.056 0 79.08 0.084 ;
    END
  END vm_rr1[115]
  PIN vm_rr1[116]
    DIRECTION INPUT ;
    USE SIGNAL ;
    PORT
      LAYER M5 ;
        RECT  79.248 0 79.272 0.084 ;
    END
  END vm_rr1[116]
  PIN vm_rr1[117]
    DIRECTION INPUT ;
    USE SIGNAL ;
    PORT
      LAYER M5 ;
        RECT  79.44 0 79.464 0.084 ;
    END
  END vm_rr1[117]
  PIN vm_rr1[118]
    DIRECTION INPUT ;
    USE SIGNAL ;
    PORT
      LAYER M5 ;
        RECT  79.632 0 79.656 0.084 ;
    END
  END vm_rr1[118]
  PIN vm_rr1[119]
    DIRECTION INPUT ;
    USE SIGNAL ;
    PORT
      LAYER M5 ;
        RECT  79.824 0 79.848 0.084 ;
    END
  END vm_rr1[119]
  PIN vm_rr1[11]
    DIRECTION INPUT ;
    USE SIGNAL ;
    PORT
      LAYER M5 ;
        RECT  59.376 0 59.4 0.084 ;
    END
  END vm_rr1[11]
  PIN vm_rr1[120]
    DIRECTION INPUT ;
    USE SIGNAL ;
    PORT
      LAYER M5 ;
        RECT  80.016 0 80.04 0.084 ;
    END
  END vm_rr1[120]
  PIN vm_rr1[121]
    DIRECTION INPUT ;
    USE SIGNAL ;
    PORT
      LAYER M5 ;
        RECT  80.16 0 80.184 0.084 ;
    END
  END vm_rr1[121]
  PIN vm_rr1[122]
    DIRECTION INPUT ;
    USE SIGNAL ;
    PORT
      LAYER M5 ;
        RECT  80.352 0 80.376 0.084 ;
    END
  END vm_rr1[122]
  PIN vm_rr1[123]
    DIRECTION INPUT ;
    USE SIGNAL ;
    PORT
      LAYER M5 ;
        RECT  80.544 0 80.568 0.084 ;
    END
  END vm_rr1[123]
  PIN vm_rr1[124]
    DIRECTION INPUT ;
    USE SIGNAL ;
    PORT
      LAYER M5 ;
        RECT  80.736 0 80.76 0.084 ;
    END
  END vm_rr1[124]
  PIN vm_rr1[125]
    DIRECTION INPUT ;
    USE SIGNAL ;
    PORT
      LAYER M5 ;
        RECT  80.928 0 80.952 0.084 ;
    END
  END vm_rr1[125]
  PIN vm_rr1[126]
    DIRECTION INPUT ;
    USE SIGNAL ;
    PORT
      LAYER M5 ;
        RECT  81.12 0 81.144 0.084 ;
    END
  END vm_rr1[126]
  PIN vm_rr1[127]
    DIRECTION INPUT ;
    USE SIGNAL ;
    PORT
      LAYER M5 ;
        RECT  81.312 0 81.336 0.084 ;
    END
  END vm_rr1[127]
  PIN vm_rr1[128]
    DIRECTION INPUT ;
    USE SIGNAL ;
    PORT
      LAYER M5 ;
        RECT  81.504 0 81.528 0.084 ;
    END
  END vm_rr1[128]
  PIN vm_rr1[129]
    DIRECTION INPUT ;
    USE SIGNAL ;
    PORT
      LAYER M5 ;
        RECT  81.696 0 81.72 0.084 ;
    END
  END vm_rr1[129]
  PIN vm_rr1[12]
    DIRECTION INPUT ;
    USE SIGNAL ;
    PORT
      LAYER M5 ;
        RECT  59.568 0 59.592 0.084 ;
    END
  END vm_rr1[12]
  PIN vm_rr1[130]
    DIRECTION INPUT ;
    USE SIGNAL ;
    PORT
      LAYER M5 ;
        RECT  81.888 0 81.912 0.084 ;
    END
  END vm_rr1[130]
  PIN vm_rr1[131]
    DIRECTION INPUT ;
    USE SIGNAL ;
    PORT
      LAYER M5 ;
        RECT  82.08 0 82.104 0.084 ;
    END
  END vm_rr1[131]
  PIN vm_rr1[132]
    DIRECTION INPUT ;
    USE SIGNAL ;
    PORT
      LAYER M5 ;
        RECT  82.272 0 82.296 0.084 ;
    END
  END vm_rr1[132]
  PIN vm_rr1[133]
    DIRECTION INPUT ;
    USE SIGNAL ;
    PORT
      LAYER M5 ;
        RECT  82.464 0 82.488 0.084 ;
    END
  END vm_rr1[133]
  PIN vm_rr1[134]
    DIRECTION INPUT ;
    USE SIGNAL ;
    PORT
      LAYER M5 ;
        RECT  82.656 0 82.68 0.084 ;
    END
  END vm_rr1[134]
  PIN vm_rr1[135]
    DIRECTION INPUT ;
    USE SIGNAL ;
    PORT
      LAYER M5 ;
        RECT  82.848 0 82.872 0.084 ;
    END
  END vm_rr1[135]
  PIN vm_rr1[136]
    DIRECTION INPUT ;
    USE SIGNAL ;
    PORT
      LAYER M5 ;
        RECT  83.04 0 83.064 0.084 ;
    END
  END vm_rr1[136]
  PIN vm_rr1[137]
    DIRECTION INPUT ;
    USE SIGNAL ;
    PORT
      LAYER M5 ;
        RECT  83.232 0 83.256 0.084 ;
    END
  END vm_rr1[137]
  PIN vm_rr1[138]
    DIRECTION INPUT ;
    USE SIGNAL ;
    PORT
      LAYER M5 ;
        RECT  83.424 0 83.448 0.084 ;
    END
  END vm_rr1[138]
  PIN vm_rr1[139]
    DIRECTION INPUT ;
    USE SIGNAL ;
    PORT
      LAYER M5 ;
        RECT  83.568 0 83.592 0.084 ;
    END
  END vm_rr1[139]
  PIN vm_rr1[13]
    DIRECTION INPUT ;
    USE SIGNAL ;
    PORT
      LAYER M5 ;
        RECT  59.76 0 59.784 0.084 ;
    END
  END vm_rr1[13]
  PIN vm_rr1[140]
    DIRECTION INPUT ;
    USE SIGNAL ;
    PORT
      LAYER M5 ;
        RECT  83.76 0 83.784 0.084 ;
    END
  END vm_rr1[140]
  PIN vm_rr1[141]
    DIRECTION INPUT ;
    USE SIGNAL ;
    PORT
      LAYER M5 ;
        RECT  83.952 0 83.976 0.084 ;
    END
  END vm_rr1[141]
  PIN vm_rr1[142]
    DIRECTION INPUT ;
    USE SIGNAL ;
    PORT
      LAYER M5 ;
        RECT  84.144 0 84.168 0.084 ;
    END
  END vm_rr1[142]
  PIN vm_rr1[143]
    DIRECTION INPUT ;
    USE SIGNAL ;
    PORT
      LAYER M5 ;
        RECT  84.336 0 84.36 0.084 ;
    END
  END vm_rr1[143]
  PIN vm_rr1[144]
    DIRECTION INPUT ;
    USE SIGNAL ;
    PORT
      LAYER M5 ;
        RECT  84.528 0 84.552 0.084 ;
    END
  END vm_rr1[144]
  PIN vm_rr1[145]
    DIRECTION INPUT ;
    USE SIGNAL ;
    PORT
      LAYER M5 ;
        RECT  84.72 0 84.744 0.084 ;
    END
  END vm_rr1[145]
  PIN vm_rr1[146]
    DIRECTION INPUT ;
    USE SIGNAL ;
    PORT
      LAYER M5 ;
        RECT  84.912 0 84.936 0.084 ;
    END
  END vm_rr1[146]
  PIN vm_rr1[147]
    DIRECTION INPUT ;
    USE SIGNAL ;
    PORT
      LAYER M5 ;
        RECT  85.104 0 85.128 0.084 ;
    END
  END vm_rr1[147]
  PIN vm_rr1[148]
    DIRECTION INPUT ;
    USE SIGNAL ;
    PORT
      LAYER M5 ;
        RECT  85.296 0 85.32 0.084 ;
    END
  END vm_rr1[148]
  PIN vm_rr1[149]
    DIRECTION INPUT ;
    USE SIGNAL ;
    PORT
      LAYER M5 ;
        RECT  85.488 0 85.512 0.084 ;
    END
  END vm_rr1[149]
  PIN vm_rr1[14]
    DIRECTION INPUT ;
    USE SIGNAL ;
    PORT
      LAYER M5 ;
        RECT  59.952 0 59.976 0.084 ;
    END
  END vm_rr1[14]
  PIN vm_rr1[150]
    DIRECTION INPUT ;
    USE SIGNAL ;
    PORT
      LAYER M5 ;
        RECT  85.68 0 85.704 0.084 ;
    END
  END vm_rr1[150]
  PIN vm_rr1[151]
    DIRECTION INPUT ;
    USE SIGNAL ;
    PORT
      LAYER M5 ;
        RECT  85.872 0 85.896 0.084 ;
    END
  END vm_rr1[151]
  PIN vm_rr1[152]
    DIRECTION INPUT ;
    USE SIGNAL ;
    PORT
      LAYER M5 ;
        RECT  86.064 0 86.088 0.084 ;
    END
  END vm_rr1[152]
  PIN vm_rr1[153]
    DIRECTION INPUT ;
    USE SIGNAL ;
    PORT
      LAYER M5 ;
        RECT  86.256 0 86.28 0.084 ;
    END
  END vm_rr1[153]
  PIN vm_rr1[154]
    DIRECTION INPUT ;
    USE SIGNAL ;
    PORT
      LAYER M5 ;
        RECT  86.448 0 86.472 0.084 ;
    END
  END vm_rr1[154]
  PIN vm_rr1[155]
    DIRECTION INPUT ;
    USE SIGNAL ;
    PORT
      LAYER M5 ;
        RECT  86.64 0 86.664 0.084 ;
    END
  END vm_rr1[155]
  PIN vm_rr1[156]
    DIRECTION INPUT ;
    USE SIGNAL ;
    PORT
      LAYER M5 ;
        RECT  86.784 0 86.808 0.084 ;
    END
  END vm_rr1[156]
  PIN vm_rr1[157]
    DIRECTION INPUT ;
    USE SIGNAL ;
    PORT
      LAYER M5 ;
        RECT  86.976 0 87 0.084 ;
    END
  END vm_rr1[157]
  PIN vm_rr1[158]
    DIRECTION INPUT ;
    USE SIGNAL ;
    PORT
      LAYER M5 ;
        RECT  87.168 0 87.192 0.084 ;
    END
  END vm_rr1[158]
  PIN vm_rr1[159]
    DIRECTION INPUT ;
    USE SIGNAL ;
    PORT
      LAYER M5 ;
        RECT  87.36 0 87.384 0.084 ;
    END
  END vm_rr1[159]
  PIN vm_rr1[15]
    DIRECTION INPUT ;
    USE SIGNAL ;
    PORT
      LAYER M5 ;
        RECT  60.144 0 60.168 0.084 ;
    END
  END vm_rr1[15]
  PIN vm_rr1[160]
    DIRECTION INPUT ;
    USE SIGNAL ;
    PORT
      LAYER M5 ;
        RECT  87.552 0 87.576 0.084 ;
    END
  END vm_rr1[160]
  PIN vm_rr1[161]
    DIRECTION INPUT ;
    USE SIGNAL ;
    PORT
      LAYER M5 ;
        RECT  87.744 0 87.768 0.084 ;
    END
  END vm_rr1[161]
  PIN vm_rr1[162]
    DIRECTION INPUT ;
    USE SIGNAL ;
    PORT
      LAYER M5 ;
        RECT  87.936 0 87.96 0.084 ;
    END
  END vm_rr1[162]
  PIN vm_rr1[163]
    DIRECTION INPUT ;
    USE SIGNAL ;
    PORT
      LAYER M5 ;
        RECT  88.128 0 88.152 0.084 ;
    END
  END vm_rr1[163]
  PIN vm_rr1[164]
    DIRECTION INPUT ;
    USE SIGNAL ;
    PORT
      LAYER M5 ;
        RECT  88.32 0 88.344 0.084 ;
    END
  END vm_rr1[164]
  PIN vm_rr1[165]
    DIRECTION INPUT ;
    USE SIGNAL ;
    PORT
      LAYER M5 ;
        RECT  88.512 0 88.536 0.084 ;
    END
  END vm_rr1[165]
  PIN vm_rr1[166]
    DIRECTION INPUT ;
    USE SIGNAL ;
    PORT
      LAYER M5 ;
        RECT  88.704 0 88.728 0.084 ;
    END
  END vm_rr1[166]
  PIN vm_rr1[167]
    DIRECTION INPUT ;
    USE SIGNAL ;
    PORT
      LAYER M5 ;
        RECT  88.896 0 88.92 0.084 ;
    END
  END vm_rr1[167]
  PIN vm_rr1[168]
    DIRECTION INPUT ;
    USE SIGNAL ;
    PORT
      LAYER M5 ;
        RECT  89.088 0 89.112 0.084 ;
    END
  END vm_rr1[168]
  PIN vm_rr1[169]
    DIRECTION INPUT ;
    USE SIGNAL ;
    PORT
      LAYER M5 ;
        RECT  89.28 0 89.304 0.084 ;
    END
  END vm_rr1[169]
  PIN vm_rr1[16]
    DIRECTION INPUT ;
    USE SIGNAL ;
    PORT
      LAYER M5 ;
        RECT  60.288 0 60.312 0.084 ;
    END
  END vm_rr1[16]
  PIN vm_rr1[170]
    DIRECTION INPUT ;
    USE SIGNAL ;
    PORT
      LAYER M5 ;
        RECT  89.472 0 89.496 0.084 ;
    END
  END vm_rr1[170]
  PIN vm_rr1[171]
    DIRECTION INPUT ;
    USE SIGNAL ;
    PORT
      LAYER M5 ;
        RECT  89.664 0 89.688 0.084 ;
    END
  END vm_rr1[171]
  PIN vm_rr1[172]
    DIRECTION INPUT ;
    USE SIGNAL ;
    PORT
      LAYER M5 ;
        RECT  89.856 0 89.88 0.084 ;
    END
  END vm_rr1[172]
  PIN vm_rr1[173]
    DIRECTION INPUT ;
    USE SIGNAL ;
    PORT
      LAYER M5 ;
        RECT  90.048 0 90.072 0.084 ;
    END
  END vm_rr1[173]
  PIN vm_rr1[174]
    DIRECTION INPUT ;
    USE SIGNAL ;
    PORT
      LAYER M5 ;
        RECT  90.192 0 90.216 0.084 ;
    END
  END vm_rr1[174]
  PIN vm_rr1[175]
    DIRECTION INPUT ;
    USE SIGNAL ;
    PORT
      LAYER M5 ;
        RECT  90.384 0 90.408 0.084 ;
    END
  END vm_rr1[175]
  PIN vm_rr1[176]
    DIRECTION INPUT ;
    USE SIGNAL ;
    PORT
      LAYER M5 ;
        RECT  90.576 0 90.6 0.084 ;
    END
  END vm_rr1[176]
  PIN vm_rr1[177]
    DIRECTION INPUT ;
    USE SIGNAL ;
    PORT
      LAYER M5 ;
        RECT  90.768 0 90.792 0.084 ;
    END
  END vm_rr1[177]
  PIN vm_rr1[178]
    DIRECTION INPUT ;
    USE SIGNAL ;
    PORT
      LAYER M5 ;
        RECT  90.96 0 90.984 0.084 ;
    END
  END vm_rr1[178]
  PIN vm_rr1[179]
    DIRECTION INPUT ;
    USE SIGNAL ;
    PORT
      LAYER M5 ;
        RECT  91.152 0 91.176 0.084 ;
    END
  END vm_rr1[179]
  PIN vm_rr1[17]
    DIRECTION INPUT ;
    USE SIGNAL ;
    PORT
      LAYER M5 ;
        RECT  60.48 0 60.504 0.084 ;
    END
  END vm_rr1[17]
  PIN vm_rr1[180]
    DIRECTION INPUT ;
    USE SIGNAL ;
    PORT
      LAYER M5 ;
        RECT  91.344 0 91.368 0.084 ;
    END
  END vm_rr1[180]
  PIN vm_rr1[181]
    DIRECTION INPUT ;
    USE SIGNAL ;
    PORT
      LAYER M5 ;
        RECT  91.536 0 91.56 0.084 ;
    END
  END vm_rr1[181]
  PIN vm_rr1[182]
    DIRECTION INPUT ;
    USE SIGNAL ;
    PORT
      LAYER M5 ;
        RECT  91.728 0 91.752 0.084 ;
    END
  END vm_rr1[182]
  PIN vm_rr1[183]
    DIRECTION INPUT ;
    USE SIGNAL ;
    PORT
      LAYER M5 ;
        RECT  91.92 0 91.944 0.084 ;
    END
  END vm_rr1[183]
  PIN vm_rr1[184]
    DIRECTION INPUT ;
    USE SIGNAL ;
    PORT
      LAYER M5 ;
        RECT  92.112 0 92.136 0.084 ;
    END
  END vm_rr1[184]
  PIN vm_rr1[185]
    DIRECTION INPUT ;
    USE SIGNAL ;
    PORT
      LAYER M5 ;
        RECT  92.304 0 92.328 0.084 ;
    END
  END vm_rr1[185]
  PIN vm_rr1[186]
    DIRECTION INPUT ;
    USE SIGNAL ;
    PORT
      LAYER M5 ;
        RECT  92.496 0 92.52 0.084 ;
    END
  END vm_rr1[186]
  PIN vm_rr1[187]
    DIRECTION INPUT ;
    USE SIGNAL ;
    PORT
      LAYER M5 ;
        RECT  92.688 0 92.712 0.084 ;
    END
  END vm_rr1[187]
  PIN vm_rr1[188]
    DIRECTION INPUT ;
    USE SIGNAL ;
    PORT
      LAYER M5 ;
        RECT  92.88 0 92.904 0.084 ;
    END
  END vm_rr1[188]
  PIN vm_rr1[189]
    DIRECTION INPUT ;
    USE SIGNAL ;
    PORT
      LAYER M5 ;
        RECT  93.072 0 93.096 0.084 ;
    END
  END vm_rr1[189]
  PIN vm_rr1[18]
    DIRECTION INPUT ;
    USE SIGNAL ;
    PORT
      LAYER M5 ;
        RECT  60.672 0 60.696 0.084 ;
    END
  END vm_rr1[18]
  PIN vm_rr1[190]
    DIRECTION INPUT ;
    USE SIGNAL ;
    PORT
      LAYER M5 ;
        RECT  93.264 0 93.288 0.084 ;
    END
  END vm_rr1[190]
  PIN vm_rr1[191]
    DIRECTION INPUT ;
    USE SIGNAL ;
    PORT
      LAYER M5 ;
        RECT  93.408 0 93.432 0.084 ;
    END
  END vm_rr1[191]
  PIN vm_rr1[192]
    DIRECTION INPUT ;
    USE SIGNAL ;
    PORT
      LAYER M5 ;
        RECT  93.6 0 93.624 0.084 ;
    END
  END vm_rr1[192]
  PIN vm_rr1[193]
    DIRECTION INPUT ;
    USE SIGNAL ;
    PORT
      LAYER M5 ;
        RECT  93.792 0 93.816 0.084 ;
    END
  END vm_rr1[193]
  PIN vm_rr1[194]
    DIRECTION INPUT ;
    USE SIGNAL ;
    PORT
      LAYER M5 ;
        RECT  93.984 0 94.008 0.084 ;
    END
  END vm_rr1[194]
  PIN vm_rr1[195]
    DIRECTION INPUT ;
    USE SIGNAL ;
    PORT
      LAYER M5 ;
        RECT  94.176 0 94.2 0.084 ;
    END
  END vm_rr1[195]
  PIN vm_rr1[196]
    DIRECTION INPUT ;
    USE SIGNAL ;
    PORT
      LAYER M5 ;
        RECT  94.368 0 94.392 0.084 ;
    END
  END vm_rr1[196]
  PIN vm_rr1[197]
    DIRECTION INPUT ;
    USE SIGNAL ;
    PORT
      LAYER M5 ;
        RECT  94.56 0 94.584 0.084 ;
    END
  END vm_rr1[197]
  PIN vm_rr1[198]
    DIRECTION INPUT ;
    USE SIGNAL ;
    PORT
      LAYER M5 ;
        RECT  94.752 0 94.776 0.084 ;
    END
  END vm_rr1[198]
  PIN vm_rr1[199]
    DIRECTION INPUT ;
    USE SIGNAL ;
    PORT
      LAYER M5 ;
        RECT  94.944 0 94.968 0.084 ;
    END
  END vm_rr1[199]
  PIN vm_rr1[19]
    DIRECTION INPUT ;
    USE SIGNAL ;
    PORT
      LAYER M5 ;
        RECT  60.864 0 60.888 0.084 ;
    END
  END vm_rr1[19]
  PIN vm_rr1[1]
    DIRECTION INPUT ;
    USE SIGNAL ;
    PORT
      LAYER M5 ;
        RECT  57.456 0 57.48 0.084 ;
    END
  END vm_rr1[1]
  PIN vm_rr1[200]
    DIRECTION INPUT ;
    USE SIGNAL ;
    PORT
      LAYER M5 ;
        RECT  95.136 0 95.16 0.084 ;
    END
  END vm_rr1[200]
  PIN vm_rr1[201]
    DIRECTION INPUT ;
    USE SIGNAL ;
    PORT
      LAYER M5 ;
        RECT  95.328 0 95.352 0.084 ;
    END
  END vm_rr1[201]
  PIN vm_rr1[202]
    DIRECTION INPUT ;
    USE SIGNAL ;
    PORT
      LAYER M5 ;
        RECT  95.52 0 95.544 0.084 ;
    END
  END vm_rr1[202]
  PIN vm_rr1[203]
    DIRECTION INPUT ;
    USE SIGNAL ;
    PORT
      LAYER M5 ;
        RECT  95.712 0 95.736 0.084 ;
    END
  END vm_rr1[203]
  PIN vm_rr1[204]
    DIRECTION INPUT ;
    USE SIGNAL ;
    PORT
      LAYER M5 ;
        RECT  95.904 0 95.928 0.084 ;
    END
  END vm_rr1[204]
  PIN vm_rr1[205]
    DIRECTION INPUT ;
    USE SIGNAL ;
    PORT
      LAYER M5 ;
        RECT  96.096 0 96.12 0.084 ;
    END
  END vm_rr1[205]
  PIN vm_rr1[206]
    DIRECTION INPUT ;
    USE SIGNAL ;
    PORT
      LAYER M5 ;
        RECT  96.288 0 96.312 0.084 ;
    END
  END vm_rr1[206]
  PIN vm_rr1[207]
    DIRECTION INPUT ;
    USE SIGNAL ;
    PORT
      LAYER M5 ;
        RECT  96.48 0 96.504 0.084 ;
    END
  END vm_rr1[207]
  PIN vm_rr1[208]
    DIRECTION INPUT ;
    USE SIGNAL ;
    PORT
      LAYER M5 ;
        RECT  96.672 0 96.696 0.084 ;
    END
  END vm_rr1[208]
  PIN vm_rr1[209]
    DIRECTION INPUT ;
    USE SIGNAL ;
    PORT
      LAYER M5 ;
        RECT  96.816 0 96.84 0.084 ;
    END
  END vm_rr1[209]
  PIN vm_rr1[20]
    DIRECTION INPUT ;
    USE SIGNAL ;
    PORT
      LAYER M5 ;
        RECT  61.056 0 61.08 0.084 ;
    END
  END vm_rr1[20]
  PIN vm_rr1[210]
    DIRECTION INPUT ;
    USE SIGNAL ;
    PORT
      LAYER M5 ;
        RECT  97.008 0 97.032 0.084 ;
    END
  END vm_rr1[210]
  PIN vm_rr1[211]
    DIRECTION INPUT ;
    USE SIGNAL ;
    PORT
      LAYER M5 ;
        RECT  97.2 0 97.224 0.084 ;
    END
  END vm_rr1[211]
  PIN vm_rr1[212]
    DIRECTION INPUT ;
    USE SIGNAL ;
    PORT
      LAYER M5 ;
        RECT  97.392 0 97.416 0.084 ;
    END
  END vm_rr1[212]
  PIN vm_rr1[213]
    DIRECTION INPUT ;
    USE SIGNAL ;
    PORT
      LAYER M5 ;
        RECT  97.584 0 97.608 0.084 ;
    END
  END vm_rr1[213]
  PIN vm_rr1[214]
    DIRECTION INPUT ;
    USE SIGNAL ;
    PORT
      LAYER M5 ;
        RECT  97.776 0 97.8 0.084 ;
    END
  END vm_rr1[214]
  PIN vm_rr1[215]
    DIRECTION INPUT ;
    USE SIGNAL ;
    PORT
      LAYER M5 ;
        RECT  97.968 0 97.992 0.084 ;
    END
  END vm_rr1[215]
  PIN vm_rr1[216]
    DIRECTION INPUT ;
    USE SIGNAL ;
    PORT
      LAYER M5 ;
        RECT  98.16 0 98.184 0.084 ;
    END
  END vm_rr1[216]
  PIN vm_rr1[217]
    DIRECTION INPUT ;
    USE SIGNAL ;
    PORT
      LAYER M5 ;
        RECT  98.352 0 98.376 0.084 ;
    END
  END vm_rr1[217]
  PIN vm_rr1[218]
    DIRECTION INPUT ;
    USE SIGNAL ;
    PORT
      LAYER M5 ;
        RECT  98.544 0 98.568 0.084 ;
    END
  END vm_rr1[218]
  PIN vm_rr1[219]
    DIRECTION INPUT ;
    USE SIGNAL ;
    PORT
      LAYER M5 ;
        RECT  98.736 0 98.76 0.084 ;
    END
  END vm_rr1[219]
  PIN vm_rr1[21]
    DIRECTION INPUT ;
    USE SIGNAL ;
    PORT
      LAYER M5 ;
        RECT  61.248 0 61.272 0.084 ;
    END
  END vm_rr1[21]
  PIN vm_rr1[220]
    DIRECTION INPUT ;
    USE SIGNAL ;
    PORT
      LAYER M5 ;
        RECT  98.928 0 98.952 0.084 ;
    END
  END vm_rr1[220]
  PIN vm_rr1[221]
    DIRECTION INPUT ;
    USE SIGNAL ;
    PORT
      LAYER M5 ;
        RECT  99.12 0 99.144 0.084 ;
    END
  END vm_rr1[221]
  PIN vm_rr1[222]
    DIRECTION INPUT ;
    USE SIGNAL ;
    PORT
      LAYER M5 ;
        RECT  99.312 0 99.336 0.084 ;
    END
  END vm_rr1[222]
  PIN vm_rr1[223]
    DIRECTION INPUT ;
    USE SIGNAL ;
    PORT
      LAYER M5 ;
        RECT  99.504 0 99.528 0.084 ;
    END
  END vm_rr1[223]
  PIN vm_rr1[224]
    DIRECTION INPUT ;
    USE SIGNAL ;
    PORT
      LAYER M5 ;
        RECT  99.696 0 99.72 0.084 ;
    END
  END vm_rr1[224]
  PIN vm_rr1[225]
    DIRECTION INPUT ;
    USE SIGNAL ;
    PORT
      LAYER M5 ;
        RECT  99.888 0 99.912 0.084 ;
    END
  END vm_rr1[225]
  PIN vm_rr1[226]
    DIRECTION INPUT ;
    USE SIGNAL ;
    PORT
      LAYER M5 ;
        RECT  100.08 0 100.104 0.084 ;
    END
  END vm_rr1[226]
  PIN vm_rr1[227]
    DIRECTION INPUT ;
    USE SIGNAL ;
    PORT
      LAYER M5 ;
        RECT  100.224 0 100.248 0.084 ;
    END
  END vm_rr1[227]
  PIN vm_rr1[228]
    DIRECTION INPUT ;
    USE SIGNAL ;
    PORT
      LAYER M5 ;
        RECT  100.416 0 100.44 0.084 ;
    END
  END vm_rr1[228]
  PIN vm_rr1[229]
    DIRECTION INPUT ;
    USE SIGNAL ;
    PORT
      LAYER M5 ;
        RECT  100.608 0 100.632 0.084 ;
    END
  END vm_rr1[229]
  PIN vm_rr1[22]
    DIRECTION INPUT ;
    USE SIGNAL ;
    PORT
      LAYER M5 ;
        RECT  61.44 0 61.464 0.084 ;
    END
  END vm_rr1[22]
  PIN vm_rr1[230]
    DIRECTION INPUT ;
    USE SIGNAL ;
    PORT
      LAYER M5 ;
        RECT  100.8 0 100.824 0.084 ;
    END
  END vm_rr1[230]
  PIN vm_rr1[231]
    DIRECTION INPUT ;
    USE SIGNAL ;
    PORT
      LAYER M5 ;
        RECT  100.992 0 101.016 0.084 ;
    END
  END vm_rr1[231]
  PIN vm_rr1[232]
    DIRECTION INPUT ;
    USE SIGNAL ;
    PORT
      LAYER M5 ;
        RECT  101.184 0 101.208 0.084 ;
    END
  END vm_rr1[232]
  PIN vm_rr1[233]
    DIRECTION INPUT ;
    USE SIGNAL ;
    PORT
      LAYER M5 ;
        RECT  101.376 0 101.4 0.084 ;
    END
  END vm_rr1[233]
  PIN vm_rr1[234]
    DIRECTION INPUT ;
    USE SIGNAL ;
    PORT
      LAYER M5 ;
        RECT  101.568 0 101.592 0.084 ;
    END
  END vm_rr1[234]
  PIN vm_rr1[235]
    DIRECTION INPUT ;
    USE SIGNAL ;
    PORT
      LAYER M5 ;
        RECT  101.76 0 101.784 0.084 ;
    END
  END vm_rr1[235]
  PIN vm_rr1[236]
    DIRECTION INPUT ;
    USE SIGNAL ;
    PORT
      LAYER M5 ;
        RECT  101.952 0 101.976 0.084 ;
    END
  END vm_rr1[236]
  PIN vm_rr1[237]
    DIRECTION INPUT ;
    USE SIGNAL ;
    PORT
      LAYER M5 ;
        RECT  102.144 0 102.168 0.084 ;
    END
  END vm_rr1[237]
  PIN vm_rr1[238]
    DIRECTION INPUT ;
    USE SIGNAL ;
    PORT
      LAYER M5 ;
        RECT  102.336 0 102.36 0.084 ;
    END
  END vm_rr1[238]
  PIN vm_rr1[239]
    DIRECTION INPUT ;
    USE SIGNAL ;
    PORT
      LAYER M5 ;
        RECT  102.528 0 102.552 0.084 ;
    END
  END vm_rr1[239]
  PIN vm_rr1[23]
    DIRECTION INPUT ;
    USE SIGNAL ;
    PORT
      LAYER M5 ;
        RECT  61.632 0 61.656 0.084 ;
    END
  END vm_rr1[23]
  PIN vm_rr1[240]
    DIRECTION INPUT ;
    USE SIGNAL ;
    PORT
      LAYER M5 ;
        RECT  102.72 0 102.744 0.084 ;
    END
  END vm_rr1[240]
  PIN vm_rr1[241]
    DIRECTION INPUT ;
    USE SIGNAL ;
    PORT
      LAYER M5 ;
        RECT  102.912 0 102.936 0.084 ;
    END
  END vm_rr1[241]
  PIN vm_rr1[242]
    DIRECTION INPUT ;
    USE SIGNAL ;
    PORT
      LAYER M5 ;
        RECT  103.104 0 103.128 0.084 ;
    END
  END vm_rr1[242]
  PIN vm_rr1[243]
    DIRECTION INPUT ;
    USE SIGNAL ;
    PORT
      LAYER M5 ;
        RECT  103.296 0 103.32 0.084 ;
    END
  END vm_rr1[243]
  PIN vm_rr1[244]
    DIRECTION INPUT ;
    USE SIGNAL ;
    PORT
      LAYER M5 ;
        RECT  103.44 0 103.464 0.084 ;
    END
  END vm_rr1[244]
  PIN vm_rr1[245]
    DIRECTION INPUT ;
    USE SIGNAL ;
    PORT
      LAYER M5 ;
        RECT  103.632 0 103.656 0.084 ;
    END
  END vm_rr1[245]
  PIN vm_rr1[246]
    DIRECTION INPUT ;
    USE SIGNAL ;
    PORT
      LAYER M5 ;
        RECT  103.824 0 103.848 0.084 ;
    END
  END vm_rr1[246]
  PIN vm_rr1[247]
    DIRECTION INPUT ;
    USE SIGNAL ;
    PORT
      LAYER M5 ;
        RECT  104.016 0 104.04 0.084 ;
    END
  END vm_rr1[247]
  PIN vm_rr1[248]
    DIRECTION INPUT ;
    USE SIGNAL ;
    PORT
      LAYER M5 ;
        RECT  104.208 0 104.232 0.084 ;
    END
  END vm_rr1[248]
  PIN vm_rr1[249]
    DIRECTION INPUT ;
    USE SIGNAL ;
    PORT
      LAYER M5 ;
        RECT  104.4 0 104.424 0.084 ;
    END
  END vm_rr1[249]
  PIN vm_rr1[24]
    DIRECTION INPUT ;
    USE SIGNAL ;
    PORT
      LAYER M5 ;
        RECT  61.824 0 61.848 0.084 ;
    END
  END vm_rr1[24]
  PIN vm_rr1[250]
    DIRECTION INPUT ;
    USE SIGNAL ;
    PORT
      LAYER M5 ;
        RECT  104.592 0 104.616 0.084 ;
    END
  END vm_rr1[250]
  PIN vm_rr1[251]
    DIRECTION INPUT ;
    USE SIGNAL ;
    PORT
      LAYER M5 ;
        RECT  104.784 0 104.808 0.084 ;
    END
  END vm_rr1[251]
  PIN vm_rr1[252]
    DIRECTION INPUT ;
    USE SIGNAL ;
    PORT
      LAYER M5 ;
        RECT  104.976 0 105 0.084 ;
    END
  END vm_rr1[252]
  PIN vm_rr1[253]
    DIRECTION INPUT ;
    USE SIGNAL ;
    PORT
      LAYER M5 ;
        RECT  105.168 0 105.192 0.084 ;
    END
  END vm_rr1[253]
  PIN vm_rr1[254]
    DIRECTION INPUT ;
    USE SIGNAL ;
    PORT
      LAYER M5 ;
        RECT  105.36 0 105.384 0.084 ;
    END
  END vm_rr1[254]
  PIN vm_rr1[255]
    DIRECTION INPUT ;
    USE SIGNAL ;
    PORT
      LAYER M5 ;
        RECT  105.552 0 105.576 0.084 ;
    END
  END vm_rr1[255]
  PIN vm_rr1[256]
    DIRECTION INPUT ;
    USE SIGNAL ;
    PORT
      LAYER M5 ;
        RECT  105.744 0 105.768 0.084 ;
    END
  END vm_rr1[256]
  PIN vm_rr1[25]
    DIRECTION INPUT ;
    USE SIGNAL ;
    PORT
      LAYER M5 ;
        RECT  62.016 0 62.04 0.084 ;
    END
  END vm_rr1[25]
  PIN vm_rr1[26]
    DIRECTION INPUT ;
    USE SIGNAL ;
    PORT
      LAYER M5 ;
        RECT  62.208 0 62.232 0.084 ;
    END
  END vm_rr1[26]
  PIN vm_rr1[27]
    DIRECTION INPUT ;
    USE SIGNAL ;
    PORT
      LAYER M5 ;
        RECT  62.4 0 62.424 0.084 ;
    END
  END vm_rr1[27]
  PIN vm_rr1[28]
    DIRECTION INPUT ;
    USE SIGNAL ;
    PORT
      LAYER M5 ;
        RECT  62.592 0 62.616 0.084 ;
    END
  END vm_rr1[28]
  PIN vm_rr1[29]
    DIRECTION INPUT ;
    USE SIGNAL ;
    PORT
      LAYER M5 ;
        RECT  62.784 0 62.808 0.084 ;
    END
  END vm_rr1[29]
  PIN vm_rr1[2]
    DIRECTION INPUT ;
    USE SIGNAL ;
    PORT
      LAYER M5 ;
        RECT  57.648 0 57.672 0.084 ;
    END
  END vm_rr1[2]
  PIN vm_rr1[30]
    DIRECTION INPUT ;
    USE SIGNAL ;
    PORT
      LAYER M5 ;
        RECT  62.976 0 63 0.084 ;
    END
  END vm_rr1[30]
  PIN vm_rr1[31]
    DIRECTION INPUT ;
    USE SIGNAL ;
    PORT
      LAYER M5 ;
        RECT  63.168 0 63.192 0.084 ;
    END
  END vm_rr1[31]
  PIN vm_rr1[32]
    DIRECTION INPUT ;
    USE SIGNAL ;
    PORT
      LAYER M5 ;
        RECT  63.36 0 63.384 0.084 ;
    END
  END vm_rr1[32]
  PIN vm_rr1[33]
    DIRECTION INPUT ;
    USE SIGNAL ;
    PORT
      LAYER M5 ;
        RECT  63.552 0 63.576 0.084 ;
    END
  END vm_rr1[33]
  PIN vm_rr1[34]
    DIRECTION INPUT ;
    USE SIGNAL ;
    PORT
      LAYER M5 ;
        RECT  63.696 0 63.72 0.084 ;
    END
  END vm_rr1[34]
  PIN vm_rr1[35]
    DIRECTION INPUT ;
    USE SIGNAL ;
    PORT
      LAYER M5 ;
        RECT  63.888 0 63.912 0.084 ;
    END
  END vm_rr1[35]
  PIN vm_rr1[36]
    DIRECTION INPUT ;
    USE SIGNAL ;
    PORT
      LAYER M5 ;
        RECT  64.08 0 64.104 0.084 ;
    END
  END vm_rr1[36]
  PIN vm_rr1[37]
    DIRECTION INPUT ;
    USE SIGNAL ;
    PORT
      LAYER M5 ;
        RECT  64.272 0 64.296 0.084 ;
    END
  END vm_rr1[37]
  PIN vm_rr1[38]
    DIRECTION INPUT ;
    USE SIGNAL ;
    PORT
      LAYER M5 ;
        RECT  64.464 0 64.488 0.084 ;
    END
  END vm_rr1[38]
  PIN vm_rr1[39]
    DIRECTION INPUT ;
    USE SIGNAL ;
    PORT
      LAYER M5 ;
        RECT  64.656 0 64.68 0.084 ;
    END
  END vm_rr1[39]
  PIN vm_rr1[3]
    DIRECTION INPUT ;
    USE SIGNAL ;
    PORT
      LAYER M5 ;
        RECT  57.84 0 57.864 0.084 ;
    END
  END vm_rr1[3]
  PIN vm_rr1[40]
    DIRECTION INPUT ;
    USE SIGNAL ;
    PORT
      LAYER M5 ;
        RECT  64.848 0 64.872 0.084 ;
    END
  END vm_rr1[40]
  PIN vm_rr1[41]
    DIRECTION INPUT ;
    USE SIGNAL ;
    PORT
      LAYER M5 ;
        RECT  65.04 0 65.064 0.084 ;
    END
  END vm_rr1[41]
  PIN vm_rr1[42]
    DIRECTION INPUT ;
    USE SIGNAL ;
    PORT
      LAYER M5 ;
        RECT  65.232 0 65.256 0.084 ;
    END
  END vm_rr1[42]
  PIN vm_rr1[43]
    DIRECTION INPUT ;
    USE SIGNAL ;
    PORT
      LAYER M5 ;
        RECT  65.424 0 65.448 0.084 ;
    END
  END vm_rr1[43]
  PIN vm_rr1[44]
    DIRECTION INPUT ;
    USE SIGNAL ;
    PORT
      LAYER M5 ;
        RECT  65.616 0 65.64 0.084 ;
    END
  END vm_rr1[44]
  PIN vm_rr1[45]
    DIRECTION INPUT ;
    USE SIGNAL ;
    PORT
      LAYER M5 ;
        RECT  65.808 0 65.832 0.084 ;
    END
  END vm_rr1[45]
  PIN vm_rr1[46]
    DIRECTION INPUT ;
    USE SIGNAL ;
    PORT
      LAYER M5 ;
        RECT  66 0 66.024 0.084 ;
    END
  END vm_rr1[46]
  PIN vm_rr1[47]
    DIRECTION INPUT ;
    USE SIGNAL ;
    PORT
      LAYER M5 ;
        RECT  66.192 0 66.216 0.084 ;
    END
  END vm_rr1[47]
  PIN vm_rr1[48]
    DIRECTION INPUT ;
    USE SIGNAL ;
    PORT
      LAYER M5 ;
        RECT  66.384 0 66.408 0.084 ;
    END
  END vm_rr1[48]
  PIN vm_rr1[49]
    DIRECTION INPUT ;
    USE SIGNAL ;
    PORT
      LAYER M5 ;
        RECT  66.576 0 66.6 0.084 ;
    END
  END vm_rr1[49]
  PIN vm_rr1[4]
    DIRECTION INPUT ;
    USE SIGNAL ;
    PORT
      LAYER M5 ;
        RECT  58.032 0 58.056 0.084 ;
    END
  END vm_rr1[4]
  PIN vm_rr1[50]
    DIRECTION INPUT ;
    USE SIGNAL ;
    PORT
      LAYER M5 ;
        RECT  66.768 0 66.792 0.084 ;
    END
  END vm_rr1[50]
  PIN vm_rr1[51]
    DIRECTION INPUT ;
    USE SIGNAL ;
    PORT
      LAYER M5 ;
        RECT  66.912 0 66.936 0.084 ;
    END
  END vm_rr1[51]
  PIN vm_rr1[52]
    DIRECTION INPUT ;
    USE SIGNAL ;
    PORT
      LAYER M5 ;
        RECT  67.104 0 67.128 0.084 ;
    END
  END vm_rr1[52]
  PIN vm_rr1[53]
    DIRECTION INPUT ;
    USE SIGNAL ;
    PORT
      LAYER M5 ;
        RECT  67.296 0 67.32 0.084 ;
    END
  END vm_rr1[53]
  PIN vm_rr1[54]
    DIRECTION INPUT ;
    USE SIGNAL ;
    PORT
      LAYER M5 ;
        RECT  67.488 0 67.512 0.084 ;
    END
  END vm_rr1[54]
  PIN vm_rr1[55]
    DIRECTION INPUT ;
    USE SIGNAL ;
    PORT
      LAYER M5 ;
        RECT  67.68 0 67.704 0.084 ;
    END
  END vm_rr1[55]
  PIN vm_rr1[56]
    DIRECTION INPUT ;
    USE SIGNAL ;
    PORT
      LAYER M5 ;
        RECT  67.872 0 67.896 0.084 ;
    END
  END vm_rr1[56]
  PIN vm_rr1[57]
    DIRECTION INPUT ;
    USE SIGNAL ;
    PORT
      LAYER M5 ;
        RECT  68.064 0 68.088 0.084 ;
    END
  END vm_rr1[57]
  PIN vm_rr1[58]
    DIRECTION INPUT ;
    USE SIGNAL ;
    PORT
      LAYER M5 ;
        RECT  68.256 0 68.28 0.084 ;
    END
  END vm_rr1[58]
  PIN vm_rr1[59]
    DIRECTION INPUT ;
    USE SIGNAL ;
    PORT
      LAYER M5 ;
        RECT  68.448 0 68.472 0.084 ;
    END
  END vm_rr1[59]
  PIN vm_rr1[5]
    DIRECTION INPUT ;
    USE SIGNAL ;
    PORT
      LAYER M5 ;
        RECT  58.224 0 58.248 0.084 ;
    END
  END vm_rr1[5]
  PIN vm_rr1[60]
    DIRECTION INPUT ;
    USE SIGNAL ;
    PORT
      LAYER M5 ;
        RECT  68.64 0 68.664 0.084 ;
    END
  END vm_rr1[60]
  PIN vm_rr1[61]
    DIRECTION INPUT ;
    USE SIGNAL ;
    PORT
      LAYER M5 ;
        RECT  68.832 0 68.856 0.084 ;
    END
  END vm_rr1[61]
  PIN vm_rr1[62]
    DIRECTION INPUT ;
    USE SIGNAL ;
    PORT
      LAYER M5 ;
        RECT  69.024 0 69.048 0.084 ;
    END
  END vm_rr1[62]
  PIN vm_rr1[63]
    DIRECTION INPUT ;
    USE SIGNAL ;
    PORT
      LAYER M5 ;
        RECT  69.216 0 69.24 0.084 ;
    END
  END vm_rr1[63]
  PIN vm_rr1[64]
    DIRECTION INPUT ;
    USE SIGNAL ;
    PORT
      LAYER M5 ;
        RECT  69.408 0 69.432 0.084 ;
    END
  END vm_rr1[64]
  PIN vm_rr1[65]
    DIRECTION INPUT ;
    USE SIGNAL ;
    PORT
      LAYER M5 ;
        RECT  69.6 0 69.624 0.084 ;
    END
  END vm_rr1[65]
  PIN vm_rr1[66]
    DIRECTION INPUT ;
    USE SIGNAL ;
    PORT
      LAYER M5 ;
        RECT  69.792 0 69.816 0.084 ;
    END
  END vm_rr1[66]
  PIN vm_rr1[67]
    DIRECTION INPUT ;
    USE SIGNAL ;
    PORT
      LAYER M5 ;
        RECT  69.984 0 70.008 0.084 ;
    END
  END vm_rr1[67]
  PIN vm_rr1[68]
    DIRECTION INPUT ;
    USE SIGNAL ;
    PORT
      LAYER M5 ;
        RECT  70.176 0 70.2 0.084 ;
    END
  END vm_rr1[68]
  PIN vm_rr1[69]
    DIRECTION INPUT ;
    USE SIGNAL ;
    PORT
      LAYER M5 ;
        RECT  70.32 0 70.344 0.084 ;
    END
  END vm_rr1[69]
  PIN vm_rr1[6]
    DIRECTION INPUT ;
    USE SIGNAL ;
    PORT
      LAYER M5 ;
        RECT  58.416 0 58.44 0.084 ;
    END
  END vm_rr1[6]
  PIN vm_rr1[70]
    DIRECTION INPUT ;
    USE SIGNAL ;
    PORT
      LAYER M5 ;
        RECT  70.512 0 70.536 0.084 ;
    END
  END vm_rr1[70]
  PIN vm_rr1[71]
    DIRECTION INPUT ;
    USE SIGNAL ;
    PORT
      LAYER M5 ;
        RECT  70.704 0 70.728 0.084 ;
    END
  END vm_rr1[71]
  PIN vm_rr1[72]
    DIRECTION INPUT ;
    USE SIGNAL ;
    PORT
      LAYER M5 ;
        RECT  70.896 0 70.92 0.084 ;
    END
  END vm_rr1[72]
  PIN vm_rr1[73]
    DIRECTION INPUT ;
    USE SIGNAL ;
    PORT
      LAYER M5 ;
        RECT  71.088 0 71.112 0.084 ;
    END
  END vm_rr1[73]
  PIN vm_rr1[74]
    DIRECTION INPUT ;
    USE SIGNAL ;
    PORT
      LAYER M5 ;
        RECT  71.28 0 71.304 0.084 ;
    END
  END vm_rr1[74]
  PIN vm_rr1[75]
    DIRECTION INPUT ;
    USE SIGNAL ;
    PORT
      LAYER M5 ;
        RECT  71.472 0 71.496 0.084 ;
    END
  END vm_rr1[75]
  PIN vm_rr1[76]
    DIRECTION INPUT ;
    USE SIGNAL ;
    PORT
      LAYER M5 ;
        RECT  71.664 0 71.688 0.084 ;
    END
  END vm_rr1[76]
  PIN vm_rr1[77]
    DIRECTION INPUT ;
    USE SIGNAL ;
    PORT
      LAYER M5 ;
        RECT  71.856 0 71.88 0.084 ;
    END
  END vm_rr1[77]
  PIN vm_rr1[78]
    DIRECTION INPUT ;
    USE SIGNAL ;
    PORT
      LAYER M5 ;
        RECT  72.048 0 72.072 0.084 ;
    END
  END vm_rr1[78]
  PIN vm_rr1[79]
    DIRECTION INPUT ;
    USE SIGNAL ;
    PORT
      LAYER M5 ;
        RECT  72.24 0 72.264 0.084 ;
    END
  END vm_rr1[79]
  PIN vm_rr1[7]
    DIRECTION INPUT ;
    USE SIGNAL ;
    PORT
      LAYER M5 ;
        RECT  58.608 0 58.632 0.084 ;
    END
  END vm_rr1[7]
  PIN vm_rr1[80]
    DIRECTION INPUT ;
    USE SIGNAL ;
    PORT
      LAYER M5 ;
        RECT  72.432 0 72.456 0.084 ;
    END
  END vm_rr1[80]
  PIN vm_rr1[81]
    DIRECTION INPUT ;
    USE SIGNAL ;
    PORT
      LAYER M5 ;
        RECT  72.624 0 72.648 0.084 ;
    END
  END vm_rr1[81]
  PIN vm_rr1[82]
    DIRECTION INPUT ;
    USE SIGNAL ;
    PORT
      LAYER M5 ;
        RECT  72.816 0 72.84 0.084 ;
    END
  END vm_rr1[82]
  PIN vm_rr1[83]
    DIRECTION INPUT ;
    USE SIGNAL ;
    PORT
      LAYER M5 ;
        RECT  73.008 0 73.032 0.084 ;
    END
  END vm_rr1[83]
  PIN vm_rr1[84]
    DIRECTION INPUT ;
    USE SIGNAL ;
    PORT
      LAYER M5 ;
        RECT  73.2 0 73.224 0.084 ;
    END
  END vm_rr1[84]
  PIN vm_rr1[85]
    DIRECTION INPUT ;
    USE SIGNAL ;
    PORT
      LAYER M5 ;
        RECT  73.392 0 73.416 0.084 ;
    END
  END vm_rr1[85]
  PIN vm_rr1[86]
    DIRECTION INPUT ;
    USE SIGNAL ;
    PORT
      LAYER M5 ;
        RECT  73.536 0 73.56 0.084 ;
    END
  END vm_rr1[86]
  PIN vm_rr1[87]
    DIRECTION INPUT ;
    USE SIGNAL ;
    PORT
      LAYER M5 ;
        RECT  73.728 0 73.752 0.084 ;
    END
  END vm_rr1[87]
  PIN vm_rr1[88]
    DIRECTION INPUT ;
    USE SIGNAL ;
    PORT
      LAYER M5 ;
        RECT  73.92 0 73.944 0.084 ;
    END
  END vm_rr1[88]
  PIN vm_rr1[89]
    DIRECTION INPUT ;
    USE SIGNAL ;
    PORT
      LAYER M5 ;
        RECT  74.112 0 74.136 0.084 ;
    END
  END vm_rr1[89]
  PIN vm_rr1[8]
    DIRECTION INPUT ;
    USE SIGNAL ;
    PORT
      LAYER M5 ;
        RECT  58.8 0 58.824 0.084 ;
    END
  END vm_rr1[8]
  PIN vm_rr1[90]
    DIRECTION INPUT ;
    USE SIGNAL ;
    PORT
      LAYER M5 ;
        RECT  74.304 0 74.328 0.084 ;
    END
  END vm_rr1[90]
  PIN vm_rr1[91]
    DIRECTION INPUT ;
    USE SIGNAL ;
    PORT
      LAYER M5 ;
        RECT  74.496 0 74.52 0.084 ;
    END
  END vm_rr1[91]
  PIN vm_rr1[92]
    DIRECTION INPUT ;
    USE SIGNAL ;
    PORT
      LAYER M5 ;
        RECT  74.688 0 74.712 0.084 ;
    END
  END vm_rr1[92]
  PIN vm_rr1[93]
    DIRECTION INPUT ;
    USE SIGNAL ;
    PORT
      LAYER M5 ;
        RECT  74.88 0 74.904 0.084 ;
    END
  END vm_rr1[93]
  PIN vm_rr1[94]
    DIRECTION INPUT ;
    USE SIGNAL ;
    PORT
      LAYER M5 ;
        RECT  75.072 0 75.096 0.084 ;
    END
  END vm_rr1[94]
  PIN vm_rr1[95]
    DIRECTION INPUT ;
    USE SIGNAL ;
    PORT
      LAYER M5 ;
        RECT  75.264 0 75.288 0.084 ;
    END
  END vm_rr1[95]
  PIN vm_rr1[96]
    DIRECTION INPUT ;
    USE SIGNAL ;
    PORT
      LAYER M5 ;
        RECT  75.456 0 75.48 0.084 ;
    END
  END vm_rr1[96]
  PIN vm_rr1[97]
    DIRECTION INPUT ;
    USE SIGNAL ;
    PORT
      LAYER M5 ;
        RECT  75.648 0 75.672 0.084 ;
    END
  END vm_rr1[97]
  PIN vm_rr1[98]
    DIRECTION INPUT ;
    USE SIGNAL ;
    PORT
      LAYER M5 ;
        RECT  75.84 0 75.864 0.084 ;
    END
  END vm_rr1[98]
  PIN vm_rr1[99]
    DIRECTION INPUT ;
    USE SIGNAL ;
    PORT
      LAYER M5 ;
        RECT  76.032 0 76.056 0.084 ;
    END
  END vm_rr1[99]
  PIN vm_rr1[9]
    DIRECTION INPUT ;
    USE SIGNAL ;
    PORT
      LAYER M5 ;
        RECT  58.992 0 59.016 0.084 ;
    END
  END vm_rr1[9]
  PIN VDD
    DIRECTION INOUT ;
    USE POWER ;
    PORT
      LAYER M5 ;
        RECT  105.192 2.151 105.312 105.849 ;
        RECT  99.792 2.151 99.912 105.849 ;
        RECT  94.392 2.151 94.512 105.849 ;
        RECT  88.992 2.151 89.112 105.849 ;
        RECT  83.592 2.151 83.712 105.849 ;
        RECT  78.192 2.151 78.312 105.849 ;
        RECT  72.792 2.151 72.912 105.849 ;
        RECT  67.392 2.151 67.512 105.849 ;
        RECT  61.992 2.151 62.112 105.849 ;
        RECT  56.592 2.151 56.712 105.849 ;
        RECT  51.192 2.151 51.312 105.849 ;
        RECT  45.792 2.151 45.912 105.849 ;
        RECT  40.392 2.151 40.512 105.849 ;
        RECT  34.992 2.151 35.112 105.849 ;
        RECT  29.592 2.151 29.712 105.849 ;
        RECT  24.192 2.151 24.312 105.849 ;
        RECT  18.792 2.151 18.912 105.849 ;
        RECT  13.392 2.151 13.512 105.849 ;
        RECT  7.992 2.151 8.112 105.849 ;
        RECT  2.592 2.151 2.712 105.849 ;
    END
  END VDD
  PIN VSS
    DIRECTION INOUT ;
    USE GROUND ;
    PORT
      LAYER M5 ;
        RECT  105 2.137 105.12 105.863 ;
        RECT  99.6 2.137 99.72 105.863 ;
        RECT  94.2 2.137 94.32 105.863 ;
        RECT  88.8 2.137 88.92 105.863 ;
        RECT  83.4 2.137 83.52 105.863 ;
        RECT  78 2.137 78.12 105.863 ;
        RECT  72.6 2.137 72.72 105.863 ;
        RECT  67.2 2.137 67.32 105.863 ;
        RECT  61.8 2.137 61.92 105.863 ;
        RECT  56.4 2.137 56.52 105.863 ;
        RECT  51 2.137 51.12 105.863 ;
        RECT  45.6 2.137 45.72 105.863 ;
        RECT  40.2 2.137 40.32 105.863 ;
        RECT  34.8 2.137 34.92 105.863 ;
        RECT  29.4 2.137 29.52 105.863 ;
        RECT  24 2.137 24.12 105.863 ;
        RECT  18.6 2.137 18.72 105.863 ;
        RECT  13.2 2.137 13.32 105.863 ;
        RECT  7.8 2.137 7.92 105.863 ;
        RECT  2.4 2.137 2.52 105.863 ;
    END
  END VSS
  OBS
    LAYER RVTN ;
     RECT  2.16 2.16 105.84 2.295 ;
     RECT  2.16 2.565 105.84 2.835 ;
     RECT  2.16 3.105 105.84 3.375 ;
     RECT  2.16 3.645 105.84 3.915 ;
     RECT  2.16 4.185 105.84 4.455 ;
     RECT  2.16 4.725 105.84 4.995 ;
     RECT  2.16 5.265 105.84 5.535 ;
     RECT  2.16 5.805 105.84 6.075 ;
     RECT  2.16 6.345 105.84 6.615 ;
     RECT  2.16 6.885 105.84 7.155 ;
     RECT  2.16 7.425 105.84 7.695 ;
     RECT  2.16 7.965 105.84 8.235 ;
     RECT  2.16 8.505 105.84 8.775 ;
     RECT  2.16 9.045 105.84 9.315 ;
     RECT  2.16 9.585 105.84 9.855 ;
     RECT  2.16 10.125 105.84 10.395 ;
     RECT  2.16 10.665 105.84 10.935 ;
     RECT  2.16 11.205 105.84 11.475 ;
     RECT  2.16 11.745 105.84 12.015 ;
     RECT  2.16 12.285 105.84 12.555 ;
     RECT  2.16 12.825 105.84 13.095 ;
     RECT  2.16 13.365 105.84 13.635 ;
     RECT  2.16 13.905 105.84 14.175 ;
     RECT  2.16 14.445 105.84 14.715 ;
     RECT  2.16 14.985 105.84 15.255 ;
     RECT  2.16 15.525 105.84 15.795 ;
     RECT  2.16 16.065 105.84 16.335 ;
     RECT  2.16 16.605 105.84 16.875 ;
     RECT  2.16 17.145 105.84 17.415 ;
     RECT  2.16 17.685 105.84 17.955 ;
     RECT  2.16 18.225 105.84 18.495 ;
     RECT  2.16 18.765 105.84 19.035 ;
     RECT  2.16 19.305 105.84 19.575 ;
     RECT  2.16 19.845 105.84 20.115 ;
     RECT  2.16 20.385 105.84 20.655 ;
     RECT  2.16 20.925 105.84 21.195 ;
     RECT  2.16 21.465 105.84 21.735 ;
     RECT  2.16 22.005 105.84 22.275 ;
     RECT  2.16 22.545 105.84 22.815 ;
     RECT  2.16 23.085 105.84 23.355 ;
     RECT  2.16 23.625 105.84 23.895 ;
     RECT  2.16 24.165 105.84 24.435 ;
     RECT  2.16 24.705 105.84 24.975 ;
     RECT  2.16 25.245 105.84 25.515 ;
     RECT  2.16 25.785 105.84 26.055 ;
     RECT  2.16 26.325 105.84 26.595 ;
     RECT  2.16 26.865 105.84 27.135 ;
     RECT  2.16 27.405 105.84 27.675 ;
     RECT  2.16 27.945 105.84 28.215 ;
     RECT  2.16 28.485 105.84 28.755 ;
     RECT  2.16 29.025 105.84 29.295 ;
     RECT  2.16 29.565 105.84 29.835 ;
     RECT  2.16 30.105 105.84 30.375 ;
     RECT  2.16 30.645 105.84 30.915 ;
     RECT  2.16 31.185 105.84 31.455 ;
     RECT  2.16 31.725 105.84 31.995 ;
     RECT  2.16 32.265 105.84 32.535 ;
     RECT  2.16 32.805 105.84 33.075 ;
     RECT  2.16 33.345 105.84 33.615 ;
     RECT  2.16 33.885 105.84 34.155 ;
     RECT  2.16 34.425 105.84 34.695 ;
     RECT  2.16 34.965 105.84 35.235 ;
     RECT  2.16 35.505 105.84 35.775 ;
     RECT  2.16 36.045 105.84 36.315 ;
     RECT  2.16 36.585 105.84 36.855 ;
     RECT  2.16 37.125 105.84 37.395 ;
     RECT  2.16 37.665 105.84 37.935 ;
     RECT  2.16 38.205 105.84 38.475 ;
     RECT  2.16 38.745 105.84 39.015 ;
     RECT  2.16 39.285 105.84 39.555 ;
     RECT  2.16 39.825 105.84 40.095 ;
     RECT  2.16 40.365 105.84 40.635 ;
     RECT  2.16 40.905 105.84 41.175 ;
     RECT  2.16 41.445 105.84 41.715 ;
     RECT  2.16 41.985 105.84 42.255 ;
     RECT  2.16 42.525 105.84 42.795 ;
     RECT  2.16 43.065 105.84 43.335 ;
     RECT  2.16 43.605 105.84 43.875 ;
     RECT  2.16 44.145 105.84 44.415 ;
     RECT  2.16 44.685 105.84 44.955 ;
     RECT  2.16 45.225 105.84 45.495 ;
     RECT  2.16 45.765 105.84 46.035 ;
     RECT  2.16 46.305 105.84 46.575 ;
     RECT  2.16 46.845 105.84 47.115 ;
     RECT  2.16 47.385 105.84 47.655 ;
     RECT  2.16 47.925 105.84 48.195 ;
     RECT  2.16 48.465 105.84 48.735 ;
     RECT  2.16 49.005 105.84 49.275 ;
     RECT  2.16 49.545 105.84 49.815 ;
     RECT  2.16 50.085 105.84 50.355 ;
     RECT  2.16 50.625 105.84 50.895 ;
     RECT  2.16 51.165 105.84 51.435 ;
     RECT  2.16 51.705 105.84 51.975 ;
     RECT  2.16 52.245 105.84 52.515 ;
     RECT  2.16 52.785 105.84 53.055 ;
     RECT  2.16 53.325 105.84 53.595 ;
     RECT  2.16 53.865 105.84 54.135 ;
     RECT  2.16 54.405 105.84 54.675 ;
     RECT  2.16 54.945 105.84 55.215 ;
     RECT  2.16 55.485 105.84 55.755 ;
     RECT  2.16 56.025 105.84 56.295 ;
     RECT  2.16 56.565 105.84 56.835 ;
     RECT  2.16 57.105 105.84 57.375 ;
     RECT  2.16 57.645 105.84 57.915 ;
     RECT  2.16 58.185 105.84 58.455 ;
     RECT  2.16 58.725 105.84 58.995 ;
     RECT  2.16 59.265 105.84 59.535 ;
     RECT  2.16 59.805 105.84 60.075 ;
     RECT  2.16 60.345 105.84 60.615 ;
     RECT  2.16 60.885 105.84 61.155 ;
     RECT  2.16 61.425 105.84 61.695 ;
     RECT  2.16 61.965 105.84 62.235 ;
     RECT  2.16 62.505 105.84 62.775 ;
     RECT  2.16 63.045 105.84 63.315 ;
     RECT  2.16 63.585 105.84 63.855 ;
     RECT  2.16 64.125 105.84 64.395 ;
     RECT  2.16 64.665 105.84 64.935 ;
     RECT  2.16 65.205 105.84 65.475 ;
     RECT  2.16 65.745 105.84 66.015 ;
     RECT  2.16 66.285 105.84 66.555 ;
     RECT  2.16 66.825 105.84 67.095 ;
     RECT  2.16 67.365 105.84 67.635 ;
     RECT  2.16 67.905 105.84 68.175 ;
     RECT  2.16 68.445 105.84 68.715 ;
     RECT  2.16 68.985 105.84 69.255 ;
     RECT  2.16 69.525 105.84 69.795 ;
     RECT  2.16 70.065 105.84 70.335 ;
     RECT  2.16 70.605 105.84 70.875 ;
     RECT  2.16 71.145 105.84 71.415 ;
     RECT  2.16 71.685 105.84 71.955 ;
     RECT  2.16 72.225 105.84 72.495 ;
     RECT  2.16 72.765 105.84 73.035 ;
     RECT  2.16 73.305 105.84 73.575 ;
     RECT  2.16 73.845 105.84 74.115 ;
     RECT  2.16 74.385 105.84 74.655 ;
     RECT  2.16 74.925 105.84 75.195 ;
     RECT  2.16 75.465 105.84 75.735 ;
     RECT  2.16 76.005 105.84 76.275 ;
     RECT  2.16 76.545 105.84 76.815 ;
     RECT  2.16 77.085 105.84 77.355 ;
     RECT  2.16 77.625 105.84 77.895 ;
     RECT  2.16 78.165 105.84 78.435 ;
     RECT  2.16 78.705 105.84 78.975 ;
     RECT  2.16 79.245 105.84 79.515 ;
     RECT  2.16 79.785 105.84 80.055 ;
     RECT  2.16 80.325 105.84 80.595 ;
     RECT  2.16 80.865 105.84 81.135 ;
     RECT  2.16 81.405 105.84 81.675 ;
     RECT  2.16 81.945 105.84 82.215 ;
     RECT  2.16 82.485 105.84 82.755 ;
     RECT  2.16 83.025 105.84 83.295 ;
     RECT  2.16 83.565 105.84 83.835 ;
     RECT  2.16 84.105 105.84 84.375 ;
     RECT  2.16 84.645 105.84 84.915 ;
     RECT  2.16 85.185 105.84 85.455 ;
     RECT  2.16 85.725 105.84 85.995 ;
     RECT  2.16 86.265 105.84 86.535 ;
     RECT  2.16 86.805 105.84 87.075 ;
     RECT  2.16 87.345 105.84 87.615 ;
     RECT  2.16 87.885 105.84 88.155 ;
     RECT  2.16 88.425 105.84 88.695 ;
     RECT  2.16 88.965 105.84 89.235 ;
     RECT  2.16 89.505 105.84 89.775 ;
     RECT  2.16 90.045 105.84 90.315 ;
     RECT  2.16 90.585 105.84 90.855 ;
     RECT  2.16 91.125 105.84 91.395 ;
     RECT  2.16 91.665 105.84 91.935 ;
     RECT  2.16 92.205 105.84 92.475 ;
     RECT  2.16 92.745 105.84 93.015 ;
     RECT  2.16 93.285 105.84 93.555 ;
     RECT  2.16 93.825 105.84 94.095 ;
     RECT  2.16 94.365 105.84 94.635 ;
     RECT  2.16 94.905 105.84 95.175 ;
     RECT  2.16 95.445 105.84 95.715 ;
     RECT  2.16 95.985 105.84 96.255 ;
     RECT  2.16 96.525 105.84 96.795 ;
     RECT  2.16 97.065 105.84 97.335 ;
     RECT  2.16 97.605 105.84 97.875 ;
     RECT  2.16 98.145 105.84 98.415 ;
     RECT  2.16 98.685 105.84 98.955 ;
     RECT  2.16 99.225 105.84 99.495 ;
     RECT  2.16 99.765 105.84 100.035 ;
     RECT  2.16 100.305 105.84 100.575 ;
     RECT  2.16 100.845 105.84 101.115 ;
     RECT  2.16 101.385 105.84 101.655 ;
     RECT  2.16 101.925 105.84 102.195 ;
     RECT  2.16 102.465 105.84 102.735 ;
     RECT  2.16 103.005 105.84 103.275 ;
     RECT  2.16 103.545 105.84 103.815 ;
     RECT  2.16 104.085 105.84 104.355 ;
     RECT  2.16 104.625 105.84 104.895 ;
     RECT  2.16 105.165 105.84 105.435 ;
     RECT  2.16 105.705 105.84 105.84 ;
    LAYER RVTP ;
     RECT  2.16 2.295 105.84 2.565 ;
     RECT  2.16 2.835 105.84 3.105 ;
     RECT  2.16 3.375 105.84 3.645 ;
     RECT  2.16 3.915 105.84 4.185 ;
     RECT  2.16 4.455 105.84 4.725 ;
     RECT  2.16 4.995 105.84 5.265 ;
     RECT  2.16 5.535 105.84 5.805 ;
     RECT  2.16 6.075 105.84 6.345 ;
     RECT  2.16 6.615 105.84 6.885 ;
     RECT  2.16 7.155 105.84 7.425 ;
     RECT  2.16 7.695 105.84 7.965 ;
     RECT  2.16 8.235 105.84 8.505 ;
     RECT  2.16 8.775 105.84 9.045 ;
     RECT  2.16 9.315 105.84 9.585 ;
     RECT  2.16 9.855 105.84 10.125 ;
     RECT  2.16 10.395 105.84 10.665 ;
     RECT  2.16 10.935 105.84 11.205 ;
     RECT  2.16 11.475 105.84 11.745 ;
     RECT  2.16 12.015 105.84 12.285 ;
     RECT  2.16 12.555 105.84 12.825 ;
     RECT  2.16 13.095 105.84 13.365 ;
     RECT  2.16 13.635 105.84 13.905 ;
     RECT  2.16 14.175 105.84 14.445 ;
     RECT  2.16 14.715 105.84 14.985 ;
     RECT  2.16 15.255 105.84 15.525 ;
     RECT  2.16 15.795 105.84 16.065 ;
     RECT  2.16 16.335 105.84 16.605 ;
     RECT  2.16 16.875 105.84 17.145 ;
     RECT  2.16 17.415 105.84 17.685 ;
     RECT  2.16 17.955 105.84 18.225 ;
     RECT  2.16 18.495 105.84 18.765 ;
     RECT  2.16 19.035 105.84 19.305 ;
     RECT  2.16 19.575 105.84 19.845 ;
     RECT  2.16 20.115 105.84 20.385 ;
     RECT  2.16 20.655 105.84 20.925 ;
     RECT  2.16 21.195 105.84 21.465 ;
     RECT  2.16 21.735 105.84 22.005 ;
     RECT  2.16 22.275 105.84 22.545 ;
     RECT  2.16 22.815 105.84 23.085 ;
     RECT  2.16 23.355 105.84 23.625 ;
     RECT  2.16 23.895 105.84 24.165 ;
     RECT  2.16 24.435 105.84 24.705 ;
     RECT  2.16 24.975 105.84 25.245 ;
     RECT  2.16 25.515 105.84 25.785 ;
     RECT  2.16 26.055 105.84 26.325 ;
     RECT  2.16 26.595 105.84 26.865 ;
     RECT  2.16 27.135 105.84 27.405 ;
     RECT  2.16 27.675 105.84 27.945 ;
     RECT  2.16 28.215 105.84 28.485 ;
     RECT  2.16 28.755 105.84 29.025 ;
     RECT  2.16 29.295 105.84 29.565 ;
     RECT  2.16 29.835 105.84 30.105 ;
     RECT  2.16 30.375 105.84 30.645 ;
     RECT  2.16 30.915 105.84 31.185 ;
     RECT  2.16 31.455 105.84 31.725 ;
     RECT  2.16 31.995 105.84 32.265 ;
     RECT  2.16 32.535 105.84 32.805 ;
     RECT  2.16 33.075 105.84 33.345 ;
     RECT  2.16 33.615 105.84 33.885 ;
     RECT  2.16 34.155 105.84 34.425 ;
     RECT  2.16 34.695 105.84 34.965 ;
     RECT  2.16 35.235 105.84 35.505 ;
     RECT  2.16 35.775 105.84 36.045 ;
     RECT  2.16 36.315 105.84 36.585 ;
     RECT  2.16 36.855 105.84 37.125 ;
     RECT  2.16 37.395 105.84 37.665 ;
     RECT  2.16 37.935 105.84 38.205 ;
     RECT  2.16 38.475 105.84 38.745 ;
     RECT  2.16 39.015 105.84 39.285 ;
     RECT  2.16 39.555 105.84 39.825 ;
     RECT  2.16 40.095 105.84 40.365 ;
     RECT  2.16 40.635 105.84 40.905 ;
     RECT  2.16 41.175 105.84 41.445 ;
     RECT  2.16 41.715 105.84 41.985 ;
     RECT  2.16 42.255 105.84 42.525 ;
     RECT  2.16 42.795 105.84 43.065 ;
     RECT  2.16 43.335 105.84 43.605 ;
     RECT  2.16 43.875 105.84 44.145 ;
     RECT  2.16 44.415 105.84 44.685 ;
     RECT  2.16 44.955 105.84 45.225 ;
     RECT  2.16 45.495 105.84 45.765 ;
     RECT  2.16 46.035 105.84 46.305 ;
     RECT  2.16 46.575 105.84 46.845 ;
     RECT  2.16 47.115 105.84 47.385 ;
     RECT  2.16 47.655 105.84 47.925 ;
     RECT  2.16 48.195 105.84 48.465 ;
     RECT  2.16 48.735 105.84 49.005 ;
     RECT  2.16 49.275 105.84 49.545 ;
     RECT  2.16 49.815 105.84 50.085 ;
     RECT  2.16 50.355 105.84 50.625 ;
     RECT  2.16 50.895 105.84 51.165 ;
     RECT  2.16 51.435 105.84 51.705 ;
     RECT  2.16 51.975 105.84 52.245 ;
     RECT  2.16 52.515 105.84 52.785 ;
     RECT  2.16 53.055 105.84 53.325 ;
     RECT  2.16 53.595 105.84 53.865 ;
     RECT  2.16 54.135 105.84 54.405 ;
     RECT  2.16 54.675 105.84 54.945 ;
     RECT  2.16 55.215 105.84 55.485 ;
     RECT  2.16 55.755 105.84 56.025 ;
     RECT  2.16 56.295 105.84 56.565 ;
     RECT  2.16 56.835 105.84 57.105 ;
     RECT  2.16 57.375 105.84 57.645 ;
     RECT  2.16 57.915 105.84 58.185 ;
     RECT  2.16 58.455 105.84 58.725 ;
     RECT  2.16 58.995 105.84 59.265 ;
     RECT  2.16 59.535 105.84 59.805 ;
     RECT  2.16 60.075 105.84 60.345 ;
     RECT  2.16 60.615 105.84 60.885 ;
     RECT  2.16 61.155 105.84 61.425 ;
     RECT  2.16 61.695 105.84 61.965 ;
     RECT  2.16 62.235 105.84 62.505 ;
     RECT  2.16 62.775 105.84 63.045 ;
     RECT  2.16 63.315 105.84 63.585 ;
     RECT  2.16 63.855 105.84 64.125 ;
     RECT  2.16 64.395 105.84 64.665 ;
     RECT  2.16 64.935 105.84 65.205 ;
     RECT  2.16 65.475 105.84 65.745 ;
     RECT  2.16 66.015 105.84 66.285 ;
     RECT  2.16 66.555 105.84 66.825 ;
     RECT  2.16 67.095 105.84 67.365 ;
     RECT  2.16 67.635 105.84 67.905 ;
     RECT  2.16 68.175 105.84 68.445 ;
     RECT  2.16 68.715 105.84 68.985 ;
     RECT  2.16 69.255 105.84 69.525 ;
     RECT  2.16 69.795 105.84 70.065 ;
     RECT  2.16 70.335 105.84 70.605 ;
     RECT  2.16 70.875 105.84 71.145 ;
     RECT  2.16 71.415 105.84 71.685 ;
     RECT  2.16 71.955 105.84 72.225 ;
     RECT  2.16 72.495 105.84 72.765 ;
     RECT  2.16 73.035 105.84 73.305 ;
     RECT  2.16 73.575 105.84 73.845 ;
     RECT  2.16 74.115 105.84 74.385 ;
     RECT  2.16 74.655 105.84 74.925 ;
     RECT  2.16 75.195 105.84 75.465 ;
     RECT  2.16 75.735 105.84 76.005 ;
     RECT  2.16 76.275 105.84 76.545 ;
     RECT  2.16 76.815 105.84 77.085 ;
     RECT  2.16 77.355 105.84 77.625 ;
     RECT  2.16 77.895 105.84 78.165 ;
     RECT  2.16 78.435 105.84 78.705 ;
     RECT  2.16 78.975 105.84 79.245 ;
     RECT  2.16 79.515 105.84 79.785 ;
     RECT  2.16 80.055 105.84 80.325 ;
     RECT  2.16 80.595 105.84 80.865 ;
     RECT  2.16 81.135 105.84 81.405 ;
     RECT  2.16 81.675 105.84 81.945 ;
     RECT  2.16 82.215 105.84 82.485 ;
     RECT  2.16 82.755 105.84 83.025 ;
     RECT  2.16 83.295 105.84 83.565 ;
     RECT  2.16 83.835 105.84 84.105 ;
     RECT  2.16 84.375 105.84 84.645 ;
     RECT  2.16 84.915 105.84 85.185 ;
     RECT  2.16 85.455 105.84 85.725 ;
     RECT  2.16 85.995 105.84 86.265 ;
     RECT  2.16 86.535 105.84 86.805 ;
     RECT  2.16 87.075 105.84 87.345 ;
     RECT  2.16 87.615 105.84 87.885 ;
     RECT  2.16 88.155 105.84 88.425 ;
     RECT  2.16 88.695 105.84 88.965 ;
     RECT  2.16 89.235 105.84 89.505 ;
     RECT  2.16 89.775 105.84 90.045 ;
     RECT  2.16 90.315 105.84 90.585 ;
     RECT  2.16 90.855 105.84 91.125 ;
     RECT  2.16 91.395 105.84 91.665 ;
     RECT  2.16 91.935 105.84 92.205 ;
     RECT  2.16 92.475 105.84 92.745 ;
     RECT  2.16 93.015 105.84 93.285 ;
     RECT  2.16 93.555 105.84 93.825 ;
     RECT  2.16 94.095 105.84 94.365 ;
     RECT  2.16 94.635 105.84 94.905 ;
     RECT  2.16 95.175 105.84 95.445 ;
     RECT  2.16 95.715 105.84 95.985 ;
     RECT  2.16 96.255 105.84 96.525 ;
     RECT  2.16 96.795 105.84 97.065 ;
     RECT  2.16 97.335 105.84 97.605 ;
     RECT  2.16 97.875 105.84 98.145 ;
     RECT  2.16 98.415 105.84 98.685 ;
     RECT  2.16 98.955 105.84 99.225 ;
     RECT  2.16 99.495 105.84 99.765 ;
     RECT  2.16 100.035 105.84 100.305 ;
     RECT  2.16 100.575 105.84 100.845 ;
     RECT  2.16 101.115 105.84 101.385 ;
     RECT  2.16 101.655 105.84 101.925 ;
     RECT  2.16 102.195 105.84 102.465 ;
     RECT  2.16 102.735 105.84 103.005 ;
     RECT  2.16 103.275 105.84 103.545 ;
     RECT  2.16 103.815 105.84 104.085 ;
     RECT  2.16 104.355 105.84 104.625 ;
     RECT  2.16 104.895 105.84 105.165 ;
     RECT  2.16 105.435 105.84 105.705 ;
    LAYER M1 ;
     RECT  2.16 2.151 105.84 105.849 ;
    LAYER M2 ;
     RECT  0.103 3.69 0.139 3.708 ;
     RECT  0.139 5.076 0.175 5.094 ;
     RECT  0.103 51.606 0.203 51.624 ;
     RECT  0.175 5.076 0.275 5.526 ;
     RECT  0.103 26.766 0.535 26.784 ;
     RECT  0.103 32.706 0.535 32.724 ;
     RECT  0.103 37.836 0.535 37.854 ;
     RECT  0.103 72.306 0.535 72.954 ;
     RECT  0.499 73.854 0.535 73.872 ;
     RECT  0.103 78.606 0.535 78.624 ;
     RECT  0.139 2.466 2.16 3.708 ;
     RECT  0.275 5.076 2.16 5.094 ;
     RECT  0.103 22.176 2.16 22.194 ;
     RECT  0.535 26.136 2.16 26.784 ;
     RECT  0.535 31.896 2.16 32.832 ;
     RECT  0.535 36.936 2.16 37.854 ;
     RECT  0.103 52.416 2.16 52.434 ;
     RECT  0.535 59.814 2.16 59.832 ;
     RECT  0.535 63.126 2.16 63.144 ;
     RECT  0.535 64.368 2.16 64.386 ;
     RECT  0.535 67.716 2.16 68.904 ;
     RECT  0.535 71.766 2.16 74.412 ;
     RECT  0.535 75.204 2.16 75.222 ;
     RECT  0.535 77.976 2.16 78.624 ;
     RECT  0.535 79.686 2.16 79.704 ;
     RECT  0.535 80.676 2.16 80.694 ;
     RECT  0.535 82.836 2.16 82.854 ;
     RECT  0.103 89.946 2.16 89.964 ;
     RECT  0.535 91.17 2.16 91.188 ;
     RECT  0.535 94.986 2.16 95.004 ;
     RECT  0.103 96.156 2.16 96.174 ;
     RECT  0.535 99.036 2.16 99.054 ;
     RECT  2.16 2.151 4.279 105.849 ;
     RECT  4.279 2.151 4.999 105.894 ;
     RECT  4.999 2.151 6.863 106.002 ;
     RECT  6.863 2.151 28.247 105.894 ;
     RECT  28.247 2.151 50.719 105.849 ;
     RECT  50.719 2.106 51.079 105.849 ;
     RECT  51.079 2.07 51.683 105.849 ;
     RECT  51.683 2.106 51.755 105.849 ;
     RECT  51.755 2.151 52.951 105.849 ;
     RECT  52.951 2.106 53.411 105.849 ;
     RECT  53.411 2.151 54.175 105.849 ;
     RECT  54.175 2.106 55.219 105.849 ;
     RECT  55.219 2.034 55.787 105.849 ;
     RECT  55.939 1.152 56.039 1.17 ;
     RECT  55.787 2.106 56.551 105.849 ;
     RECT  56.551 2.07 56.831 105.849 ;
     RECT  56.767 1.152 56.903 1.17 ;
     RECT  56.831 2.106 57.227 105.849 ;
     RECT  57.227 2.151 105.84 105.849 ;
     RECT  105.84 8.442 105.971 105.804 ;
     RECT  105.84 5.04 106.007 6.714 ;
     RECT  105.971 8.442 106.007 105.426 ;
     RECT  106.007 8.442 106.043 81.324 ;
     RECT  106.043 13.572 106.079 81.324 ;
     RECT  106.007 82.386 106.547 105.426 ;
     RECT  106.043 8.442 106.583 12.744 ;
     RECT  106.079 13.572 106.583 52.74 ;
     RECT  106.079 53.568 106.583 81.324 ;
     RECT  106.547 82.386 106.583 105.354 ;
     RECT  106.007 5.076 106.619 6.714 ;
     RECT  106.583 8.442 106.619 8.46 ;
     RECT  106.583 9.252 106.619 11.664 ;
     RECT  106.583 13.572 106.619 15.444 ;
     RECT  106.583 18.396 106.619 19.26 ;
     RECT  106.583 20.016 106.619 32.292 ;
     RECT  106.583 33.246 106.619 33.606 ;
     RECT  106.583 34.938 106.619 34.956 ;
     RECT  106.583 35.712 106.619 36.234 ;
     RECT  106.583 37.602 106.619 41.4 ;
     RECT  106.583 42.696 106.619 43.794 ;
     RECT  106.583 44.586 106.619 46.494 ;
     RECT  106.583 47.556 106.619 51.354 ;
     RECT  106.583 52.722 106.619 52.74 ;
     RECT  106.583 53.568 106.619 60.174 ;
     RECT  106.583 60.966 106.619 65.664 ;
     RECT  106.583 66.564 106.619 71.064 ;
     RECT  106.583 71.856 106.619 78.66 ;
     RECT  106.583 79.686 106.619 81.324 ;
     RECT  106.583 83.646 106.619 84.564 ;
     RECT  106.583 88.902 106.619 91.08 ;
     RECT  106.583 93.726 106.619 95.634 ;
     RECT  106.583 96.426 106.619 99.45 ;
     RECT  106.583 100.206 106.619 101.034 ;
     RECT  106.583 101.97 106.619 105.354 ;
     RECT  105.84 3.42 107.123 3.438 ;
     RECT  106.583 85.356 107.123 87.804 ;
     RECT  106.619 101.97 107.123 102.564 ;
     RECT  105.84 2.376 107.159 2.394 ;
     RECT  106.619 5.076 107.159 5.094 ;
     RECT  106.619 9.396 107.159 10.962 ;
     RECT  106.583 12.456 107.159 12.744 ;
     RECT  106.619 13.806 107.159 15.444 ;
     RECT  106.583 16.236 107.159 16.524 ;
     RECT  106.583 17.316 107.159 17.604 ;
     RECT  106.619 18.576 107.159 18.954 ;
     RECT  106.619 20.286 107.159 22.5 ;
     RECT  106.619 24.246 107.159 24.624 ;
     RECT  106.619 25.416 107.159 28.674 ;
     RECT  106.619 29.466 107.159 30.564 ;
     RECT  106.619 33.246 107.159 33.534 ;
     RECT  106.619 36.216 107.159 36.234 ;
     RECT  106.619 39.636 107.159 41.4 ;
     RECT  106.619 43.236 107.159 43.794 ;
     RECT  106.619 44.586 107.159 44.604 ;
     RECT  106.619 47.556 107.159 48.924 ;
     RECT  106.619 50.526 107.159 50.814 ;
     RECT  106.619 54.846 107.159 55.404 ;
     RECT  106.619 56.196 107.159 56.214 ;
     RECT  106.619 57.276 107.159 59.832 ;
     RECT  106.619 61.776 107.159 65.664 ;
     RECT  106.619 67.806 107.159 68.364 ;
     RECT  106.619 69.426 107.159 69.714 ;
     RECT  106.619 71.046 107.159 71.064 ;
     RECT  106.619 72.306 107.159 72.954 ;
     RECT  106.619 73.746 107.159 76.464 ;
     RECT  106.619 77.292 107.159 77.814 ;
     RECT  106.583 82.386 107.159 82.404 ;
     RECT  106.619 84.006 107.159 84.564 ;
     RECT  107.123 85.356 107.159 85.914 ;
     RECT  107.123 86.706 107.159 87.804 ;
     RECT  106.619 88.902 107.159 90.612 ;
     RECT  106.583 91.836 107.159 92.934 ;
     RECT  106.619 93.726 107.159 94.284 ;
     RECT  106.619 95.148 107.159 95.544 ;
     RECT  106.619 96.876 107.159 97.254 ;
     RECT  106.619 98.316 107.159 98.604 ;
     RECT  106.619 100.476 107.159 101.034 ;
     RECT  107.123 102.096 107.159 102.564 ;
     RECT  106.619 103.356 107.159 105.354 ;
     RECT  106.619 6.552 107.195 6.714 ;
     RECT  105.84 7.632 107.195 7.65 ;
     RECT  107.159 10.944 107.195 10.962 ;
     RECT  107.159 22.176 107.195 22.194 ;
     RECT  107.159 28.458 107.195 28.476 ;
     RECT  106.619 31.806 107.195 32.292 ;
     RECT  106.619 37.602 107.195 37.62 ;
     RECT  107.159 39.636 107.195 40.284 ;
     RECT  107.159 43.236 107.195 43.254 ;
     RECT  107.159 48.906 107.195 48.924 ;
     RECT  106.619 53.568 107.195 53.586 ;
     RECT  107.159 55.386 107.195 55.404 ;
     RECT  107.159 57.924 107.195 57.942 ;
     RECT  107.159 59.238 107.195 59.832 ;
     RECT  106.619 60.966 107.195 60.984 ;
     RECT  107.159 67.806 107.195 67.824 ;
     RECT  107.159 69.696 107.195 69.714 ;
     RECT  107.159 72.846 107.195 72.954 ;
     RECT  107.159 77.292 107.195 77.31 ;
     RECT  106.619 79.686 107.195 79.704 ;
     RECT  107.159 89.946 107.195 89.964 ;
     RECT  107.159 104.292 107.195 104.31 ;
     RECT  107.159 105.336 107.195 105.354 ;
     RECT  107.195 6.696 107.915 6.714 ;
     RECT  107.159 9.396 107.915 9.882 ;
     RECT  107.159 13.806 107.915 13.824 ;
     RECT  107.159 16.506 107.915 16.524 ;
     RECT  107.159 17.586 107.915 17.604 ;
     RECT  107.159 18.576 107.915 18.594 ;
     RECT  107.159 20.664 107.915 20.682 ;
     RECT  107.159 25.956 107.915 25.974 ;
     RECT  106.619 38.556 107.915 38.574 ;
     RECT  107.195 39.636 107.915 39.654 ;
     RECT  106.619 45.846 107.915 45.864 ;
     RECT  107.159 50.796 107.915 50.814 ;
     RECT  107.195 72.846 107.915 72.864 ;
     RECT  107.159 75.168 107.915 75.186 ;
     RECT  107.159 76.086 107.915 76.104 ;
     RECT  106.619 78.642 107.915 78.66 ;
     RECT  107.159 87.786 107.915 87.804 ;
     RECT  107.159 92.376 107.915 92.394 ;
     RECT  107.159 93.906 107.915 93.924 ;
     RECT  107.159 95.526 107.915 95.544 ;
     RECT  107.159 97.11 107.915 97.128 ;
    LAYER M3 ;
     RECT  35.172 0.091 35.19 0.187 ;
     RECT  56.376 0.091 56.394 0.523 ;
     RECT  105.336 0.091 105.354 0.523 ;
     RECT  56.016 0.523 56.394 0.571 ;
     RECT  86.076 0.091 86.094 0.571 ;
     RECT  40.068 0.427 40.086 0.605 ;
     RECT  72.432 0.427 72.45 0.605 ;
     RECT  99.504 0.427 99.522 0.605 ;
     RECT  38.232 0.571 38.25 1.099 ;
     RECT  44.46 0.091 44.478 1.099 ;
     RECT  45.756 0.091 45.99 1.099 ;
     RECT  55.08 0.091 55.098 1.099 ;
     RECT  105.156 0.523 105.354 1.099 ;
     RECT  56.016 0.571 56.898 1.147 ;
     RECT  42.696 1.099 42.714 1.675 ;
     RECT  103.896 1.147 103.914 1.675 ;
     RECT  104.904 1.099 105.354 1.675 ;
     RECT  52.668 0.091 52.686 1.723 ;
     RECT  54.936 1.099 55.098 1.723 ;
     RECT  55.944 1.147 56.898 1.723 ;
     RECT  103.176 1.675 105.354 1.723 ;
     RECT  35.172 0.187 35.226 2.011 ;
     RECT  83.268 0.091 83.286 2.011 ;
     RECT  94.644 0.139 94.662 2.011 ;
     RECT  50.904 1.723 57.366 2.101 ;
     RECT  29.772 2.011 29.79 2.143 ;
     RECT  39.888 1.675 39.906 2.143 ;
     RECT  67.356 1.723 67.374 2.143 ;
     RECT  94.572 2.011 94.662 2.143 ;
     RECT  50.724 2.101 57.366 2.191 ;
     RECT  58.5 1.723 58.518 2.191 ;
     RECT  50.724 2.191 58.518 2.263 ;
     RECT  47.304 2.251 47.322 2.291 ;
     RECT  2.415 2.143 2.505 2.413 ;
     RECT  7.815 2.143 7.905 2.413 ;
     RECT  13.215 2.143 13.305 2.413 ;
     RECT  18.615 2.143 18.705 2.413 ;
     RECT  24.015 2.143 24.105 2.413 ;
     RECT  39.888 2.143 40.305 2.413 ;
     RECT  41.04 1.675 41.058 2.413 ;
     RECT  61.815 2.143 61.905 2.413 ;
     RECT  67.215 2.143 67.374 2.413 ;
     RECT  72.615 2.143 72.705 2.413 ;
     RECT  78.015 2.143 78.105 2.413 ;
     RECT  88.815 2.143 88.905 2.413 ;
     RECT  99.615 2.143 99.705 2.413 ;
     RECT  50.616 2.263 58.518 2.497 ;
     RECT  2.415 2.413 2.697 2.632 ;
     RECT  13.215 2.413 13.497 2.632 ;
     RECT  24.015 2.413 24.297 2.632 ;
     RECT  34.776 2.011 35.226 2.632 ;
     RECT  49.032 0.091 49.05 2.635 ;
     RECT  107.136 2.251 107.154 2.635 ;
     RECT  49.032 2.635 49.194 2.767 ;
     RECT  50.184 2.497 58.518 2.803 ;
     RECT  72.615 2.413 72.897 2.827 ;
     RECT  79.848 0.091 79.866 2.827 ;
     RECT  103.104 1.723 105.354 2.827 ;
     RECT  107.136 2.635 107.838 2.971 ;
     RECT  50.184 2.803 59.166 3.029 ;
     RECT  0.144 2.443 0.162 3.065 ;
     RECT  48.42 2.767 49.194 3.181 ;
     RECT  2.304 2.632 2.697 3.209 ;
     RECT  13.104 2.632 13.497 3.209 ;
     RECT  23.904 2.632 24.297 3.209 ;
     RECT  34.704 2.632 35.226 3.209 ;
     RECT  48.384 3.181 49.194 3.271 ;
     RECT  50.184 3.029 58.662 3.271 ;
     RECT  107.1 2.971 107.838 3.341 ;
     RECT  101.556 2.827 101.754 3.355 ;
     RECT  48.384 3.271 58.662 3.389 ;
     RECT  36.432 1.099 36.45 3.403 ;
     RECT  76.932 0.523 76.95 3.403 ;
     RECT  48.42 3.389 58.662 3.407 ;
     RECT  107.1 3.341 107.154 3.443 ;
     RECT  60.948 3.451 60.966 3.641 ;
     RECT  103.104 2.827 105.426 3.721 ;
     RECT  49.104 3.407 58.662 3.749 ;
     RECT  0.108 3.685 0.126 3.773 ;
     RECT  107.892 3.547 107.91 3.869 ;
     RECT  76.32 3.403 76.95 3.931 ;
     RECT  78.015 2.413 78.297 3.931 ;
     RECT  44.46 1.099 45.99 3.991 ;
     RECT  49.104 3.749 58.59 4.145 ;
     RECT  43.848 3.991 45.99 4.157 ;
     RECT  101.556 3.355 102.006 4.181 ;
     RECT  2.415 3.209 2.697 4.315 ;
     RECT  103.104 3.721 105.462 4.315 ;
     RECT  13.215 3.209 13.497 4.351 ;
     RECT  24.015 3.209 24.297 4.351 ;
     RECT  34.776 3.209 35.226 4.351 ;
     RECT  50.4 4.145 58.59 4.379 ;
     RECT  50.4 4.379 58.518 4.451 ;
     RECT  50.724 4.451 58.518 4.493 ;
     RECT  2.304 4.315 2.697 4.555 ;
     RECT  42.156 1.675 42.714 4.747 ;
     RECT  47.268 4.657 47.286 4.781 ;
     RECT  34.704 4.351 35.226 4.925 ;
     RECT  42.156 4.747 42.786 4.925 ;
     RECT  2.304 4.555 2.862 4.928 ;
     RECT  13.104 4.351 13.497 4.928 ;
     RECT  23.904 4.351 24.297 4.928 ;
     RECT  49.104 4.145 49.122 5.071 ;
     RECT  107.136 3.443 107.154 5.099 ;
     RECT  0.144 5.071 0.162 5.117 ;
     RECT  67.215 2.413 67.497 5.161 ;
     RECT  103.104 4.315 106.002 5.161 ;
     RECT  66.672 5.161 67.497 5.261 ;
     RECT  34.776 4.925 35.226 5.275 ;
     RECT  49.032 5.071 49.122 5.297 ;
     RECT  34.776 5.275 35.37 5.333 ;
     RECT  36.432 3.403 37.026 5.341 ;
     RECT  50.76 4.493 58.518 5.341 ;
     RECT  50.616 5.341 58.518 5.495 ;
     RECT  0.18 5.467 0.198 5.503 ;
     RECT  36.396 5.341 37.026 5.531 ;
     RECT  0.18 5.503 0.27 5.549 ;
     RECT  103.104 5.161 106.038 5.575 ;
     RECT  0.18 5.549 0.198 5.693 ;
     RECT  2.415 4.928 2.862 6.079 ;
     RECT  2.415 6.079 2.898 6.125 ;
     RECT  60.948 6.007 60.966 6.143 ;
     RECT  76.32 3.931 78.297 6.235 ;
     RECT  103.104 5.575 106.614 6.235 ;
     RECT  50.724 5.495 58.518 6.511 ;
     RECT  5.796 5.131 5.814 6.523 ;
     RECT  102.96 6.235 106.614 6.547 ;
     RECT  107.892 5.083 107.91 6.547 ;
     RECT  102.96 6.547 107.91 6.619 ;
     RECT  2.415 6.125 2.862 6.667 ;
     RECT  60.912 6.547 60.93 6.683 ;
     RECT  102.672 6.619 107.91 6.781 ;
     RECT  2.232 6.667 2.862 6.845 ;
     RECT  83.268 2.011 83.754 6.845 ;
     RECT  36.432 5.531 37.026 6.881 ;
     RECT  13.215 4.928 13.497 6.952 ;
     RECT  24.015 4.928 24.297 6.952 ;
     RECT  34.776 5.333 35.226 6.952 ;
     RECT  102.6 6.781 107.91 7.181 ;
     RECT  50.724 6.511 59.13 7.223 ;
     RECT  101.556 4.181 101.754 7.357 ;
     RECT  52.452 7.223 59.13 7.385 ;
     RECT  102.6 7.181 106.074 7.469 ;
     RECT  13.104 6.952 13.497 7.529 ;
     RECT  23.904 6.952 24.297 7.529 ;
     RECT  34.704 6.952 35.226 7.529 ;
     RECT  2.304 6.845 2.862 7.565 ;
     RECT  60.948 7.627 60.966 7.727 ;
     RECT  102.96 7.469 106.074 7.757 ;
     RECT  52.92 7.385 59.13 7.799 ;
     RECT  52.92 7.799 58.518 7.949 ;
     RECT  3.6 6.859 4.122 7.963 ;
     RECT  5.292 6.523 5.814 7.963 ;
     RECT  6.732 7.435 6.75 7.963 ;
     RECT  3.6 7.963 4.518 8.011 ;
     RECT  5.292 7.963 6.75 8.011 ;
     RECT  94.215 2.143 94.662 8.011 ;
     RECT  56.268 7.949 58.518 8.033 ;
     RECT  101.484 7.357 101.754 8.045 ;
     RECT  107.172 7.181 107.91 8.141 ;
     RECT  52.92 7.949 55.35 8.267 ;
     RECT  53.172 8.267 55.35 8.303 ;
     RECT  2.415 7.565 2.862 8.311 ;
     RECT  3.6 8.011 6.75 8.311 ;
     RECT  50.724 7.223 51.714 8.333 ;
     RECT  107.172 8.141 107.19 8.333 ;
     RECT  56.415 8.033 58.518 8.339 ;
     RECT  65.808 8.311 65.826 8.429 ;
     RECT  36.432 6.881 36.954 8.437 ;
     RECT  106.596 8.437 106.614 8.525 ;
     RECT  2.415 8.311 6.75 8.671 ;
     RECT  7.815 2.413 8.097 8.671 ;
     RECT  57.528 8.339 58.518 8.671 ;
     RECT  2.415 8.671 8.097 8.683 ;
     RECT  2.304 8.683 8.097 8.807 ;
     RECT  57.528 8.671 58.698 8.843 ;
     RECT  102.96 7.757 105.426 8.851 ;
     RECT  57.816 8.843 58.698 9.115 ;
     RECT  9.108 8.941 9.126 9.121 ;
     RECT  99.615 2.413 99.897 9.121 ;
     RECT  10.728 9.121 10.746 9.211 ;
     RECT  2.415 8.807 8.097 9.239 ;
     RECT  5.616 9.239 8.097 9.247 ;
     RECT  53.172 8.303 54.162 9.247 ;
     RECT  106.56 8.671 106.578 9.247 ;
     RECT  9.036 9.121 9.126 9.275 ;
     RECT  98.604 8.671 98.622 9.275 ;
     RECT  5.616 9.247 8.19 9.293 ;
     RECT  10.728 9.211 10.89 9.311 ;
     RECT  53.172 9.247 54.81 9.347 ;
     RECT  101.556 8.045 101.754 9.355 ;
     RECT  102.6 8.851 105.426 9.355 ;
     RECT  9.072 9.275 9.126 9.391 ;
     RECT  9.072 9.391 9.234 9.419 ;
     RECT  101.556 9.355 105.426 9.451 ;
     RECT  106.56 9.247 106.614 9.451 ;
     RECT  0.144 9.451 0.162 9.581 ;
     RECT  9.144 9.419 9.234 9.581 ;
     RECT  57.816 9.115 59.778 9.589 ;
     RECT  9.144 9.581 9.162 9.617 ;
     RECT  53.172 9.347 54.738 9.617 ;
     RECT  99.615 9.121 100.062 9.689 ;
     RECT  57.816 9.589 59.886 9.691 ;
     RECT  101.556 9.451 106.614 9.751 ;
     RECT  101.448 9.751 106.614 9.781 ;
     RECT  101.268 9.781 106.614 9.821 ;
     RECT  10.728 9.311 10.818 9.851 ;
     RECT  107.892 9.067 107.91 9.887 ;
     RECT  10.764 9.851 10.818 9.923 ;
     RECT  2.415 9.239 4.878 10.021 ;
     RECT  5.616 9.293 8.097 10.021 ;
     RECT  10.8 9.923 10.818 10.049 ;
     RECT  98.676 9.391 98.73 10.057 ;
     RECT  2.415 10.021 8.097 10.171 ;
     RECT  57.816 9.691 60.642 10.201 ;
     RECT  98.676 10.057 98.766 10.253 ;
     RECT  98.676 10.253 98.694 10.363 ;
     RECT  99.615 9.689 100.026 10.435 ;
     RECT  101.448 9.821 106.614 10.552 ;
     RECT  99.615 10.435 100.062 10.705 ;
     RECT  98.604 10.363 98.694 10.733 ;
     RECT  101.448 10.552 107.154 10.747 ;
     RECT  0.108 10.651 0.126 10.781 ;
     RECT  94.215 8.011 94.698 10.829 ;
     RECT  2.376 10.171 8.097 10.831 ;
     RECT  57.816 10.201 60.93 10.831 ;
     RECT  61.815 2.413 62.097 10.831 ;
     RECT  99.615 10.705 100.314 10.831 ;
     RECT  101.448 10.747 107.19 10.831 ;
     RECT  99.615 10.831 107.19 10.859 ;
     RECT  2.376 10.831 8.442 10.939 ;
     RECT  100.908 10.859 107.19 10.967 ;
     RECT  2.304 10.939 8.442 11.011 ;
     RECT  9.216 10.867 9.306 11.011 ;
     RECT  2.304 11.011 9.306 11.281 ;
     RECT  2.304 11.281 9.378 11.308 ;
     RECT  2.268 11.308 9.378 11.399 ;
     RECT  100.908 10.967 106.614 11.399 ;
     RECT  2.304 11.399 9.378 11.419 ;
     RECT  57.816 10.831 62.097 11.419 ;
     RECT  98.604 10.733 98.622 11.551 ;
     RECT  99.615 10.859 99.897 11.551 ;
     RECT  98.604 11.551 99.897 11.669 ;
     RECT  98.604 11.669 98.766 11.705 ;
     RECT  98.604 11.705 98.622 11.849 ;
     RECT  72.615 2.827 73.53 11.947 ;
     RECT  99.615 11.669 99.897 12.055 ;
     RECT  99.615 12.055 99.99 12.091 ;
     RECT  99.615 12.091 100.062 12.209 ;
     RECT  101.556 11.399 106.614 12.209 ;
     RECT  99.615 12.209 99.99 12.479 ;
     RECT  101.556 12.209 106.038 12.631 ;
     RECT  100.836 12.631 106.038 12.749 ;
     RECT  107.136 12.283 107.154 12.749 ;
     RECT  94.215 10.829 94.662 12.901 ;
     RECT  98.604 12.595 98.622 13.003 ;
     RECT  80.964 3.403 80.982 13.051 ;
     RECT  82.08 2.251 82.098 13.051 ;
     RECT  94.215 12.901 94.698 13.055 ;
     RECT  98.604 13.003 98.766 13.055 ;
     RECT  98.604 13.055 98.622 13.397 ;
     RECT  101.232 12.749 106.038 13.567 ;
     RECT  10.8 12.289 10.818 13.631 ;
     RECT  100.908 13.567 106.614 13.667 ;
     RECT  99.615 12.479 99.897 13.801 ;
     RECT  107.892 13.771 107.91 13.829 ;
     RECT  2.304 11.419 9.666 13.963 ;
     RECT  106.56 13.667 106.614 13.963 ;
     RECT  2.268 13.963 9.666 14.009 ;
     RECT  98.748 13.801 99.897 14.059 ;
     RECT  100.908 13.667 105.426 14.059 ;
     RECT  98.748 14.059 105.426 14.171 ;
     RECT  106.56 13.963 107.154 14.381 ;
     RECT  57.816 11.419 64.854 14.485 ;
     RECT  99.615 14.171 105.426 14.549 ;
     RECT  100.764 14.549 105.426 14.639 ;
     RECT  100.908 14.639 105.426 14.675 ;
     RECT  2.304 14.009 9.666 14.791 ;
     RECT  83.268 6.845 83.697 14.791 ;
     RECT  2.304 14.791 9.81 14.827 ;
     RECT  10.8 14.647 10.818 14.827 ;
     RECT  57.816 14.485 64.926 14.827 ;
     RECT  83.232 14.791 83.697 14.909 ;
     RECT  106.596 14.381 107.154 14.957 ;
     RECT  98.604 14.251 98.622 14.989 ;
     RECT  98.604 14.989 98.694 15.025 ;
     RECT  101.016 14.675 105.426 15.115 ;
     RECT  2.304 14.827 10.818 15.223 ;
     RECT  57.816 14.827 65.43 15.223 ;
     RECT  98.604 15.025 98.766 15.251 ;
     RECT  57.816 15.223 65.502 15.295 ;
     RECT  99.615 14.549 99.99 15.331 ;
     RECT  99.615 15.331 100.026 15.389 ;
     RECT  2.304 15.223 10.854 15.403 ;
     RECT  13.215 7.529 13.497 15.403 ;
     RECT  57.816 15.295 65.754 15.403 ;
     RECT  67.215 5.261 67.497 15.403 ;
     RECT  107.136 14.957 107.154 15.449 ;
     RECT  98.676 15.251 98.766 15.601 ;
     RECT  99.615 15.389 99.897 15.601 ;
     RECT  101.016 15.115 106.038 15.629 ;
     RECT  101.016 15.629 105.606 15.835 ;
     RECT  98.676 15.601 99.897 16.141 ;
     RECT  100.8 15.835 105.606 16.169 ;
     RECT  106.56 15.691 106.578 16.219 ;
     RECT  106.56 16.219 107.154 16.259 ;
     RECT  98.604 16.141 99.897 16.367 ;
     RECT  107.892 16.411 107.91 16.529 ;
     RECT  106.56 16.259 106.578 16.799 ;
     RECT  2.304 15.403 14.346 17.113 ;
     RECT  100.8 16.169 105.57 17.179 ;
     RECT  2.304 17.113 14.742 17.221 ;
     RECT  98.604 16.367 98.73 17.249 ;
     RECT  2.304 17.221 14.814 17.339 ;
     RECT  107.136 16.987 107.154 17.339 ;
     RECT  99.615 16.367 99.897 17.455 ;
     RECT  98.748 17.455 99.897 17.609 ;
     RECT  107.892 17.563 107.91 17.609 ;
     RECT  98.748 17.609 98.766 17.651 ;
     RECT  100.8 17.179 106.038 17.947 ;
     RECT  99.615 17.609 99.897 17.959 ;
     RECT  100.8 17.947 106.074 18.059 ;
     RECT  106.56 18.121 106.578 18.173 ;
     RECT  57.816 15.403 69.21 18.301 ;
     RECT  98.604 18.229 98.622 18.391 ;
     RECT  99.615 17.959 100.062 18.571 ;
     RECT  100.8 18.059 105.462 18.571 ;
     RECT  107.892 18.331 107.91 18.599 ;
     RECT  57.816 18.301 69.282 18.697 ;
     RECT  106.596 18.391 106.614 18.715 ;
     RECT  2.304 17.339 14.346 18.769 ;
     RECT  70.668 3.931 70.686 18.805 ;
     RECT  2.304 18.769 14.562 18.811 ;
     RECT  57.816 18.697 69.426 18.811 ;
     RECT  70.596 18.805 70.686 18.811 ;
     RECT  72.615 11.947 74.07 18.811 ;
     RECT  106.596 18.715 107.154 18.959 ;
     RECT  99.615 18.571 105.462 19.051 ;
     RECT  106.596 18.959 106.614 19.051 ;
     RECT  99.615 19.051 106.614 19.277 ;
     RECT  2.304 18.811 17.622 19.301 ;
     RECT  98.604 18.391 98.694 19.615 ;
     RECT  98.604 19.615 98.766 19.769 ;
     RECT  99.615 19.277 106.578 19.769 ;
     RECT  13.104 19.301 17.622 19.877 ;
     RECT  98.64 19.769 98.766 19.877 ;
     RECT  57.816 18.811 74.07 19.913 ;
     RECT  98.676 19.877 98.766 19.913 ;
     RECT  13.176 19.877 17.622 19.949 ;
     RECT  98.676 19.913 98.694 19.949 ;
     RECT  99.615 19.769 105.534 19.949 ;
     RECT  106.596 20.005 106.614 20.203 ;
     RECT  107.892 20.395 107.91 20.687 ;
     RECT  106.596 20.203 107.154 20.965 ;
     RECT  18.615 2.413 18.897 21.091 ;
     RECT  106.56 20.965 107.154 21.227 ;
     RECT  94.215 13.055 94.662 21.271 ;
     RECT  18.576 21.091 18.897 21.299 ;
     RECT  99.615 19.949 105.426 21.352 ;
     RECT  2.304 19.301 12.33 21.469 ;
     RECT  96.912 21.091 97.002 21.469 ;
     RECT  97.74 8.815 97.758 21.469 ;
     RECT  94.215 21.271 94.734 21.533 ;
     RECT  98.748 21.499 98.766 21.539 ;
     RECT  94.215 21.533 94.698 21.569 ;
     RECT  96.912 21.469 97.758 21.569 ;
     RECT  2.268 21.469 12.33 21.581 ;
     RECT  96.912 21.569 96.966 21.659 ;
     RECT  13.215 19.949 17.622 21.973 ;
     RECT  99.615 21.352 106.038 21.973 ;
     RECT  99.36 21.973 106.038 22.037 ;
     RECT  13.215 21.973 17.802 22.072 ;
     RECT  107.136 21.227 107.154 22.081 ;
     RECT  96.912 21.659 96.93 22.109 ;
     RECT  106.524 22.081 107.154 22.157 ;
     RECT  106.56 22.157 107.154 22.171 ;
     RECT  13.215 22.072 17.838 22.219 ;
     RECT  18.615 21.299 18.897 22.219 ;
     RECT  0.108 22.171 0.126 22.301 ;
     RECT  106.56 22.171 107.19 22.301 ;
     RECT  106.56 22.301 107.154 22.505 ;
     RECT  96.948 22.477 96.966 22.613 ;
     RECT  99.36 22.037 105.426 22.621 ;
     RECT  2.304 21.581 12.33 22.648 ;
     RECT  2.268 22.648 12.33 22.739 ;
     RECT  83.268 14.909 83.697 22.747 ;
     RECT  98.784 22.621 105.426 22.747 ;
     RECT  98.64 22.747 105.426 22.784 ;
     RECT  83.232 22.747 83.697 22.847 ;
     RECT  13.215 22.219 18.897 23.371 ;
     RECT  68.688 19.913 74.07 23.371 ;
     RECT  99.36 22.784 105.426 23.419 ;
     RECT  106.56 22.505 106.614 23.419 ;
     RECT  13.215 23.371 19.278 23.629 ;
     RECT  99.36 23.419 106.614 23.729 ;
     RECT  13.215 23.629 19.422 23.827 ;
     RECT  68.688 23.371 74.286 23.827 ;
     RECT  96.912 23.665 96.93 23.927 ;
     RECT  94.215 21.569 94.662 23.933 ;
     RECT  13.215 23.827 19.458 23.947 ;
     RECT  24.015 7.529 24.297 23.947 ;
     RECT  68.688 23.827 74.574 23.947 ;
     RECT  75.816 6.235 78.297 23.947 ;
     RECT  106.56 23.729 106.614 24.187 ;
     RECT  96.948 24.169 96.966 24.269 ;
     RECT  68.688 23.947 78.297 24.283 ;
     RECT  13.215 23.947 21.906 24.427 ;
     RECT  13.215 24.427 22.302 24.475 ;
     RECT  23.292 23.947 24.297 24.475 ;
     RECT  68.688 24.283 78.462 24.475 ;
     RECT  79.2 2.827 79.866 24.475 ;
     RECT  99.36 23.729 105.498 24.763 ;
     RECT  106.56 24.187 107.154 24.763 ;
     RECT  96.912 24.943 96.93 25.043 ;
     RECT  99.36 24.763 107.154 25.181 ;
     RECT  99.36 25.181 105.426 25.285 ;
     RECT  94.215 23.933 94.59 25.321 ;
     RECT  98.748 25.285 105.426 25.387 ;
     RECT  106.56 25.181 107.154 25.709 ;
     RECT  94.215 25.321 94.662 25.861 ;
     RECT  107.892 25.867 107.91 25.979 ;
     RECT  94.215 25.861 94.698 26.159 ;
     RECT  98.604 25.387 105.426 26.251 ;
     RECT  0.54 26.131 0.558 26.285 ;
     RECT  98.604 26.251 106.038 26.429 ;
     RECT  107.136 25.709 107.154 26.443 ;
     RECT  68.688 24.475 79.866 26.591 ;
     RECT  0.108 26.761 0.126 26.861 ;
     RECT  106.56 26.443 107.154 27.059 ;
     RECT  98.676 26.429 105.426 27.211 ;
     RECT  98.604 27.211 105.426 27.595 ;
     RECT  98.604 27.595 106.038 27.779 ;
     RECT  94.215 26.159 94.662 27.917 ;
     RECT  98.604 27.779 105.642 27.941 ;
     RECT  98.604 27.941 98.622 28.211 ;
     RECT  13.215 24.475 24.297 28.219 ;
     RECT  68.688 26.591 74.394 28.291 ;
     RECT  68.688 28.291 74.754 28.409 ;
     RECT  68.688 28.409 74.682 28.445 ;
     RECT  107.136 27.059 107.154 28.453 ;
     RECT  13.215 28.219 24.426 28.507 ;
     RECT  75.492 26.591 79.866 28.507 ;
     RECT  80.964 13.051 82.098 28.507 ;
     RECT  107.136 28.453 107.19 28.541 ;
     RECT  99.36 27.941 105.642 28.699 ;
     RECT  99.36 28.699 106.038 28.795 ;
     RECT  98.892 28.795 106.038 28.957 ;
     RECT  2.304 22.739 12.33 29.083 ;
     RECT  2.268 29.083 12.33 29.129 ;
     RECT  98.748 28.957 106.038 29.263 ;
     RECT  107.136 28.541 107.154 29.263 ;
     RECT  98.748 29.263 107.154 29.309 ;
     RECT  26.712 29.263 26.73 29.363 ;
     RECT  98.748 29.309 106.038 29.371 ;
     RECT  98.604 29.371 106.038 29.597 ;
     RECT  75.492 28.507 82.098 29.839 ;
     RECT  13.215 28.507 25.902 30.073 ;
     RECT  13.215 30.073 26.118 30.235 ;
     RECT  98.748 29.597 106.038 30.235 ;
     RECT  107.136 29.309 107.154 30.235 ;
     RECT  13.215 30.235 26.298 30.343 ;
     RECT  27.072 30.235 27.09 30.343 ;
     RECT  98.748 30.235 107.154 30.569 ;
     RECT  75.492 29.839 82.386 30.715 ;
     RECT  83.268 22.847 83.697 30.715 ;
     RECT  98.748 30.569 106.614 30.749 ;
     RECT  13.215 30.343 27.09 30.805 ;
     RECT  94.215 27.917 94.59 30.811 ;
     RECT  53.172 9.617 54.162 30.847 ;
     RECT  53.1 30.847 54.162 30.875 ;
     RECT  98.748 30.749 105.642 30.883 ;
     RECT  98.676 30.883 105.642 30.991 ;
     RECT  13.215 30.805 27.198 31.225 ;
     RECT  98.604 30.991 105.642 31.289 ;
     RECT  13.215 31.225 27.378 31.339 ;
     RECT  13.215 31.339 27.486 31.621 ;
     RECT  53.892 30.875 54.162 31.657 ;
     RECT  53.1 30.875 53.118 31.675 ;
     RECT  13.215 31.621 27.594 31.72 ;
     RECT  52.956 31.675 53.118 31.721 ;
     RECT  106.56 30.749 106.614 31.801 ;
     RECT  53.892 31.657 54.81 31.829 ;
     RECT  13.215 31.72 27.702 31.891 ;
     RECT  13.215 31.891 27.774 31.915 ;
     RECT  51.015 8.333 51.714 32.161 ;
     RECT  98.604 31.289 105.426 32.189 ;
     RECT  106.56 31.801 107.19 32.299 ;
     RECT  53.1 31.721 53.118 32.341 ;
     RECT  53.892 31.829 54.414 32.341 ;
     RECT  13.215 31.915 28.17 32.467 ;
     RECT  49.032 5.297 49.05 32.467 ;
     RECT  13.215 32.467 28.386 32.491 ;
     RECT  29.415 2.143 29.79 32.491 ;
     RECT  75.492 30.715 83.697 32.491 ;
     RECT  49.032 32.467 49.734 32.503 ;
     RECT  106.524 32.299 107.19 32.525 ;
     RECT  53.1 32.341 54.414 32.531 ;
     RECT  53.244 32.531 54.414 32.567 ;
     RECT  53.28 32.567 54.414 32.603 ;
     RECT  0.54 31.891 0.558 32.683 ;
     RECT  0.108 32.683 0.558 32.729 ;
     RECT  50.724 32.161 51.714 32.729 ;
     RECT  106.524 32.525 107.154 32.729 ;
     RECT  2.304 29.129 12.33 32.773 ;
     RECT  13.215 32.491 29.79 32.773 ;
     RECT  98.748 32.189 105.426 32.875 ;
     RECT  98.748 32.875 106.038 32.971 ;
     RECT  0.54 32.729 0.558 33.101 ;
     RECT  107.136 32.729 107.154 33.539 ;
     RECT  98.604 32.971 106.038 33.583 ;
     RECT  98.604 33.583 106.614 33.677 ;
     RECT  75.492 32.491 84.51 34.051 ;
     RECT  98.604 33.677 106.578 34.079 ;
     RECT  75.492 34.051 84.618 34.159 ;
     RECT  2.304 32.773 29.79 34.219 ;
     RECT  75.492 34.159 84.654 34.219 ;
     RECT  75.492 34.219 84.978 34.429 ;
     RECT  2.304 34.219 30.042 34.501 ;
     RECT  2.304 34.501 30.078 34.727 ;
     RECT  28.62 34.727 30.078 34.747 ;
     RECT  31.032 34.219 31.05 34.747 ;
     RECT  75.492 34.429 85.338 34.795 ;
     RECT  86.076 0.571 86.67 34.795 ;
     RECT  28.62 34.747 31.374 34.799 ;
     RECT  106.56 34.079 106.578 34.933 ;
     RECT  106.56 34.933 106.614 34.973 ;
     RECT  98.604 34.079 105.534 35.159 ;
     RECT  99.036 35.159 105.534 35.515 ;
     RECT  106.56 34.973 106.578 35.515 ;
     RECT  99.036 35.515 106.578 35.701 ;
     RECT  99.036 35.701 106.614 35.741 ;
     RECT  2.304 34.727 27.666 35.851 ;
     RECT  28.764 34.799 31.374 35.851 ;
     RECT  99.036 35.741 106.038 35.879 ;
     RECT  99.036 35.879 105.642 35.941 ;
     RECT  2.304 35.851 31.374 35.977 ;
     RECT  94.215 30.811 94.662 35.995 ;
     RECT  98.676 35.941 105.642 36.121 ;
     RECT  98.604 36.121 105.642 36.239 ;
     RECT  107.136 35.899 107.154 36.239 ;
     RECT  2.304 35.977 31.698 36.391 ;
     RECT  98.64 36.239 105.642 36.419 ;
     RECT  2.304 36.391 31.734 36.475 ;
     RECT  33.084 4.555 33.102 36.475 ;
     RECT  98.748 36.419 105.606 36.617 ;
     RECT  75.492 34.795 86.994 36.625 ;
     RECT  75.492 36.625 87.066 36.931 ;
     RECT  75.492 36.931 87.102 37.021 ;
     RECT  75.492 37.021 87.642 37.051 ;
     RECT  88.815 2.413 89.097 37.051 ;
     RECT  2.304 36.475 33.102 37.277 ;
     RECT  98.748 36.617 105.426 37.363 ;
     RECT  98.676 37.363 105.426 37.471 ;
     RECT  2.412 37.277 33.102 37.589 ;
     RECT  98.604 37.471 105.426 37.589 ;
     RECT  106.56 36.661 106.578 37.597 ;
     RECT  2.415 37.589 33.102 37.627 ;
     RECT  0.54 36.931 0.558 37.661 ;
     RECT  106.56 37.597 107.19 37.661 ;
     RECT  98.748 37.589 105.426 37.819 ;
     RECT  106.56 37.661 106.614 37.819 ;
     RECT  0.108 37.819 0.126 37.859 ;
     RECT  98.748 37.819 106.614 38.189 ;
     RECT  2.415 37.627 34.002 38.347 ;
     RECT  98.748 38.189 106.578 38.479 ;
     RECT  98.604 38.479 106.578 38.579 ;
     RECT  107.892 38.539 107.91 38.579 ;
     RECT  2.304 38.347 34.002 38.713 ;
     RECT  34.776 7.529 35.226 38.713 ;
     RECT  94.215 35.995 94.698 38.717 ;
     RECT  98.964 38.579 106.578 38.765 ;
     RECT  2.304 38.713 35.226 38.779 ;
     RECT  36.432 8.437 37.026 38.779 ;
     RECT  75.492 37.051 89.097 38.779 ;
     RECT  90.072 2.875 90.09 38.779 ;
     RECT  106.56 38.765 106.578 38.911 ;
     RECT  98.964 38.765 105.426 39.523 ;
     RECT  94.215 38.717 94.662 39.595 ;
     RECT  107.892 39.307 107.91 39.659 ;
     RECT  93.744 39.595 94.662 39.821 ;
     RECT  106.56 38.911 106.614 39.883 ;
     RECT  106.56 39.883 107.154 40.127 ;
     RECT  107.136 40.127 107.154 40.261 ;
     RECT  107.136 40.261 107.19 40.301 ;
     RECT  98.604 39.523 105.426 40.459 ;
     RECT  75.492 38.779 91.89 40.873 ;
     RECT  75.492 40.873 91.962 40.981 ;
     RECT  98.604 40.459 106.002 41.009 ;
     RECT  2.304 38.779 37.026 41.035 ;
     RECT  38.232 1.099 38.79 41.035 ;
     RECT  39.888 2.413 41.058 41.035 ;
     RECT  42.156 4.925 42.714 41.035 ;
     RECT  75.492 40.981 92.034 41.035 ;
     RECT  93.744 39.821 94.626 41.035 ;
     RECT  98.676 41.009 106.002 41.035 ;
     RECT  98.676 41.035 106.038 41.071 ;
     RECT  107.136 40.301 107.154 41.071 ;
     RECT  2.268 41.035 39.15 41.207 ;
     RECT  98.676 41.071 107.154 41.243 ;
     RECT  98.748 41.243 107.154 41.279 ;
     RECT  106.524 41.279 107.154 41.405 ;
     RECT  2.304 41.207 39.15 41.563 ;
     RECT  39.888 41.035 43.182 41.563 ;
     RECT  44.46 4.157 45.99 41.563 ;
     RECT  75.492 41.035 95.022 41.563 ;
     RECT  75.492 41.563 95.67 42.139 ;
     RECT  96.768 39.019 96.786 42.139 ;
     RECT  98.748 41.279 105.426 42.223 ;
     RECT  98.604 42.223 105.426 42.523 ;
     RECT  106.524 41.405 106.578 42.523 ;
     RECT  98.604 42.523 106.578 42.629 ;
     RECT  106.56 42.629 106.578 42.691 ;
     RECT  75.492 42.139 96.786 42.763 ;
     RECT  97.74 21.569 97.758 42.763 ;
     RECT  97.74 42.763 97.83 42.791 ;
     RECT  106.56 42.691 106.614 43.133 ;
     RECT  107.136 43.231 107.19 43.325 ;
     RECT  98.604 42.629 105.426 43.601 ;
     RECT  98.676 43.601 105.426 43.681 ;
     RECT  98.676 43.681 106.038 43.709 ;
     RECT  2.304 41.563 45.99 44.221 ;
     RECT  98.748 43.709 106.038 44.383 ;
     RECT  107.136 43.325 107.154 44.383 ;
     RECT  97.812 42.791 97.83 44.443 ;
     RECT  98.748 44.383 107.154 44.443 ;
     RECT  97.56 44.443 107.154 44.609 ;
     RECT  2.268 44.221 45.99 44.879 ;
     RECT  97.56 44.609 106.614 44.987 ;
     RECT  75.492 42.763 96.822 45.019 ;
     RECT  97.56 44.987 105.426 45.019 ;
     RECT  107.892 45.547 107.91 45.869 ;
     RECT  51.015 32.729 51.714 45.931 ;
     RECT  49.032 32.503 49.914 46.237 ;
     RECT  50.832 45.931 51.714 46.237 ;
     RECT  75.492 45.019 105.426 46.315 ;
     RECT  106.56 44.987 106.614 46.315 ;
     RECT  46.764 46.237 46.782 46.381 ;
     RECT  75.492 46.315 106.614 46.409 ;
     RECT  106.56 46.409 106.614 46.541 ;
     RECT  68.688 28.445 74.394 46.741 ;
     RECT  53.424 32.603 54.414 46.769 ;
     RECT  46.764 46.381 46.818 46.813 ;
     RECT  49.032 46.237 51.714 46.813 ;
     RECT  49.032 46.813 52.074 46.84 ;
     RECT  54.396 46.769 54.414 46.921 ;
     RECT  46.764 46.813 46.854 46.949 ;
     RECT  49.032 46.84 52.182 47.219 ;
     RECT  106.56 46.541 106.578 47.309 ;
     RECT  54.396 46.921 54.738 47.317 ;
     RECT  54.396 47.317 54.81 47.353 ;
     RECT  50.436 47.219 52.182 47.461 ;
     RECT  50.436 47.461 52.218 47.551 ;
     RECT  54.396 47.353 54.846 47.579 ;
     RECT  75.492 46.409 105.606 47.611 ;
     RECT  54.396 47.579 54.81 47.615 ;
     RECT  46.764 46.949 46.782 47.759 ;
     RECT  50.436 47.551 52.326 47.821 ;
     RECT  68.688 46.741 74.466 47.929 ;
     RECT  56.415 8.339 56.697 47.992 ;
     RECT  49.032 47.219 49.662 48.001 ;
     RECT  50.436 47.821 52.434 48.001 ;
     RECT  68.688 47.929 74.682 48.029 ;
     RECT  56.304 47.992 56.697 48.128 ;
     RECT  54.648 47.615 54.81 48.389 ;
     RECT  54.72 48.389 54.738 48.461 ;
     RECT  53.424 46.769 53.442 48.469 ;
     RECT  53.424 48.469 53.658 48.505 ;
     RECT  49.032 48.001 52.434 48.569 ;
     RECT  49.824 48.569 52.434 48.631 ;
     RECT  53.208 48.505 53.658 48.631 ;
     RECT  46.836 48.703 46.854 48.811 ;
     RECT  46.764 48.811 46.854 48.839 ;
     RECT  107.136 47.467 107.154 48.901 ;
     RECT  46.764 48.839 46.782 48.929 ;
     RECT  57.816 19.913 67.554 48.937 ;
     RECT  68.688 48.029 74.466 48.937 ;
     RECT  49.824 48.631 53.658 48.955 ;
     RECT  75.492 47.611 106.038 48.955 ;
     RECT  107.136 48.901 107.19 48.955 ;
     RECT  57.816 48.937 67.662 48.973 ;
     RECT  68.436 48.937 74.466 48.973 ;
     RECT  49.824 48.955 53.694 49.001 ;
     RECT  75.492 48.955 107.19 49.009 ;
     RECT  75.456 49.009 107.19 49.181 ;
     RECT  49.824 49.001 53.55 49.343 ;
     RECT  50.004 49.343 53.55 49.517 ;
     RECT  50.04 49.517 53.55 49.981 ;
     RECT  54.432 49.891 54.45 49.981 ;
     RECT  2.304 44.879 45.99 50.053 ;
     RECT  46.728 49.819 46.746 50.053 ;
     RECT  57.816 48.973 74.466 50.153 ;
     RECT  68.364 50.153 74.466 50.189 ;
     RECT  75.456 49.181 106.614 50.333 ;
     RECT  50.04 49.981 54.45 50.359 ;
     RECT  50.04 50.359 54.522 50.395 ;
     RECT  68.688 50.189 74.466 50.431 ;
     RECT  49.968 50.395 54.522 50.539 ;
     RECT  107.136 50.491 107.154 50.549 ;
     RECT  68.688 50.431 74.718 50.587 ;
     RECT  75.456 50.333 106.038 50.587 ;
     RECT  49.896 50.539 54.558 50.717 ;
     RECT  2.304 50.053 46.746 50.731 ;
     RECT  49.032 48.569 49.05 50.731 ;
     RECT  49.896 50.717 52.038 50.731 ;
     RECT  107.892 50.635 107.91 50.819 ;
     RECT  55.404 50.863 55.422 50.899 ;
     RECT  52.956 50.717 54.558 51.097 ;
     RECT  55.404 50.899 55.53 51.097 ;
     RECT  52.956 51.097 55.53 51.211 ;
     RECT  2.304 50.731 46.926 51.259 ;
     RECT  52.956 51.211 55.566 51.269 ;
     RECT  49.032 50.731 52.038 51.307 ;
     RECT  68.688 50.587 106.038 51.331 ;
     RECT  68.688 51.331 106.614 51.437 ;
     RECT  2.304 51.259 47.214 51.467 ;
     RECT  52.956 51.269 55.53 51.503 ;
     RECT  48.564 51.307 52.038 51.511 ;
     RECT  0.108 51.592 0.126 51.601 ;
     RECT  53.172 51.503 55.53 51.629 ;
     RECT  68.688 51.437 106.578 51.629 ;
     RECT  48.564 51.511 52.182 51.637 ;
     RECT  0.108 51.601 0.198 51.677 ;
     RECT  68.688 51.629 74.538 51.701 ;
     RECT  53.172 51.629 54.45 51.737 ;
     RECT  53.172 51.737 53.442 51.773 ;
     RECT  54.288 51.737 54.378 51.773 ;
     RECT  75.312 51.629 106.578 51.821 ;
     RECT  2.415 51.467 47.214 51.871 ;
     RECT  56.415 48.128 56.697 51.871 ;
     RECT  56.304 51.871 56.697 51.917 ;
     RECT  2.415 51.871 47.286 51.931 ;
     RECT  48.564 51.637 52.218 51.931 ;
     RECT  55.296 51.629 55.53 51.935 ;
     RECT  2.415 51.931 52.218 51.943 ;
     RECT  55.332 51.935 55.53 52.141 ;
     RECT  75.42 51.821 106.578 52.169 ;
     RECT  55.332 52.141 55.566 52.205 ;
     RECT  2.415 51.943 52.254 52.241 ;
     RECT  2.415 52.241 51.642 52.249 ;
     RECT  55.512 52.205 55.566 52.277 ;
     RECT  55.548 52.277 55.566 52.321 ;
     RECT  55.548 52.321 55.638 52.349 ;
     RECT  55.62 52.349 55.638 52.439 ;
     RECT  75.456 52.169 106.578 52.511 ;
     RECT  0.108 51.677 0.126 52.589 ;
     RECT  75.492 52.511 106.578 52.717 ;
     RECT  75.492 52.717 106.614 52.781 ;
     RECT  107.172 53.563 107.19 53.741 ;
     RECT  54.288 51.773 54.306 53.869 ;
     RECT  75.492 52.781 106.074 53.897 ;
     RECT  53.28 51.773 53.442 54.031 ;
     RECT  54.18 53.869 54.306 54.031 ;
     RECT  106.02 53.897 106.074 54.031 ;
     RECT  53.28 54.031 54.306 54.077 ;
     RECT  54.18 54.077 54.306 54.095 ;
     RECT  75.492 53.897 105.297 54.643 ;
     RECT  106.02 54.031 106.614 54.643 ;
     RECT  68.688 51.701 74.466 54.707 ;
     RECT  75.492 54.643 106.614 54.707 ;
     RECT  75.492 54.707 105.498 54.779 ;
     RECT  106.56 54.707 106.614 54.811 ;
     RECT  75.492 54.779 105.318 55.139 ;
     RECT  106.56 54.811 107.154 55.381 ;
     RECT  106.56 55.381 107.19 55.421 ;
     RECT  75.492 55.139 105.297 55.963 ;
     RECT  75.492 55.963 105.714 56.129 ;
     RECT  106.56 55.421 106.614 56.155 ;
     RECT  106.56 56.155 107.154 56.219 ;
     RECT  75.492 56.129 105.498 56.399 ;
     RECT  106.56 56.219 106.614 56.923 ;
     RECT  75.492 56.399 105.297 57.209 ;
     RECT  106.02 56.923 106.614 57.259 ;
     RECT  57.816 50.153 67.554 57.335 ;
     RECT  106.02 57.259 107.154 57.485 ;
     RECT  57.888 57.335 67.554 57.569 ;
     RECT  58.428 57.569 67.554 57.847 ;
     RECT  68.688 54.707 74.394 57.847 ;
     RECT  106.596 57.485 107.154 57.919 ;
     RECT  58.428 57.847 74.394 57.983 ;
     RECT  98.352 57.209 105.297 57.991 ;
     RECT  58.5 57.983 74.394 58.019 ;
     RECT  106.596 57.919 107.19 58.253 ;
     RECT  98.352 57.991 105.39 58.423 ;
     RECT  107.136 58.253 107.19 58.445 ;
     RECT  58.968 58.019 74.394 58.793 ;
     RECT  98.064 58.423 105.39 58.795 ;
     RECT  59.544 58.793 74.394 58.829 ;
     RECT  98.064 58.795 105.462 58.891 ;
     RECT  107.136 58.445 107.154 59.233 ;
     RECT  60.12 58.829 74.394 59.531 ;
     RECT  98.064 58.891 105.786 59.563 ;
     RECT  75.492 57.209 97.326 59.575 ;
     RECT  98.064 59.563 106.038 59.575 ;
     RECT  75.492 59.575 106.038 59.737 ;
     RECT  107.136 59.233 107.19 59.737 ;
     RECT  75.492 59.737 107.19 59.837 ;
     RECT  60.156 59.531 74.394 59.873 ;
     RECT  75.492 59.837 105.318 59.909 ;
     RECT  0.54 59.809 0.558 59.981 ;
     RECT  106.56 59.837 107.19 59.981 ;
     RECT  60.696 59.873 74.394 60.539 ;
     RECT  61.236 60.539 74.394 60.809 ;
     RECT  75.492 59.909 105.297 60.817 ;
     RECT  106.56 59.981 106.614 60.859 ;
     RECT  75.492 60.817 105.318 60.917 ;
     RECT  106.524 60.859 106.614 60.961 ;
     RECT  106.524 60.961 107.19 61.085 ;
     RECT  106.524 61.085 107.154 61.231 ;
     RECT  106.02 61.231 107.154 61.277 ;
     RECT  75.492 60.917 105.297 61.819 ;
     RECT  106.596 61.277 107.154 62.011 ;
     RECT  106.524 62.011 107.154 62.069 ;
     RECT  75.492 61.819 105.678 62.131 ;
     RECT  53.28 54.077 53.442 62.159 ;
     RECT  75.492 62.131 106.398 62.237 ;
     RECT  53.424 62.159 53.442 62.275 ;
     RECT  54.288 54.095 54.306 62.275 ;
     RECT  61.815 60.809 74.394 62.339 ;
     RECT  63 62.339 74.394 62.609 ;
     RECT  75.492 62.237 105.462 62.699 ;
     RECT  106.38 62.237 106.398 62.813 ;
     RECT  63 62.609 67.554 62.879 ;
     RECT  107.136 62.069 107.154 62.941 ;
     RECT  53.424 62.275 54.306 63.049 ;
     RECT  53.316 63.049 54.306 63.101 ;
     RECT  53.856 63.101 54.306 63.121 ;
     RECT  63.612 62.879 67.554 63.239 ;
     RECT  0.54 63.121 0.558 63.389 ;
     RECT  63.648 63.239 67.554 63.419 ;
     RECT  106.56 62.941 107.154 63.547 ;
     RECT  68.688 62.609 74.394 63.553 ;
     RECT  75.492 62.699 105.297 63.553 ;
     RECT  106.02 63.547 107.154 63.689 ;
     RECT  64.116 63.419 67.554 63.959 ;
     RECT  64.188 63.959 67.554 64.157 ;
     RECT  0.54 64.363 0.558 64.493 ;
     RECT  106.56 63.689 107.154 64.651 ;
     RECT  64.656 64.157 67.554 64.733 ;
     RECT  65.232 64.733 67.554 64.769 ;
     RECT  68.688 63.553 105.297 64.939 ;
     RECT  106.02 64.651 107.154 64.939 ;
     RECT  65.268 64.769 67.554 65.039 ;
     RECT  68.688 64.939 107.154 65.165 ;
     RECT  106.02 65.165 107.154 65.453 ;
     RECT  65.808 65.039 67.554 65.669 ;
     RECT  106.56 65.453 107.154 65.669 ;
     RECT  2.304 52.249 51.642 65.749 ;
     RECT  2.268 65.749 51.642 66.317 ;
     RECT  66.384 65.669 67.554 66.317 ;
     RECT  106.56 65.669 106.578 66.379 ;
     RECT  11.664 66.317 51.642 66.389 ;
     RECT  2.268 66.317 10.566 66.413 ;
     RECT  11.808 66.389 51.642 66.479 ;
     RECT  106.02 66.379 106.578 66.559 ;
     RECT  66.96 66.317 67.554 66.857 ;
     RECT  12.24 66.479 51.642 67.019 ;
     RECT  106.02 66.559 106.614 67.199 ;
     RECT  2.304 66.413 10.566 67.292 ;
     RECT  67.215 66.857 67.554 67.397 ;
     RECT  2.304 67.292 8.154 67.468 ;
     RECT  2.268 67.468 8.154 67.667 ;
     RECT  106.56 67.199 106.614 67.801 ;
     RECT  2.304 67.667 8.154 67.829 ;
     RECT  106.56 67.801 107.19 67.901 ;
     RECT  2.304 67.829 8.097 68.099 ;
     RECT  0.54 67.711 0.558 68.155 ;
     RECT  68.688 65.165 105.297 68.179 ;
     RECT  0.108 68.155 0.558 68.285 ;
     RECT  68.688 68.179 105.498 68.369 ;
     RECT  106.56 67.901 107.154 68.369 ;
     RECT  69.228 68.369 105.498 68.611 ;
     RECT  106.56 68.369 106.614 68.611 ;
     RECT  69.228 68.611 106.614 68.669 ;
     RECT  106.524 68.669 106.614 68.861 ;
     RECT  12.816 67.019 51.642 68.909 ;
     RECT  0.54 68.285 0.558 69.245 ;
     RECT  69.228 68.669 105.297 69.323 ;
     RECT  69.804 69.323 105.297 69.359 ;
     RECT  106.596 68.861 106.614 69.403 ;
     RECT  14.508 68.909 51.642 69.449 ;
     RECT  2.34 68.099 8.097 69.595 ;
     RECT  2.304 69.595 8.097 69.601 ;
     RECT  8.892 67.292 10.566 69.601 ;
     RECT  106.596 69.403 107.154 69.691 ;
     RECT  2.304 69.601 10.566 69.719 ;
     RECT  70.38 69.359 105.297 69.719 ;
     RECT  106.596 69.691 107.19 69.821 ;
     RECT  70.38 69.719 74.394 69.989 ;
     RECT  75.492 69.719 105.297 70.141 ;
     RECT  75.492 70.141 105.39 70.171 ;
     RECT  106.596 69.821 106.614 70.171 ;
     RECT  14.544 69.449 51.642 70.259 ;
     RECT  15.66 70.259 51.642 70.529 ;
     RECT  75.492 70.171 106.614 70.699 ;
     RECT  70.956 69.989 74.394 70.709 ;
     RECT  16.236 70.529 51.642 70.835 ;
     RECT  8.892 69.719 10.566 70.951 ;
     RECT  16.38 70.835 51.642 70.979 ;
     RECT  8.892 70.951 10.818 71.069 ;
     RECT  75.492 70.699 107.154 71.069 ;
     RECT  75.492 71.069 106.578 71.177 ;
     RECT  71.496 70.709 74.394 71.339 ;
     RECT  71.604 71.339 74.394 71.411 ;
     RECT  2.304 69.719 8.097 71.447 ;
     RECT  16.776 70.979 51.642 71.447 ;
     RECT  16.848 71.447 51.642 71.519 ;
     RECT  72.072 71.411 74.394 71.519 ;
     RECT  2.34 71.447 8.097 71.803 ;
     RECT  106.524 71.177 106.578 71.851 ;
     RECT  72.108 71.519 74.394 71.879 ;
     RECT  0.54 71.761 0.558 71.885 ;
     RECT  75.492 71.177 105.642 72.043 ;
     RECT  106.524 71.851 106.614 72.043 ;
     RECT  17.352 71.519 51.642 72.059 ;
     RECT  75.492 72.043 106.614 72.059 ;
     RECT  106.02 72.059 106.614 72.235 ;
     RECT  17.424 72.059 51.642 72.257 ;
     RECT  106.02 72.235 107.154 72.257 ;
     RECT  2.34 71.803 8.154 72.619 ;
     RECT  8.892 71.069 10.566 72.661 ;
     RECT  2.304 72.619 8.154 72.689 ;
     RECT  106.56 72.257 107.154 72.689 ;
     RECT  17.928 72.257 51.642 72.833 ;
     RECT  8.892 72.661 10.926 72.869 ;
     RECT  72.615 71.879 74.394 72.869 ;
     RECT  107.892 72.811 107.91 72.869 ;
     RECT  75.492 72.059 105.297 72.931 ;
     RECT  0.108 72.301 0.126 73.037 ;
     RECT  107.172 72.931 107.19 73.037 ;
     RECT  18.504 72.833 51.642 73.139 ;
     RECT  75.492 72.931 105.462 73.195 ;
     RECT  2.304 72.689 8.097 73.387 ;
     RECT  75.492 73.195 105.498 73.421 ;
     RECT  2.268 73.387 8.097 73.499 ;
     RECT  106.596 73.471 107.154 73.565 ;
     RECT  0.54 73.309 0.558 73.849 ;
     RECT  18.615 73.139 51.642 73.913 ;
     RECT  73.836 72.869 74.394 73.913 ;
     RECT  2.304 73.499 8.097 73.921 ;
     RECT  8.892 72.869 10.566 73.921 ;
     RECT  74.376 73.913 74.394 73.949 ;
     RECT  2.304 73.921 10.566 74.111 ;
     RECT  19.656 73.913 51.642 74.219 ;
     RECT  75.492 73.421 105.297 74.281 ;
     RECT  106.02 73.921 106.038 74.281 ;
     RECT  0.504 73.849 0.558 74.333 ;
     RECT  19.728 74.219 51.642 74.453 ;
     RECT  19.8 74.453 51.642 74.489 ;
     RECT  107.136 73.565 107.154 74.579 ;
     RECT  75.492 74.281 106.038 74.821 ;
     RECT  75.492 74.821 106.614 74.909 ;
     RECT  2.304 74.111 8.097 74.929 ;
     RECT  8.892 74.111 10.566 74.929 ;
     RECT  75.492 74.909 106.038 75.119 ;
     RECT  20.196 74.489 51.642 75.263 ;
     RECT  75.492 75.119 105.297 75.299 ;
     RECT  2.304 74.929 10.566 75.433 ;
     RECT  2.304 75.433 10.782 75.469 ;
     RECT  0.54 74.333 0.558 75.485 ;
     RECT  107.136 75.451 107.154 75.497 ;
     RECT  2.304 75.469 10.854 75.569 ;
     RECT  2.304 75.569 10.782 75.659 ;
     RECT  20.232 75.263 51.642 75.659 ;
     RECT  75.636 75.299 105.297 75.659 ;
     RECT  76.068 75.659 105.297 75.839 ;
     RECT  106.02 75.119 106.038 75.901 ;
     RECT  21.096 75.659 51.642 76.073 ;
     RECT  76.14 75.839 105.297 76.073 ;
     RECT  107.892 75.067 107.91 76.109 ;
     RECT  53.856 63.121 54.594 76.363 ;
     RECT  106.02 75.901 106.614 76.411 ;
     RECT  21.348 76.073 51.642 76.469 ;
     RECT  106.02 76.411 107.154 76.469 ;
     RECT  76.644 76.073 105.297 76.513 ;
     RECT  106.02 76.469 106.614 76.513 ;
     RECT  76.644 76.513 106.614 76.577 ;
     RECT  77.22 76.577 106.614 76.829 ;
     RECT  53.856 76.363 54.954 76.891 ;
     RECT  53.856 76.891 55.278 76.928 ;
     RECT  77.22 76.829 106.074 77.009 ;
     RECT  2.304 75.659 10.566 77.053 ;
     RECT  77.22 77.009 105.297 77.117 ;
     RECT  2.268 77.053 10.566 77.125 ;
     RECT  21.924 76.469 51.642 77.153 ;
     RECT  77.292 77.117 105.297 77.189 ;
     RECT  106.02 77.009 106.074 77.387 ;
     RECT  106.056 77.387 106.074 77.459 ;
     RECT  107.172 77.287 107.19 77.549 ;
     RECT  77.796 77.189 105.297 77.657 ;
     RECT  77.868 77.657 105.297 77.693 ;
     RECT  2.268 77.125 10.818 77.701 ;
     RECT  23.076 77.153 51.642 77.729 ;
     RECT  23.22 77.729 51.642 77.819 ;
     RECT  107.136 77.707 107.154 77.819 ;
     RECT  2.268 77.701 10.854 77.927 ;
     RECT  2.304 77.927 10.854 77.981 ;
     RECT  8.892 77.981 10.854 77.999 ;
     RECT  106.56 77.899 106.614 78.283 ;
     RECT  78.015 77.693 105.297 78.367 ;
     RECT  106.02 78.283 106.614 78.367 ;
     RECT  78.015 78.367 106.614 78.509 ;
     RECT  12.816 68.909 13.497 78.539 ;
     RECT  0.54 77.971 0.558 78.601 ;
     RECT  78.015 78.509 106.578 78.629 ;
     RECT  0.108 78.601 0.558 78.701 ;
     RECT  107.892 78.637 107.91 78.701 ;
     RECT  0.54 78.701 0.558 78.893 ;
     RECT  21.924 77.153 21.942 78.899 ;
     RECT  23.616 77.819 51.642 78.935 ;
     RECT  2.304 77.981 8.097 79.243 ;
     RECT  8.892 77.999 10.566 79.243 ;
     RECT  23.616 78.935 51.297 79.277 ;
     RECT  79.488 78.629 106.578 79.313 ;
     RECT  20.232 75.659 20.25 79.349 ;
     RECT  79.56 79.313 106.578 79.349 ;
     RECT  80.064 79.349 106.578 79.439 ;
     RECT  105.012 79.439 106.578 79.469 ;
     RECT  2.304 79.243 10.566 79.547 ;
     RECT  24.015 79.277 51.297 79.619 ;
     RECT  106.524 79.469 106.578 79.681 ;
     RECT  0.54 79.681 0.558 79.853 ;
     RECT  106.524 79.681 107.19 79.853 ;
     RECT  80.064 79.439 104.274 79.979 ;
     RECT  25.344 79.619 51.297 80.159 ;
     RECT  80.136 79.979 104.274 80.249 ;
     RECT  80.64 80.249 104.274 80.257 ;
     RECT  105.012 79.469 105.462 80.257 ;
     RECT  2.412 79.547 10.566 80.285 ;
     RECT  80.64 80.257 105.462 80.329 ;
     RECT  106.524 79.853 106.614 80.329 ;
     RECT  2.412 80.285 8.097 80.491 ;
     RECT  80.64 80.329 106.614 80.627 ;
     RECT  25.92 80.159 51.297 80.699 ;
     RECT  81.216 80.627 106.614 80.699 ;
     RECT  25.992 80.699 51.297 80.789 ;
     RECT  2.304 80.491 8.097 80.923 ;
     RECT  2.268 80.923 8.097 80.969 ;
     RECT  81.756 80.699 106.614 81.059 ;
     RECT  0.54 80.671 0.558 81.149 ;
     RECT  26.496 80.789 51.297 81.329 ;
     RECT  105.015 81.059 106.614 81.341 ;
     RECT  81.756 81.059 104.274 81.635 ;
     RECT  2.304 80.969 8.097 81.643 ;
     RECT  8.892 80.285 10.566 81.643 ;
     RECT  81.828 81.635 104.274 81.779 ;
     RECT  2.304 81.643 10.566 81.905 ;
     RECT  105.015 81.341 106.002 81.917 ;
     RECT  82.332 81.779 104.274 82.139 ;
     RECT  82.908 82.139 104.274 82.219 ;
     RECT  105.015 81.917 105.297 82.219 ;
     RECT  27.036 81.329 51.297 82.283 ;
     RECT  27.036 82.283 27.054 82.409 ;
     RECT  107.136 82.267 107.154 82.409 ;
     RECT  106.02 82.075 106.038 82.459 ;
     RECT  82.908 82.219 105.297 82.679 ;
     RECT  83.415 82.679 105.297 83.057 ;
     RECT  0.54 82.831 0.558 83.261 ;
     RECT  84.636 83.057 105.297 83.497 ;
     RECT  106.02 82.459 106.578 83.497 ;
     RECT  84.636 83.497 106.578 83.641 ;
     RECT  28.188 82.283 51.297 83.669 ;
     RECT  84.636 83.641 106.614 83.789 ;
     RECT  29.34 83.669 51.297 83.831 ;
     RECT  28.188 83.669 28.242 83.939 ;
     RECT  84.636 83.789 106.002 84.209 ;
     RECT  84.672 84.209 106.002 84.479 ;
     RECT  107.136 83.947 107.154 84.569 ;
     RECT  29.415 83.831 51.297 84.749 ;
     RECT  85.212 84.479 106.002 84.749 ;
     RECT  2.304 81.905 8.097 84.911 ;
     RECT  85.752 84.749 106.002 84.941 ;
     RECT  85.752 84.941 105.39 84.947 ;
     RECT  7.092 84.911 8.097 85.261 ;
     RECT  8.892 81.905 10.566 85.261 ;
     RECT  106.56 85.099 106.578 85.291 ;
     RECT  7.092 85.261 10.566 85.424 ;
     RECT  8.892 85.424 10.566 85.531 ;
     RECT  30.456 84.749 51.297 85.559 ;
     RECT  85.788 84.947 105.39 85.559 ;
     RECT  8.892 85.531 10.818 85.649 ;
     RECT  85.788 85.559 104.274 85.649 ;
     RECT  105.015 85.559 105.39 85.685 ;
     RECT  7.092 85.424 8.097 85.801 ;
     RECT  106.56 85.291 107.154 86.189 ;
     RECT  2.304 84.911 6.174 86.197 ;
     RECT  6.912 85.801 8.097 86.197 ;
     RECT  2.304 86.197 8.154 86.237 ;
     RECT  86.328 85.649 104.274 86.305 ;
     RECT  105.015 85.685 105.297 86.305 ;
     RECT  31.032 85.559 51.297 86.369 ;
     RECT  86.328 86.305 105.297 86.369 ;
     RECT  106.02 86.251 106.038 86.369 ;
     RECT  86.904 86.369 105.297 86.443 ;
     RECT  2.304 86.237 8.097 86.495 ;
     RECT  86.904 86.443 105.606 86.531 ;
     RECT  86.904 86.531 104.274 86.639 ;
     RECT  105.015 86.531 105.606 86.639 ;
     RECT  31.644 86.369 51.297 86.729 ;
     RECT  86.904 86.639 104.238 86.837 ;
     RECT  32.184 86.729 51.297 86.999 ;
     RECT  107.1 86.189 107.154 87.151 ;
     RECT  2.304 86.495 4.626 87.241 ;
     RECT  5.4 86.495 8.097 87.241 ;
     RECT  32.22 86.999 51.297 87.377 ;
     RECT  105.015 86.639 105.297 87.385 ;
     RECT  87.48 86.837 104.238 87.413 ;
     RECT  88.056 87.413 104.238 87.421 ;
     RECT  106.596 87.151 107.154 87.449 ;
     RECT  32.76 87.377 51.297 87.539 ;
     RECT  106.596 87.449 106.614 87.581 ;
     RECT  88.056 87.421 104.274 87.809 ;
     RECT  107.892 87.739 107.91 87.809 ;
     RECT  88.128 87.809 104.274 87.917 ;
     RECT  32.796 87.539 51.297 87.953 ;
     RECT  105.015 87.385 105.318 87.961 ;
     RECT  88.596 87.917 104.274 88.259 ;
     RECT  88.596 88.259 93.258 88.529 ;
     RECT  106.56 87.931 106.578 88.619 ;
     RECT  94.215 88.259 104.274 88.663 ;
     RECT  105.015 87.961 105.462 88.663 ;
     RECT  32.832 87.953 51.297 88.691 ;
     RECT  94.215 88.663 105.462 88.699 ;
     RECT  94.215 88.699 105.714 88.799 ;
     RECT  33.876 88.691 51.297 88.889 ;
     RECT  2.304 87.241 8.097 88.925 ;
     RECT  88.815 88.529 93.258 89.069 ;
     RECT  8.892 85.649 10.566 89.195 ;
     RECT  107.136 88.888 107.154 89.464 ;
     RECT  89.82 89.069 93.258 89.609 ;
     RECT  32.832 88.691 32.85 89.699 ;
     RECT  2.304 88.925 6.066 89.707 ;
     RECT  6.84 88.925 8.097 89.707 ;
     RECT  94.215 88.799 105.498 89.779 ;
     RECT  106.56 89.464 107.154 89.779 ;
     RECT  34.452 88.889 51.297 89.807 ;
     RECT  2.304 89.707 8.097 89.851 ;
     RECT  94.215 89.779 107.154 89.888 ;
     RECT  107.136 89.888 107.154 89.941 ;
     RECT  2.304 89.851 8.154 89.969 ;
     RECT  8.892 89.195 8.946 89.969 ;
     RECT  0.108 89.941 0.126 90.077 ;
     RECT  107.136 89.941 107.19 90.077 ;
     RECT  0.18 90.091 0.198 90.221 ;
     RECT  34.815 89.807 51.297 90.347 ;
     RECT  14.544 70.259 14.562 90.419 ;
     RECT  90.324 89.609 93.258 90.419 ;
     RECT  107.136 90.077 107.154 90.617 ;
     RECT  90.9 90.419 93.258 90.653 ;
     RECT  90.972 90.653 93.258 90.689 ;
     RECT  10.152 89.195 10.566 90.751 ;
     RECT  94.215 89.888 106.038 90.751 ;
     RECT  10.152 90.751 10.818 90.959 ;
     RECT  2.304 89.969 8.097 91.049 ;
     RECT  91.476 90.689 93.258 91.049 ;
     RECT  2.304 91.049 4.734 91.085 ;
     RECT  94.215 90.751 106.614 91.157 ;
     RECT  53.856 76.928 54.594 91.195 ;
     RECT  91.512 91.049 93.258 91.229 ;
     RECT  53.712 91.195 54.594 91.319 ;
     RECT  0.54 91.165 0.558 91.373 ;
     RECT  36.18 90.347 51.297 91.391 ;
     RECT  36.756 91.391 51.297 91.499 ;
     RECT  36.828 91.499 51.297 91.589 ;
     RECT  94.215 91.157 105.498 91.625 ;
     RECT  5.472 91.049 8.097 91.661 ;
     RECT  106.56 91.157 106.614 91.723 ;
     RECT  0.108 91.627 0.126 91.757 ;
     RECT  106.56 91.723 107.154 91.859 ;
     RECT  92.016 91.229 93.258 91.931 ;
     RECT  105.015 91.625 105.498 92.101 ;
     RECT  106.56 91.859 106.578 92.101 ;
     RECT  92.592 91.931 93.258 92.129 ;
     RECT  105.015 92.101 106.578 92.141 ;
     RECT  2.34 91.085 4.734 92.281 ;
     RECT  2.304 92.281 4.734 92.371 ;
     RECT  5.472 91.661 7.038 92.371 ;
     RECT  92.628 92.129 93.258 92.399 ;
     RECT  107.892 92.299 107.91 92.399 ;
     RECT  37.296 91.589 51.297 92.435 ;
     RECT  7.815 91.661 8.097 92.551 ;
     RECT  94.215 91.625 104.274 92.551 ;
     RECT  105.015 92.141 105.297 92.551 ;
     RECT  92.7 92.399 93.258 92.579 ;
     RECT  94.215 92.551 105.297 92.669 ;
     RECT  106.02 92.141 106.578 92.875 ;
     RECT  8.892 89.969 8.91 92.939 ;
     RECT  105.015 92.669 105.297 93.067 ;
     RECT  106.02 92.875 107.154 93.067 ;
     RECT  93.168 92.579 93.258 93.083 ;
     RECT  93.24 93.083 93.258 93.119 ;
     RECT  2.304 92.371 7.038 93.253 ;
     RECT  7.812 92.551 8.097 93.253 ;
     RECT  10.152 90.959 10.566 93.253 ;
     RECT  2.304 93.253 8.097 93.388 ;
     RECT  10.152 93.253 10.782 93.389 ;
     RECT  37.872 92.435 51.297 93.389 ;
     RECT  2.268 93.388 8.097 93.479 ;
     RECT  94.215 92.669 104.274 93.631 ;
     RECT  105.015 93.067 107.154 93.631 ;
     RECT  39.024 93.389 51.297 93.749 ;
     RECT  94.215 93.631 107.154 93.857 ;
     RECT  107.892 93.787 107.91 93.929 ;
     RECT  106.56 93.857 107.154 94.019 ;
     RECT  94.215 93.857 105.462 94.199 ;
     RECT  106.596 94.019 107.154 94.289 ;
     RECT  2.304 93.479 8.097 94.405 ;
     RECT  2.304 94.405 8.658 94.441 ;
     RECT  39.06 93.749 51.297 94.559 ;
     RECT  95.436 94.199 105.462 94.559 ;
     RECT  2.304 94.441 8.802 94.595 ;
     RECT  95.436 94.559 105.297 94.739 ;
     RECT  106.596 94.289 106.614 94.747 ;
     RECT  53.856 91.319 54.594 94.837 ;
     RECT  2.304 94.595 8.097 95.099 ;
     RECT  39.06 94.559 39.078 95.099 ;
     RECT  106.56 94.747 106.614 95.131 ;
     RECT  106.56 95.131 107.154 95.171 ;
     RECT  37.872 93.389 37.89 95.279 ;
     RECT  95.436 94.739 96.102 95.279 ;
     RECT  97.2 94.739 105.297 95.323 ;
     RECT  106.56 95.171 106.614 95.323 ;
     RECT  0.54 94.981 0.558 95.357 ;
     RECT  97.2 95.323 106.614 95.369 ;
     RECT  96.012 95.279 96.102 95.513 ;
     RECT  96.012 95.513 96.066 95.549 ;
     RECT  107.892 95.512 107.91 95.549 ;
     RECT  2.304 95.099 4.734 95.741 ;
     RECT  96.048 95.549 96.066 95.819 ;
     RECT  40.215 94.559 51.297 95.909 ;
     RECT  5.472 95.099 8.097 96.061 ;
     RECT  41.292 95.909 51.297 96.089 ;
     RECT  9.144 95.953 9.162 96.179 ;
     RECT  106.56 95.369 106.614 96.283 ;
     RECT  5.472 96.061 8.37 96.287 ;
     RECT  97.2 95.369 105.297 96.449 ;
     RECT  0.108 96.151 0.126 96.509 ;
     RECT  106.02 96.283 106.614 96.509 ;
     RECT  41.868 96.089 51.297 96.557 ;
     RECT  6.948 96.287 8.37 96.565 ;
     RECT  38.772 96.457 38.79 96.593 ;
     RECT  41.94 96.557 51.297 96.629 ;
     RECT  97.2 96.449 104.274 96.629 ;
     RECT  6.948 96.565 8.874 96.755 ;
     RECT  106.02 96.509 106.038 96.827 ;
     RECT  2.304 95.741 4.626 96.997 ;
     RECT  5.472 96.287 6.174 96.997 ;
     RECT  8.856 96.755 8.874 96.997 ;
     RECT  97.812 96.629 104.274 97.025 ;
     RECT  8.856 96.997 9.09 97.133 ;
     RECT  42.192 96.629 51.297 97.133 ;
     RECT  107.892 97.003 107.91 97.133 ;
     RECT  2.304 96.997 6.174 97.141 ;
     RECT  6.948 96.755 8.097 97.141 ;
     RECT  105.015 96.449 105.297 97.141 ;
     RECT  9.036 97.133 9.09 97.169 ;
     RECT  42.192 97.133 42.21 97.169 ;
     RECT  107.136 96.811 107.154 97.259 ;
     RECT  9.036 97.169 9.054 97.439 ;
     RECT  98.352 97.025 104.274 97.501 ;
     RECT  105.015 97.141 105.426 97.501 ;
     RECT  98.352 97.501 105.426 97.579 ;
     RECT  43.056 97.133 51.297 97.673 ;
     RECT  10.152 93.389 10.566 98.069 ;
     RECT  106.56 97.387 106.614 98.155 ;
     RECT  98.352 97.579 105.642 98.177 ;
     RECT  2.304 97.141 8.097 98.339 ;
     RECT  43.596 97.673 51.297 98.339 ;
     RECT  99.036 98.177 105.642 98.339 ;
     RECT  99.615 98.339 105.642 98.347 ;
     RECT  106.56 98.155 107.154 98.347 ;
     RECT  9.108 98.311 9.126 98.519 ;
     RECT  99.615 98.347 107.154 98.519 ;
     RECT  106.56 98.519 107.154 98.609 ;
     RECT  43.632 98.339 51.297 98.879 ;
     RECT  44.208 98.879 51.297 98.915 ;
     RECT  2.304 98.339 6.21 99.149 ;
     RECT  99.615 98.519 105.498 99.293 ;
     RECT  102.312 99.293 105.498 99.307 ;
     RECT  106.56 98.609 106.614 99.307 ;
     RECT  0.54 99.031 0.558 99.341 ;
     RECT  44.712 98.915 51.297 99.491 ;
     RECT  9.108 99.391 9.126 99.599 ;
     RECT  10.548 98.069 10.566 99.797 ;
     RECT  7.092 98.339 8.097 99.841 ;
     RECT  2.415 99.149 6.21 99.883 ;
     RECT  45.288 99.491 51.297 99.959 ;
     RECT  99.615 99.293 101.466 100.111 ;
     RECT  102.312 99.307 106.614 100.111 ;
     RECT  7.092 99.841 8.658 100.139 ;
     RECT  99.615 100.111 106.614 100.229 ;
     RECT  102.348 100.229 106.614 100.253 ;
     RECT  7.092 100.139 8.154 100.301 ;
     RECT  2.304 99.883 6.21 100.381 ;
     RECT  7.092 100.301 8.097 100.381 ;
     RECT  102.348 100.253 106.002 100.841 ;
     RECT  2.304 100.381 8.097 100.877 ;
     RECT  5.436 100.877 8.097 101.035 ;
     RECT  5.436 101.035 8.586 101.039 ;
     RECT  2.304 100.877 4.626 101.075 ;
     RECT  107.136 100.411 107.154 101.179 ;
     RECT  45.615 99.959 51.297 101.219 ;
     RECT  6.66 101.039 8.586 101.417 ;
     RECT  6.66 101.417 7.038 101.459 ;
     RECT  7.815 101.417 8.586 101.587 ;
     RECT  106.56 101.179 107.154 101.597 ;
     RECT  47.016 101.219 51.297 101.615 ;
     RECT  7.815 101.587 8.658 101.687 ;
     RECT  2.304 101.075 2.826 101.947 ;
     RECT  3.636 101.075 4.626 101.947 ;
     RECT  5.436 101.039 5.886 102.043 ;
     RECT  47.556 101.615 51.297 102.119 ;
     RECT  7.815 101.687 8.154 102.155 ;
     RECT  5.436 102.043 6.066 102.235 ;
     RECT  99.615 100.229 101.43 102.271 ;
     RECT  102.348 100.841 105.297 102.271 ;
     RECT  6.912 101.459 7.038 102.299 ;
     RECT  106.02 102.139 106.038 102.299 ;
     RECT  99.615 102.271 105.297 102.331 ;
     RECT  2.304 101.947 4.626 102.361 ;
     RECT  5.364 102.235 6.066 102.361 ;
     RECT  6.912 102.299 6.93 102.361 ;
     RECT  47.628 102.119 51.297 102.389 ;
     RECT  99.615 102.331 105.462 102.389 ;
     RECT  9.072 102.271 9.09 102.569 ;
     RECT  107.1 101.597 107.154 102.569 ;
     RECT  105.015 102.389 105.462 102.767 ;
     RECT  48.132 102.389 51.297 102.929 ;
     RECT  102.24 102.389 104.202 102.929 ;
     RECT  99.615 102.389 101.43 103.073 ;
     RECT  106.596 102.703 106.614 103.081 ;
     RECT  106.56 103.081 106.614 103.133 ;
     RECT  102.348 102.929 104.202 103.199 ;
     RECT  2.304 102.361 6.93 103.351 ;
     RECT  2.304 103.351 7.074 103.469 ;
     RECT  48.708 102.929 51.297 103.649 ;
     RECT  105.015 102.767 105.39 103.711 ;
     RECT  5.112 103.469 7.038 103.739 ;
     RECT  100.728 103.073 101.43 103.747 ;
     RECT  102.348 103.199 104.166 103.747 ;
     RECT  100.728 103.747 104.166 103.805 ;
     RECT  105.015 103.711 105.426 103.819 ;
     RECT  5.4 103.739 7.038 103.921 ;
     RECT  105.015 103.819 106.038 104.117 ;
     RECT  7.815 102.155 8.097 104.161 ;
     RECT  103.176 103.805 104.166 104.161 ;
     RECT  105.015 104.117 105.498 104.161 ;
     RECT  2.304 103.469 4.266 104.188 ;
     RECT  49.284 103.649 51.297 104.189 ;
     RECT  6.336 103.921 7.038 104.203 ;
     RECT  7.815 104.161 8.154 104.203 ;
     RECT  6.336 104.203 8.154 104.237 ;
     RECT  2.268 104.188 4.266 104.279 ;
     RECT  6.336 104.237 6.354 104.279 ;
     RECT  100.728 103.805 102.366 104.279 ;
     RECT  103.176 104.161 105.498 104.279 ;
     RECT  107.136 103.291 107.154 104.287 ;
     RECT  100.728 104.279 102.15 104.315 ;
     RECT  8.928 104.125 8.946 104.323 ;
     RECT  49.284 104.189 49.302 104.351 ;
     RECT  107.136 104.287 107.19 104.395 ;
     RECT  53.856 94.837 54.63 104.431 ;
     RECT  5.4 103.921 5.562 104.521 ;
     RECT  53.856 104.431 54.918 104.539 ;
     RECT  8.928 104.323 9.126 104.549 ;
     RECT  100.728 104.315 102.042 104.549 ;
     RECT  53.424 104.539 54.918 104.557 ;
     RECT  53.424 104.557 55.098 104.701 ;
     RECT  2.304 104.279 4.266 104.813 ;
     RECT  2.376 104.813 4.266 104.855 ;
     RECT  53.424 104.701 55.314 104.855 ;
     RECT  5.364 104.521 5.562 104.875 ;
     RECT  53.424 104.855 55.098 104.891 ;
     RECT  2.415 104.855 4.266 104.899 ;
     RECT  5.364 104.875 6.03 104.971 ;
     RECT  7.704 104.237 8.154 104.971 ;
     RECT  103.176 104.279 105.297 104.971 ;
     RECT  106.56 104.395 107.19 105.061 ;
     RECT  7.704 104.971 8.658 105.089 ;
     RECT  50.436 104.189 51.297 105.089 ;
     RECT  53.604 104.891 55.098 105.089 ;
     RECT  7.704 105.089 8.097 105.125 ;
     RECT  103.104 104.971 105.297 105.125 ;
     RECT  2.415 104.899 4.374 105.241 ;
     RECT  10.8 105.061 10.818 105.269 ;
     RECT  2.415 105.241 4.446 105.359 ;
     RECT  50.508 105.089 51.297 105.359 ;
     RECT  100.728 104.549 101.43 105.359 ;
     RECT  103.104 105.125 104.166 105.359 ;
     RECT  3.6 105.359 4.446 105.395 ;
     RECT  53.604 105.089 54.846 105.395 ;
     RECT  104.904 105.125 105.297 105.395 ;
     RECT  3.636 105.395 4.446 105.403 ;
     RECT  5.22 104.971 6.03 105.403 ;
     RECT  103.104 105.359 103.734 105.403 ;
     RECT  102.996 105.403 103.734 105.431 ;
     RECT  106.524 105.061 107.19 105.431 ;
     RECT  102.996 105.431 103.698 105.44 ;
     RECT  53.856 105.395 54.846 105.485 ;
     RECT  100.728 105.359 100.998 105.485 ;
     RECT  3.636 105.403 6.03 105.511 ;
     RECT  6.768 105.205 6.786 105.511 ;
     RECT  107.172 105.431 107.19 105.581 ;
     RECT  2.415 105.359 2.697 105.587 ;
     RECT  7.815 105.125 8.097 105.587 ;
     RECT  13.215 78.539 13.497 105.587 ;
     RECT  18.615 73.913 18.897 105.587 ;
     RECT  24.015 79.619 24.297 105.587 ;
     RECT  29.415 84.749 29.697 105.587 ;
     RECT  34.815 90.347 35.097 105.587 ;
     RECT  40.215 95.909 40.497 105.587 ;
     RECT  45.615 101.219 45.897 105.587 ;
     RECT  51.015 105.359 51.297 105.587 ;
     RECT  56.415 51.917 56.697 105.587 ;
     RECT  61.815 62.339 62.097 105.587 ;
     RECT  67.215 67.397 67.497 105.587 ;
     RECT  72.615 72.869 72.897 105.587 ;
     RECT  78.015 78.629 78.297 105.587 ;
     RECT  83.415 83.057 83.697 105.587 ;
     RECT  88.815 89.069 89.097 105.587 ;
     RECT  94.215 94.199 94.497 105.587 ;
     RECT  99.615 103.073 99.897 105.587 ;
     RECT  105.015 105.395 105.297 105.587 ;
     RECT  54.18 105.485 54.846 105.629 ;
     RECT  54.18 105.629 54.774 105.665 ;
     RECT  102.132 105.451 102.15 105.665 ;
     RECT  102.996 105.44 103.014 105.665 ;
     RECT  3.636 105.511 6.786 105.701 ;
     RECT  54.324 105.665 54.45 105.701 ;
     RECT  2.415 105.587 2.505 105.739 ;
     RECT  2.304 105.739 2.505 105.809 ;
     RECT  100.728 105.485 100.746 105.809 ;
     RECT  105.948 105.739 105.966 105.809 ;
     RECT  2.415 105.809 2.505 105.857 ;
     RECT  7.815 105.587 7.905 105.857 ;
     RECT  13.215 105.587 13.305 105.857 ;
     RECT  18.615 105.587 18.705 105.857 ;
     RECT  24.015 105.587 24.105 105.857 ;
     RECT  29.415 105.587 29.505 105.857 ;
     RECT  34.815 105.587 34.905 105.857 ;
     RECT  40.215 105.587 40.305 105.857 ;
     RECT  45.615 105.587 45.705 105.857 ;
     RECT  51.015 105.587 51.105 105.857 ;
     RECT  56.415 105.587 56.505 105.857 ;
     RECT  61.815 105.587 61.905 105.857 ;
     RECT  67.215 105.587 67.305 105.857 ;
     RECT  72.615 105.587 72.705 105.857 ;
     RECT  78.015 105.587 78.105 105.857 ;
     RECT  83.415 105.587 83.505 105.857 ;
     RECT  88.815 105.587 88.905 105.857 ;
     RECT  94.215 105.587 94.305 105.857 ;
     RECT  99.615 105.587 99.705 105.857 ;
     RECT  105.015 105.587 105.105 105.857 ;
     RECT  6.12 105.701 6.786 105.871 ;
     RECT  4.284 105.701 5.022 105.899 ;
     RECT  6.12 105.871 6.858 105.899 ;
     RECT  28.224 83.939 28.242 105.899 ;
     RECT  5.004 105.899 5.022 106.007 ;
     RECT  6.84 105.899 6.858 106.007 ;
     RECT  54.324 105.701 54.342 107.165 ;
    LAYER M4 ;
     RECT  0.06 2.256 2.408 105.768 ;
     RECT  2.293 0.192 2.437 0.216 ;
     RECT  2.408 2.148 2.512 105.852 ;
     RECT  2.437 0.144 2.675 0.216 ;
     RECT  2.512 2.256 2.704 105.582 ;
     RECT  2.704 53.856 2.729 56.568 ;
     RECT  2.704 76.032 2.729 80.376 ;
     RECT  2.704 2.256 2.765 16.824 ;
     RECT  2.704 44.976 2.765 47.112 ;
     RECT  2.704 57.648 2.765 62.328 ;
     RECT  2.704 64.368 2.765 71.832 ;
     RECT  2.704 81.696 2.765 81.912 ;
     RECT  2.704 92.688 2.765 94.728 ;
     RECT  2.704 103.296 2.765 105.384 ;
     RECT  2.704 17.952 2.801 19.272 ;
     RECT  2.704 39.312 2.801 43.896 ;
     RECT  2.765 45.552 2.801 47.112 ;
     RECT  2.729 55.68 2.801 56.568 ;
     RECT  2.765 81.696 2.801 81.72 ;
     RECT  2.704 95.712 2.801 102.216 ;
     RECT  2.675 0.144 2.819 0.168 ;
     RECT  2.765 2.256 2.837 14.232 ;
     RECT  2.765 15.312 2.837 16.824 ;
     RECT  2.801 18.144 2.837 19.272 ;
     RECT  2.704 21.936 2.837 24.408 ;
     RECT  2.704 30 2.837 30.456 ;
     RECT  2.704 33.648 2.837 38.184 ;
     RECT  2.801 43.296 2.837 43.32 ;
     RECT  2.704 48.384 2.837 52.728 ;
     RECT  2.765 64.368 2.837 66.024 ;
     RECT  2.765 68.16 2.837 71.832 ;
     RECT  2.729 76.416 2.837 79.272 ;
     RECT  2.704 83.04 2.837 85.512 ;
     RECT  2.704 87.936 2.837 91.656 ;
     RECT  2.765 93.264 2.837 94.728 ;
     RECT  2.801 96.288 2.837 102.216 ;
     RECT  2.837 89.472 2.945 91.656 ;
     RECT  2.837 15.312 2.981 16.584 ;
     RECT  2.945 89.472 2.981 91.176 ;
     RECT  2.837 96.816 2.981 98.952 ;
     RECT  2.981 15.312 3.089 15.336 ;
     RECT  2.837 64.368 3.161 65.064 ;
     RECT  2.765 67.104 3.161 67.128 ;
     RECT  2.981 96.816 3.161 98.616 ;
     RECT  2.837 2.256 3.269 13.032 ;
     RECT  2.704 20.4 3.305 20.472 ;
     RECT  2.837 101.952 3.377 102.216 ;
     RECT  2.801 39.312 3.413 41.784 ;
     RECT  3.377 102.192 3.449 102.216 ;
     RECT  2.765 103.488 3.484 105.384 ;
     RECT  3.161 64.992 3.629 65.064 ;
     RECT  3.484 103.872 3.701 105.384 ;
     RECT  2.837 68.16 3.877 70.344 ;
     RECT  2.981 89.472 3.877 90.936 ;
     RECT  2.837 14.208 3.985 14.232 ;
     RECT  2.837 49.344 3.989 52.728 ;
     RECT  3.697 82.704 4.021 82.728 ;
     RECT  3.413 39.792 4.025 41.784 ;
     RECT  3.989 49.344 4.025 52.488 ;
     RECT  3.629 64.992 4.025 65.016 ;
     RECT  2.837 83.76 4.025 85.512 ;
     RECT  2.837 100.08 4.025 100.824 ;
     RECT  3.269 2.256 4.133 10.056 ;
     RECT  2.729 53.856 4.133 54.648 ;
     RECT  3.877 68.16 4.133 70.488 ;
     RECT  2.837 93.792 4.133 94.728 ;
     RECT  2.837 34.224 4.165 34.776 ;
     RECT  2.837 36.576 4.169 38.184 ;
     RECT  4.025 84.912 4.169 85.512 ;
     RECT  2.837 76.416 4.201 77.928 ;
     RECT  2.765 62.304 4.237 62.328 ;
     RECT  4.201 76.416 4.237 78.216 ;
     RECT  4.133 70.368 4.273 70.488 ;
     RECT  4.025 49.344 4.277 51.096 ;
     RECT  3.701 103.872 4.277 104.424 ;
     RECT  3.269 11.328 4.309 13.032 ;
     RECT  3.985 14.208 4.309 14.76 ;
     RECT  4.133 93.792 4.309 94.008 ;
     RECT  4.165 96.24 4.309 96.264 ;
     RECT  3.305 20.448 4.316 20.472 ;
     RECT  2.801 46.176 4.316 47.112 ;
     RECT  4.316 20.448 4.345 20.856 ;
     RECT  2.837 22.848 4.345 24.408 ;
     RECT  2.837 30 4.345 30.024 ;
     RECT  4.165 34.224 4.345 34.824 ;
     RECT  4.273 64.944 4.345 64.968 ;
     RECT  3.877 89.376 4.345 90.936 ;
     RECT  4.025 100.08 4.345 100.392 ;
     RECT  4.316 46.176 4.349 47.352 ;
     RECT  4.277 50.592 4.349 51.096 ;
     RECT  4.165 86.64 4.349 86.664 ;
     RECT  4.309 11.328 4.355 14.76 ;
     RECT  4.309 93.6 4.355 94.008 ;
     RECT  2.729 80.352 4.357 80.376 ;
     RECT  4.355 14.736 4.385 14.76 ;
     RECT  4.169 36.576 4.385 36.6 ;
     RECT  4.355 11.328 4.396 13.368 ;
     RECT  4.355 93.6 4.396 93.624 ;
     RECT  4.309 95.088 4.396 96.264 ;
     RECT  4.345 20.448 4.403 21.672 ;
     RECT  4.345 30 4.403 30.84 ;
     RECT  4.025 39.792 4.403 41.592 ;
     RECT  4.349 50.688 4.403 51.096 ;
     RECT  4.357 80.352 4.403 81.048 ;
     RECT  4.237 76.416 4.417 78.456 ;
     RECT  2.837 87.936 4.421 87.96 ;
     RECT  4.345 19.344 4.429 19.368 ;
     RECT  4.345 28.464 4.429 28.488 ;
     RECT  4.403 80.784 4.444 81.048 ;
     RECT  4.345 89.376 4.444 91.368 ;
     RECT  4.349 47.184 4.453 47.352 ;
     RECT  4.396 11.328 4.457 13.032 ;
     RECT  2.704 25.824 4.457 27.432 ;
     RECT  4.345 64.896 4.457 64.968 ;
     RECT  4.444 89.376 4.457 90.072 ;
     RECT  4.349 46.176 4.489 46.2 ;
     RECT  4.457 11.328 4.493 12.552 ;
     RECT  4.345 22.848 4.499 24.552 ;
     RECT  4.133 53.856 4.525 54.36 ;
     RECT  4.489 45.552 4.529 46.2 ;
     RECT  4.499 22.848 4.54 24.12 ;
     RECT  4.237 61.536 4.561 62.328 ;
     RECT  4.457 64.896 4.561 64.92 ;
     RECT  4.493 11.328 4.565 11.544 ;
     RECT  4.169 37.584 4.565 38.184 ;
     RECT  4.403 40.272 4.565 41.592 ;
     RECT  4.396 95.184 4.565 96.264 ;
     RECT  4.565 11.328 4.597 11.4 ;
     RECT  4.529 45.552 4.597 45.576 ;
     RECT  4.133 68.16 4.709 68.952 ;
     RECT  4.345 34.224 4.741 35.304 ;
     RECT  4.453 47.184 4.741 48.12 ;
     RECT  4.277 49.344 4.741 49.464 ;
     RECT  4.561 61.536 4.751 63.192 ;
     RECT  4.561 64.56 4.751 64.92 ;
     RECT  4.565 40.8 4.781 41.592 ;
     RECT  4.025 52.128 4.781 52.488 ;
     RECT  4.237 66.72 4.789 66.744 ;
     RECT  4.709 68.16 4.789 68.424 ;
     RECT  4.751 61.536 4.817 64.92 ;
     RECT  2.704 74.112 4.885 74.136 ;
     RECT  4.489 88.032 4.885 88.056 ;
     RECT  4.273 70.368 4.889 70.584 ;
     RECT  4.789 66.72 4.897 68.424 ;
     RECT  4.345 43.344 4.921 43.368 ;
     RECT  4.457 90.048 4.925 90.072 ;
     RECT  4.025 83.76 4.931 83.784 ;
     RECT  4.403 21.648 4.957 21.672 ;
     RECT  4.54 22.848 4.957 23.064 ;
     RECT  4.417 76.32 4.957 78.456 ;
     RECT  2.765 57.648 4.988 59.496 ;
     RECT  2.837 71.808 4.988 71.832 ;
     RECT  4.897 66.72 4.993 67.8 ;
     RECT  4.817 61.632 5.033 61.656 ;
     RECT  4.021 82.128 5.033 82.728 ;
     RECT  4.169 84.912 5.065 84.984 ;
     RECT  4.981 86.16 5.068 86.184 ;
     RECT  4.921 42.816 5.069 43.368 ;
     RECT  4.988 57.648 5.075 60.216 ;
     RECT  4.817 63.168 5.075 64.92 ;
     RECT  4.993 66.48 5.075 67.8 ;
     RECT  4.988 71.472 5.075 71.832 ;
     RECT  4.345 17.664 5.101 17.688 ;
     RECT  4.885 18.72 5.101 18.744 ;
     RECT  5.065 84.384 5.105 84.984 ;
     RECT  4.885 74.112 5.125 74.664 ;
     RECT  4.957 76.32 5.125 78.6 ;
     RECT  5.101 17.664 5.132 18.744 ;
     RECT  2.981 16.56 5.137 16.584 ;
     RECT  5.132 17.616 5.137 18.744 ;
     RECT  4.525 53.52 5.137 54.36 ;
     RECT  2.801 55.68 5.137 56.472 ;
     RECT  4.597 10.272 5.141 11.4 ;
     RECT  5.125 74.112 5.141 78.6 ;
     RECT  5.033 82.128 5.141 82.152 ;
     RECT  5.141 74.448 5.171 78.6 ;
     RECT  5.141 10.272 5.209 11.256 ;
     RECT  5.137 16.56 5.213 18.744 ;
     RECT  5.209 10.224 5.249 11.256 ;
     RECT  5.213 17.088 5.267 18.744 ;
     RECT  4.403 30.816 5.281 30.84 ;
     RECT  4.417 32.448 5.281 32.472 ;
     RECT  5.075 57.648 5.281 59.736 ;
     RECT  5.075 64.56 5.285 64.92 ;
     RECT  4.597 45.456 5.317 45.576 ;
     RECT  4.345 99.696 5.353 100.392 ;
     RECT  4.277 104.4 5.353 104.424 ;
     RECT  5.171 75.504 5.357 78.6 ;
     RECT  4.885 88.032 5.357 88.584 ;
     RECT  4.403 50.736 5.389 50.76 ;
     RECT  4.957 21.648 5.393 23.064 ;
     RECT  4.565 37.584 5.393 37.656 ;
     RECT  5.137 53.52 5.393 56.472 ;
     RECT  5.357 75.504 5.393 78.216 ;
     RECT  3.161 97.296 5.393 98.616 ;
     RECT  5.393 21.648 5.411 22.2 ;
     RECT  4.457 25.92 5.425 26.232 ;
     RECT  4.781 52.128 5.425 52.152 ;
     RECT  5.353 104.4 5.429 104.904 ;
     RECT  5.389 50.736 5.461 50.808 ;
     RECT  5.411 21.648 5.465 22.152 ;
     RECT  4.781 40.944 5.465 41.592 ;
     RECT  5.317 45.024 5.465 45.576 ;
     RECT  5.389 86.64 5.501 86.664 ;
     RECT  5.393 75.504 5.537 78.12 ;
     RECT  5.353 99.6 5.537 100.392 ;
     RECT  4.837 20.304 5.569 20.328 ;
     RECT  5.267 17.664 5.573 18.744 ;
     RECT  4.741 33.648 5.573 35.304 ;
     RECT  5.281 57.504 5.573 59.736 ;
     RECT  5.101 70.08 5.573 70.104 ;
     RECT  5.393 98.592 5.573 98.616 ;
     RECT  5.425 51.888 5.603 52.152 ;
     RECT  4.133 2.256 5.605 9.144 ;
     RECT  5.249 10.224 5.605 11.16 ;
     RECT  5.533 28.56 5.605 28.584 ;
     RECT  5.393 37.632 5.605 37.656 ;
     RECT  5.137 38.64 5.605 38.664 ;
     RECT  4.54 24.096 5.609 24.12 ;
     RECT  5.281 30.816 5.609 32.472 ;
     RECT  5.069 43.344 5.609 43.368 ;
     RECT  4.444 80.784 5.641 80.808 ;
     RECT  5.609 30.816 5.645 31.56 ;
     RECT  5.465 45.552 5.645 45.576 ;
     RECT  4.741 47.184 5.645 49.464 ;
     RECT  5.461 50.688 5.645 50.808 ;
     RECT  4.493 12.528 5.677 12.552 ;
     RECT  5.537 99.6 5.677 99.624 ;
     RECT  5.569 19.92 5.699 20.328 ;
     RECT  5.465 21.648 5.699 22.104 ;
     RECT  5.425 25.584 5.701 26.232 ;
     RECT  5.393 55.824 5.717 56.472 ;
     RECT  5.717 55.92 5.753 56.472 ;
     RECT  5.075 63.168 5.753 63.192 ;
     RECT  5.605 37.632 5.756 38.664 ;
     RECT  5.645 30.816 5.759 31.224 ;
     RECT  5.573 33.648 5.785 34.056 ;
     RECT  5.573 35.136 5.785 35.304 ;
     RECT  5.573 17.664 5.789 18.216 ;
     RECT  5.465 40.944 5.821 40.968 ;
     RECT  5.699 21.936 5.825 22.104 ;
     RECT  5.701 25.056 5.825 26.232 ;
     RECT  5.756 37.632 5.825 39.048 ;
     RECT  5.821 40.032 5.825 40.968 ;
     RECT  5.393 97.296 5.825 97.32 ;
     RECT  5.785 35.136 5.843 35.736 ;
     RECT  5.825 38.208 5.843 39.048 ;
     RECT  5.285 64.896 5.845 64.92 ;
     RECT  5.075 66.48 5.845 66.744 ;
     RECT  4.444 91.344 5.857 91.368 ;
     RECT  4.453 102.384 5.857 102.408 ;
     RECT  5.573 57.984 5.891 59.736 ;
     RECT  5.845 64.896 5.891 66.744 ;
     RECT  5.677 99.168 5.897 99.624 ;
     RECT  5.891 59.184 5.932 59.736 ;
     RECT  5.891 65.136 5.932 66.744 ;
     RECT  5.897 99.168 5.933 99.192 ;
     RECT  5.797 43.728 5.939 43.752 ;
     RECT  5.857 91.344 6.005 91.848 ;
     RECT  5.891 57.984 6.041 58.008 ;
     RECT  5.932 66.24 6.041 66.744 ;
     RECT  5.605 28.56 6.077 28.824 ;
     RECT  5.785 33.36 6.077 34.056 ;
     RECT  6.085 90.672 6.145 90.696 ;
     RECT  5.429 104.88 6.179 104.904 ;
     RECT  5.393 53.52 6.181 54.072 ;
     RECT  6.145 90.624 6.181 90.696 ;
     RECT  5.171 74.448 6.221 74.472 ;
     RECT  5.105 84.384 6.221 84.408 ;
     RECT  5.357 88.464 6.227 88.584 ;
     RECT  6.181 90.48 6.227 90.696 ;
     RECT  4.885 79.632 6.229 79.656 ;
     RECT  5.641 80.784 6.229 80.904 ;
     RECT  5.759 30 6.275 31.224 ;
     RECT  4.565 95.184 6.293 95.736 ;
     RECT  5.825 25.92 6.321 26.232 ;
     RECT  6.229 79.632 6.329 80.904 ;
     RECT  5.605 2.256 6.353 11.16 ;
     RECT  6.353 2.256 6.469 11.448 ;
     RECT  5.677 12.528 6.469 13.032 ;
     RECT  6.329 80.88 6.469 80.904 ;
     RECT  6.227 90.48 6.541 90.648 ;
     RECT  5.537 76.368 6.581 78.12 ;
     RECT  5.857 101.616 6.581 102.408 ;
     RECT  6.321 26.208 6.613 26.232 ;
     RECT  6.077 28.8 6.613 28.824 ;
     RECT  5.843 38.208 6.617 38.76 ;
     RECT  6.581 101.616 6.649 102.072 ;
     RECT  6.275 30.816 6.653 31.224 ;
     RECT  5.645 47.184 6.653 48.984 ;
     RECT  6.613 28.8 6.689 29.208 ;
     RECT  5.713 73.344 6.689 73.368 ;
     RECT  6.613 26.208 6.725 26.808 ;
     RECT  6.617 38.208 6.725 38.664 ;
     RECT  5.075 71.808 6.725 71.832 ;
     RECT  6.716 62.592 6.757 62.616 ;
     RECT  6.469 2.256 6.761 13.032 ;
     RECT  6.689 29.04 6.761 29.208 ;
     RECT  6.577 32.304 6.761 32.328 ;
     RECT  5.753 55.92 6.792 56.28 ;
     RECT  6.077 33.36 6.797 33.912 ;
     RECT  6.433 86.208 6.805 86.232 ;
     RECT  5.075 67.728 6.829 67.8 ;
     RECT  5.461 103.728 6.829 103.896 ;
     RECT  6.725 38.208 6.853 38.28 ;
     RECT  6.792 55.92 6.853 56.472 ;
     RECT  5.605 14.64 6.865 14.664 ;
     RECT  5.221 15.696 6.865 16.008 ;
     RECT  6.653 47.184 6.865 48.168 ;
     RECT  5.932 65.136 6.937 65.16 ;
     RECT  6.293 95.712 6.937 95.736 ;
     RECT  6.829 103.632 7.009 103.896 ;
     RECT  6.581 76.368 7.045 77.064 ;
     RECT  5.699 20.304 7.117 20.328 ;
     RECT  6.181 53.328 7.117 54.072 ;
     RECT  6.541 89.952 7.117 90.648 ;
     RECT  5.605 42.144 7.261 42.168 ;
     RECT  6.217 50.832 7.333 50.856 ;
     RECT  5.603 52.128 7.333 52.152 ;
     RECT  7.621 0.096 7.669 0.12 ;
     RECT  6.761 11.232 7.669 13.032 ;
     RECT  6.937 64.32 7.669 65.16 ;
     RECT  6.649 101.424 7.765 102.072 ;
     RECT  6.761 2.256 7.808 10.248 ;
     RECT  7.669 11.232 7.808 13.608 ;
     RECT  6.865 14.64 7.808 16.008 ;
     RECT  6.86 17.28 7.808 17.304 ;
     RECT  7.117 19.776 7.808 20.328 ;
     RECT  5.825 22.08 7.808 22.104 ;
     RECT  6.865 23.952 7.808 23.976 ;
     RECT  6.725 26.208 7.808 26.232 ;
     RECT  6.761 29.04 7.808 29.064 ;
     RECT  6.653 31.2 7.808 31.224 ;
     RECT  6.797 33.36 7.808 33.576 ;
     RECT  5.843 35.28 7.808 35.736 ;
     RECT  6.853 37.584 7.808 38.28 ;
     RECT  5.825 40.032 7.808 40.056 ;
     RECT  7.261 42.144 7.808 42.648 ;
     RECT  6.001 44.064 7.808 44.088 ;
     RECT  6.865 47.136 7.808 48.168 ;
     RECT  7.333 50.832 7.808 52.152 ;
     RECT  7.117 53.328 7.808 54.216 ;
     RECT  6.853 55.92 7.808 57.048 ;
     RECT  5.932 59.184 7.808 59.208 ;
     RECT  6.757 62.592 7.808 62.712 ;
     RECT  7.669 63.792 7.808 65.16 ;
     RECT  6.041 66.24 7.808 66.264 ;
     RECT  6.829 67.296 7.808 67.8 ;
     RECT  5.965 69.84 7.808 69.864 ;
     RECT  6.865 71.184 7.808 71.208 ;
     RECT  7.045 75.792 7.808 77.064 ;
     RECT  6.581 78.096 7.808 78.12 ;
     RECT  6.329 79.632 7.808 79.656 ;
     RECT  6.469 80.88 7.808 81.624 ;
     RECT  6.073 83.232 7.808 83.256 ;
     RECT  6.805 85.392 7.808 86.232 ;
     RECT  7.429 88.32 7.808 88.344 ;
     RECT  7.117 89.376 7.808 90.648 ;
     RECT  6.005 91.824 7.808 91.848 ;
     RECT  6.577 93.312 7.808 93.432 ;
     RECT  6.937 95.712 7.808 96.312 ;
     RECT  7.765 101.04 7.808 102.072 ;
     RECT  7.009 103.632 7.808 104.232 ;
     RECT  7.808 2.148 7.912 105.852 ;
     RECT  7.669 0.096 7.955 0.216 ;
     RECT  7.912 2.256 8.104 105.582 ;
     RECT  8.104 11.232 8.165 13.704 ;
     RECT  8.104 56.208 8.165 57.048 ;
     RECT  8.104 85.392 8.165 86.232 ;
     RECT  8.104 2.256 8.201 9.288 ;
     RECT  8.104 23.952 8.201 23.976 ;
     RECT  8.104 44.064 8.201 44.088 ;
     RECT  8.104 47.136 8.201 48.168 ;
     RECT  8.104 15.984 8.237 16.008 ;
     RECT  8.104 19.776 8.237 20.328 ;
     RECT  8.104 40.032 8.237 40.056 ;
     RECT  8.104 96.288 8.237 96.312 ;
     RECT  7.955 0.096 8.243 0.12 ;
     RECT  8.104 29.712 8.243 29.736 ;
     RECT  8.104 49.536 8.243 49.56 ;
     RECT  8.104 53.328 8.243 54.552 ;
     RECT  8.104 71.184 8.243 71.832 ;
     RECT  8.104 75.792 8.243 77.976 ;
     RECT  8.104 100.272 8.243 102.12 ;
     RECT  8.104 28.464 8.281 28.488 ;
     RECT  8.104 74.064 8.309 74.088 ;
     RECT  8.243 76.368 8.381 77.976 ;
     RECT  8.165 85.392 8.381 85.416 ;
     RECT  8.104 63.792 8.483 64.344 ;
     RECT  8.104 67.296 8.483 67.32 ;
     RECT  8.104 79.248 8.483 79.272 ;
     RECT  8.104 65.808 8.524 65.832 ;
     RECT  8.381 77.952 8.524 77.976 ;
     RECT  8.165 11.904 8.533 13.704 ;
     RECT  8.243 101.04 8.579 102.12 ;
     RECT  8.579 101.04 8.597 101.592 ;
     RECT  8.533 11.904 9.137 12.888 ;
     RECT  9.137 11.904 9.299 11.976 ;
     RECT  9.421 11.424 9.721 11.448 ;
     RECT  9.745 14.832 10.069 14.856 ;
     RECT  10.069 14.832 10.405 15.432 ;
     RECT  8.237 20.304 10.825 20.328 ;
     RECT  10.825 20.304 10.937 20.952 ;
     RECT  10.405 15.408 11.016 15.432 ;
     RECT  11.016 15.408 11.171 15.48 ;
     RECT  11.171 15.408 13.068 15.432 ;
     RECT  8.201 2.256 13.208 8.52 ;
     RECT  13.068 15.408 13.208 15.48 ;
     RECT  10.937 20.304 13.208 20.328 ;
     RECT  8.104 35.28 13.208 35.304 ;
     RECT  8.201 47.184 13.208 48.168 ;
     RECT  8.104 50.832 13.208 51.48 ;
     RECT  8.243 53.328 13.208 53.352 ;
     RECT  8.165 56.208 13.208 56.232 ;
     RECT  8.381 76.752 13.208 76.776 ;
     RECT  13.093 0.096 13.235 0.12 ;
     RECT  13.208 2.148 13.312 105.852 ;
     RECT  13.312 2.256 13.504 105.582 ;
     RECT  13.504 15.408 13.619 15.576 ;
     RECT  13.381 0.144 13.667 0.168 ;
     RECT  13.619 15.408 13.667 15.48 ;
     RECT  13.504 20.304 13.673 20.328 ;
     RECT  13.667 15.408 14.401 15.432 ;
     RECT  17.153 22.224 17.449 22.248 ;
     RECT  13.504 18.816 17.633 18.84 ;
     RECT  17.449 22.128 17.737 22.248 ;
     RECT  17.737 22.128 18.097 22.824 ;
     RECT  18.421 0.096 18.469 0.12 ;
     RECT  13.504 2.256 18.608 8.52 ;
     RECT  18.097 22.128 18.608 23.4 ;
     RECT  13.504 35.28 18.608 35.304 ;
     RECT  13.504 47.184 18.608 48.168 ;
     RECT  13.504 50.832 18.608 51.48 ;
     RECT  13.504 53.328 18.608 53.352 ;
     RECT  13.504 56.208 18.608 56.232 ;
     RECT  13.504 76.752 18.608 76.776 ;
     RECT  18.608 2.148 18.712 105.852 ;
     RECT  18.469 0.096 18.755 0.216 ;
     RECT  18.712 2.256 18.904 105.582 ;
     RECT  18.755 0.096 19.043 0.12 ;
     RECT  18.904 23.376 19.043 24.12 ;
     RECT  19.043 23.376 19.333 24.024 ;
     RECT  19.333 23.952 19.667 24.024 ;
     RECT  21.409 26.544 21.517 26.568 ;
     RECT  19.667 23.952 21.971 23.976 ;
     RECT  21.517 26.544 22.133 26.664 ;
     RECT  22.133 26.64 22.169 26.664 ;
     RECT  22.117 24.432 23.221 24.504 ;
     RECT  18.904 2.256 24.008 8.52 ;
     RECT  23.221 23.952 24.008 24.504 ;
     RECT  23.389 27.936 24.008 27.96 ;
     RECT  18.904 35.28 24.008 35.304 ;
     RECT  18.904 47.184 24.008 48.168 ;
     RECT  18.904 50.832 24.008 51.48 ;
     RECT  18.904 53.328 24.008 53.352 ;
     RECT  18.904 56.208 24.008 56.232 ;
     RECT  18.904 76.752 24.008 76.776 ;
     RECT  24.008 2.148 24.112 105.852 ;
     RECT  23.989 0.144 24.181 0.168 ;
     RECT  24.112 2.256 24.304 105.582 ;
     RECT  24.304 27.936 24.445 28.632 ;
     RECT  24.181 0.144 24.467 0.264 ;
     RECT  24.467 0.24 24.515 0.264 ;
     RECT  24.445 27.936 24.515 28.584 ;
     RECT  24.515 28.512 25.379 28.584 ;
     RECT  25.379 28.512 25.957 28.536 ;
     RECT  25.717 30.24 26.341 30.264 ;
     RECT  26.341 30.24 26.881 30.84 ;
     RECT  26.881 30.24 27.101 31.272 ;
     RECT  27.101 30.816 27.169 31.272 ;
     RECT  27.169 30.816 27.209 31.368 ;
     RECT  27.209 31.248 27.313 31.368 ;
     RECT  27.313 31.248 27.389 31.752 ;
     RECT  27.389 31.344 27.497 31.752 ;
     RECT  27.497 31.728 27.529 31.752 ;
     RECT  27.529 31.728 27.713 31.944 ;
     RECT  27.713 31.92 27.953 31.944 ;
     RECT  27.953 31.92 28.225 32.52 ;
     RECT  29.221 0.096 29.269 0.12 ;
     RECT  29.269 0.096 29.363 0.216 ;
     RECT  24.304 2.256 29.408 8.52 ;
     RECT  28.225 32.496 29.408 32.52 ;
     RECT  29.269 34.224 29.408 34.248 ;
     RECT  24.304 35.28 29.408 35.304 ;
     RECT  24.304 47.184 29.408 48.168 ;
     RECT  24.304 50.832 29.408 51.48 ;
     RECT  24.304 53.328 29.408 53.352 ;
     RECT  24.304 56.208 29.408 56.232 ;
     RECT  24.304 76.752 29.408 76.776 ;
     RECT  29.408 2.148 29.512 105.852 ;
     RECT  29.363 0.192 29.555 0.216 ;
     RECT  29.512 2.148 29.653 105.582 ;
     RECT  29.653 2.016 29.704 105.582 ;
     RECT  29.704 2.016 29.801 8.52 ;
     RECT  29.704 34.224 31.061 35.304 ;
     RECT  31.061 34.752 31.427 35.304 ;
     RECT  31.561 36.48 32.581 36.504 ;
     RECT  32.677 37.632 32.929 37.656 ;
     RECT  32.929 37.632 34.189 38.376 ;
     RECT  34.189 37.632 34.477 38.808 ;
     RECT  29.801 2.256 34.765 8.52 ;
     RECT  34.765 2.016 34.808 8.52 ;
     RECT  31.427 35.28 34.808 35.304 ;
     RECT  34.477 37.632 34.808 39.624 ;
     RECT  29.704 47.184 34.808 48.168 ;
     RECT  29.704 50.832 34.808 51.48 ;
     RECT  29.704 53.328 34.808 53.352 ;
     RECT  29.704 56.208 34.808 56.232 ;
     RECT  29.704 76.752 34.808 76.776 ;
     RECT  34.808 2.016 34.849 105.852 ;
     RECT  34.849 2.148 34.912 105.852 ;
     RECT  34.912 2.256 35.104 105.582 ;
     RECT  34.981 0.096 35.153 0.12 ;
     RECT  35.104 38.784 35.165 39.624 ;
     RECT  35.153 0.096 35.201 0.216 ;
     RECT  35.201 0.192 35.237 0.216 ;
     RECT  35.165 38.784 36.325 38.808 ;
     RECT  36.421 1.104 36.515 1.128 ;
     RECT  35.104 2.256 37.037 8.52 ;
     RECT  38.177 0.576 38.261 0.6 ;
     RECT  38.761 1.104 38.845 1.128 ;
     RECT  38.941 42.528 39.125 42.552 ;
     RECT  36.097 41.04 39.205 41.064 ;
     RECT  37.037 2.256 39.836 8.328 ;
     RECT  39.836 1.68 39.923 8.328 ;
     RECT  40.021 0.576 40.057 0.6 ;
     RECT  40.057 0.432 40.069 0.6 ;
     RECT  39.923 2.148 40.208 8.328 ;
     RECT  35.104 35.28 40.208 35.304 ;
     RECT  39.308 41.136 40.208 41.592 ;
     RECT  40.129 43.824 40.208 43.848 ;
     RECT  35.104 47.184 40.208 48.168 ;
     RECT  35.104 50.832 40.208 51.48 ;
     RECT  35.104 53.328 40.208 53.352 ;
     RECT  35.104 56.208 40.208 56.232 ;
     RECT  35.104 76.752 40.208 76.776 ;
     RECT  40.069 0.432 40.307 0.696 ;
     RECT  40.208 2.148 40.312 105.852 ;
     RECT  40.312 2.148 40.504 105.582 ;
     RECT  40.453 0.144 40.643 0.168 ;
     RECT  40.504 43.824 40.673 44.712 ;
     RECT  40.504 2.148 40.988 8.328 ;
     RECT  40.988 1.68 41.075 8.328 ;
     RECT  40.673 44.688 41.105 44.712 ;
     RECT  40.504 41.04 41.861 41.592 ;
     RECT  41.075 2.256 42.14 8.328 ;
     RECT  42.14 1.68 42.227 8.328 ;
     RECT  42.685 1.104 42.803 1.128 ;
     RECT  41.861 41.568 43.093 41.592 ;
     RECT  43.093 41.04 43.193 41.592 ;
     RECT  43.193 41.568 43.907 41.592 ;
     RECT  40.504 50.832 44.161 51.48 ;
     RECT  44.405 0.096 44.489 0.12 ;
     RECT  40.504 46.752 45.169 48.168 ;
     RECT  44.161 50.304 45.349 51.48 ;
     RECT  40.504 53.328 45.349 53.352 ;
     RECT  42.227 2.256 45.608 8.328 ;
     RECT  40.504 35.28 45.608 35.304 ;
     RECT  45.169 46.752 45.608 49.032 ;
     RECT  45.349 50.304 45.608 53.352 ;
     RECT  40.504 56.208 45.608 56.232 ;
     RECT  40.504 76.752 45.608 76.776 ;
     RECT  44.953 1.104 45.635 1.128 ;
     RECT  45.608 2.148 45.712 105.852 ;
     RECT  45.712 2.256 45.904 105.582 ;
     RECT  45.745 0.096 46.045 0.12 ;
     RECT  45.904 50.304 47.041 52.104 ;
     RECT  45.904 53.328 47.041 53.352 ;
     RECT  47.041 50.304 47.117 53.352 ;
     RECT  45.904 2.256 47.333 8.328 ;
     RECT  47.117 50.304 48.305 52.872 ;
     RECT  48.305 50.304 48.493 51.96 ;
     RECT  48.957 0.096 49.061 0.12 ;
     RECT  47.333 2.64 49.205 8.328 ;
     RECT  45.904 76.752 49.525 76.776 ;
     RECT  49.157 53.04 49.609 53.064 ;
     RECT  45.904 46.752 49.633 48.168 ;
     RECT  49.633 46.512 49.669 48.168 ;
     RECT  49.205 3.552 49.781 8.328 ;
     RECT  49.525 76.56 49.889 76.776 ;
     RECT  49.849 53.568 49.955 53.592 ;
     RECT  48.493 50.304 49.993 51.912 ;
     RECT  49.669 46.512 50.101 48.504 ;
     RECT  49.993 49.488 50.101 51.912 ;
     RECT  50.101 46.512 50.245 51.912 ;
     RECT  49.781 3.936 50.785 8.328 ;
     RECT  50.785 3.024 50.929 8.328 ;
     RECT  50.849 1.728 51.008 1.752 ;
     RECT  50.929 2.784 51.008 8.328 ;
     RECT  45.904 35.28 51.008 35.304 ;
     RECT  50.245 46.512 51.008 52.488 ;
     RECT  45.904 56.208 51.008 56.232 ;
     RECT  49.889 76.56 51.008 76.584 ;
     RECT  51.008 1.728 51.112 105.852 ;
     RECT  51.112 1.728 51.304 105.582 ;
     RECT  51.304 46.608 51.365 51.912 ;
     RECT  51.304 1.728 51.473 8.28 ;
     RECT  51.473 1.728 52.403 2.28 ;
     RECT  51.473 3.264 52.441 8.28 ;
     RECT  52.549 0.096 52.697 0.12 ;
     RECT  51.365 46.752 53.171 51.912 ;
     RECT  52.403 1.728 53.377 1.8 ;
     RECT  52.441 2.88 53.377 8.28 ;
     RECT  53.377 1.728 53.381 8.28 ;
     RECT  53.171 50.112 53.525 51.912 ;
     RECT  51.304 76.56 53.557 76.584 ;
     RECT  53.557 76.368 53.603 76.584 ;
     RECT  53.381 3.552 53.669 8.28 ;
     RECT  53.171 46.752 53.705 48.984 ;
     RECT  53.413 104.544 53.845 104.568 ;
     RECT  53.749 107.856 53.987 107.88 ;
     RECT  53.845 104.544 54.083 105.48 ;
     RECT  53.708 54.048 54.172 54.072 ;
     RECT  53.701 91.2 54.236 91.224 ;
     RECT  54.236 91.2 54.277 91.512 ;
     RECT  54.277 90.72 54.323 91.512 ;
     RECT  54.083 104.544 54.323 104.568 ;
     RECT  54.133 107.136 54.353 107.16 ;
     RECT  53.305 63.072 54.419 63.096 ;
     RECT  54.323 90.72 54.419 91.224 ;
     RECT  52.945 31.68 54.476 31.704 ;
     RECT  54.476 31.68 54.563 31.8 ;
     RECT  51.304 35.28 54.563 35.304 ;
     RECT  53.381 1.728 54.925 2.52 ;
     RECT  53.603 76.368 54.965 76.392 ;
     RECT  54.419 91.2 54.995 91.224 ;
     RECT  54.925 1.104 55.043 2.52 ;
     RECT  55.043 1.728 55.105 2.52 ;
     RECT  53.669 3.6 55.105 8.28 ;
     RECT  54.805 0.096 55.109 0.12 ;
     RECT  54.949 79.776 55.237 79.8 ;
     RECT  55.237 79.44 55.283 79.8 ;
     RECT  55.205 76.896 55.289 76.92 ;
     RECT  55.105 1.728 55.361 8.28 ;
     RECT  55.361 1.728 55.541 7.944 ;
     RECT  55.957 0.528 56.149 0.552 ;
     RECT  56.149 0.096 56.405 0.552 ;
     RECT  55.541 1.776 56.408 7.944 ;
     RECT  54.563 31.68 56.408 31.704 ;
     RECT  53.705 46.752 56.408 48.168 ;
     RECT  53.525 50.304 56.408 51.912 ;
     RECT  55.283 79.44 56.408 79.464 ;
     RECT  56.408 1.776 56.512 105.852 ;
     RECT  56.512 1.776 56.689 105.582 ;
     RECT  56.689 1.728 56.704 105.582 ;
     RECT  56.533 0.576 56.909 0.6 ;
     RECT  56.704 1.728 57.089 7.992 ;
     RECT  57.089 3.312 57.107 7.992 ;
     RECT  57.107 3.408 57.125 7.992 ;
     RECT  57.125 7.104 57.233 7.992 ;
     RECT  57.125 3.408 57.269 5.976 ;
     RECT  57.089 1.728 57.377 2.184 ;
     RECT  57.233 7.44 57.493 7.992 ;
     RECT  57.269 3.408 57.701 5.64 ;
     RECT  57.701 3.408 57.881 5.544 ;
     RECT  57.493 7.44 57.881 7.464 ;
     RECT  57.881 3.648 58.097 5.544 ;
     RECT  58.021 8.544 58.105 8.568 ;
     RECT  58.097 3.648 58.205 4.728 ;
     RECT  56.704 31.68 58.385 31.704 ;
     RECT  58.172 2.256 58.405 2.28 ;
     RECT  58.405 1.728 58.529 2.28 ;
     RECT  58.529 2.256 58.643 2.28 ;
     RECT  56.704 46.752 58.921 48.168 ;
     RECT  58.921 46.752 59.101 48.216 ;
     RECT  58.777 9.12 59.569 9.144 ;
     RECT  59.569 9.12 59.833 9.624 ;
     RECT  59.833 9.6 59.893 9.624 ;
     RECT  59.893 9.6 59.897 9.72 ;
     RECT  56.704 50.304 60.085 51.912 ;
     RECT  59.897 9.696 60.109 9.72 ;
     RECT  58.597 31.872 60.131 31.896 ;
     RECT  60.109 9.696 60.193 10.056 ;
     RECT  60.193 9.696 60.707 9.72 ;
     RECT  60.757 10.848 61.237 10.872 ;
     RECT  61.237 10.848 61.372 11.448 ;
     RECT  59.101 46.752 61.513 48.36 ;
     RECT  61.372 10.848 61.573 11.496 ;
     RECT  61.573 0.144 61.669 0.168 ;
     RECT  61.573 10.848 61.669 11.544 ;
     RECT  58.205 3.84 61.808 4.728 ;
     RECT  61.669 10.848 61.808 11.592 ;
     RECT  61.513 46.752 61.808 48.744 ;
     RECT  60.085 50.016 61.808 51.912 ;
     RECT  56.704 79.44 61.808 79.464 ;
     RECT  61.669 0.144 61.859 0.216 ;
     RECT  61.808 2.148 61.912 105.852 ;
     RECT  61.859 0.192 62.051 0.216 ;
     RECT  61.912 2.418 62.104 105.582 ;
     RECT  62.104 46.752 63.565 49.032 ;
     RECT  62.104 50.016 63.565 51.912 ;
     RECT  62.104 11.424 64.909 11.448 ;
     RECT  64.997 14.832 65.185 14.856 ;
     RECT  65.185 14.832 65.485 15.432 ;
     RECT  65.485 15.408 66.481 15.432 ;
     RECT  62.104 3.84 67.208 4.728 ;
     RECT  66.481 15.408 67.208 15.72 ;
     RECT  63.565 46.752 67.208 51.912 ;
     RECT  62.104 79.44 67.208 79.464 ;
     RECT  67.208 2.148 67.285 105.852 ;
     RECT  67.285 1.728 67.312 105.852 ;
     RECT  67.312 1.728 67.385 105.582 ;
     RECT  67.385 2.418 67.504 105.582 ;
     RECT  67.477 0.096 67.619 0.12 ;
     RECT  67.504 15.408 67.717 15.48 ;
     RECT  67.504 46.752 68.969 51.912 ;
     RECT  68.969 49.536 69.077 51.912 ;
     RECT  67.717 15.408 69.265 15.432 ;
     RECT  68.821 18.816 69.325 18.84 ;
     RECT  69.325 18.816 69.443 18.888 ;
     RECT  69.077 50.016 70.604 51.912 ;
     RECT  70.604 49.92 70.691 51.912 ;
     RECT  72.373 0.576 72.421 0.6 ;
     RECT  69.443 18.816 72.421 18.84 ;
     RECT  72.421 0.432 72.469 0.696 ;
     RECT  72.205 22.224 72.469 22.248 ;
     RECT  67.504 3.84 72.608 4.728 ;
     RECT  72.421 18.816 72.608 18.984 ;
     RECT  72.469 22.224 72.608 23.064 ;
     RECT  68.969 46.752 72.608 48.168 ;
     RECT  70.691 50.016 72.608 51.912 ;
     RECT  67.504 79.44 72.608 79.464 ;
     RECT  72.469 0.144 72.659 0.696 ;
     RECT  72.608 2.148 72.712 105.852 ;
     RECT  72.659 0.144 72.851 0.168 ;
     RECT  72.712 2.418 72.904 105.582 ;
     RECT  72.904 22.224 73.045 23.4 ;
     RECT  73.045 22.8 73.235 23.4 ;
     RECT  72.904 2.832 73.571 2.856 ;
     RECT  73.235 23.376 73.897 23.4 ;
     RECT  74.041 11.952 74.147 11.976 ;
     RECT  73.897 23.376 74.341 23.976 ;
     RECT  72.904 50.016 75.409 51.912 ;
     RECT  75.409 50.016 75.773 52.152 ;
     RECT  75.773 50.016 75.809 52.056 ;
     RECT  75.788 6.24 75.875 6.264 ;
     RECT  72.904 3.84 76.309 4.728 ;
     RECT  76.309 3.408 76.451 4.728 ;
     RECT  74.341 23.952 76.741 23.976 ;
     RECT  76.892 0.528 76.979 0.552 ;
     RECT  76.451 3.84 78.008 4.728 ;
     RECT  76.741 23.952 78.008 24.504 ;
     RECT  72.904 46.752 78.008 48.168 ;
     RECT  75.809 50.016 78.008 51.912 ;
     RECT  72.904 79.44 78.008 79.464 ;
     RECT  78.008 2.148 78.112 105.852 ;
     RECT  78.085 0.096 78.277 0.12 ;
     RECT  78.112 2.418 78.304 105.582 ;
     RECT  78.277 0.096 78.419 0.216 ;
     RECT  78.419 0.192 78.467 0.216 ;
     RECT  78.304 24.288 78.515 24.504 ;
     RECT  78.515 24.48 78.733 24.504 ;
     RECT  78.304 27.936 78.905 28.536 ;
     RECT  78.304 2.832 79.283 2.856 ;
     RECT  78.304 50.016 79.769 51.96 ;
     RECT  79.793 0.096 79.877 0.12 ;
     RECT  78.905 28.512 80.064 28.536 ;
     RECT  80.064 28.512 80.195 28.584 ;
     RECT  78.304 3.84 80.909 4.728 ;
     RECT  80.909 3.408 80.993 4.728 ;
     RECT  81.061 30.24 81.155 30.264 ;
     RECT  80.195 28.512 81.361 28.536 ;
     RECT  81.452 13.056 81.539 13.08 ;
     RECT  82.028 2.256 82.115 2.28 ;
     RECT  82.421 31.92 83.005 31.944 ;
     RECT  83.213 0.096 83.221 0.12 ;
     RECT  83.005 31.92 83.221 32.52 ;
     RECT  83.221 0.096 83.297 0.312 ;
     RECT  80.993 3.84 83.408 4.728 ;
     RECT  81.644 30.72 83.408 30.744 ;
     RECT  83.221 31.92 83.408 33.048 ;
     RECT  78.304 46.752 83.408 48.168 ;
     RECT  79.769 50.016 83.408 51.912 ;
     RECT  78.304 79.44 83.408 79.464 ;
     RECT  83.297 0.192 83.459 0.312 ;
     RECT  83.408 2.148 83.512 105.852 ;
     RECT  83.459 0.192 83.603 0.216 ;
     RECT  83.512 2.148 83.704 105.582 ;
     RECT  83.704 32.496 83.765 32.568 ;
     RECT  83.708 2.016 83.795 2.04 ;
     RECT  83.765 32.496 84.565 32.52 ;
     RECT  83.704 34.224 84.989 34.248 ;
     RECT  86.021 0.096 86.105 0.12 ;
     RECT  86.629 0.576 86.716 0.6 ;
     RECT  85.057 34.8 87.049 34.824 ;
     RECT  88.645 38.976 88.693 39 ;
     RECT  83.704 3.84 88.808 4.728 ;
     RECT  86.749 37.056 88.808 37.08 ;
     RECT  88.693 38.784 88.808 39 ;
     RECT  83.704 46.752 88.808 48.168 ;
     RECT  83.704 50.016 88.808 51.912 ;
     RECT  83.704 79.44 88.808 79.464 ;
     RECT  88.808 2.148 88.912 105.852 ;
     RECT  88.645 0.144 88.931 0.168 ;
     RECT  88.912 2.418 89.104 105.582 ;
     RECT  89.077 0.096 89.219 0.12 ;
     RECT  89.104 2.88 90.101 4.728 ;
     RECT  89.104 38.784 90.101 39.48 ;
     RECT  90.101 38.784 91.955 38.808 ;
     RECT  91.717 41.04 93.913 41.064 ;
     RECT  93.913 41.04 94.018 41.112 ;
     RECT  90.101 3.84 94.208 4.728 ;
     RECT  94.018 41.04 94.208 41.16 ;
     RECT  93.049 44.16 94.208 44.184 ;
     RECT  89.104 46.752 94.208 48.168 ;
     RECT  89.104 50.016 94.208 51.912 ;
     RECT  89.104 79.44 94.208 79.464 ;
     RECT  94.069 0.096 94.211 0.12 ;
     RECT  94.208 2.148 94.312 105.852 ;
     RECT  94.312 2.148 94.504 105.582 ;
     RECT  94.504 2.148 94.517 4.728 ;
     RECT  94.517 2.016 94.601 4.728 ;
     RECT  94.504 23.808 94.643 23.976 ;
     RECT  94.504 27.888 94.643 28.056 ;
     RECT  94.504 38.592 94.643 38.808 ;
     RECT  94.357 0.144 94.673 0.168 ;
     RECT  94.504 7.92 94.673 8.04 ;
     RECT  94.504 11.952 94.673 12.072 ;
     RECT  94.504 15.84 94.673 16.008 ;
     RECT  94.504 19.872 94.673 20.088 ;
     RECT  94.643 23.904 94.673 23.976 ;
     RECT  94.643 27.888 94.673 27.96 ;
     RECT  94.504 30.72 94.673 31.944 ;
     RECT  94.504 34.752 94.673 36.024 ;
     RECT  94.504 39.792 94.673 39.816 ;
     RECT  94.601 2.832 94.684 4.728 ;
     RECT  94.504 6.768 94.684 6.888 ;
     RECT  94.504 10.8 94.684 10.92 ;
     RECT  94.504 14.736 94.684 14.856 ;
     RECT  94.504 18.768 94.684 18.888 ;
     RECT  94.504 22.704 94.684 22.824 ;
     RECT  94.504 26.736 94.684 26.856 ;
     RECT  94.673 30.72 94.684 30.84 ;
     RECT  94.673 34.752 94.684 34.872 ;
     RECT  94.643 38.688 94.684 38.808 ;
     RECT  94.673 8.016 94.709 8.04 ;
     RECT  94.684 10.8 94.709 10.824 ;
     RECT  94.673 36 94.709 36.024 ;
     RECT  94.684 38.688 94.709 38.712 ;
     RECT  94.673 23.952 94.739 23.976 ;
     RECT  94.684 26.736 94.739 26.76 ;
     RECT  94.673 27.936 94.739 27.96 ;
     RECT  94.684 30.72 94.739 30.744 ;
     RECT  94.504 41.04 95.033 41.592 ;
     RECT  95.033 41.568 95.747 41.592 ;
     RECT  95.852 42.144 96.131 42.168 ;
     RECT  94.504 44.16 96.253 44.184 ;
     RECT  94.504 46.752 96.721 48.168 ;
     RECT  96.469 42.768 96.877 42.792 ;
     RECT  96.721 46.752 96.901 48.216 ;
     RECT  96.253 44.16 96.937 44.472 ;
     RECT  96.937 44.16 97.237 45.048 ;
     RECT  96.901 46.752 97.333 48.744 ;
     RECT  97.333 46.176 97.427 48.744 ;
     RECT  94.504 50.016 98.305 51.912 ;
     RECT  98.305 50.016 98.389 52.488 ;
     RECT  97.237 44.16 98.579 45 ;
     RECT  97.427 46.752 98.581 48.744 ;
     RECT  98.389 50.016 98.581 51.912 ;
     RECT  98.581 46.752 98.665 51.912 ;
     RECT  98.725 11.664 98.732 14.808 ;
     RECT  98.579 44.16 98.732 44.712 ;
     RECT  98.732 11.664 98.737 15.48 ;
     RECT  98.732 17.616 98.773 17.64 ;
     RECT  98.732 43.248 98.773 44.712 ;
     RECT  94.504 79.44 98.917 79.464 ;
     RECT  98.521 80.928 99.241 80.952 ;
     RECT  98.809 82.08 99.241 82.104 ;
     RECT  98.809 63.696 99.253 63.72 ;
     RECT  99.212 65.088 99.253 65.112 ;
     RECT  98.809 66.432 99.253 67.32 ;
     RECT  99.241 80.928 99.253 82.104 ;
     RECT  99.445 0.576 99.493 0.6 ;
     RECT  94.684 3.84 99.608 4.728 ;
     RECT  98.725 6.864 99.608 6.888 ;
     RECT  98.693 10.224 99.608 10.248 ;
     RECT  98.737 11.664 99.608 16.008 ;
     RECT  98.773 17.616 99.608 18.168 ;
     RECT  98.737 21.504 99.608 21.528 ;
     RECT  98.629 22.752 99.608 22.776 ;
     RECT  98.593 25.392 99.608 25.896 ;
     RECT  98.737 27.072 99.608 27.096 ;
     RECT  98.737 29.76 99.608 29.784 ;
     RECT  98.737 32.496 99.608 32.52 ;
     RECT  98.737 34.368 99.608 34.392 ;
     RECT  98.737 37.632 99.608 37.656 ;
     RECT  98.737 40.416 99.608 40.44 ;
     RECT  98.773 42.72 99.608 44.712 ;
     RECT  98.665 46.128 99.608 51.912 ;
     RECT  98.693 55.824 99.608 55.848 ;
     RECT  98.725 57.024 99.608 57.048 ;
     RECT  98.809 59.28 99.608 59.304 ;
     RECT  99.253 63.072 99.608 67.32 ;
     RECT  99.349 75.216 99.608 75.24 ;
     RECT  98.809 77.04 99.608 77.064 ;
     RECT  98.917 79.248 99.608 79.464 ;
     RECT  99.253 80.784 99.608 82.104 ;
     RECT  99.385 85.392 99.608 85.416 ;
     RECT  99.241 89.472 99.608 89.496 ;
     RECT  98.809 93.312 99.608 93.336 ;
     RECT  99.241 96.576 99.608 96.6 ;
     RECT  99.608 2.148 99.712 105.852 ;
     RECT  99.493 0.432 99.731 0.696 ;
     RECT  99.712 2.418 99.904 105.582 ;
     RECT  99.904 79.248 99.965 79.416 ;
     RECT  99.904 21.12 100.001 21.528 ;
     RECT  99.904 33.552 100.001 34.92 ;
     RECT  99.904 38.736 100.019 41.688 ;
     RECT  99.904 75.216 100.019 75.912 ;
     RECT  99.904 84.768 100.019 87.96 ;
     RECT  99.904 89.472 100.019 91.368 ;
     RECT  100.019 90.624 100.037 91.368 ;
     RECT  99.904 15.36 100.06 16.008 ;
     RECT  100.019 75.888 100.06 75.912 ;
     RECT  100.019 41.184 100.073 41.688 ;
     RECT  99.904 71.28 100.073 71.4 ;
     RECT  99.904 22.752 100.08 25.752 ;
     RECT  99.904 46.032 100.115 54.648 ;
     RECT  100.019 86.064 100.145 87.96 ;
     RECT  99.877 0.144 100.163 0.168 ;
     RECT  100.115 46.08 100.259 54.648 ;
     RECT  99.904 64.368 100.433 64.392 ;
     RECT  99.904 61.008 100.613 61.752 ;
     RECT  99.904 95.76 100.643 97.512 ;
     RECT  99.904 67.296 100.649 67.704 ;
     RECT  99.904 82.656 100.649 83.16 ;
     RECT  100.643 96.864 100.787 97.512 ;
     RECT  99.904 29.712 100.826 29.784 ;
     RECT  99.904 19.152 100.828 19.944 ;
     RECT  100.787 96.864 100.829 96.936 ;
     RECT  100.08 25.152 100.835 25.752 ;
     RECT  99.904 14.064 100.897 14.088 ;
     RECT  100.828 19.92 100.897 19.944 ;
     RECT  100.001 21.12 100.897 21.144 ;
     RECT  99.904 59.28 100.897 59.304 ;
     RECT  100.259 46.752 100.901 54.648 ;
     RECT  100.897 55.824 100.933 55.848 ;
     RECT  99.904 57.024 100.933 57.048 ;
     RECT  100.001 33.552 100.937 33.576 ;
     RECT  99.904 74.064 100.94 74.088 ;
     RECT  99.904 99.408 100.94 99.432 ;
     RECT  100.933 55.824 100.969 57.048 ;
     RECT  100.06 15.984 100.973 16.008 ;
     RECT  100.001 34.896 100.973 34.92 ;
     RECT  100.073 41.472 100.973 41.688 ;
     RECT  100.94 99.408 100.981 100.2 ;
     RECT  100.897 19.92 101.009 21.144 ;
     RECT  100.08 22.752 101.009 23.592 ;
     RECT  99.904 31.248 101.009 31.272 ;
     RECT  100.897 66.144 101.009 66.552 ;
     RECT  99.904 77.04 101.009 77.064 ;
     RECT  101.009 22.752 101.02 22.776 ;
     RECT  100.94 74.064 101.027 74.808 ;
     RECT  100.981 99.168 101.027 100.2 ;
     RECT  100.897 59.28 101.036 59.88 ;
     RECT  100.613 61.008 101.036 61.032 ;
     RECT  100.835 25.728 101.041 25.752 ;
     RECT  101.041 25.728 101.081 25.992 ;
     RECT  100.901 51.36 101.081 54.648 ;
     RECT  100.037 91.2 101.117 91.224 ;
     RECT  101.036 59.28 101.123 61.032 ;
     RECT  100.019 89.472 101.149 89.496 ;
     RECT  101.009 20.688 101.173 21.144 ;
     RECT  100.145 86.688 101.185 87.96 ;
     RECT  101.081 25.92 101.219 25.992 ;
     RECT  100.897 72.96 101.221 72.984 ;
     RECT  101.027 74.064 101.221 74.088 ;
     RECT  101.221 72.96 101.267 74.088 ;
     RECT  101.185 86.448 101.297 87.96 ;
     RECT  101.267 72.96 101.308 73.512 ;
     RECT  101.123 59.28 101.333 59.88 ;
     RECT  100.649 67.68 101.365 67.704 ;
     RECT  99.904 68.688 101.365 68.712 ;
     RECT  101.365 67.68 101.405 68.712 ;
     RECT  101.149 89.472 101.405 90.456 ;
     RECT  101.149 45.552 101.411 45.576 ;
     RECT  100.969 55.824 101.437 57.576 ;
     RECT  100.826 29.712 101.473 29.736 ;
     RECT  101.333 59.28 101.477 59.448 ;
     RECT  99.904 92.544 101.509 93.336 ;
     RECT  101.219 25.968 101.513 25.992 ;
     RECT  101.257 78.096 101.513 78.12 ;
     RECT  101.221 75.792 101.585 75.816 ;
     RECT  100.901 46.752 101.603 50.328 ;
     RECT  100.969 37.008 101.605 37.032 ;
     RECT  101.077 38.736 101.605 38.76 ;
     RECT  101.473 29.088 101.651 29.736 ;
     RECT  101.564 34.032 101.651 34.056 ;
     RECT  99.904 44.16 101.651 44.184 ;
     RECT  101.297 87.744 101.653 87.96 ;
     RECT  100.829 96.912 101.693 96.936 ;
     RECT  101.405 67.68 101.701 68.376 ;
     RECT  100.073 71.28 101.701 71.304 ;
     RECT  100.643 95.76 101.761 95.784 ;
     RECT  101.437 55.824 101.765 58.152 ;
     RECT  100.969 63.36 101.797 63.384 ;
     RECT  101.477 59.424 101.843 59.448 ;
     RECT  101.701 67.248 101.843 68.376 ;
     RECT  101.761 94.8 101.852 95.784 ;
     RECT  101.852 94.8 101.939 96.744 ;
     RECT  101.516 2.832 101.977 2.856 ;
     RECT  99.904 3.84 101.977 4.728 ;
     RECT  101.405 90.432 101.987 90.456 ;
     RECT  101.939 94.8 101.987 96.168 ;
     RECT  101.027 99.168 101.987 100.152 ;
     RECT  99.904 9.792 102.013 9.816 ;
     RECT  99.965 79.392 102.013 79.416 ;
     RECT  101.701 71.28 102.044 71.448 ;
     RECT  102.044 71.28 102.077 71.592 ;
     RECT  102.013 9.792 102.085 10.776 ;
     RECT  101.797 63.36 102.085 64.344 ;
     RECT  102.077 70.656 102.085 71.592 ;
     RECT  101.308 72.96 102.085 72.984 ;
     RECT  102.085 9.792 102.121 11.4 ;
     RECT  100.897 13.584 102.131 14.088 ;
     RECT  102.044 18.096 102.131 18.12 ;
     RECT  101.173 20.688 102.131 21.624 ;
     RECT  100.649 83.136 102.133 83.16 ;
     RECT  101.297 86.448 102.157 86.472 ;
     RECT  101.009 66.144 102.161 66.168 ;
     RECT  102.085 70.656 102.161 72.984 ;
     RECT  100.969 104.256 102.161 104.28 ;
     RECT  100.969 105.456 102.161 105.48 ;
     RECT  102.121 9.6 102.169 11.4 ;
     RECT  102.037 0.096 102.179 0.12 ;
     RECT  102.169 9.6 102.179 10.776 ;
     RECT  100.973 41.472 102.181 41.496 ;
     RECT  101.605 37.008 102.197 38.76 ;
     RECT  102.133 83.136 102.236 83.208 ;
     RECT  101.509 84.288 102.236 84.312 ;
     RECT  102.157 85.488 102.269 86.472 ;
     RECT  102.236 83.136 102.323 84.312 ;
     RECT  102.323 83.136 102.325 83.208 ;
     RECT  101.651 29.088 102.337 29.112 ;
     RECT  101.765 55.824 102.337 57 ;
     RECT  102.013 79.392 102.337 79.704 ;
     RECT  102.325 82.656 102.337 83.208 ;
     RECT  102.181 41.472 102.37 42.216 ;
     RECT  101.977 2.832 102.371 4.728 ;
     RECT  102.037 76.368 102.371 76.392 ;
     RECT  102.337 78.672 102.371 79.704 ;
     RECT  102.337 82.608 102.371 83.208 ;
     RECT  102.371 79.68 102.373 79.704 ;
     RECT  101.509 92.016 102.377 93.336 ;
     RECT  102.197 37.728 102.405 38.76 ;
     RECT  101.461 103.2 102.409 103.224 ;
     RECT  101.077 40.176 102.413 40.2 ;
     RECT  101.765 58.128 102.413 58.152 ;
     RECT  102.37 41.424 102.445 42.216 ;
     RECT  102.085 62.736 102.469 64.344 ;
     RECT  101.653 87.744 102.481 88.056 ;
     RECT  102.371 78.672 102.521 78.696 ;
     RECT  102.371 82.608 102.521 82.68 ;
     RECT  102.469 62.592 102.556 64.344 ;
     RECT  102.337 55.728 102.557 57 ;
     RECT  102.556 63.072 102.557 64.344 ;
     RECT  102.409 103.2 102.557 103.8 ;
     RECT  102.157 30.48 102.565 30.504 ;
     RECT  101.077 31.872 102.565 31.896 ;
     RECT  101.473 8.016 102.589 8.04 ;
     RECT  102.373 26.736 102.589 26.76 ;
     RECT  102.552 35.904 102.589 35.928 ;
     RECT  102.085 44.976 102.589 45 ;
     RECT  102.373 66.192 102.589 66.216 ;
     RECT  102.377 92.016 102.589 92.04 ;
     RECT  102.179 9.6 102.593 10.392 ;
     RECT  102.445 41.424 102.593 42.744 ;
     RECT  102.557 63.072 102.593 64.248 ;
     RECT  102.377 93.312 102.593 93.336 ;
     RECT  102.589 23.616 102.625 23.64 ;
     RECT  102.565 30.48 102.629 31.896 ;
     RECT  102.405 38.736 102.629 38.76 ;
     RECT  102.593 41.424 102.629 42.216 ;
     RECT  102.373 79.68 102.629 80.952 ;
     RECT  102.323 84.288 102.629 84.312 ;
     RECT  102.589 90.528 102.629 92.04 ;
     RECT  101.987 94.8 102.629 95.784 ;
     RECT  102.629 30.48 102.652 31.368 ;
     RECT  102.589 35.328 102.659 35.928 ;
     RECT  102.589 26.736 102.673 27.384 ;
     RECT  102.625 22.656 102.733 23.64 ;
     RECT  101.603 49.056 102.733 50.328 ;
     RECT  101.603 46.752 102.773 48.024 ;
     RECT  102.733 49.008 102.773 50.328 ;
     RECT  102.161 72.288 102.773 72.984 ;
     RECT  101.987 99.168 102.773 99.192 ;
     RECT  102.733 22.032 102.845 23.64 ;
     RECT  102.337 28.464 102.877 29.112 ;
     RECT  102.652 30.48 102.877 30.504 ;
     RECT  102.521 82.656 102.881 82.68 ;
     RECT  102.409 102 102.913 102.024 ;
     RECT  102.877 28.464 102.917 30.504 ;
     RECT  102.773 49.008 102.917 49.08 ;
     RECT  101.081 51.36 102.949 54.12 ;
     RECT  102.917 49.008 102.989 49.032 ;
     RECT  102.845 22.032 103.025 22.824 ;
     RECT  102.589 44.976 103.025 45.432 ;
     RECT  102.949 51.36 103.025 54.744 ;
     RECT  101.123 61.008 103.025 61.032 ;
     RECT  102.913 102 103.069 102.648 ;
     RECT  102.901 1.728 103.132 1.752 ;
     RECT  103.132 1.68 103.133 1.752 ;
     RECT  102.481 87.744 103.133 88.536 ;
     RECT  102.949 6.24 103.139 6.264 ;
     RECT  102.629 79.68 103.205 80.472 ;
     RECT  102.917 29.664 103.241 30.504 ;
     RECT  102.161 70.656 103.244 70.68 ;
     RECT  103.069 102 103.277 102.6 ;
     RECT  101.843 68.064 103.285 68.376 ;
     RECT  102.589 59.184 103.292 59.208 ;
     RECT  102.481 76.896 103.309 76.92 ;
     RECT  103.133 87.744 103.313 87.768 ;
     RECT  103.244 69.984 103.331 71.304 ;
     RECT  103.292 59.184 103.333 59.448 ;
     RECT  102.557 103.728 103.345 103.8 ;
     RECT  103.333 58.656 103.379 59.448 ;
     RECT  102.405 37.728 103.421 37.752 ;
     RECT  103.025 51.888 103.421 54.744 ;
     RECT  103.165 86.64 103.421 86.664 ;
     RECT  102.131 13.584 103.457 13.608 ;
     RECT  103.025 22.032 103.457 22.776 ;
     RECT  102.659 35.328 103.457 35.352 ;
     RECT  102.629 90.528 103.457 91.464 ;
     RECT  103.421 52.944 103.475 54.744 ;
     RECT  102.131 20.688 103.493 20.712 ;
     RECT  103.331 70.512 103.493 70.872 ;
     RECT  103.309 76.896 103.493 76.968 ;
     RECT  102.593 63.072 103.525 63.096 ;
     RECT  103.345 103.728 103.525 104.28 ;
     RECT  103.381 105.408 103.525 105.432 ;
     RECT  103.277 102 103.529 102.024 ;
     RECT  102.373 33.552 103.532 33.576 ;
     RECT  102.773 46.752 103.565 46.776 ;
     RECT  102.557 56.304 103.571 57 ;
     RECT  103.525 62.544 103.571 63.096 ;
     RECT  103.571 56.304 103.573 56.952 ;
     RECT  102.593 64.224 103.601 64.248 ;
     RECT  103.532 33.552 103.619 34.344 ;
     RECT  103.525 103.728 103.619 105.432 ;
     RECT  102.589 66.192 103.628 66.792 ;
     RECT  103.285 68.064 103.628 68.952 ;
     RECT  103.571 62.544 103.637 62.952 ;
     RECT  102.593 10.368 103.673 10.392 ;
     RECT  102.121 16.272 103.673 16.296 ;
     RECT  102.373 24.624 103.673 24.648 ;
     RECT  102.917 28.464 103.673 28.488 ;
     RECT  103.241 30.48 103.673 30.504 ;
     RECT  103.025 45.408 103.673 45.432 ;
     RECT  103.475 52.992 103.673 54.744 ;
     RECT  103.573 55.872 103.673 56.952 ;
     RECT  102.589 74.592 103.673 74.616 ;
     RECT  103.205 80.352 103.673 80.472 ;
     RECT  103.676 96.288 103.697 96.312 ;
     RECT  103.619 103.728 103.709 104.328 ;
     RECT  103.619 105.408 103.709 105.432 ;
     RECT  103.628 66.192 103.715 68.952 ;
     RECT  103.697 95.664 103.717 96.312 ;
     RECT  103.715 68.064 103.745 68.952 ;
     RECT  103.673 55.872 103.763 56.424 ;
     RECT  103.717 95.664 103.763 96.936 ;
     RECT  103.619 33.552 103.781 33.576 ;
     RECT  103.637 62.544 103.781 62.568 ;
     RECT  103.457 90.528 103.781 90.552 ;
     RECT  103.709 104.256 103.781 104.328 ;
     RECT  103.133 1.68 103.813 1.704 ;
     RECT  103.741 19.392 103.825 19.416 ;
     RECT  102.773 50.304 103.853 50.328 ;
     RECT  103.421 51.888 103.853 51.912 ;
     RECT  103.673 53.328 103.853 54.12 ;
     RECT  103.745 68.064 103.853 68.088 ;
     RECT  103.673 80.352 103.853 80.376 ;
     RECT  103.715 66.192 103.889 66.312 ;
     RECT  103.493 70.512 103.889 70.536 ;
     RECT  103.813 1.152 103.925 1.704 ;
     RECT  102.773 72.288 103.961 72.312 ;
     RECT  103.763 95.664 103.961 95.688 ;
     RECT  102.371 3.312 103.993 4.728 ;
     RECT  103.813 60.816 104.029 60.888 ;
     RECT  104.029 60.816 104.053 60.984 ;
     RECT  102.629 41.424 104.204 41.448 ;
     RECT  102.589 7.44 104.317 8.04 ;
     RECT  104.317 6.864 104.348 8.04 ;
     RECT  103.925 1.68 104.569 1.704 ;
     RECT  103.993 2.784 104.569 4.728 ;
     RECT  104.569 1.68 104.857 4.728 ;
     RECT  104.348 6.24 104.857 8.04 ;
     RECT  104.857 1.68 104.893 8.04 ;
     RECT  104.893 1.104 105.008 8.04 ;
     RECT  103.489 18.24 105.008 18.264 ;
     RECT  103.457 22.032 105.008 22.056 ;
     RECT  102.673 26.736 105.008 26.76 ;
     RECT  104.204 41.184 105.008 41.448 ;
     RECT  104.065 42.624 105.008 42.648 ;
     RECT  103.853 53.328 105.008 54.024 ;
     RECT  103.763 56.4 105.008 56.424 ;
     RECT  103.379 58.656 105.008 58.68 ;
     RECT  104.053 60.768 105.008 60.984 ;
     RECT  103.493 76.896 105.008 76.92 ;
     RECT  102.269 85.488 105.008 85.512 ;
     RECT  103.763 96.912 105.008 96.936 ;
     RECT  103.781 104.304 105.008 104.328 ;
     RECT  105.008 1.104 105.011 105.852 ;
     RECT  105.011 2.016 105.112 105.852 ;
     RECT  105.145 0.528 105.157 0.552 ;
     RECT  105.112 2.016 105.304 105.768 ;
     RECT  105.157 0.096 105.365 0.552 ;
     RECT  105.304 2.016 105.395 8.04 ;
     RECT  105.395 2.592 105.587 8.04 ;
     RECT  105.365 0.528 105.779 0.552 ;
     RECT  105.304 61.248 106.369 62.232 ;
     RECT  105.304 63.552 106.369 63.576 ;
     RECT  105.304 21.36 106.513 21.96 ;
     RECT  105.304 32.88 106.513 36.504 ;
     RECT  105.304 40.464 106.513 41.064 ;
     RECT  105.304 42.528 106.513 42.552 ;
     RECT  106.369 61.248 106.513 63.576 ;
     RECT  105.304 68.64 106.513 68.664 ;
     RECT  105.304 103.824 106.513 104.232 ;
     RECT  105.304 105.744 106.513 105.768 ;
     RECT  105.587 2.784 106.549 8.04 ;
     RECT  105.304 9.456 106.549 13.416 ;
     RECT  105.304 14.544 106.549 17.976 ;
     RECT  105.304 19.056 106.549 19.848 ;
     RECT  106.513 21.36 106.549 22.152 ;
     RECT  105.304 23.424 106.549 25.176 ;
     RECT  105.304 26.256 106.549 26.28 ;
     RECT  105.304 27.6 106.549 31.224 ;
     RECT  106.513 32.304 106.549 36.504 ;
     RECT  105.304 37.824 106.549 38.76 ;
     RECT  106.513 40.464 106.549 42.552 ;
     RECT  105.304 43.872 106.549 44.808 ;
     RECT  105.304 46.32 106.549 54.264 ;
     RECT  105.304 55.968 106.549 57.48 ;
     RECT  105.304 58.8 106.549 59.784 ;
     RECT  106.513 60.864 106.549 63.576 ;
     RECT  105.304 64.656 106.549 66.936 ;
     RECT  106.513 68.64 106.549 68.856 ;
     RECT  105.304 70.176 106.549 72.072 ;
     RECT  105.304 73.2 106.549 84.936 ;
     RECT  105.304 86.256 106.549 87 ;
     RECT  105.304 88.128 106.549 88.728 ;
     RECT  105.304 90.192 106.549 90.984 ;
     RECT  105.304 92.112 106.549 100.824 ;
     RECT  105.304 102.144 106.549 102.36 ;
     RECT  106.513 103.824 106.549 105.768 ;
     RECT  106.549 2.784 106.585 19.848 ;
     RECT  106.549 20.976 106.585 57.48 ;
     RECT  106.549 58.8 106.585 68.856 ;
     RECT  106.549 70.176 106.585 105.768 ;
     RECT  106.585 2.784 107.125 105.768 ;
     RECT  107.125 2.256 107.964 105.768 ;
    LAYER M5 ;
     RECT  2.256 0.016 105.768 0.563 ;
     RECT  2.256 0.563 105.576 1.763 ;
     RECT  2.256 1.763 54.504 1.811 ;
     RECT  55.584 1.763 105.576 1.811 ;
     RECT  53.52 1.811 54.504 2.195 ;
     RECT  2.256 1.811 52.392 2.243 ;
     RECT  53.52 2.195 54.312 2.243 ;
     RECT  2.256 2.243 52.248 2.291 ;
     RECT  53.52 2.243 53.544 2.291 ;
     RECT  55.776 1.811 105.576 2.627 ;
     RECT  55.776 2.627 105.312 3.059 ;
     RECT  56.4 3.059 105.312 5.269 ;
     RECT  2.256 2.291 51.312 6.277 ;
     RECT  2.256 6.277 51.912 6.661 ;
     RECT  54.288 6.133 54.312 6.661 ;
     RECT  2.208 6.661 51.912 6.841 ;
     RECT  2.256 6.841 51.912 6.899 ;
     RECT  2.4 6.899 51.912 6.947 ;
     RECT  54.288 6.661 54.696 7.235 ;
     RECT  55.728 5.269 105.312 7.427 ;
     RECT  54.528 7.235 54.696 7.619 ;
     RECT  56.4 7.427 105.312 8.003 ;
     RECT  2.4 6.947 51.312 8.101 ;
     RECT  2.304 8.101 51.312 8.291 ;
     RECT  58.032 8.003 105.312 8.579 ;
     RECT  2.4 8.291 51.312 8.627 ;
     RECT  58.8 8.579 105.312 9.155 ;
     RECT  59.952 9.155 105.312 9.731 ;
     RECT  60.144 9.731 105.312 10.067 ;
     RECT  4.704 8.627 51.312 10.307 ;
     RECT  5.232 10.307 51.312 10.451 ;
     RECT  60.864 10.067 105.312 10.883 ;
     RECT  5.232 10.451 5.256 11.365 ;
     RECT  6.384 10.451 51.312 11.459 ;
     RECT  61.248 10.883 105.312 11.459 ;
     RECT  61.44 11.459 62.112 11.507 ;
     RECT  61.584 11.507 62.112 11.555 ;
     RECT  61.68 11.555 62.112 11.603 ;
     RECT  7.104 11.459 51.312 12.083 ;
     RECT  4.416 11.365 5.256 12.517 ;
     RECT  7.104 12.083 8.52 13.043 ;
     RECT  7.68 13.043 8.52 13.619 ;
     RECT  7.8 13.619 8.52 13.715 ;
     RECT  4.32 12.517 5.256 14.243 ;
     RECT  9.792 12.083 51.312 14.867 ;
     RECT  65.04 11.459 105.312 14.867 ;
     RECT  7.8 13.715 8.112 15.301 ;
     RECT  10.176 14.867 51.312 15.443 ;
     RECT  65.232 14.867 105.312 15.443 ;
     RECT  11.136 15.443 11.16 15.491 ;
     RECT  13.104 15.443 51.312 15.491 ;
     RECT  66.576 15.443 67.704 15.491 ;
     RECT  66.576 15.491 67.512 15.731 ;
     RECT  7.008 15.301 8.112 15.925 ;
     RECT  4.416 14.243 5.256 17.123 ;
     RECT  6.912 15.925 8.112 17.315 ;
     RECT  13.2 15.491 51.312 18.851 ;
     RECT  68.832 15.443 105.312 18.851 ;
     RECT  69.408 18.851 69.432 18.899 ;
     RECT  4.416 17.123 5.208 19.333 ;
     RECT  4.368 19.333 5.208 19.909 ;
     RECT  4.368 19.909 5.688 20.867 ;
     RECT  4.416 20.867 5.688 21.971 ;
     RECT  17.184 18.851 51.312 22.259 ;
     RECT  72.24 18.851 105.312 22.259 ;
     RECT  17.76 22.259 51.312 22.835 ;
     RECT  72.48 22.259 105.312 23.075 ;
     RECT  18.144 22.835 51.312 23.411 ;
     RECT  72.6 23.075 105.312 23.411 ;
     RECT  18.6 23.411 51.312 23.987 ;
     RECT  73.92 23.411 105.312 23.987 ;
     RECT  18.6 23.987 19.656 24.035 ;
     RECT  18.6 24.035 19.032 24.131 ;
     RECT  22.128 23.987 51.312 24.515 ;
     RECT  76.8 23.987 105.312 24.515 ;
     RECT  4.416 21.971 5.4 25.045 ;
     RECT  2.4 8.627 2.712 25.813 ;
     RECT  4.416 25.045 5.736 25.909 ;
     RECT  2.304 25.813 2.712 26.003 ;
     RECT  4.416 25.909 6.264 26.243 ;
     RECT  2.4 26.003 2.712 26.389 ;
     RECT  2.4 26.389 3.336 26.819 ;
     RECT  23.424 24.515 51.312 27.971 ;
     RECT  4.416 26.243 4.872 28.453 ;
     RECT  7.8 17.315 8.112 28.453 ;
     RECT  78 24.515 105.312 28.547 ;
     RECT  24 27.971 51.312 28.595 ;
     RECT  80.16 28.547 105.312 28.595 ;
     RECT  24 28.595 24.408 28.643 ;
     RECT  7.8 28.453 8.232 29.747 ;
     RECT  4.368 28.453 4.872 29.989 ;
     RECT  6.24 26.243 6.264 29.989 ;
     RECT  4.368 29.989 6.264 30.035 ;
     RECT  25.728 28.595 51.312 30.275 ;
     RECT  81.12 28.595 105.312 30.275 ;
     RECT  26.448 30.275 51.312 30.755 ;
     RECT  81.696 30.275 105.312 30.755 ;
     RECT  27.216 30.755 51.312 31.379 ;
     RECT  54.528 7.619 54.552 31.669 ;
     RECT  27.6 31.379 51.312 31.955 ;
     RECT  82.464 30.755 105.312 31.955 ;
     RECT  27.984 31.955 51.312 32.531 ;
     RECT  83.04 31.955 105.312 32.531 ;
     RECT  83.232 32.531 105.312 33.059 ;
     RECT  29.28 32.531 51.312 34.259 ;
     RECT  83.4 33.059 105.312 34.259 ;
     RECT  29.4 34.259 51.312 34.787 ;
     RECT  85.104 34.259 105.312 34.835 ;
     RECT  31.584 34.787 51.312 35.269 ;
     RECT  54.096 31.669 54.552 35.315 ;
     RECT  2.4 26.819 2.712 36.469 ;
     RECT  31.584 35.269 51.576 36.515 ;
     RECT  2.16 36.469 2.712 36.611 ;
     RECT  86.784 34.835 105.312 37.091 ;
     RECT  7.8 29.747 8.112 37.573 ;
     RECT  32.736 36.515 51.576 37.667 ;
     RECT  6.864 37.573 8.112 38.291 ;
     RECT  34.224 37.667 51.576 38.819 ;
     RECT  88.656 37.091 105.312 38.819 ;
     RECT  88.656 38.819 89.304 38.867 ;
     RECT  88.656 38.867 89.112 39.011 ;
     RECT  4.416 30.035 5.832 39.781 ;
     RECT  4.368 39.781 5.832 40.835 ;
     RECT  36.144 38.819 51.576 41.075 ;
     RECT  91.728 38.819 105.312 41.075 ;
     RECT  93.984 41.075 105.312 41.123 ;
     RECT  94.08 41.123 105.312 41.171 ;
     RECT  39.36 41.075 51.576 41.603 ;
     RECT  94.2 41.171 105.312 41.603 ;
     RECT  95.904 41.603 105.312 42.179 ;
     RECT  4.416 40.835 5.832 43.717 ;
     RECT  4.416 43.717 5.928 43.763 ;
     RECT  96.288 42.179 105.312 44.483 ;
     RECT  97.008 44.483 105.312 45.011 ;
     RECT  97.008 45.011 97.416 45.059 ;
     RECT  98.736 45.011 105.312 46.163 ;
     RECT  4.416 43.763 4.872 46.165 ;
     RECT  97.392 45.059 97.416 46.211 ;
     RECT  4.368 46.165 4.872 47.363 ;
     RECT  4.416 47.363 4.872 47.797 ;
     RECT  5.904 43.763 5.928 47.797 ;
     RECT  4.416 47.797 5.928 47.843 ;
     RECT  54.096 35.315 54.12 47.845 ;
     RECT  43.68 41.603 51.576 47.939 ;
     RECT  99.312 46.163 105.312 48.515 ;
     RECT  99.504 48.515 105.312 48.707 ;
     RECT  45.216 47.939 51.576 49.043 ;
     RECT  53.136 47.845 54.12 49.187 ;
     RECT  64.752 48.421 64.776 49.283 ;
     RECT  7.8 38.291 8.112 49.525 ;
     RECT  99.6 48.707 105.312 49.619 ;
     RECT  99.6 49.619 102.168 49.763 ;
     RECT  45.6 49.043 51.576 49.861 ;
     RECT  100.992 49.763 102.168 49.955 ;
     RECT  98.592 49.477 98.616 50.005 ;
     RECT  60.096 31.861 60.12 50.051 ;
     RECT  98.352 50.005 98.616 50.051 ;
     RECT  72.6 23.411 72.912 50.389 ;
     RECT  4.416 47.843 5.592 50.677 ;
     RECT  70.656 49.909 70.68 50.915 ;
     RECT  99.6 49.763 99.912 51.253 ;
     RECT  72.6 50.389 73.416 51.347 ;
     RECT  45.6 49.861 51.768 51.395 ;
     RECT  4.368 50.677 5.592 51.923 ;
     RECT  45.6 51.395 51.312 51.971 ;
     RECT  4.368 51.923 4.872 52.163 ;
     RECT  47.088 51.971 47.88 52.355 ;
     RECT  101.568 49.955 102.168 52.405 ;
     RECT  103.296 49.619 105.312 52.405 ;
     RECT  47.088 52.355 47.112 52.499 ;
     RECT  49.2 51.971 51.312 52.499 ;
     RECT  98.352 50.051 98.376 52.499 ;
     RECT  101.568 52.405 105.312 52.979 ;
     RECT  49.2 52.499 49.944 53.075 ;
     RECT  49.92 53.075 49.944 53.603 ;
     RECT  103.776 52.979 105.312 53.603 ;
     RECT  54.096 49.187 54.12 54.037 ;
     RECT  101.568 52.979 102.792 54.085 ;
     RECT  103.776 53.603 103.8 54.085 ;
     RECT  7.8 49.525 8.232 54.563 ;
     RECT  4.416 52.163 4.872 55.813 ;
     RECT  99.6 51.253 100.584 55.813 ;
     RECT  101.568 54.085 103.8 55.859 ;
     RECT  6.192 53.317 6.216 56.197 ;
     RECT  98.736 55.813 100.584 56.341 ;
     RECT  101.568 55.859 101.832 56.341 ;
     RECT  103.008 55.859 103.8 56.389 ;
     RECT  105 53.603 105.312 56.389 ;
     RECT  6.144 56.197 6.216 56.437 ;
     RECT  7.8 54.563 8.112 56.437 ;
     RECT  6.144 56.437 8.112 57.059 ;
     RECT  98.736 56.341 101.832 57.059 ;
     RECT  99.6 57.059 101.832 57.587 ;
     RECT  4.416 55.813 5.064 58.645 ;
     RECT  6.144 57.059 6.216 58.645 ;
     RECT  4.416 58.645 6.216 59.315 ;
     RECT  99.6 57.587 100.584 59.413 ;
     RECT  101.568 57.587 101.832 59.413 ;
     RECT  4.848 59.315 6.216 59.747 ;
     RECT  99.6 59.413 101.832 60.467 ;
     RECT  99.6 60.467 100.584 61.043 ;
     RECT  6.144 59.747 6.216 62.581 ;
     RECT  7.8 57.059 8.112 62.581 ;
     RECT  101.568 60.467 101.832 62.581 ;
     RECT  103.008 56.389 105.312 62.581 ;
     RECT  6.144 62.581 8.112 62.723 ;
     RECT  53.76 54.037 54.12 63.061 ;
     RECT  99.6 61.043 99.912 63.061 ;
     RECT  101.568 62.581 105.312 63.107 ;
     RECT  4.848 59.747 5.064 63.733 ;
     RECT  4.8 63.733 5.064 63.779 ;
     RECT  7.68 62.723 8.112 63.781 ;
     RECT  7.68 63.781 8.472 63.827 ;
     RECT  6.144 62.723 6.216 64.885 ;
     RECT  2.4 36.611 2.712 64.981 ;
     RECT  2.304 64.981 2.712 65.171 ;
     RECT  5.856 64.885 6.216 66.227 ;
     RECT  99.264 63.061 99.912 66.467 ;
     RECT  4.8 63.779 4.872 67.237 ;
     RECT  4.8 67.237 5.064 67.283 ;
     RECT  101.568 63.107 101.832 67.283 ;
     RECT  7.8 63.827 8.472 67.331 ;
     RECT  4.848 67.283 5.064 68.917 ;
     RECT  4.56 68.917 5.064 70.499 ;
     RECT  101.568 67.283 101.736 70.645 ;
     RECT  103.008 63.107 105.312 70.645 ;
     RECT  7.8 67.331 8.112 71.173 ;
     RECT  7.8 71.173 8.232 71.843 ;
     RECT  101.568 70.645 105.312 73.477 ;
     RECT  7.8 71.843 8.112 74.053 ;
     RECT  101.232 73.477 105.312 74.053 ;
     RECT  5.04 70.499 5.064 74.629 ;
     RECT  100.992 74.053 105.312 74.819 ;
     RECT  99.6 66.467 99.912 75.205 ;
     RECT  5.04 74.629 5.16 75.539 ;
     RECT  99.6 75.205 100.008 75.923 ;
     RECT  53.76 63.061 54.408 76.357 ;
     RECT  7.8 74.053 8.232 76.403 ;
     RECT  53.568 76.357 54.408 76.595 ;
     RECT  5.04 75.539 5.064 76.885 ;
     RECT  53.76 76.595 54.408 76.885 ;
     RECT  4.896 76.885 5.064 77.173 ;
     RECT  7.8 76.403 8.112 77.941 ;
     RECT  4.896 77.173 5.112 78.131 ;
     RECT  7.8 77.941 8.472 79.283 ;
     RECT  53.76 76.885 55.272 79.811 ;
     RECT  4.896 78.131 4.92 80.341 ;
     RECT  6.144 66.227 6.216 80.341 ;
     RECT  99.6 75.923 99.912 80.773 ;
     RECT  6.144 80.341 6.264 80.915 ;
     RECT  99.264 80.773 99.912 80.963 ;
     RECT  99.36 80.963 99.912 81.875 ;
     RECT  4.368 80.341 4.92 82.163 ;
     RECT  6.144 80.915 6.216 83.221 ;
     RECT  7.8 79.283 8.112 83.221 ;
     RECT  2.4 65.171 2.712 84.181 ;
     RECT  99.6 81.875 99.912 84.757 ;
     RECT  4.896 82.163 4.92 84.949 ;
     RECT  6.144 83.221 8.112 85.427 ;
     RECT  2.304 84.181 2.712 85.571 ;
     RECT  99.6 84.757 100.008 86.099 ;
     RECT  4.896 84.949 5.016 86.195 ;
     RECT  101.568 74.819 105.312 88.067 ;
     RECT  7.8 85.427 8.112 88.309 ;
     RECT  6.144 85.427 6.216 88.453 ;
     RECT  4.896 86.195 4.92 88.595 ;
     RECT  99.6 86.099 99.912 89.989 ;
     RECT  7.44 88.309 8.112 90.035 ;
     RECT  6.096 88.453 6.216 90.565 ;
     RECT  4.368 90.373 4.392 90.659 ;
     RECT  99.6 89.989 100.008 90.659 ;
     RECT  6.096 90.565 6.264 90.707 ;
     RECT  2.4 85.571 2.712 90.901 ;
     RECT  2.304 90.901 2.712 91.091 ;
     RECT  53.76 79.811 54.984 91.235 ;
     RECT  99.6 90.659 99.912 92.533 ;
     RECT  101.568 88.067 101.976 92.533 ;
     RECT  6.144 90.707 6.264 95.555 ;
     RECT  4.32 93.589 4.344 95.939 ;
     RECT  99.6 92.533 101.976 96.947 ;
     RECT  99.6 96.947 100.776 97.523 ;
     RECT  101.952 96.947 101.976 99.157 ;
     RECT  100.992 99.157 101.976 100.163 ;
     RECT  100.992 100.163 101.496 100.211 ;
     RECT  7.8 90.035 8.112 100.261 ;
     RECT  6.144 95.555 6.216 101.413 ;
     RECT  7.8 100.261 8.232 101.413 ;
     RECT  6.144 101.413 8.232 101.557 ;
     RECT  6.144 101.557 8.568 101.605 ;
     RECT  5.952 101.605 8.568 102.083 ;
     RECT  7.8 102.083 8.568 102.131 ;
     RECT  103.008 88.067 105.312 102.659 ;
     RECT  101.472 100.211 101.496 103.235 ;
     RECT  2.4 91.091 2.712 103.477 ;
     RECT  5.952 102.083 6.168 103.763 ;
     RECT  103.584 102.659 105.312 104.339 ;
     RECT  2.4 103.477 3.432 104.579 ;
     RECT  53.76 91.235 54.312 104.579 ;
     RECT  6.144 103.763 6.168 104.915 ;
     RECT  103.584 104.339 103.608 104.915 ;
     RECT  2.4 104.579 2.712 105.849 ;
     RECT  7.8 102.131 8.112 105.849 ;
     RECT  13.2 18.851 13.512 105.849 ;
     RECT  18.6 24.131 18.912 105.849 ;
     RECT  24 28.643 24.312 105.849 ;
     RECT  29.4 34.787 29.712 105.849 ;
     RECT  34.8 38.819 35.112 105.849 ;
     RECT  40.2 41.603 40.512 105.849 ;
     RECT  45.6 51.971 45.912 105.849 ;
     RECT  51 52.499 51.312 105.849 ;
     RECT  56.4 8.003 56.712 105.849 ;
     RECT  61.8 11.603 62.112 105.849 ;
     RECT  67.2 15.731 67.512 105.849 ;
     RECT  72.6 51.347 72.912 105.849 ;
     RECT  78 28.547 78.312 105.849 ;
     RECT  83.4 34.259 83.712 105.849 ;
     RECT  88.8 39.011 89.112 105.849 ;
     RECT  94.2 41.603 94.512 105.849 ;
     RECT  99.6 97.523 99.912 105.849 ;
     RECT  105 104.339 105.312 105.849 ;
     RECT  2.4 105.849 2.52 105.863 ;
     RECT  7.8 105.849 7.92 105.863 ;
     RECT  13.2 105.849 13.32 105.863 ;
     RECT  18.6 105.849 18.72 105.863 ;
     RECT  24 105.849 24.12 105.863 ;
     RECT  29.4 105.849 29.52 105.863 ;
     RECT  34.8 105.849 34.92 105.863 ;
     RECT  40.2 105.849 40.32 105.863 ;
     RECT  45.6 105.849 45.72 105.863 ;
     RECT  51 105.849 51.12 105.863 ;
     RECT  56.4 105.849 56.52 105.863 ;
     RECT  61.8 105.849 61.92 105.863 ;
     RECT  67.2 105.849 67.32 105.863 ;
     RECT  72.6 105.849 72.72 105.863 ;
     RECT  78 105.849 78.12 105.863 ;
     RECT  83.4 105.849 83.52 105.863 ;
     RECT  88.8 105.849 88.92 105.863 ;
     RECT  94.2 105.849 94.32 105.863 ;
     RECT  99.6 105.849 99.72 105.863 ;
     RECT  105 105.849 105.12 105.863 ;
     RECT  53.76 104.579 54.072 107.125 ;
     RECT  53.76 107.125 54.168 107.891 ;
     RECT  53.952 107.891 54.168 107.984 ;
  END
END ot_hbm_idx_vm_share2_leaf_r
END LIBRARY
